VERSION 5.7 ;
BUSBITCHARS "[]" ;
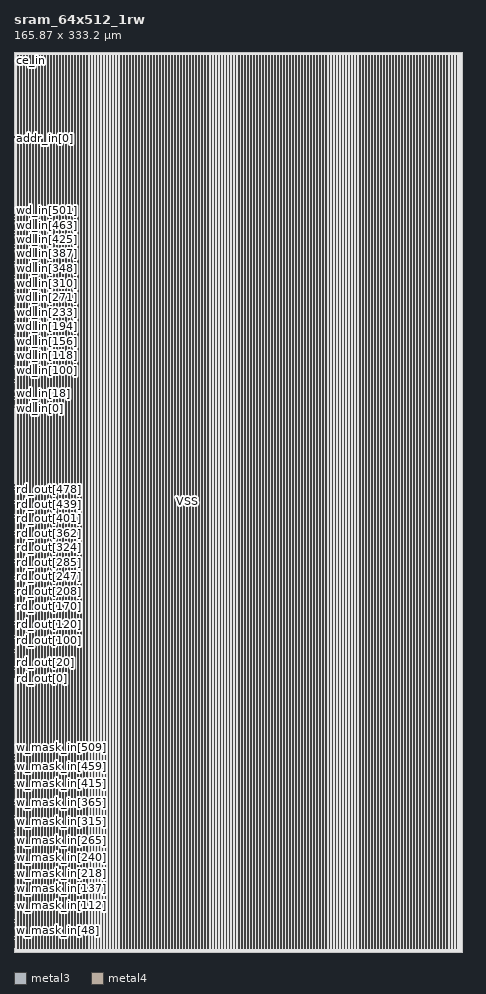
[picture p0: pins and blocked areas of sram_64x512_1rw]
MACRO sram_64x512_1rw
  FOREIGN sram_64x512_1rw 0 0 ;
  SYMMETRY X Y R90 ;
  SIZE 165.870 BY 333.200 ;
  CLASS BLOCK ;
  PIN w_mask_in[0]
    DIRECTION INPUT ;
    USE SIGNAL ;
    SHAPE ABUTMENT ;
    PORT
      LAYER metal3 ;
      RECT 0.000 1.365 0.070 1.435 ;
    END
  END w_mask_in[0]
  PIN w_mask_in[1]
    DIRECTION INPUT ;
    USE SIGNAL ;
    SHAPE ABUTMENT ;
    PORT
      LAYER metal3 ;
      RECT 0.000 1.505 0.070 1.575 ;
    END
  END w_mask_in[1]
  PIN w_mask_in[2]
    DIRECTION INPUT ;
    USE SIGNAL ;
    SHAPE ABUTMENT ;
    PORT
      LAYER metal3 ;
      RECT 0.000 1.645 0.070 1.715 ;
    END
  END w_mask_in[2]
  PIN w_mask_in[3]
    DIRECTION INPUT ;
    USE SIGNAL ;
    SHAPE ABUTMENT ;
    PORT
      LAYER metal3 ;
      RECT 0.000 1.785 0.070 1.855 ;
    END
  END w_mask_in[3]
  PIN w_mask_in[4]
    DIRECTION INPUT ;
    USE SIGNAL ;
    SHAPE ABUTMENT ;
    PORT
      LAYER metal3 ;
      RECT 0.000 1.925 0.070 1.995 ;
    END
  END w_mask_in[4]
  PIN w_mask_in[5]
    DIRECTION INPUT ;
    USE SIGNAL ;
    SHAPE ABUTMENT ;
    PORT
      LAYER metal3 ;
      RECT 0.000 2.065 0.070 2.135 ;
    END
  END w_mask_in[5]
  PIN w_mask_in[6]
    DIRECTION INPUT ;
    USE SIGNAL ;
    SHAPE ABUTMENT ;
    PORT
      LAYER metal3 ;
      RECT 0.000 2.205 0.070 2.275 ;
    END
  END w_mask_in[6]
  PIN w_mask_in[7]
    DIRECTION INPUT ;
    USE SIGNAL ;
    SHAPE ABUTMENT ;
    PORT
      LAYER metal3 ;
      RECT 0.000 2.345 0.070 2.415 ;
    END
  END w_mask_in[7]
  PIN w_mask_in[8]
    DIRECTION INPUT ;
    USE SIGNAL ;
    SHAPE ABUTMENT ;
    PORT
      LAYER metal3 ;
      RECT 0.000 2.485 0.070 2.555 ;
    END
  END w_mask_in[8]
  PIN w_mask_in[9]
    DIRECTION INPUT ;
    USE SIGNAL ;
    SHAPE ABUTMENT ;
    PORT
      LAYER metal3 ;
      RECT 0.000 2.625 0.070 2.695 ;
    END
  END w_mask_in[9]
  PIN w_mask_in[10]
    DIRECTION INPUT ;
    USE SIGNAL ;
    SHAPE ABUTMENT ;
    PORT
      LAYER metal3 ;
      RECT 0.000 2.765 0.070 2.835 ;
    END
  END w_mask_in[10]
  PIN w_mask_in[11]
    DIRECTION INPUT ;
    USE SIGNAL ;
    SHAPE ABUTMENT ;
    PORT
      LAYER metal3 ;
      RECT 0.000 2.905 0.070 2.975 ;
    END
  END w_mask_in[11]
  PIN w_mask_in[12]
    DIRECTION INPUT ;
    USE SIGNAL ;
    SHAPE ABUTMENT ;
    PORT
      LAYER metal3 ;
      RECT 0.000 3.045 0.070 3.115 ;
    END
  END w_mask_in[12]
  PIN w_mask_in[13]
    DIRECTION INPUT ;
    USE SIGNAL ;
    SHAPE ABUTMENT ;
    PORT
      LAYER metal3 ;
      RECT 0.000 3.185 0.070 3.255 ;
    END
  END w_mask_in[13]
  PIN w_mask_in[14]
    DIRECTION INPUT ;
    USE SIGNAL ;
    SHAPE ABUTMENT ;
    PORT
      LAYER metal3 ;
      RECT 0.000 3.325 0.070 3.395 ;
    END
  END w_mask_in[14]
  PIN w_mask_in[15]
    DIRECTION INPUT ;
    USE SIGNAL ;
    SHAPE ABUTMENT ;
    PORT
      LAYER metal3 ;
      RECT 0.000 3.465 0.070 3.535 ;
    END
  END w_mask_in[15]
  PIN w_mask_in[16]
    DIRECTION INPUT ;
    USE SIGNAL ;
    SHAPE ABUTMENT ;
    PORT
      LAYER metal3 ;
      RECT 0.000 3.605 0.070 3.675 ;
    END
  END w_mask_in[16]
  PIN w_mask_in[17]
    DIRECTION INPUT ;
    USE SIGNAL ;
    SHAPE ABUTMENT ;
    PORT
      LAYER metal3 ;
      RECT 0.000 3.745 0.070 3.815 ;
    END
  END w_mask_in[17]
  PIN w_mask_in[18]
    DIRECTION INPUT ;
    USE SIGNAL ;
    SHAPE ABUTMENT ;
    PORT
      LAYER metal3 ;
      RECT 0.000 3.885 0.070 3.955 ;
    END
  END w_mask_in[18]
  PIN w_mask_in[19]
    DIRECTION INPUT ;
    USE SIGNAL ;
    SHAPE ABUTMENT ;
    PORT
      LAYER metal3 ;
      RECT 0.000 4.025 0.070 4.095 ;
    END
  END w_mask_in[19]
  PIN w_mask_in[20]
    DIRECTION INPUT ;
    USE SIGNAL ;
    SHAPE ABUTMENT ;
    PORT
      LAYER metal3 ;
      RECT 0.000 4.165 0.070 4.235 ;
    END
  END w_mask_in[20]
  PIN w_mask_in[21]
    DIRECTION INPUT ;
    USE SIGNAL ;
    SHAPE ABUTMENT ;
    PORT
      LAYER metal3 ;
      RECT 0.000 4.305 0.070 4.375 ;
    END
  END w_mask_in[21]
  PIN w_mask_in[22]
    DIRECTION INPUT ;
    USE SIGNAL ;
    SHAPE ABUTMENT ;
    PORT
      LAYER metal3 ;
      RECT 0.000 4.445 0.070 4.515 ;
    END
  END w_mask_in[22]
  PIN w_mask_in[23]
    DIRECTION INPUT ;
    USE SIGNAL ;
    SHAPE ABUTMENT ;
    PORT
      LAYER metal3 ;
      RECT 0.000 4.585 0.070 4.655 ;
    END
  END w_mask_in[23]
  PIN w_mask_in[24]
    DIRECTION INPUT ;
    USE SIGNAL ;
    SHAPE ABUTMENT ;
    PORT
      LAYER metal3 ;
      RECT 0.000 4.725 0.070 4.795 ;
    END
  END w_mask_in[24]
  PIN w_mask_in[25]
    DIRECTION INPUT ;
    USE SIGNAL ;
    SHAPE ABUTMENT ;
    PORT
      LAYER metal3 ;
      RECT 0.000 4.865 0.070 4.935 ;
    END
  END w_mask_in[25]
  PIN w_mask_in[26]
    DIRECTION INPUT ;
    USE SIGNAL ;
    SHAPE ABUTMENT ;
    PORT
      LAYER metal3 ;
      RECT 0.000 5.005 0.070 5.075 ;
    END
  END w_mask_in[26]
  PIN w_mask_in[27]
    DIRECTION INPUT ;
    USE SIGNAL ;
    SHAPE ABUTMENT ;
    PORT
      LAYER metal3 ;
      RECT 0.000 5.145 0.070 5.215 ;
    END
  END w_mask_in[27]
  PIN w_mask_in[28]
    DIRECTION INPUT ;
    USE SIGNAL ;
    SHAPE ABUTMENT ;
    PORT
      LAYER metal3 ;
      RECT 0.000 5.285 0.070 5.355 ;
    END
  END w_mask_in[28]
  PIN w_mask_in[29]
    DIRECTION INPUT ;
    USE SIGNAL ;
    SHAPE ABUTMENT ;
    PORT
      LAYER metal3 ;
      RECT 0.000 5.425 0.070 5.495 ;
    END
  END w_mask_in[29]
  PIN w_mask_in[30]
    DIRECTION INPUT ;
    USE SIGNAL ;
    SHAPE ABUTMENT ;
    PORT
      LAYER metal3 ;
      RECT 0.000 5.565 0.070 5.635 ;
    END
  END w_mask_in[30]
  PIN w_mask_in[31]
    DIRECTION INPUT ;
    USE SIGNAL ;
    SHAPE ABUTMENT ;
    PORT
      LAYER metal3 ;
      RECT 0.000 5.705 0.070 5.775 ;
    END
  END w_mask_in[31]
  PIN w_mask_in[32]
    DIRECTION INPUT ;
    USE SIGNAL ;
    SHAPE ABUTMENT ;
    PORT
      LAYER metal3 ;
      RECT 0.000 5.845 0.070 5.915 ;
    END
  END w_mask_in[32]
  PIN w_mask_in[33]
    DIRECTION INPUT ;
    USE SIGNAL ;
    SHAPE ABUTMENT ;
    PORT
      LAYER metal3 ;
      RECT 0.000 5.985 0.070 6.055 ;
    END
  END w_mask_in[33]
  PIN w_mask_in[34]
    DIRECTION INPUT ;
    USE SIGNAL ;
    SHAPE ABUTMENT ;
    PORT
      LAYER metal3 ;
      RECT 0.000 6.125 0.070 6.195 ;
    END
  END w_mask_in[34]
  PIN w_mask_in[35]
    DIRECTION INPUT ;
    USE SIGNAL ;
    SHAPE ABUTMENT ;
    PORT
      LAYER metal3 ;
      RECT 0.000 6.265 0.070 6.335 ;
    END
  END w_mask_in[35]
  PIN w_mask_in[36]
    DIRECTION INPUT ;
    USE SIGNAL ;
    SHAPE ABUTMENT ;
    PORT
      LAYER metal3 ;
      RECT 0.000 6.405 0.070 6.475 ;
    END
  END w_mask_in[36]
  PIN w_mask_in[37]
    DIRECTION INPUT ;
    USE SIGNAL ;
    SHAPE ABUTMENT ;
    PORT
      LAYER metal3 ;
      RECT 0.000 6.545 0.070 6.615 ;
    END
  END w_mask_in[37]
  PIN w_mask_in[38]
    DIRECTION INPUT ;
    USE SIGNAL ;
    SHAPE ABUTMENT ;
    PORT
      LAYER metal3 ;
      RECT 0.000 6.685 0.070 6.755 ;
    END
  END w_mask_in[38]
  PIN w_mask_in[39]
    DIRECTION INPUT ;
    USE SIGNAL ;
    SHAPE ABUTMENT ;
    PORT
      LAYER metal3 ;
      RECT 0.000 6.825 0.070 6.895 ;
    END
  END w_mask_in[39]
  PIN w_mask_in[40]
    DIRECTION INPUT ;
    USE SIGNAL ;
    SHAPE ABUTMENT ;
    PORT
      LAYER metal3 ;
      RECT 0.000 6.965 0.070 7.035 ;
    END
  END w_mask_in[40]
  PIN w_mask_in[41]
    DIRECTION INPUT ;
    USE SIGNAL ;
    SHAPE ABUTMENT ;
    PORT
      LAYER metal3 ;
      RECT 0.000 7.105 0.070 7.175 ;
    END
  END w_mask_in[41]
  PIN w_mask_in[42]
    DIRECTION INPUT ;
    USE SIGNAL ;
    SHAPE ABUTMENT ;
    PORT
      LAYER metal3 ;
      RECT 0.000 7.245 0.070 7.315 ;
    END
  END w_mask_in[42]
  PIN w_mask_in[43]
    DIRECTION INPUT ;
    USE SIGNAL ;
    SHAPE ABUTMENT ;
    PORT
      LAYER metal3 ;
      RECT 0.000 7.385 0.070 7.455 ;
    END
  END w_mask_in[43]
  PIN w_mask_in[44]
    DIRECTION INPUT ;
    USE SIGNAL ;
    SHAPE ABUTMENT ;
    PORT
      LAYER metal3 ;
      RECT 0.000 7.525 0.070 7.595 ;
    END
  END w_mask_in[44]
  PIN w_mask_in[45]
    DIRECTION INPUT ;
    USE SIGNAL ;
    SHAPE ABUTMENT ;
    PORT
      LAYER metal3 ;
      RECT 0.000 7.665 0.070 7.735 ;
    END
  END w_mask_in[45]
  PIN w_mask_in[46]
    DIRECTION INPUT ;
    USE SIGNAL ;
    SHAPE ABUTMENT ;
    PORT
      LAYER metal3 ;
      RECT 0.000 7.805 0.070 7.875 ;
    END
  END w_mask_in[46]
  PIN w_mask_in[47]
    DIRECTION INPUT ;
    USE SIGNAL ;
    SHAPE ABUTMENT ;
    PORT
      LAYER metal3 ;
      RECT 0.000 7.945 0.070 8.015 ;
    END
  END w_mask_in[47]
  PIN w_mask_in[48]
    DIRECTION INPUT ;
    USE SIGNAL ;
    SHAPE ABUTMENT ;
    PORT
      LAYER metal3 ;
      RECT 0.000 8.085 0.070 8.155 ;
    END
  END w_mask_in[48]
  PIN w_mask_in[49]
    DIRECTION INPUT ;
    USE SIGNAL ;
    SHAPE ABUTMENT ;
    PORT
      LAYER metal3 ;
      RECT 0.000 8.225 0.070 8.295 ;
    END
  END w_mask_in[49]
  PIN w_mask_in[50]
    DIRECTION INPUT ;
    USE SIGNAL ;
    SHAPE ABUTMENT ;
    PORT
      LAYER metal3 ;
      RECT 0.000 8.365 0.070 8.435 ;
    END
  END w_mask_in[50]
  PIN w_mask_in[51]
    DIRECTION INPUT ;
    USE SIGNAL ;
    SHAPE ABUTMENT ;
    PORT
      LAYER metal3 ;
      RECT 0.000 8.505 0.070 8.575 ;
    END
  END w_mask_in[51]
  PIN w_mask_in[52]
    DIRECTION INPUT ;
    USE SIGNAL ;
    SHAPE ABUTMENT ;
    PORT
      LAYER metal3 ;
      RECT 0.000 8.645 0.070 8.715 ;
    END
  END w_mask_in[52]
  PIN w_mask_in[53]
    DIRECTION INPUT ;
    USE SIGNAL ;
    SHAPE ABUTMENT ;
    PORT
      LAYER metal3 ;
      RECT 0.000 8.785 0.070 8.855 ;
    END
  END w_mask_in[53]
  PIN w_mask_in[54]
    DIRECTION INPUT ;
    USE SIGNAL ;
    SHAPE ABUTMENT ;
    PORT
      LAYER metal3 ;
      RECT 0.000 8.925 0.070 8.995 ;
    END
  END w_mask_in[54]
  PIN w_mask_in[55]
    DIRECTION INPUT ;
    USE SIGNAL ;
    SHAPE ABUTMENT ;
    PORT
      LAYER metal3 ;
      RECT 0.000 9.065 0.070 9.135 ;
    END
  END w_mask_in[55]
  PIN w_mask_in[56]
    DIRECTION INPUT ;
    USE SIGNAL ;
    SHAPE ABUTMENT ;
    PORT
      LAYER metal3 ;
      RECT 0.000 9.205 0.070 9.275 ;
    END
  END w_mask_in[56]
  PIN w_mask_in[57]
    DIRECTION INPUT ;
    USE SIGNAL ;
    SHAPE ABUTMENT ;
    PORT
      LAYER metal3 ;
      RECT 0.000 9.345 0.070 9.415 ;
    END
  END w_mask_in[57]
  PIN w_mask_in[58]
    DIRECTION INPUT ;
    USE SIGNAL ;
    SHAPE ABUTMENT ;
    PORT
      LAYER metal3 ;
      RECT 0.000 9.485 0.070 9.555 ;
    END
  END w_mask_in[58]
  PIN w_mask_in[59]
    DIRECTION INPUT ;
    USE SIGNAL ;
    SHAPE ABUTMENT ;
    PORT
      LAYER metal3 ;
      RECT 0.000 9.625 0.070 9.695 ;
    END
  END w_mask_in[59]
  PIN w_mask_in[60]
    DIRECTION INPUT ;
    USE SIGNAL ;
    SHAPE ABUTMENT ;
    PORT
      LAYER metal3 ;
      RECT 0.000 9.765 0.070 9.835 ;
    END
  END w_mask_in[60]
  PIN w_mask_in[61]
    DIRECTION INPUT ;
    USE SIGNAL ;
    SHAPE ABUTMENT ;
    PORT
      LAYER metal3 ;
      RECT 0.000 9.905 0.070 9.975 ;
    END
  END w_mask_in[61]
  PIN w_mask_in[62]
    DIRECTION INPUT ;
    USE SIGNAL ;
    SHAPE ABUTMENT ;
    PORT
      LAYER metal3 ;
      RECT 0.000 10.045 0.070 10.115 ;
    END
  END w_mask_in[62]
  PIN w_mask_in[63]
    DIRECTION INPUT ;
    USE SIGNAL ;
    SHAPE ABUTMENT ;
    PORT
      LAYER metal3 ;
      RECT 0.000 10.185 0.070 10.255 ;
    END
  END w_mask_in[63]
  PIN w_mask_in[64]
    DIRECTION INPUT ;
    USE SIGNAL ;
    SHAPE ABUTMENT ;
    PORT
      LAYER metal3 ;
      RECT 0.000 10.325 0.070 10.395 ;
    END
  END w_mask_in[64]
  PIN w_mask_in[65]
    DIRECTION INPUT ;
    USE SIGNAL ;
    SHAPE ABUTMENT ;
    PORT
      LAYER metal3 ;
      RECT 0.000 10.465 0.070 10.535 ;
    END
  END w_mask_in[65]
  PIN w_mask_in[66]
    DIRECTION INPUT ;
    USE SIGNAL ;
    SHAPE ABUTMENT ;
    PORT
      LAYER metal3 ;
      RECT 0.000 10.605 0.070 10.675 ;
    END
  END w_mask_in[66]
  PIN w_mask_in[67]
    DIRECTION INPUT ;
    USE SIGNAL ;
    SHAPE ABUTMENT ;
    PORT
      LAYER metal3 ;
      RECT 0.000 10.745 0.070 10.815 ;
    END
  END w_mask_in[67]
  PIN w_mask_in[68]
    DIRECTION INPUT ;
    USE SIGNAL ;
    SHAPE ABUTMENT ;
    PORT
      LAYER metal3 ;
      RECT 0.000 10.885 0.070 10.955 ;
    END
  END w_mask_in[68]
  PIN w_mask_in[69]
    DIRECTION INPUT ;
    USE SIGNAL ;
    SHAPE ABUTMENT ;
    PORT
      LAYER metal3 ;
      RECT 0.000 11.025 0.070 11.095 ;
    END
  END w_mask_in[69]
  PIN w_mask_in[70]
    DIRECTION INPUT ;
    USE SIGNAL ;
    SHAPE ABUTMENT ;
    PORT
      LAYER metal3 ;
      RECT 0.000 11.165 0.070 11.235 ;
    END
  END w_mask_in[70]
  PIN w_mask_in[71]
    DIRECTION INPUT ;
    USE SIGNAL ;
    SHAPE ABUTMENT ;
    PORT
      LAYER metal3 ;
      RECT 0.000 11.305 0.070 11.375 ;
    END
  END w_mask_in[71]
  PIN w_mask_in[72]
    DIRECTION INPUT ;
    USE SIGNAL ;
    SHAPE ABUTMENT ;
    PORT
      LAYER metal3 ;
      RECT 0.000 11.445 0.070 11.515 ;
    END
  END w_mask_in[72]
  PIN w_mask_in[73]
    DIRECTION INPUT ;
    USE SIGNAL ;
    SHAPE ABUTMENT ;
    PORT
      LAYER metal3 ;
      RECT 0.000 11.585 0.070 11.655 ;
    END
  END w_mask_in[73]
  PIN w_mask_in[74]
    DIRECTION INPUT ;
    USE SIGNAL ;
    SHAPE ABUTMENT ;
    PORT
      LAYER metal3 ;
      RECT 0.000 11.725 0.070 11.795 ;
    END
  END w_mask_in[74]
  PIN w_mask_in[75]
    DIRECTION INPUT ;
    USE SIGNAL ;
    SHAPE ABUTMENT ;
    PORT
      LAYER metal3 ;
      RECT 0.000 11.865 0.070 11.935 ;
    END
  END w_mask_in[75]
  PIN w_mask_in[76]
    DIRECTION INPUT ;
    USE SIGNAL ;
    SHAPE ABUTMENT ;
    PORT
      LAYER metal3 ;
      RECT 0.000 12.005 0.070 12.075 ;
    END
  END w_mask_in[76]
  PIN w_mask_in[77]
    DIRECTION INPUT ;
    USE SIGNAL ;
    SHAPE ABUTMENT ;
    PORT
      LAYER metal3 ;
      RECT 0.000 12.145 0.070 12.215 ;
    END
  END w_mask_in[77]
  PIN w_mask_in[78]
    DIRECTION INPUT ;
    USE SIGNAL ;
    SHAPE ABUTMENT ;
    PORT
      LAYER metal3 ;
      RECT 0.000 12.285 0.070 12.355 ;
    END
  END w_mask_in[78]
  PIN w_mask_in[79]
    DIRECTION INPUT ;
    USE SIGNAL ;
    SHAPE ABUTMENT ;
    PORT
      LAYER metal3 ;
      RECT 0.000 12.425 0.070 12.495 ;
    END
  END w_mask_in[79]
  PIN w_mask_in[80]
    DIRECTION INPUT ;
    USE SIGNAL ;
    SHAPE ABUTMENT ;
    PORT
      LAYER metal3 ;
      RECT 0.000 12.565 0.070 12.635 ;
    END
  END w_mask_in[80]
  PIN w_mask_in[81]
    DIRECTION INPUT ;
    USE SIGNAL ;
    SHAPE ABUTMENT ;
    PORT
      LAYER metal3 ;
      RECT 0.000 12.705 0.070 12.775 ;
    END
  END w_mask_in[81]
  PIN w_mask_in[82]
    DIRECTION INPUT ;
    USE SIGNAL ;
    SHAPE ABUTMENT ;
    PORT
      LAYER metal3 ;
      RECT 0.000 12.845 0.070 12.915 ;
    END
  END w_mask_in[82]
  PIN w_mask_in[83]
    DIRECTION INPUT ;
    USE SIGNAL ;
    SHAPE ABUTMENT ;
    PORT
      LAYER metal3 ;
      RECT 0.000 12.985 0.070 13.055 ;
    END
  END w_mask_in[83]
  PIN w_mask_in[84]
    DIRECTION INPUT ;
    USE SIGNAL ;
    SHAPE ABUTMENT ;
    PORT
      LAYER metal3 ;
      RECT 0.000 13.125 0.070 13.195 ;
    END
  END w_mask_in[84]
  PIN w_mask_in[85]
    DIRECTION INPUT ;
    USE SIGNAL ;
    SHAPE ABUTMENT ;
    PORT
      LAYER metal3 ;
      RECT 0.000 13.265 0.070 13.335 ;
    END
  END w_mask_in[85]
  PIN w_mask_in[86]
    DIRECTION INPUT ;
    USE SIGNAL ;
    SHAPE ABUTMENT ;
    PORT
      LAYER metal3 ;
      RECT 0.000 13.405 0.070 13.475 ;
    END
  END w_mask_in[86]
  PIN w_mask_in[87]
    DIRECTION INPUT ;
    USE SIGNAL ;
    SHAPE ABUTMENT ;
    PORT
      LAYER metal3 ;
      RECT 0.000 13.545 0.070 13.615 ;
    END
  END w_mask_in[87]
  PIN w_mask_in[88]
    DIRECTION INPUT ;
    USE SIGNAL ;
    SHAPE ABUTMENT ;
    PORT
      LAYER metal3 ;
      RECT 0.000 13.685 0.070 13.755 ;
    END
  END w_mask_in[88]
  PIN w_mask_in[89]
    DIRECTION INPUT ;
    USE SIGNAL ;
    SHAPE ABUTMENT ;
    PORT
      LAYER metal3 ;
      RECT 0.000 13.825 0.070 13.895 ;
    END
  END w_mask_in[89]
  PIN w_mask_in[90]
    DIRECTION INPUT ;
    USE SIGNAL ;
    SHAPE ABUTMENT ;
    PORT
      LAYER metal3 ;
      RECT 0.000 13.965 0.070 14.035 ;
    END
  END w_mask_in[90]
  PIN w_mask_in[91]
    DIRECTION INPUT ;
    USE SIGNAL ;
    SHAPE ABUTMENT ;
    PORT
      LAYER metal3 ;
      RECT 0.000 14.105 0.070 14.175 ;
    END
  END w_mask_in[91]
  PIN w_mask_in[92]
    DIRECTION INPUT ;
    USE SIGNAL ;
    SHAPE ABUTMENT ;
    PORT
      LAYER metal3 ;
      RECT 0.000 14.245 0.070 14.315 ;
    END
  END w_mask_in[92]
  PIN w_mask_in[93]
    DIRECTION INPUT ;
    USE SIGNAL ;
    SHAPE ABUTMENT ;
    PORT
      LAYER metal3 ;
      RECT 0.000 14.385 0.070 14.455 ;
    END
  END w_mask_in[93]
  PIN w_mask_in[94]
    DIRECTION INPUT ;
    USE SIGNAL ;
    SHAPE ABUTMENT ;
    PORT
      LAYER metal3 ;
      RECT 0.000 14.525 0.070 14.595 ;
    END
  END w_mask_in[94]
  PIN w_mask_in[95]
    DIRECTION INPUT ;
    USE SIGNAL ;
    SHAPE ABUTMENT ;
    PORT
      LAYER metal3 ;
      RECT 0.000 14.665 0.070 14.735 ;
    END
  END w_mask_in[95]
  PIN w_mask_in[96]
    DIRECTION INPUT ;
    USE SIGNAL ;
    SHAPE ABUTMENT ;
    PORT
      LAYER metal3 ;
      RECT 0.000 14.805 0.070 14.875 ;
    END
  END w_mask_in[96]
  PIN w_mask_in[97]
    DIRECTION INPUT ;
    USE SIGNAL ;
    SHAPE ABUTMENT ;
    PORT
      LAYER metal3 ;
      RECT 0.000 14.945 0.070 15.015 ;
    END
  END w_mask_in[97]
  PIN w_mask_in[98]
    DIRECTION INPUT ;
    USE SIGNAL ;
    SHAPE ABUTMENT ;
    PORT
      LAYER metal3 ;
      RECT 0.000 15.085 0.070 15.155 ;
    END
  END w_mask_in[98]
  PIN w_mask_in[99]
    DIRECTION INPUT ;
    USE SIGNAL ;
    SHAPE ABUTMENT ;
    PORT
      LAYER metal3 ;
      RECT 0.000 15.225 0.070 15.295 ;
    END
  END w_mask_in[99]
  PIN w_mask_in[100]
    DIRECTION INPUT ;
    USE SIGNAL ;
    SHAPE ABUTMENT ;
    PORT
      LAYER metal3 ;
      RECT 0.000 15.365 0.070 15.435 ;
    END
  END w_mask_in[100]
  PIN w_mask_in[101]
    DIRECTION INPUT ;
    USE SIGNAL ;
    SHAPE ABUTMENT ;
    PORT
      LAYER metal3 ;
      RECT 0.000 15.505 0.070 15.575 ;
    END
  END w_mask_in[101]
  PIN w_mask_in[102]
    DIRECTION INPUT ;
    USE SIGNAL ;
    SHAPE ABUTMENT ;
    PORT
      LAYER metal3 ;
      RECT 0.000 15.645 0.070 15.715 ;
    END
  END w_mask_in[102]
  PIN w_mask_in[103]
    DIRECTION INPUT ;
    USE SIGNAL ;
    SHAPE ABUTMENT ;
    PORT
      LAYER metal3 ;
      RECT 0.000 15.785 0.070 15.855 ;
    END
  END w_mask_in[103]
  PIN w_mask_in[104]
    DIRECTION INPUT ;
    USE SIGNAL ;
    SHAPE ABUTMENT ;
    PORT
      LAYER metal3 ;
      RECT 0.000 15.925 0.070 15.995 ;
    END
  END w_mask_in[104]
  PIN w_mask_in[105]
    DIRECTION INPUT ;
    USE SIGNAL ;
    SHAPE ABUTMENT ;
    PORT
      LAYER metal3 ;
      RECT 0.000 16.065 0.070 16.135 ;
    END
  END w_mask_in[105]
  PIN w_mask_in[106]
    DIRECTION INPUT ;
    USE SIGNAL ;
    SHAPE ABUTMENT ;
    PORT
      LAYER metal3 ;
      RECT 0.000 16.205 0.070 16.275 ;
    END
  END w_mask_in[106]
  PIN w_mask_in[107]
    DIRECTION INPUT ;
    USE SIGNAL ;
    SHAPE ABUTMENT ;
    PORT
      LAYER metal3 ;
      RECT 0.000 16.345 0.070 16.415 ;
    END
  END w_mask_in[107]
  PIN w_mask_in[108]
    DIRECTION INPUT ;
    USE SIGNAL ;
    SHAPE ABUTMENT ;
    PORT
      LAYER metal3 ;
      RECT 0.000 16.485 0.070 16.555 ;
    END
  END w_mask_in[108]
  PIN w_mask_in[109]
    DIRECTION INPUT ;
    USE SIGNAL ;
    SHAPE ABUTMENT ;
    PORT
      LAYER metal3 ;
      RECT 0.000 16.625 0.070 16.695 ;
    END
  END w_mask_in[109]
  PIN w_mask_in[110]
    DIRECTION INPUT ;
    USE SIGNAL ;
    SHAPE ABUTMENT ;
    PORT
      LAYER metal3 ;
      RECT 0.000 16.765 0.070 16.835 ;
    END
  END w_mask_in[110]
  PIN w_mask_in[111]
    DIRECTION INPUT ;
    USE SIGNAL ;
    SHAPE ABUTMENT ;
    PORT
      LAYER metal3 ;
      RECT 0.000 16.905 0.070 16.975 ;
    END
  END w_mask_in[111]
  PIN w_mask_in[112]
    DIRECTION INPUT ;
    USE SIGNAL ;
    SHAPE ABUTMENT ;
    PORT
      LAYER metal3 ;
      RECT 0.000 17.045 0.070 17.115 ;
    END
  END w_mask_in[112]
  PIN w_mask_in[113]
    DIRECTION INPUT ;
    USE SIGNAL ;
    SHAPE ABUTMENT ;
    PORT
      LAYER metal3 ;
      RECT 0.000 17.185 0.070 17.255 ;
    END
  END w_mask_in[113]
  PIN w_mask_in[114]
    DIRECTION INPUT ;
    USE SIGNAL ;
    SHAPE ABUTMENT ;
    PORT
      LAYER metal3 ;
      RECT 0.000 17.325 0.070 17.395 ;
    END
  END w_mask_in[114]
  PIN w_mask_in[115]
    DIRECTION INPUT ;
    USE SIGNAL ;
    SHAPE ABUTMENT ;
    PORT
      LAYER metal3 ;
      RECT 0.000 17.465 0.070 17.535 ;
    END
  END w_mask_in[115]
  PIN w_mask_in[116]
    DIRECTION INPUT ;
    USE SIGNAL ;
    SHAPE ABUTMENT ;
    PORT
      LAYER metal3 ;
      RECT 0.000 17.605 0.070 17.675 ;
    END
  END w_mask_in[116]
  PIN w_mask_in[117]
    DIRECTION INPUT ;
    USE SIGNAL ;
    SHAPE ABUTMENT ;
    PORT
      LAYER metal3 ;
      RECT 0.000 17.745 0.070 17.815 ;
    END
  END w_mask_in[117]
  PIN w_mask_in[118]
    DIRECTION INPUT ;
    USE SIGNAL ;
    SHAPE ABUTMENT ;
    PORT
      LAYER metal3 ;
      RECT 0.000 17.885 0.070 17.955 ;
    END
  END w_mask_in[118]
  PIN w_mask_in[119]
    DIRECTION INPUT ;
    USE SIGNAL ;
    SHAPE ABUTMENT ;
    PORT
      LAYER metal3 ;
      RECT 0.000 18.025 0.070 18.095 ;
    END
  END w_mask_in[119]
  PIN w_mask_in[120]
    DIRECTION INPUT ;
    USE SIGNAL ;
    SHAPE ABUTMENT ;
    PORT
      LAYER metal3 ;
      RECT 0.000 18.165 0.070 18.235 ;
    END
  END w_mask_in[120]
  PIN w_mask_in[121]
    DIRECTION INPUT ;
    USE SIGNAL ;
    SHAPE ABUTMENT ;
    PORT
      LAYER metal3 ;
      RECT 0.000 18.305 0.070 18.375 ;
    END
  END w_mask_in[121]
  PIN w_mask_in[122]
    DIRECTION INPUT ;
    USE SIGNAL ;
    SHAPE ABUTMENT ;
    PORT
      LAYER metal3 ;
      RECT 0.000 18.445 0.070 18.515 ;
    END
  END w_mask_in[122]
  PIN w_mask_in[123]
    DIRECTION INPUT ;
    USE SIGNAL ;
    SHAPE ABUTMENT ;
    PORT
      LAYER metal3 ;
      RECT 0.000 18.585 0.070 18.655 ;
    END
  END w_mask_in[123]
  PIN w_mask_in[124]
    DIRECTION INPUT ;
    USE SIGNAL ;
    SHAPE ABUTMENT ;
    PORT
      LAYER metal3 ;
      RECT 0.000 18.725 0.070 18.795 ;
    END
  END w_mask_in[124]
  PIN w_mask_in[125]
    DIRECTION INPUT ;
    USE SIGNAL ;
    SHAPE ABUTMENT ;
    PORT
      LAYER metal3 ;
      RECT 0.000 18.865 0.070 18.935 ;
    END
  END w_mask_in[125]
  PIN w_mask_in[126]
    DIRECTION INPUT ;
    USE SIGNAL ;
    SHAPE ABUTMENT ;
    PORT
      LAYER metal3 ;
      RECT 0.000 19.005 0.070 19.075 ;
    END
  END w_mask_in[126]
  PIN w_mask_in[127]
    DIRECTION INPUT ;
    USE SIGNAL ;
    SHAPE ABUTMENT ;
    PORT
      LAYER metal3 ;
      RECT 0.000 19.145 0.070 19.215 ;
    END
  END w_mask_in[127]
  PIN w_mask_in[128]
    DIRECTION INPUT ;
    USE SIGNAL ;
    SHAPE ABUTMENT ;
    PORT
      LAYER metal3 ;
      RECT 0.000 19.285 0.070 19.355 ;
    END
  END w_mask_in[128]
  PIN w_mask_in[129]
    DIRECTION INPUT ;
    USE SIGNAL ;
    SHAPE ABUTMENT ;
    PORT
      LAYER metal3 ;
      RECT 0.000 19.425 0.070 19.495 ;
    END
  END w_mask_in[129]
  PIN w_mask_in[130]
    DIRECTION INPUT ;
    USE SIGNAL ;
    SHAPE ABUTMENT ;
    PORT
      LAYER metal3 ;
      RECT 0.000 19.565 0.070 19.635 ;
    END
  END w_mask_in[130]
  PIN w_mask_in[131]
    DIRECTION INPUT ;
    USE SIGNAL ;
    SHAPE ABUTMENT ;
    PORT
      LAYER metal3 ;
      RECT 0.000 19.705 0.070 19.775 ;
    END
  END w_mask_in[131]
  PIN w_mask_in[132]
    DIRECTION INPUT ;
    USE SIGNAL ;
    SHAPE ABUTMENT ;
    PORT
      LAYER metal3 ;
      RECT 0.000 19.845 0.070 19.915 ;
    END
  END w_mask_in[132]
  PIN w_mask_in[133]
    DIRECTION INPUT ;
    USE SIGNAL ;
    SHAPE ABUTMENT ;
    PORT
      LAYER metal3 ;
      RECT 0.000 19.985 0.070 20.055 ;
    END
  END w_mask_in[133]
  PIN w_mask_in[134]
    DIRECTION INPUT ;
    USE SIGNAL ;
    SHAPE ABUTMENT ;
    PORT
      LAYER metal3 ;
      RECT 0.000 20.125 0.070 20.195 ;
    END
  END w_mask_in[134]
  PIN w_mask_in[135]
    DIRECTION INPUT ;
    USE SIGNAL ;
    SHAPE ABUTMENT ;
    PORT
      LAYER metal3 ;
      RECT 0.000 20.265 0.070 20.335 ;
    END
  END w_mask_in[135]
  PIN w_mask_in[136]
    DIRECTION INPUT ;
    USE SIGNAL ;
    SHAPE ABUTMENT ;
    PORT
      LAYER metal3 ;
      RECT 0.000 20.405 0.070 20.475 ;
    END
  END w_mask_in[136]
  PIN w_mask_in[137]
    DIRECTION INPUT ;
    USE SIGNAL ;
    SHAPE ABUTMENT ;
    PORT
      LAYER metal3 ;
      RECT 0.000 20.545 0.070 20.615 ;
    END
  END w_mask_in[137]
  PIN w_mask_in[138]
    DIRECTION INPUT ;
    USE SIGNAL ;
    SHAPE ABUTMENT ;
    PORT
      LAYER metal3 ;
      RECT 0.000 20.685 0.070 20.755 ;
    END
  END w_mask_in[138]
  PIN w_mask_in[139]
    DIRECTION INPUT ;
    USE SIGNAL ;
    SHAPE ABUTMENT ;
    PORT
      LAYER metal3 ;
      RECT 0.000 20.825 0.070 20.895 ;
    END
  END w_mask_in[139]
  PIN w_mask_in[140]
    DIRECTION INPUT ;
    USE SIGNAL ;
    SHAPE ABUTMENT ;
    PORT
      LAYER metal3 ;
      RECT 0.000 20.965 0.070 21.035 ;
    END
  END w_mask_in[140]
  PIN w_mask_in[141]
    DIRECTION INPUT ;
    USE SIGNAL ;
    SHAPE ABUTMENT ;
    PORT
      LAYER metal3 ;
      RECT 0.000 21.105 0.070 21.175 ;
    END
  END w_mask_in[141]
  PIN w_mask_in[142]
    DIRECTION INPUT ;
    USE SIGNAL ;
    SHAPE ABUTMENT ;
    PORT
      LAYER metal3 ;
      RECT 0.000 21.245 0.070 21.315 ;
    END
  END w_mask_in[142]
  PIN w_mask_in[143]
    DIRECTION INPUT ;
    USE SIGNAL ;
    SHAPE ABUTMENT ;
    PORT
      LAYER metal3 ;
      RECT 0.000 21.385 0.070 21.455 ;
    END
  END w_mask_in[143]
  PIN w_mask_in[144]
    DIRECTION INPUT ;
    USE SIGNAL ;
    SHAPE ABUTMENT ;
    PORT
      LAYER metal3 ;
      RECT 0.000 21.525 0.070 21.595 ;
    END
  END w_mask_in[144]
  PIN w_mask_in[145]
    DIRECTION INPUT ;
    USE SIGNAL ;
    SHAPE ABUTMENT ;
    PORT
      LAYER metal3 ;
      RECT 0.000 21.665 0.070 21.735 ;
    END
  END w_mask_in[145]
  PIN w_mask_in[146]
    DIRECTION INPUT ;
    USE SIGNAL ;
    SHAPE ABUTMENT ;
    PORT
      LAYER metal3 ;
      RECT 0.000 21.805 0.070 21.875 ;
    END
  END w_mask_in[146]
  PIN w_mask_in[147]
    DIRECTION INPUT ;
    USE SIGNAL ;
    SHAPE ABUTMENT ;
    PORT
      LAYER metal3 ;
      RECT 0.000 21.945 0.070 22.015 ;
    END
  END w_mask_in[147]
  PIN w_mask_in[148]
    DIRECTION INPUT ;
    USE SIGNAL ;
    SHAPE ABUTMENT ;
    PORT
      LAYER metal3 ;
      RECT 0.000 22.085 0.070 22.155 ;
    END
  END w_mask_in[148]
  PIN w_mask_in[149]
    DIRECTION INPUT ;
    USE SIGNAL ;
    SHAPE ABUTMENT ;
    PORT
      LAYER metal3 ;
      RECT 0.000 22.225 0.070 22.295 ;
    END
  END w_mask_in[149]
  PIN w_mask_in[150]
    DIRECTION INPUT ;
    USE SIGNAL ;
    SHAPE ABUTMENT ;
    PORT
      LAYER metal3 ;
      RECT 0.000 22.365 0.070 22.435 ;
    END
  END w_mask_in[150]
  PIN w_mask_in[151]
    DIRECTION INPUT ;
    USE SIGNAL ;
    SHAPE ABUTMENT ;
    PORT
      LAYER metal3 ;
      RECT 0.000 22.505 0.070 22.575 ;
    END
  END w_mask_in[151]
  PIN w_mask_in[152]
    DIRECTION INPUT ;
    USE SIGNAL ;
    SHAPE ABUTMENT ;
    PORT
      LAYER metal3 ;
      RECT 0.000 22.645 0.070 22.715 ;
    END
  END w_mask_in[152]
  PIN w_mask_in[153]
    DIRECTION INPUT ;
    USE SIGNAL ;
    SHAPE ABUTMENT ;
    PORT
      LAYER metal3 ;
      RECT 0.000 22.785 0.070 22.855 ;
    END
  END w_mask_in[153]
  PIN w_mask_in[154]
    DIRECTION INPUT ;
    USE SIGNAL ;
    SHAPE ABUTMENT ;
    PORT
      LAYER metal3 ;
      RECT 0.000 22.925 0.070 22.995 ;
    END
  END w_mask_in[154]
  PIN w_mask_in[155]
    DIRECTION INPUT ;
    USE SIGNAL ;
    SHAPE ABUTMENT ;
    PORT
      LAYER metal3 ;
      RECT 0.000 23.065 0.070 23.135 ;
    END
  END w_mask_in[155]
  PIN w_mask_in[156]
    DIRECTION INPUT ;
    USE SIGNAL ;
    SHAPE ABUTMENT ;
    PORT
      LAYER metal3 ;
      RECT 0.000 23.205 0.070 23.275 ;
    END
  END w_mask_in[156]
  PIN w_mask_in[157]
    DIRECTION INPUT ;
    USE SIGNAL ;
    SHAPE ABUTMENT ;
    PORT
      LAYER metal3 ;
      RECT 0.000 23.345 0.070 23.415 ;
    END
  END w_mask_in[157]
  PIN w_mask_in[158]
    DIRECTION INPUT ;
    USE SIGNAL ;
    SHAPE ABUTMENT ;
    PORT
      LAYER metal3 ;
      RECT 0.000 23.485 0.070 23.555 ;
    END
  END w_mask_in[158]
  PIN w_mask_in[159]
    DIRECTION INPUT ;
    USE SIGNAL ;
    SHAPE ABUTMENT ;
    PORT
      LAYER metal3 ;
      RECT 0.000 23.625 0.070 23.695 ;
    END
  END w_mask_in[159]
  PIN w_mask_in[160]
    DIRECTION INPUT ;
    USE SIGNAL ;
    SHAPE ABUTMENT ;
    PORT
      LAYER metal3 ;
      RECT 0.000 23.765 0.070 23.835 ;
    END
  END w_mask_in[160]
  PIN w_mask_in[161]
    DIRECTION INPUT ;
    USE SIGNAL ;
    SHAPE ABUTMENT ;
    PORT
      LAYER metal3 ;
      RECT 0.000 23.905 0.070 23.975 ;
    END
  END w_mask_in[161]
  PIN w_mask_in[162]
    DIRECTION INPUT ;
    USE SIGNAL ;
    SHAPE ABUTMENT ;
    PORT
      LAYER metal3 ;
      RECT 0.000 24.045 0.070 24.115 ;
    END
  END w_mask_in[162]
  PIN w_mask_in[163]
    DIRECTION INPUT ;
    USE SIGNAL ;
    SHAPE ABUTMENT ;
    PORT
      LAYER metal3 ;
      RECT 0.000 24.185 0.070 24.255 ;
    END
  END w_mask_in[163]
  PIN w_mask_in[164]
    DIRECTION INPUT ;
    USE SIGNAL ;
    SHAPE ABUTMENT ;
    PORT
      LAYER metal3 ;
      RECT 0.000 24.325 0.070 24.395 ;
    END
  END w_mask_in[164]
  PIN w_mask_in[165]
    DIRECTION INPUT ;
    USE SIGNAL ;
    SHAPE ABUTMENT ;
    PORT
      LAYER metal3 ;
      RECT 0.000 24.465 0.070 24.535 ;
    END
  END w_mask_in[165]
  PIN w_mask_in[166]
    DIRECTION INPUT ;
    USE SIGNAL ;
    SHAPE ABUTMENT ;
    PORT
      LAYER metal3 ;
      RECT 0.000 24.605 0.070 24.675 ;
    END
  END w_mask_in[166]
  PIN w_mask_in[167]
    DIRECTION INPUT ;
    USE SIGNAL ;
    SHAPE ABUTMENT ;
    PORT
      LAYER metal3 ;
      RECT 0.000 24.745 0.070 24.815 ;
    END
  END w_mask_in[167]
  PIN w_mask_in[168]
    DIRECTION INPUT ;
    USE SIGNAL ;
    SHAPE ABUTMENT ;
    PORT
      LAYER metal3 ;
      RECT 0.000 24.885 0.070 24.955 ;
    END
  END w_mask_in[168]
  PIN w_mask_in[169]
    DIRECTION INPUT ;
    USE SIGNAL ;
    SHAPE ABUTMENT ;
    PORT
      LAYER metal3 ;
      RECT 0.000 25.025 0.070 25.095 ;
    END
  END w_mask_in[169]
  PIN w_mask_in[170]
    DIRECTION INPUT ;
    USE SIGNAL ;
    SHAPE ABUTMENT ;
    PORT
      LAYER metal3 ;
      RECT 0.000 25.165 0.070 25.235 ;
    END
  END w_mask_in[170]
  PIN w_mask_in[171]
    DIRECTION INPUT ;
    USE SIGNAL ;
    SHAPE ABUTMENT ;
    PORT
      LAYER metal3 ;
      RECT 0.000 25.305 0.070 25.375 ;
    END
  END w_mask_in[171]
  PIN w_mask_in[172]
    DIRECTION INPUT ;
    USE SIGNAL ;
    SHAPE ABUTMENT ;
    PORT
      LAYER metal3 ;
      RECT 0.000 25.445 0.070 25.515 ;
    END
  END w_mask_in[172]
  PIN w_mask_in[173]
    DIRECTION INPUT ;
    USE SIGNAL ;
    SHAPE ABUTMENT ;
    PORT
      LAYER metal3 ;
      RECT 0.000 25.585 0.070 25.655 ;
    END
  END w_mask_in[173]
  PIN w_mask_in[174]
    DIRECTION INPUT ;
    USE SIGNAL ;
    SHAPE ABUTMENT ;
    PORT
      LAYER metal3 ;
      RECT 0.000 25.725 0.070 25.795 ;
    END
  END w_mask_in[174]
  PIN w_mask_in[175]
    DIRECTION INPUT ;
    USE SIGNAL ;
    SHAPE ABUTMENT ;
    PORT
      LAYER metal3 ;
      RECT 0.000 25.865 0.070 25.935 ;
    END
  END w_mask_in[175]
  PIN w_mask_in[176]
    DIRECTION INPUT ;
    USE SIGNAL ;
    SHAPE ABUTMENT ;
    PORT
      LAYER metal3 ;
      RECT 0.000 26.005 0.070 26.075 ;
    END
  END w_mask_in[176]
  PIN w_mask_in[177]
    DIRECTION INPUT ;
    USE SIGNAL ;
    SHAPE ABUTMENT ;
    PORT
      LAYER metal3 ;
      RECT 0.000 26.145 0.070 26.215 ;
    END
  END w_mask_in[177]
  PIN w_mask_in[178]
    DIRECTION INPUT ;
    USE SIGNAL ;
    SHAPE ABUTMENT ;
    PORT
      LAYER metal3 ;
      RECT 0.000 26.285 0.070 26.355 ;
    END
  END w_mask_in[178]
  PIN w_mask_in[179]
    DIRECTION INPUT ;
    USE SIGNAL ;
    SHAPE ABUTMENT ;
    PORT
      LAYER metal3 ;
      RECT 0.000 26.425 0.070 26.495 ;
    END
  END w_mask_in[179]
  PIN w_mask_in[180]
    DIRECTION INPUT ;
    USE SIGNAL ;
    SHAPE ABUTMENT ;
    PORT
      LAYER metal3 ;
      RECT 0.000 26.565 0.070 26.635 ;
    END
  END w_mask_in[180]
  PIN w_mask_in[181]
    DIRECTION INPUT ;
    USE SIGNAL ;
    SHAPE ABUTMENT ;
    PORT
      LAYER metal3 ;
      RECT 0.000 26.705 0.070 26.775 ;
    END
  END w_mask_in[181]
  PIN w_mask_in[182]
    DIRECTION INPUT ;
    USE SIGNAL ;
    SHAPE ABUTMENT ;
    PORT
      LAYER metal3 ;
      RECT 0.000 26.845 0.070 26.915 ;
    END
  END w_mask_in[182]
  PIN w_mask_in[183]
    DIRECTION INPUT ;
    USE SIGNAL ;
    SHAPE ABUTMENT ;
    PORT
      LAYER metal3 ;
      RECT 0.000 26.985 0.070 27.055 ;
    END
  END w_mask_in[183]
  PIN w_mask_in[184]
    DIRECTION INPUT ;
    USE SIGNAL ;
    SHAPE ABUTMENT ;
    PORT
      LAYER metal3 ;
      RECT 0.000 27.125 0.070 27.195 ;
    END
  END w_mask_in[184]
  PIN w_mask_in[185]
    DIRECTION INPUT ;
    USE SIGNAL ;
    SHAPE ABUTMENT ;
    PORT
      LAYER metal3 ;
      RECT 0.000 27.265 0.070 27.335 ;
    END
  END w_mask_in[185]
  PIN w_mask_in[186]
    DIRECTION INPUT ;
    USE SIGNAL ;
    SHAPE ABUTMENT ;
    PORT
      LAYER metal3 ;
      RECT 0.000 27.405 0.070 27.475 ;
    END
  END w_mask_in[186]
  PIN w_mask_in[187]
    DIRECTION INPUT ;
    USE SIGNAL ;
    SHAPE ABUTMENT ;
    PORT
      LAYER metal3 ;
      RECT 0.000 27.545 0.070 27.615 ;
    END
  END w_mask_in[187]
  PIN w_mask_in[188]
    DIRECTION INPUT ;
    USE SIGNAL ;
    SHAPE ABUTMENT ;
    PORT
      LAYER metal3 ;
      RECT 0.000 27.685 0.070 27.755 ;
    END
  END w_mask_in[188]
  PIN w_mask_in[189]
    DIRECTION INPUT ;
    USE SIGNAL ;
    SHAPE ABUTMENT ;
    PORT
      LAYER metal3 ;
      RECT 0.000 27.825 0.070 27.895 ;
    END
  END w_mask_in[189]
  PIN w_mask_in[190]
    DIRECTION INPUT ;
    USE SIGNAL ;
    SHAPE ABUTMENT ;
    PORT
      LAYER metal3 ;
      RECT 0.000 27.965 0.070 28.035 ;
    END
  END w_mask_in[190]
  PIN w_mask_in[191]
    DIRECTION INPUT ;
    USE SIGNAL ;
    SHAPE ABUTMENT ;
    PORT
      LAYER metal3 ;
      RECT 0.000 28.105 0.070 28.175 ;
    END
  END w_mask_in[191]
  PIN w_mask_in[192]
    DIRECTION INPUT ;
    USE SIGNAL ;
    SHAPE ABUTMENT ;
    PORT
      LAYER metal3 ;
      RECT 0.000 28.245 0.070 28.315 ;
    END
  END w_mask_in[192]
  PIN w_mask_in[193]
    DIRECTION INPUT ;
    USE SIGNAL ;
    SHAPE ABUTMENT ;
    PORT
      LAYER metal3 ;
      RECT 0.000 28.385 0.070 28.455 ;
    END
  END w_mask_in[193]
  PIN w_mask_in[194]
    DIRECTION INPUT ;
    USE SIGNAL ;
    SHAPE ABUTMENT ;
    PORT
      LAYER metal3 ;
      RECT 0.000 28.525 0.070 28.595 ;
    END
  END w_mask_in[194]
  PIN w_mask_in[195]
    DIRECTION INPUT ;
    USE SIGNAL ;
    SHAPE ABUTMENT ;
    PORT
      LAYER metal3 ;
      RECT 0.000 28.665 0.070 28.735 ;
    END
  END w_mask_in[195]
  PIN w_mask_in[196]
    DIRECTION INPUT ;
    USE SIGNAL ;
    SHAPE ABUTMENT ;
    PORT
      LAYER metal3 ;
      RECT 0.000 28.805 0.070 28.875 ;
    END
  END w_mask_in[196]
  PIN w_mask_in[197]
    DIRECTION INPUT ;
    USE SIGNAL ;
    SHAPE ABUTMENT ;
    PORT
      LAYER metal3 ;
      RECT 0.000 28.945 0.070 29.015 ;
    END
  END w_mask_in[197]
  PIN w_mask_in[198]
    DIRECTION INPUT ;
    USE SIGNAL ;
    SHAPE ABUTMENT ;
    PORT
      LAYER metal3 ;
      RECT 0.000 29.085 0.070 29.155 ;
    END
  END w_mask_in[198]
  PIN w_mask_in[199]
    DIRECTION INPUT ;
    USE SIGNAL ;
    SHAPE ABUTMENT ;
    PORT
      LAYER metal3 ;
      RECT 0.000 29.225 0.070 29.295 ;
    END
  END w_mask_in[199]
  PIN w_mask_in[200]
    DIRECTION INPUT ;
    USE SIGNAL ;
    SHAPE ABUTMENT ;
    PORT
      LAYER metal3 ;
      RECT 0.000 29.365 0.070 29.435 ;
    END
  END w_mask_in[200]
  PIN w_mask_in[201]
    DIRECTION INPUT ;
    USE SIGNAL ;
    SHAPE ABUTMENT ;
    PORT
      LAYER metal3 ;
      RECT 0.000 29.505 0.070 29.575 ;
    END
  END w_mask_in[201]
  PIN w_mask_in[202]
    DIRECTION INPUT ;
    USE SIGNAL ;
    SHAPE ABUTMENT ;
    PORT
      LAYER metal3 ;
      RECT 0.000 29.645 0.070 29.715 ;
    END
  END w_mask_in[202]
  PIN w_mask_in[203]
    DIRECTION INPUT ;
    USE SIGNAL ;
    SHAPE ABUTMENT ;
    PORT
      LAYER metal3 ;
      RECT 0.000 29.785 0.070 29.855 ;
    END
  END w_mask_in[203]
  PIN w_mask_in[204]
    DIRECTION INPUT ;
    USE SIGNAL ;
    SHAPE ABUTMENT ;
    PORT
      LAYER metal3 ;
      RECT 0.000 29.925 0.070 29.995 ;
    END
  END w_mask_in[204]
  PIN w_mask_in[205]
    DIRECTION INPUT ;
    USE SIGNAL ;
    SHAPE ABUTMENT ;
    PORT
      LAYER metal3 ;
      RECT 0.000 30.065 0.070 30.135 ;
    END
  END w_mask_in[205]
  PIN w_mask_in[206]
    DIRECTION INPUT ;
    USE SIGNAL ;
    SHAPE ABUTMENT ;
    PORT
      LAYER metal3 ;
      RECT 0.000 30.205 0.070 30.275 ;
    END
  END w_mask_in[206]
  PIN w_mask_in[207]
    DIRECTION INPUT ;
    USE SIGNAL ;
    SHAPE ABUTMENT ;
    PORT
      LAYER metal3 ;
      RECT 0.000 30.345 0.070 30.415 ;
    END
  END w_mask_in[207]
  PIN w_mask_in[208]
    DIRECTION INPUT ;
    USE SIGNAL ;
    SHAPE ABUTMENT ;
    PORT
      LAYER metal3 ;
      RECT 0.000 30.485 0.070 30.555 ;
    END
  END w_mask_in[208]
  PIN w_mask_in[209]
    DIRECTION INPUT ;
    USE SIGNAL ;
    SHAPE ABUTMENT ;
    PORT
      LAYER metal3 ;
      RECT 0.000 30.625 0.070 30.695 ;
    END
  END w_mask_in[209]
  PIN w_mask_in[210]
    DIRECTION INPUT ;
    USE SIGNAL ;
    SHAPE ABUTMENT ;
    PORT
      LAYER metal3 ;
      RECT 0.000 30.765 0.070 30.835 ;
    END
  END w_mask_in[210]
  PIN w_mask_in[211]
    DIRECTION INPUT ;
    USE SIGNAL ;
    SHAPE ABUTMENT ;
    PORT
      LAYER metal3 ;
      RECT 0.000 30.905 0.070 30.975 ;
    END
  END w_mask_in[211]
  PIN w_mask_in[212]
    DIRECTION INPUT ;
    USE SIGNAL ;
    SHAPE ABUTMENT ;
    PORT
      LAYER metal3 ;
      RECT 0.000 31.045 0.070 31.115 ;
    END
  END w_mask_in[212]
  PIN w_mask_in[213]
    DIRECTION INPUT ;
    USE SIGNAL ;
    SHAPE ABUTMENT ;
    PORT
      LAYER metal3 ;
      RECT 0.000 31.185 0.070 31.255 ;
    END
  END w_mask_in[213]
  PIN w_mask_in[214]
    DIRECTION INPUT ;
    USE SIGNAL ;
    SHAPE ABUTMENT ;
    PORT
      LAYER metal3 ;
      RECT 0.000 31.325 0.070 31.395 ;
    END
  END w_mask_in[214]
  PIN w_mask_in[215]
    DIRECTION INPUT ;
    USE SIGNAL ;
    SHAPE ABUTMENT ;
    PORT
      LAYER metal3 ;
      RECT 0.000 31.465 0.070 31.535 ;
    END
  END w_mask_in[215]
  PIN w_mask_in[216]
    DIRECTION INPUT ;
    USE SIGNAL ;
    SHAPE ABUTMENT ;
    PORT
      LAYER metal3 ;
      RECT 0.000 31.605 0.070 31.675 ;
    END
  END w_mask_in[216]
  PIN w_mask_in[217]
    DIRECTION INPUT ;
    USE SIGNAL ;
    SHAPE ABUTMENT ;
    PORT
      LAYER metal3 ;
      RECT 0.000 31.745 0.070 31.815 ;
    END
  END w_mask_in[217]
  PIN w_mask_in[218]
    DIRECTION INPUT ;
    USE SIGNAL ;
    SHAPE ABUTMENT ;
    PORT
      LAYER metal3 ;
      RECT 0.000 31.885 0.070 31.955 ;
    END
  END w_mask_in[218]
  PIN w_mask_in[219]
    DIRECTION INPUT ;
    USE SIGNAL ;
    SHAPE ABUTMENT ;
    PORT
      LAYER metal3 ;
      RECT 0.000 32.025 0.070 32.095 ;
    END
  END w_mask_in[219]
  PIN w_mask_in[220]
    DIRECTION INPUT ;
    USE SIGNAL ;
    SHAPE ABUTMENT ;
    PORT
      LAYER metal3 ;
      RECT 0.000 32.165 0.070 32.235 ;
    END
  END w_mask_in[220]
  PIN w_mask_in[221]
    DIRECTION INPUT ;
    USE SIGNAL ;
    SHAPE ABUTMENT ;
    PORT
      LAYER metal3 ;
      RECT 0.000 32.305 0.070 32.375 ;
    END
  END w_mask_in[221]
  PIN w_mask_in[222]
    DIRECTION INPUT ;
    USE SIGNAL ;
    SHAPE ABUTMENT ;
    PORT
      LAYER metal3 ;
      RECT 0.000 32.445 0.070 32.515 ;
    END
  END w_mask_in[222]
  PIN w_mask_in[223]
    DIRECTION INPUT ;
    USE SIGNAL ;
    SHAPE ABUTMENT ;
    PORT
      LAYER metal3 ;
      RECT 0.000 32.585 0.070 32.655 ;
    END
  END w_mask_in[223]
  PIN w_mask_in[224]
    DIRECTION INPUT ;
    USE SIGNAL ;
    SHAPE ABUTMENT ;
    PORT
      LAYER metal3 ;
      RECT 0.000 32.725 0.070 32.795 ;
    END
  END w_mask_in[224]
  PIN w_mask_in[225]
    DIRECTION INPUT ;
    USE SIGNAL ;
    SHAPE ABUTMENT ;
    PORT
      LAYER metal3 ;
      RECT 0.000 32.865 0.070 32.935 ;
    END
  END w_mask_in[225]
  PIN w_mask_in[226]
    DIRECTION INPUT ;
    USE SIGNAL ;
    SHAPE ABUTMENT ;
    PORT
      LAYER metal3 ;
      RECT 0.000 33.005 0.070 33.075 ;
    END
  END w_mask_in[226]
  PIN w_mask_in[227]
    DIRECTION INPUT ;
    USE SIGNAL ;
    SHAPE ABUTMENT ;
    PORT
      LAYER metal3 ;
      RECT 0.000 33.145 0.070 33.215 ;
    END
  END w_mask_in[227]
  PIN w_mask_in[228]
    DIRECTION INPUT ;
    USE SIGNAL ;
    SHAPE ABUTMENT ;
    PORT
      LAYER metal3 ;
      RECT 0.000 33.285 0.070 33.355 ;
    END
  END w_mask_in[228]
  PIN w_mask_in[229]
    DIRECTION INPUT ;
    USE SIGNAL ;
    SHAPE ABUTMENT ;
    PORT
      LAYER metal3 ;
      RECT 0.000 33.425 0.070 33.495 ;
    END
  END w_mask_in[229]
  PIN w_mask_in[230]
    DIRECTION INPUT ;
    USE SIGNAL ;
    SHAPE ABUTMENT ;
    PORT
      LAYER metal3 ;
      RECT 0.000 33.565 0.070 33.635 ;
    END
  END w_mask_in[230]
  PIN w_mask_in[231]
    DIRECTION INPUT ;
    USE SIGNAL ;
    SHAPE ABUTMENT ;
    PORT
      LAYER metal3 ;
      RECT 0.000 33.705 0.070 33.775 ;
    END
  END w_mask_in[231]
  PIN w_mask_in[232]
    DIRECTION INPUT ;
    USE SIGNAL ;
    SHAPE ABUTMENT ;
    PORT
      LAYER metal3 ;
      RECT 0.000 33.845 0.070 33.915 ;
    END
  END w_mask_in[232]
  PIN w_mask_in[233]
    DIRECTION INPUT ;
    USE SIGNAL ;
    SHAPE ABUTMENT ;
    PORT
      LAYER metal3 ;
      RECT 0.000 33.985 0.070 34.055 ;
    END
  END w_mask_in[233]
  PIN w_mask_in[234]
    DIRECTION INPUT ;
    USE SIGNAL ;
    SHAPE ABUTMENT ;
    PORT
      LAYER metal3 ;
      RECT 0.000 34.125 0.070 34.195 ;
    END
  END w_mask_in[234]
  PIN w_mask_in[235]
    DIRECTION INPUT ;
    USE SIGNAL ;
    SHAPE ABUTMENT ;
    PORT
      LAYER metal3 ;
      RECT 0.000 34.265 0.070 34.335 ;
    END
  END w_mask_in[235]
  PIN w_mask_in[236]
    DIRECTION INPUT ;
    USE SIGNAL ;
    SHAPE ABUTMENT ;
    PORT
      LAYER metal3 ;
      RECT 0.000 34.405 0.070 34.475 ;
    END
  END w_mask_in[236]
  PIN w_mask_in[237]
    DIRECTION INPUT ;
    USE SIGNAL ;
    SHAPE ABUTMENT ;
    PORT
      LAYER metal3 ;
      RECT 0.000 34.545 0.070 34.615 ;
    END
  END w_mask_in[237]
  PIN w_mask_in[238]
    DIRECTION INPUT ;
    USE SIGNAL ;
    SHAPE ABUTMENT ;
    PORT
      LAYER metal3 ;
      RECT 0.000 34.685 0.070 34.755 ;
    END
  END w_mask_in[238]
  PIN w_mask_in[239]
    DIRECTION INPUT ;
    USE SIGNAL ;
    SHAPE ABUTMENT ;
    PORT
      LAYER metal3 ;
      RECT 0.000 34.825 0.070 34.895 ;
    END
  END w_mask_in[239]
  PIN w_mask_in[240]
    DIRECTION INPUT ;
    USE SIGNAL ;
    SHAPE ABUTMENT ;
    PORT
      LAYER metal3 ;
      RECT 0.000 34.965 0.070 35.035 ;
    END
  END w_mask_in[240]
  PIN w_mask_in[241]
    DIRECTION INPUT ;
    USE SIGNAL ;
    SHAPE ABUTMENT ;
    PORT
      LAYER metal3 ;
      RECT 0.000 35.105 0.070 35.175 ;
    END
  END w_mask_in[241]
  PIN w_mask_in[242]
    DIRECTION INPUT ;
    USE SIGNAL ;
    SHAPE ABUTMENT ;
    PORT
      LAYER metal3 ;
      RECT 0.000 35.245 0.070 35.315 ;
    END
  END w_mask_in[242]
  PIN w_mask_in[243]
    DIRECTION INPUT ;
    USE SIGNAL ;
    SHAPE ABUTMENT ;
    PORT
      LAYER metal3 ;
      RECT 0.000 35.385 0.070 35.455 ;
    END
  END w_mask_in[243]
  PIN w_mask_in[244]
    DIRECTION INPUT ;
    USE SIGNAL ;
    SHAPE ABUTMENT ;
    PORT
      LAYER metal3 ;
      RECT 0.000 35.525 0.070 35.595 ;
    END
  END w_mask_in[244]
  PIN w_mask_in[245]
    DIRECTION INPUT ;
    USE SIGNAL ;
    SHAPE ABUTMENT ;
    PORT
      LAYER metal3 ;
      RECT 0.000 35.665 0.070 35.735 ;
    END
  END w_mask_in[245]
  PIN w_mask_in[246]
    DIRECTION INPUT ;
    USE SIGNAL ;
    SHAPE ABUTMENT ;
    PORT
      LAYER metal3 ;
      RECT 0.000 35.805 0.070 35.875 ;
    END
  END w_mask_in[246]
  PIN w_mask_in[247]
    DIRECTION INPUT ;
    USE SIGNAL ;
    SHAPE ABUTMENT ;
    PORT
      LAYER metal3 ;
      RECT 0.000 35.945 0.070 36.015 ;
    END
  END w_mask_in[247]
  PIN w_mask_in[248]
    DIRECTION INPUT ;
    USE SIGNAL ;
    SHAPE ABUTMENT ;
    PORT
      LAYER metal3 ;
      RECT 0.000 36.085 0.070 36.155 ;
    END
  END w_mask_in[248]
  PIN w_mask_in[249]
    DIRECTION INPUT ;
    USE SIGNAL ;
    SHAPE ABUTMENT ;
    PORT
      LAYER metal3 ;
      RECT 0.000 36.225 0.070 36.295 ;
    END
  END w_mask_in[249]
  PIN w_mask_in[250]
    DIRECTION INPUT ;
    USE SIGNAL ;
    SHAPE ABUTMENT ;
    PORT
      LAYER metal3 ;
      RECT 0.000 36.365 0.070 36.435 ;
    END
  END w_mask_in[250]
  PIN w_mask_in[251]
    DIRECTION INPUT ;
    USE SIGNAL ;
    SHAPE ABUTMENT ;
    PORT
      LAYER metal3 ;
      RECT 0.000 36.505 0.070 36.575 ;
    END
  END w_mask_in[251]
  PIN w_mask_in[252]
    DIRECTION INPUT ;
    USE SIGNAL ;
    SHAPE ABUTMENT ;
    PORT
      LAYER metal3 ;
      RECT 0.000 36.645 0.070 36.715 ;
    END
  END w_mask_in[252]
  PIN w_mask_in[253]
    DIRECTION INPUT ;
    USE SIGNAL ;
    SHAPE ABUTMENT ;
    PORT
      LAYER metal3 ;
      RECT 0.000 36.785 0.070 36.855 ;
    END
  END w_mask_in[253]
  PIN w_mask_in[254]
    DIRECTION INPUT ;
    USE SIGNAL ;
    SHAPE ABUTMENT ;
    PORT
      LAYER metal3 ;
      RECT 0.000 36.925 0.070 36.995 ;
    END
  END w_mask_in[254]
  PIN w_mask_in[255]
    DIRECTION INPUT ;
    USE SIGNAL ;
    SHAPE ABUTMENT ;
    PORT
      LAYER metal3 ;
      RECT 0.000 37.065 0.070 37.135 ;
    END
  END w_mask_in[255]
  PIN w_mask_in[256]
    DIRECTION INPUT ;
    USE SIGNAL ;
    SHAPE ABUTMENT ;
    PORT
      LAYER metal3 ;
      RECT 0.000 37.205 0.070 37.275 ;
    END
  END w_mask_in[256]
  PIN w_mask_in[257]
    DIRECTION INPUT ;
    USE SIGNAL ;
    SHAPE ABUTMENT ;
    PORT
      LAYER metal3 ;
      RECT 0.000 37.345 0.070 37.415 ;
    END
  END w_mask_in[257]
  PIN w_mask_in[258]
    DIRECTION INPUT ;
    USE SIGNAL ;
    SHAPE ABUTMENT ;
    PORT
      LAYER metal3 ;
      RECT 0.000 37.485 0.070 37.555 ;
    END
  END w_mask_in[258]
  PIN w_mask_in[259]
    DIRECTION INPUT ;
    USE SIGNAL ;
    SHAPE ABUTMENT ;
    PORT
      LAYER metal3 ;
      RECT 0.000 37.625 0.070 37.695 ;
    END
  END w_mask_in[259]
  PIN w_mask_in[260]
    DIRECTION INPUT ;
    USE SIGNAL ;
    SHAPE ABUTMENT ;
    PORT
      LAYER metal3 ;
      RECT 0.000 37.765 0.070 37.835 ;
    END
  END w_mask_in[260]
  PIN w_mask_in[261]
    DIRECTION INPUT ;
    USE SIGNAL ;
    SHAPE ABUTMENT ;
    PORT
      LAYER metal3 ;
      RECT 0.000 37.905 0.070 37.975 ;
    END
  END w_mask_in[261]
  PIN w_mask_in[262]
    DIRECTION INPUT ;
    USE SIGNAL ;
    SHAPE ABUTMENT ;
    PORT
      LAYER metal3 ;
      RECT 0.000 38.045 0.070 38.115 ;
    END
  END w_mask_in[262]
  PIN w_mask_in[263]
    DIRECTION INPUT ;
    USE SIGNAL ;
    SHAPE ABUTMENT ;
    PORT
      LAYER metal3 ;
      RECT 0.000 38.185 0.070 38.255 ;
    END
  END w_mask_in[263]
  PIN w_mask_in[264]
    DIRECTION INPUT ;
    USE SIGNAL ;
    SHAPE ABUTMENT ;
    PORT
      LAYER metal3 ;
      RECT 0.000 38.325 0.070 38.395 ;
    END
  END w_mask_in[264]
  PIN w_mask_in[265]
    DIRECTION INPUT ;
    USE SIGNAL ;
    SHAPE ABUTMENT ;
    PORT
      LAYER metal3 ;
      RECT 0.000 38.465 0.070 38.535 ;
    END
  END w_mask_in[265]
  PIN w_mask_in[266]
    DIRECTION INPUT ;
    USE SIGNAL ;
    SHAPE ABUTMENT ;
    PORT
      LAYER metal3 ;
      RECT 0.000 38.605 0.070 38.675 ;
    END
  END w_mask_in[266]
  PIN w_mask_in[267]
    DIRECTION INPUT ;
    USE SIGNAL ;
    SHAPE ABUTMENT ;
    PORT
      LAYER metal3 ;
      RECT 0.000 38.745 0.070 38.815 ;
    END
  END w_mask_in[267]
  PIN w_mask_in[268]
    DIRECTION INPUT ;
    USE SIGNAL ;
    SHAPE ABUTMENT ;
    PORT
      LAYER metal3 ;
      RECT 0.000 38.885 0.070 38.955 ;
    END
  END w_mask_in[268]
  PIN w_mask_in[269]
    DIRECTION INPUT ;
    USE SIGNAL ;
    SHAPE ABUTMENT ;
    PORT
      LAYER metal3 ;
      RECT 0.000 39.025 0.070 39.095 ;
    END
  END w_mask_in[269]
  PIN w_mask_in[270]
    DIRECTION INPUT ;
    USE SIGNAL ;
    SHAPE ABUTMENT ;
    PORT
      LAYER metal3 ;
      RECT 0.000 39.165 0.070 39.235 ;
    END
  END w_mask_in[270]
  PIN w_mask_in[271]
    DIRECTION INPUT ;
    USE SIGNAL ;
    SHAPE ABUTMENT ;
    PORT
      LAYER metal3 ;
      RECT 0.000 39.305 0.070 39.375 ;
    END
  END w_mask_in[271]
  PIN w_mask_in[272]
    DIRECTION INPUT ;
    USE SIGNAL ;
    SHAPE ABUTMENT ;
    PORT
      LAYER metal3 ;
      RECT 0.000 39.445 0.070 39.515 ;
    END
  END w_mask_in[272]
  PIN w_mask_in[273]
    DIRECTION INPUT ;
    USE SIGNAL ;
    SHAPE ABUTMENT ;
    PORT
      LAYER metal3 ;
      RECT 0.000 39.585 0.070 39.655 ;
    END
  END w_mask_in[273]
  PIN w_mask_in[274]
    DIRECTION INPUT ;
    USE SIGNAL ;
    SHAPE ABUTMENT ;
    PORT
      LAYER metal3 ;
      RECT 0.000 39.725 0.070 39.795 ;
    END
  END w_mask_in[274]
  PIN w_mask_in[275]
    DIRECTION INPUT ;
    USE SIGNAL ;
    SHAPE ABUTMENT ;
    PORT
      LAYER metal3 ;
      RECT 0.000 39.865 0.070 39.935 ;
    END
  END w_mask_in[275]
  PIN w_mask_in[276]
    DIRECTION INPUT ;
    USE SIGNAL ;
    SHAPE ABUTMENT ;
    PORT
      LAYER metal3 ;
      RECT 0.000 40.005 0.070 40.075 ;
    END
  END w_mask_in[276]
  PIN w_mask_in[277]
    DIRECTION INPUT ;
    USE SIGNAL ;
    SHAPE ABUTMENT ;
    PORT
      LAYER metal3 ;
      RECT 0.000 40.145 0.070 40.215 ;
    END
  END w_mask_in[277]
  PIN w_mask_in[278]
    DIRECTION INPUT ;
    USE SIGNAL ;
    SHAPE ABUTMENT ;
    PORT
      LAYER metal3 ;
      RECT 0.000 40.285 0.070 40.355 ;
    END
  END w_mask_in[278]
  PIN w_mask_in[279]
    DIRECTION INPUT ;
    USE SIGNAL ;
    SHAPE ABUTMENT ;
    PORT
      LAYER metal3 ;
      RECT 0.000 40.425 0.070 40.495 ;
    END
  END w_mask_in[279]
  PIN w_mask_in[280]
    DIRECTION INPUT ;
    USE SIGNAL ;
    SHAPE ABUTMENT ;
    PORT
      LAYER metal3 ;
      RECT 0.000 40.565 0.070 40.635 ;
    END
  END w_mask_in[280]
  PIN w_mask_in[281]
    DIRECTION INPUT ;
    USE SIGNAL ;
    SHAPE ABUTMENT ;
    PORT
      LAYER metal3 ;
      RECT 0.000 40.705 0.070 40.775 ;
    END
  END w_mask_in[281]
  PIN w_mask_in[282]
    DIRECTION INPUT ;
    USE SIGNAL ;
    SHAPE ABUTMENT ;
    PORT
      LAYER metal3 ;
      RECT 0.000 40.845 0.070 40.915 ;
    END
  END w_mask_in[282]
  PIN w_mask_in[283]
    DIRECTION INPUT ;
    USE SIGNAL ;
    SHAPE ABUTMENT ;
    PORT
      LAYER metal3 ;
      RECT 0.000 40.985 0.070 41.055 ;
    END
  END w_mask_in[283]
  PIN w_mask_in[284]
    DIRECTION INPUT ;
    USE SIGNAL ;
    SHAPE ABUTMENT ;
    PORT
      LAYER metal3 ;
      RECT 0.000 41.125 0.070 41.195 ;
    END
  END w_mask_in[284]
  PIN w_mask_in[285]
    DIRECTION INPUT ;
    USE SIGNAL ;
    SHAPE ABUTMENT ;
    PORT
      LAYER metal3 ;
      RECT 0.000 41.265 0.070 41.335 ;
    END
  END w_mask_in[285]
  PIN w_mask_in[286]
    DIRECTION INPUT ;
    USE SIGNAL ;
    SHAPE ABUTMENT ;
    PORT
      LAYER metal3 ;
      RECT 0.000 41.405 0.070 41.475 ;
    END
  END w_mask_in[286]
  PIN w_mask_in[287]
    DIRECTION INPUT ;
    USE SIGNAL ;
    SHAPE ABUTMENT ;
    PORT
      LAYER metal3 ;
      RECT 0.000 41.545 0.070 41.615 ;
    END
  END w_mask_in[287]
  PIN w_mask_in[288]
    DIRECTION INPUT ;
    USE SIGNAL ;
    SHAPE ABUTMENT ;
    PORT
      LAYER metal3 ;
      RECT 0.000 41.685 0.070 41.755 ;
    END
  END w_mask_in[288]
  PIN w_mask_in[289]
    DIRECTION INPUT ;
    USE SIGNAL ;
    SHAPE ABUTMENT ;
    PORT
      LAYER metal3 ;
      RECT 0.000 41.825 0.070 41.895 ;
    END
  END w_mask_in[289]
  PIN w_mask_in[290]
    DIRECTION INPUT ;
    USE SIGNAL ;
    SHAPE ABUTMENT ;
    PORT
      LAYER metal3 ;
      RECT 0.000 41.965 0.070 42.035 ;
    END
  END w_mask_in[290]
  PIN w_mask_in[291]
    DIRECTION INPUT ;
    USE SIGNAL ;
    SHAPE ABUTMENT ;
    PORT
      LAYER metal3 ;
      RECT 0.000 42.105 0.070 42.175 ;
    END
  END w_mask_in[291]
  PIN w_mask_in[292]
    DIRECTION INPUT ;
    USE SIGNAL ;
    SHAPE ABUTMENT ;
    PORT
      LAYER metal3 ;
      RECT 0.000 42.245 0.070 42.315 ;
    END
  END w_mask_in[292]
  PIN w_mask_in[293]
    DIRECTION INPUT ;
    USE SIGNAL ;
    SHAPE ABUTMENT ;
    PORT
      LAYER metal3 ;
      RECT 0.000 42.385 0.070 42.455 ;
    END
  END w_mask_in[293]
  PIN w_mask_in[294]
    DIRECTION INPUT ;
    USE SIGNAL ;
    SHAPE ABUTMENT ;
    PORT
      LAYER metal3 ;
      RECT 0.000 42.525 0.070 42.595 ;
    END
  END w_mask_in[294]
  PIN w_mask_in[295]
    DIRECTION INPUT ;
    USE SIGNAL ;
    SHAPE ABUTMENT ;
    PORT
      LAYER metal3 ;
      RECT 0.000 42.665 0.070 42.735 ;
    END
  END w_mask_in[295]
  PIN w_mask_in[296]
    DIRECTION INPUT ;
    USE SIGNAL ;
    SHAPE ABUTMENT ;
    PORT
      LAYER metal3 ;
      RECT 0.000 42.805 0.070 42.875 ;
    END
  END w_mask_in[296]
  PIN w_mask_in[297]
    DIRECTION INPUT ;
    USE SIGNAL ;
    SHAPE ABUTMENT ;
    PORT
      LAYER metal3 ;
      RECT 0.000 42.945 0.070 43.015 ;
    END
  END w_mask_in[297]
  PIN w_mask_in[298]
    DIRECTION INPUT ;
    USE SIGNAL ;
    SHAPE ABUTMENT ;
    PORT
      LAYER metal3 ;
      RECT 0.000 43.085 0.070 43.155 ;
    END
  END w_mask_in[298]
  PIN w_mask_in[299]
    DIRECTION INPUT ;
    USE SIGNAL ;
    SHAPE ABUTMENT ;
    PORT
      LAYER metal3 ;
      RECT 0.000 43.225 0.070 43.295 ;
    END
  END w_mask_in[299]
  PIN w_mask_in[300]
    DIRECTION INPUT ;
    USE SIGNAL ;
    SHAPE ABUTMENT ;
    PORT
      LAYER metal3 ;
      RECT 0.000 43.365 0.070 43.435 ;
    END
  END w_mask_in[300]
  PIN w_mask_in[301]
    DIRECTION INPUT ;
    USE SIGNAL ;
    SHAPE ABUTMENT ;
    PORT
      LAYER metal3 ;
      RECT 0.000 43.505 0.070 43.575 ;
    END
  END w_mask_in[301]
  PIN w_mask_in[302]
    DIRECTION INPUT ;
    USE SIGNAL ;
    SHAPE ABUTMENT ;
    PORT
      LAYER metal3 ;
      RECT 0.000 43.645 0.070 43.715 ;
    END
  END w_mask_in[302]
  PIN w_mask_in[303]
    DIRECTION INPUT ;
    USE SIGNAL ;
    SHAPE ABUTMENT ;
    PORT
      LAYER metal3 ;
      RECT 0.000 43.785 0.070 43.855 ;
    END
  END w_mask_in[303]
  PIN w_mask_in[304]
    DIRECTION INPUT ;
    USE SIGNAL ;
    SHAPE ABUTMENT ;
    PORT
      LAYER metal3 ;
      RECT 0.000 43.925 0.070 43.995 ;
    END
  END w_mask_in[304]
  PIN w_mask_in[305]
    DIRECTION INPUT ;
    USE SIGNAL ;
    SHAPE ABUTMENT ;
    PORT
      LAYER metal3 ;
      RECT 0.000 44.065 0.070 44.135 ;
    END
  END w_mask_in[305]
  PIN w_mask_in[306]
    DIRECTION INPUT ;
    USE SIGNAL ;
    SHAPE ABUTMENT ;
    PORT
      LAYER metal3 ;
      RECT 0.000 44.205 0.070 44.275 ;
    END
  END w_mask_in[306]
  PIN w_mask_in[307]
    DIRECTION INPUT ;
    USE SIGNAL ;
    SHAPE ABUTMENT ;
    PORT
      LAYER metal3 ;
      RECT 0.000 44.345 0.070 44.415 ;
    END
  END w_mask_in[307]
  PIN w_mask_in[308]
    DIRECTION INPUT ;
    USE SIGNAL ;
    SHAPE ABUTMENT ;
    PORT
      LAYER metal3 ;
      RECT 0.000 44.485 0.070 44.555 ;
    END
  END w_mask_in[308]
  PIN w_mask_in[309]
    DIRECTION INPUT ;
    USE SIGNAL ;
    SHAPE ABUTMENT ;
    PORT
      LAYER metal3 ;
      RECT 0.000 44.625 0.070 44.695 ;
    END
  END w_mask_in[309]
  PIN w_mask_in[310]
    DIRECTION INPUT ;
    USE SIGNAL ;
    SHAPE ABUTMENT ;
    PORT
      LAYER metal3 ;
      RECT 0.000 44.765 0.070 44.835 ;
    END
  END w_mask_in[310]
  PIN w_mask_in[311]
    DIRECTION INPUT ;
    USE SIGNAL ;
    SHAPE ABUTMENT ;
    PORT
      LAYER metal3 ;
      RECT 0.000 44.905 0.070 44.975 ;
    END
  END w_mask_in[311]
  PIN w_mask_in[312]
    DIRECTION INPUT ;
    USE SIGNAL ;
    SHAPE ABUTMENT ;
    PORT
      LAYER metal3 ;
      RECT 0.000 45.045 0.070 45.115 ;
    END
  END w_mask_in[312]
  PIN w_mask_in[313]
    DIRECTION INPUT ;
    USE SIGNAL ;
    SHAPE ABUTMENT ;
    PORT
      LAYER metal3 ;
      RECT 0.000 45.185 0.070 45.255 ;
    END
  END w_mask_in[313]
  PIN w_mask_in[314]
    DIRECTION INPUT ;
    USE SIGNAL ;
    SHAPE ABUTMENT ;
    PORT
      LAYER metal3 ;
      RECT 0.000 45.325 0.070 45.395 ;
    END
  END w_mask_in[314]
  PIN w_mask_in[315]
    DIRECTION INPUT ;
    USE SIGNAL ;
    SHAPE ABUTMENT ;
    PORT
      LAYER metal3 ;
      RECT 0.000 45.465 0.070 45.535 ;
    END
  END w_mask_in[315]
  PIN w_mask_in[316]
    DIRECTION INPUT ;
    USE SIGNAL ;
    SHAPE ABUTMENT ;
    PORT
      LAYER metal3 ;
      RECT 0.000 45.605 0.070 45.675 ;
    END
  END w_mask_in[316]
  PIN w_mask_in[317]
    DIRECTION INPUT ;
    USE SIGNAL ;
    SHAPE ABUTMENT ;
    PORT
      LAYER metal3 ;
      RECT 0.000 45.745 0.070 45.815 ;
    END
  END w_mask_in[317]
  PIN w_mask_in[318]
    DIRECTION INPUT ;
    USE SIGNAL ;
    SHAPE ABUTMENT ;
    PORT
      LAYER metal3 ;
      RECT 0.000 45.885 0.070 45.955 ;
    END
  END w_mask_in[318]
  PIN w_mask_in[319]
    DIRECTION INPUT ;
    USE SIGNAL ;
    SHAPE ABUTMENT ;
    PORT
      LAYER metal3 ;
      RECT 0.000 46.025 0.070 46.095 ;
    END
  END w_mask_in[319]
  PIN w_mask_in[320]
    DIRECTION INPUT ;
    USE SIGNAL ;
    SHAPE ABUTMENT ;
    PORT
      LAYER metal3 ;
      RECT 0.000 46.165 0.070 46.235 ;
    END
  END w_mask_in[320]
  PIN w_mask_in[321]
    DIRECTION INPUT ;
    USE SIGNAL ;
    SHAPE ABUTMENT ;
    PORT
      LAYER metal3 ;
      RECT 0.000 46.305 0.070 46.375 ;
    END
  END w_mask_in[321]
  PIN w_mask_in[322]
    DIRECTION INPUT ;
    USE SIGNAL ;
    SHAPE ABUTMENT ;
    PORT
      LAYER metal3 ;
      RECT 0.000 46.445 0.070 46.515 ;
    END
  END w_mask_in[322]
  PIN w_mask_in[323]
    DIRECTION INPUT ;
    USE SIGNAL ;
    SHAPE ABUTMENT ;
    PORT
      LAYER metal3 ;
      RECT 0.000 46.585 0.070 46.655 ;
    END
  END w_mask_in[323]
  PIN w_mask_in[324]
    DIRECTION INPUT ;
    USE SIGNAL ;
    SHAPE ABUTMENT ;
    PORT
      LAYER metal3 ;
      RECT 0.000 46.725 0.070 46.795 ;
    END
  END w_mask_in[324]
  PIN w_mask_in[325]
    DIRECTION INPUT ;
    USE SIGNAL ;
    SHAPE ABUTMENT ;
    PORT
      LAYER metal3 ;
      RECT 0.000 46.865 0.070 46.935 ;
    END
  END w_mask_in[325]
  PIN w_mask_in[326]
    DIRECTION INPUT ;
    USE SIGNAL ;
    SHAPE ABUTMENT ;
    PORT
      LAYER metal3 ;
      RECT 0.000 47.005 0.070 47.075 ;
    END
  END w_mask_in[326]
  PIN w_mask_in[327]
    DIRECTION INPUT ;
    USE SIGNAL ;
    SHAPE ABUTMENT ;
    PORT
      LAYER metal3 ;
      RECT 0.000 47.145 0.070 47.215 ;
    END
  END w_mask_in[327]
  PIN w_mask_in[328]
    DIRECTION INPUT ;
    USE SIGNAL ;
    SHAPE ABUTMENT ;
    PORT
      LAYER metal3 ;
      RECT 0.000 47.285 0.070 47.355 ;
    END
  END w_mask_in[328]
  PIN w_mask_in[329]
    DIRECTION INPUT ;
    USE SIGNAL ;
    SHAPE ABUTMENT ;
    PORT
      LAYER metal3 ;
      RECT 0.000 47.425 0.070 47.495 ;
    END
  END w_mask_in[329]
  PIN w_mask_in[330]
    DIRECTION INPUT ;
    USE SIGNAL ;
    SHAPE ABUTMENT ;
    PORT
      LAYER metal3 ;
      RECT 0.000 47.565 0.070 47.635 ;
    END
  END w_mask_in[330]
  PIN w_mask_in[331]
    DIRECTION INPUT ;
    USE SIGNAL ;
    SHAPE ABUTMENT ;
    PORT
      LAYER metal3 ;
      RECT 0.000 47.705 0.070 47.775 ;
    END
  END w_mask_in[331]
  PIN w_mask_in[332]
    DIRECTION INPUT ;
    USE SIGNAL ;
    SHAPE ABUTMENT ;
    PORT
      LAYER metal3 ;
      RECT 0.000 47.845 0.070 47.915 ;
    END
  END w_mask_in[332]
  PIN w_mask_in[333]
    DIRECTION INPUT ;
    USE SIGNAL ;
    SHAPE ABUTMENT ;
    PORT
      LAYER metal3 ;
      RECT 0.000 47.985 0.070 48.055 ;
    END
  END w_mask_in[333]
  PIN w_mask_in[334]
    DIRECTION INPUT ;
    USE SIGNAL ;
    SHAPE ABUTMENT ;
    PORT
      LAYER metal3 ;
      RECT 0.000 48.125 0.070 48.195 ;
    END
  END w_mask_in[334]
  PIN w_mask_in[335]
    DIRECTION INPUT ;
    USE SIGNAL ;
    SHAPE ABUTMENT ;
    PORT
      LAYER metal3 ;
      RECT 0.000 48.265 0.070 48.335 ;
    END
  END w_mask_in[335]
  PIN w_mask_in[336]
    DIRECTION INPUT ;
    USE SIGNAL ;
    SHAPE ABUTMENT ;
    PORT
      LAYER metal3 ;
      RECT 0.000 48.405 0.070 48.475 ;
    END
  END w_mask_in[336]
  PIN w_mask_in[337]
    DIRECTION INPUT ;
    USE SIGNAL ;
    SHAPE ABUTMENT ;
    PORT
      LAYER metal3 ;
      RECT 0.000 48.545 0.070 48.615 ;
    END
  END w_mask_in[337]
  PIN w_mask_in[338]
    DIRECTION INPUT ;
    USE SIGNAL ;
    SHAPE ABUTMENT ;
    PORT
      LAYER metal3 ;
      RECT 0.000 48.685 0.070 48.755 ;
    END
  END w_mask_in[338]
  PIN w_mask_in[339]
    DIRECTION INPUT ;
    USE SIGNAL ;
    SHAPE ABUTMENT ;
    PORT
      LAYER metal3 ;
      RECT 0.000 48.825 0.070 48.895 ;
    END
  END w_mask_in[339]
  PIN w_mask_in[340]
    DIRECTION INPUT ;
    USE SIGNAL ;
    SHAPE ABUTMENT ;
    PORT
      LAYER metal3 ;
      RECT 0.000 48.965 0.070 49.035 ;
    END
  END w_mask_in[340]
  PIN w_mask_in[341]
    DIRECTION INPUT ;
    USE SIGNAL ;
    SHAPE ABUTMENT ;
    PORT
      LAYER metal3 ;
      RECT 0.000 49.105 0.070 49.175 ;
    END
  END w_mask_in[341]
  PIN w_mask_in[342]
    DIRECTION INPUT ;
    USE SIGNAL ;
    SHAPE ABUTMENT ;
    PORT
      LAYER metal3 ;
      RECT 0.000 49.245 0.070 49.315 ;
    END
  END w_mask_in[342]
  PIN w_mask_in[343]
    DIRECTION INPUT ;
    USE SIGNAL ;
    SHAPE ABUTMENT ;
    PORT
      LAYER metal3 ;
      RECT 0.000 49.385 0.070 49.455 ;
    END
  END w_mask_in[343]
  PIN w_mask_in[344]
    DIRECTION INPUT ;
    USE SIGNAL ;
    SHAPE ABUTMENT ;
    PORT
      LAYER metal3 ;
      RECT 0.000 49.525 0.070 49.595 ;
    END
  END w_mask_in[344]
  PIN w_mask_in[345]
    DIRECTION INPUT ;
    USE SIGNAL ;
    SHAPE ABUTMENT ;
    PORT
      LAYER metal3 ;
      RECT 0.000 49.665 0.070 49.735 ;
    END
  END w_mask_in[345]
  PIN w_mask_in[346]
    DIRECTION INPUT ;
    USE SIGNAL ;
    SHAPE ABUTMENT ;
    PORT
      LAYER metal3 ;
      RECT 0.000 49.805 0.070 49.875 ;
    END
  END w_mask_in[346]
  PIN w_mask_in[347]
    DIRECTION INPUT ;
    USE SIGNAL ;
    SHAPE ABUTMENT ;
    PORT
      LAYER metal3 ;
      RECT 0.000 49.945 0.070 50.015 ;
    END
  END w_mask_in[347]
  PIN w_mask_in[348]
    DIRECTION INPUT ;
    USE SIGNAL ;
    SHAPE ABUTMENT ;
    PORT
      LAYER metal3 ;
      RECT 0.000 50.085 0.070 50.155 ;
    END
  END w_mask_in[348]
  PIN w_mask_in[349]
    DIRECTION INPUT ;
    USE SIGNAL ;
    SHAPE ABUTMENT ;
    PORT
      LAYER metal3 ;
      RECT 0.000 50.225 0.070 50.295 ;
    END
  END w_mask_in[349]
  PIN w_mask_in[350]
    DIRECTION INPUT ;
    USE SIGNAL ;
    SHAPE ABUTMENT ;
    PORT
      LAYER metal3 ;
      RECT 0.000 50.365 0.070 50.435 ;
    END
  END w_mask_in[350]
  PIN w_mask_in[351]
    DIRECTION INPUT ;
    USE SIGNAL ;
    SHAPE ABUTMENT ;
    PORT
      LAYER metal3 ;
      RECT 0.000 50.505 0.070 50.575 ;
    END
  END w_mask_in[351]
  PIN w_mask_in[352]
    DIRECTION INPUT ;
    USE SIGNAL ;
    SHAPE ABUTMENT ;
    PORT
      LAYER metal3 ;
      RECT 0.000 50.645 0.070 50.715 ;
    END
  END w_mask_in[352]
  PIN w_mask_in[353]
    DIRECTION INPUT ;
    USE SIGNAL ;
    SHAPE ABUTMENT ;
    PORT
      LAYER metal3 ;
      RECT 0.000 50.785 0.070 50.855 ;
    END
  END w_mask_in[353]
  PIN w_mask_in[354]
    DIRECTION INPUT ;
    USE SIGNAL ;
    SHAPE ABUTMENT ;
    PORT
      LAYER metal3 ;
      RECT 0.000 50.925 0.070 50.995 ;
    END
  END w_mask_in[354]
  PIN w_mask_in[355]
    DIRECTION INPUT ;
    USE SIGNAL ;
    SHAPE ABUTMENT ;
    PORT
      LAYER metal3 ;
      RECT 0.000 51.065 0.070 51.135 ;
    END
  END w_mask_in[355]
  PIN w_mask_in[356]
    DIRECTION INPUT ;
    USE SIGNAL ;
    SHAPE ABUTMENT ;
    PORT
      LAYER metal3 ;
      RECT 0.000 51.205 0.070 51.275 ;
    END
  END w_mask_in[356]
  PIN w_mask_in[357]
    DIRECTION INPUT ;
    USE SIGNAL ;
    SHAPE ABUTMENT ;
    PORT
      LAYER metal3 ;
      RECT 0.000 51.345 0.070 51.415 ;
    END
  END w_mask_in[357]
  PIN w_mask_in[358]
    DIRECTION INPUT ;
    USE SIGNAL ;
    SHAPE ABUTMENT ;
    PORT
      LAYER metal3 ;
      RECT 0.000 51.485 0.070 51.555 ;
    END
  END w_mask_in[358]
  PIN w_mask_in[359]
    DIRECTION INPUT ;
    USE SIGNAL ;
    SHAPE ABUTMENT ;
    PORT
      LAYER metal3 ;
      RECT 0.000 51.625 0.070 51.695 ;
    END
  END w_mask_in[359]
  PIN w_mask_in[360]
    DIRECTION INPUT ;
    USE SIGNAL ;
    SHAPE ABUTMENT ;
    PORT
      LAYER metal3 ;
      RECT 0.000 51.765 0.070 51.835 ;
    END
  END w_mask_in[360]
  PIN w_mask_in[361]
    DIRECTION INPUT ;
    USE SIGNAL ;
    SHAPE ABUTMENT ;
    PORT
      LAYER metal3 ;
      RECT 0.000 51.905 0.070 51.975 ;
    END
  END w_mask_in[361]
  PIN w_mask_in[362]
    DIRECTION INPUT ;
    USE SIGNAL ;
    SHAPE ABUTMENT ;
    PORT
      LAYER metal3 ;
      RECT 0.000 52.045 0.070 52.115 ;
    END
  END w_mask_in[362]
  PIN w_mask_in[363]
    DIRECTION INPUT ;
    USE SIGNAL ;
    SHAPE ABUTMENT ;
    PORT
      LAYER metal3 ;
      RECT 0.000 52.185 0.070 52.255 ;
    END
  END w_mask_in[363]
  PIN w_mask_in[364]
    DIRECTION INPUT ;
    USE SIGNAL ;
    SHAPE ABUTMENT ;
    PORT
      LAYER metal3 ;
      RECT 0.000 52.325 0.070 52.395 ;
    END
  END w_mask_in[364]
  PIN w_mask_in[365]
    DIRECTION INPUT ;
    USE SIGNAL ;
    SHAPE ABUTMENT ;
    PORT
      LAYER metal3 ;
      RECT 0.000 52.465 0.070 52.535 ;
    END
  END w_mask_in[365]
  PIN w_mask_in[366]
    DIRECTION INPUT ;
    USE SIGNAL ;
    SHAPE ABUTMENT ;
    PORT
      LAYER metal3 ;
      RECT 0.000 52.605 0.070 52.675 ;
    END
  END w_mask_in[366]
  PIN w_mask_in[367]
    DIRECTION INPUT ;
    USE SIGNAL ;
    SHAPE ABUTMENT ;
    PORT
      LAYER metal3 ;
      RECT 0.000 52.745 0.070 52.815 ;
    END
  END w_mask_in[367]
  PIN w_mask_in[368]
    DIRECTION INPUT ;
    USE SIGNAL ;
    SHAPE ABUTMENT ;
    PORT
      LAYER metal3 ;
      RECT 0.000 52.885 0.070 52.955 ;
    END
  END w_mask_in[368]
  PIN w_mask_in[369]
    DIRECTION INPUT ;
    USE SIGNAL ;
    SHAPE ABUTMENT ;
    PORT
      LAYER metal3 ;
      RECT 0.000 53.025 0.070 53.095 ;
    END
  END w_mask_in[369]
  PIN w_mask_in[370]
    DIRECTION INPUT ;
    USE SIGNAL ;
    SHAPE ABUTMENT ;
    PORT
      LAYER metal3 ;
      RECT 0.000 53.165 0.070 53.235 ;
    END
  END w_mask_in[370]
  PIN w_mask_in[371]
    DIRECTION INPUT ;
    USE SIGNAL ;
    SHAPE ABUTMENT ;
    PORT
      LAYER metal3 ;
      RECT 0.000 53.305 0.070 53.375 ;
    END
  END w_mask_in[371]
  PIN w_mask_in[372]
    DIRECTION INPUT ;
    USE SIGNAL ;
    SHAPE ABUTMENT ;
    PORT
      LAYER metal3 ;
      RECT 0.000 53.445 0.070 53.515 ;
    END
  END w_mask_in[372]
  PIN w_mask_in[373]
    DIRECTION INPUT ;
    USE SIGNAL ;
    SHAPE ABUTMENT ;
    PORT
      LAYER metal3 ;
      RECT 0.000 53.585 0.070 53.655 ;
    END
  END w_mask_in[373]
  PIN w_mask_in[374]
    DIRECTION INPUT ;
    USE SIGNAL ;
    SHAPE ABUTMENT ;
    PORT
      LAYER metal3 ;
      RECT 0.000 53.725 0.070 53.795 ;
    END
  END w_mask_in[374]
  PIN w_mask_in[375]
    DIRECTION INPUT ;
    USE SIGNAL ;
    SHAPE ABUTMENT ;
    PORT
      LAYER metal3 ;
      RECT 0.000 53.865 0.070 53.935 ;
    END
  END w_mask_in[375]
  PIN w_mask_in[376]
    DIRECTION INPUT ;
    USE SIGNAL ;
    SHAPE ABUTMENT ;
    PORT
      LAYER metal3 ;
      RECT 0.000 54.005 0.070 54.075 ;
    END
  END w_mask_in[376]
  PIN w_mask_in[377]
    DIRECTION INPUT ;
    USE SIGNAL ;
    SHAPE ABUTMENT ;
    PORT
      LAYER metal3 ;
      RECT 0.000 54.145 0.070 54.215 ;
    END
  END w_mask_in[377]
  PIN w_mask_in[378]
    DIRECTION INPUT ;
    USE SIGNAL ;
    SHAPE ABUTMENT ;
    PORT
      LAYER metal3 ;
      RECT 0.000 54.285 0.070 54.355 ;
    END
  END w_mask_in[378]
  PIN w_mask_in[379]
    DIRECTION INPUT ;
    USE SIGNAL ;
    SHAPE ABUTMENT ;
    PORT
      LAYER metal3 ;
      RECT 0.000 54.425 0.070 54.495 ;
    END
  END w_mask_in[379]
  PIN w_mask_in[380]
    DIRECTION INPUT ;
    USE SIGNAL ;
    SHAPE ABUTMENT ;
    PORT
      LAYER metal3 ;
      RECT 0.000 54.565 0.070 54.635 ;
    END
  END w_mask_in[380]
  PIN w_mask_in[381]
    DIRECTION INPUT ;
    USE SIGNAL ;
    SHAPE ABUTMENT ;
    PORT
      LAYER metal3 ;
      RECT 0.000 54.705 0.070 54.775 ;
    END
  END w_mask_in[381]
  PIN w_mask_in[382]
    DIRECTION INPUT ;
    USE SIGNAL ;
    SHAPE ABUTMENT ;
    PORT
      LAYER metal3 ;
      RECT 0.000 54.845 0.070 54.915 ;
    END
  END w_mask_in[382]
  PIN w_mask_in[383]
    DIRECTION INPUT ;
    USE SIGNAL ;
    SHAPE ABUTMENT ;
    PORT
      LAYER metal3 ;
      RECT 0.000 54.985 0.070 55.055 ;
    END
  END w_mask_in[383]
  PIN w_mask_in[384]
    DIRECTION INPUT ;
    USE SIGNAL ;
    SHAPE ABUTMENT ;
    PORT
      LAYER metal3 ;
      RECT 0.000 55.125 0.070 55.195 ;
    END
  END w_mask_in[384]
  PIN w_mask_in[385]
    DIRECTION INPUT ;
    USE SIGNAL ;
    SHAPE ABUTMENT ;
    PORT
      LAYER metal3 ;
      RECT 0.000 55.265 0.070 55.335 ;
    END
  END w_mask_in[385]
  PIN w_mask_in[386]
    DIRECTION INPUT ;
    USE SIGNAL ;
    SHAPE ABUTMENT ;
    PORT
      LAYER metal3 ;
      RECT 0.000 55.405 0.070 55.475 ;
    END
  END w_mask_in[386]
  PIN w_mask_in[387]
    DIRECTION INPUT ;
    USE SIGNAL ;
    SHAPE ABUTMENT ;
    PORT
      LAYER metal3 ;
      RECT 0.000 55.545 0.070 55.615 ;
    END
  END w_mask_in[387]
  PIN w_mask_in[388]
    DIRECTION INPUT ;
    USE SIGNAL ;
    SHAPE ABUTMENT ;
    PORT
      LAYER metal3 ;
      RECT 0.000 55.685 0.070 55.755 ;
    END
  END w_mask_in[388]
  PIN w_mask_in[389]
    DIRECTION INPUT ;
    USE SIGNAL ;
    SHAPE ABUTMENT ;
    PORT
      LAYER metal3 ;
      RECT 0.000 55.825 0.070 55.895 ;
    END
  END w_mask_in[389]
  PIN w_mask_in[390]
    DIRECTION INPUT ;
    USE SIGNAL ;
    SHAPE ABUTMENT ;
    PORT
      LAYER metal3 ;
      RECT 0.000 55.965 0.070 56.035 ;
    END
  END w_mask_in[390]
  PIN w_mask_in[391]
    DIRECTION INPUT ;
    USE SIGNAL ;
    SHAPE ABUTMENT ;
    PORT
      LAYER metal3 ;
      RECT 0.000 56.105 0.070 56.175 ;
    END
  END w_mask_in[391]
  PIN w_mask_in[392]
    DIRECTION INPUT ;
    USE SIGNAL ;
    SHAPE ABUTMENT ;
    PORT
      LAYER metal3 ;
      RECT 0.000 56.245 0.070 56.315 ;
    END
  END w_mask_in[392]
  PIN w_mask_in[393]
    DIRECTION INPUT ;
    USE SIGNAL ;
    SHAPE ABUTMENT ;
    PORT
      LAYER metal3 ;
      RECT 0.000 56.385 0.070 56.455 ;
    END
  END w_mask_in[393]
  PIN w_mask_in[394]
    DIRECTION INPUT ;
    USE SIGNAL ;
    SHAPE ABUTMENT ;
    PORT
      LAYER metal3 ;
      RECT 0.000 56.525 0.070 56.595 ;
    END
  END w_mask_in[394]
  PIN w_mask_in[395]
    DIRECTION INPUT ;
    USE SIGNAL ;
    SHAPE ABUTMENT ;
    PORT
      LAYER metal3 ;
      RECT 0.000 56.665 0.070 56.735 ;
    END
  END w_mask_in[395]
  PIN w_mask_in[396]
    DIRECTION INPUT ;
    USE SIGNAL ;
    SHAPE ABUTMENT ;
    PORT
      LAYER metal3 ;
      RECT 0.000 56.805 0.070 56.875 ;
    END
  END w_mask_in[396]
  PIN w_mask_in[397]
    DIRECTION INPUT ;
    USE SIGNAL ;
    SHAPE ABUTMENT ;
    PORT
      LAYER metal3 ;
      RECT 0.000 56.945 0.070 57.015 ;
    END
  END w_mask_in[397]
  PIN w_mask_in[398]
    DIRECTION INPUT ;
    USE SIGNAL ;
    SHAPE ABUTMENT ;
    PORT
      LAYER metal3 ;
      RECT 0.000 57.085 0.070 57.155 ;
    END
  END w_mask_in[398]
  PIN w_mask_in[399]
    DIRECTION INPUT ;
    USE SIGNAL ;
    SHAPE ABUTMENT ;
    PORT
      LAYER metal3 ;
      RECT 0.000 57.225 0.070 57.295 ;
    END
  END w_mask_in[399]
  PIN w_mask_in[400]
    DIRECTION INPUT ;
    USE SIGNAL ;
    SHAPE ABUTMENT ;
    PORT
      LAYER metal3 ;
      RECT 0.000 57.365 0.070 57.435 ;
    END
  END w_mask_in[400]
  PIN w_mask_in[401]
    DIRECTION INPUT ;
    USE SIGNAL ;
    SHAPE ABUTMENT ;
    PORT
      LAYER metal3 ;
      RECT 0.000 57.505 0.070 57.575 ;
    END
  END w_mask_in[401]
  PIN w_mask_in[402]
    DIRECTION INPUT ;
    USE SIGNAL ;
    SHAPE ABUTMENT ;
    PORT
      LAYER metal3 ;
      RECT 0.000 57.645 0.070 57.715 ;
    END
  END w_mask_in[402]
  PIN w_mask_in[403]
    DIRECTION INPUT ;
    USE SIGNAL ;
    SHAPE ABUTMENT ;
    PORT
      LAYER metal3 ;
      RECT 0.000 57.785 0.070 57.855 ;
    END
  END w_mask_in[403]
  PIN w_mask_in[404]
    DIRECTION INPUT ;
    USE SIGNAL ;
    SHAPE ABUTMENT ;
    PORT
      LAYER metal3 ;
      RECT 0.000 57.925 0.070 57.995 ;
    END
  END w_mask_in[404]
  PIN w_mask_in[405]
    DIRECTION INPUT ;
    USE SIGNAL ;
    SHAPE ABUTMENT ;
    PORT
      LAYER metal3 ;
      RECT 0.000 58.065 0.070 58.135 ;
    END
  END w_mask_in[405]
  PIN w_mask_in[406]
    DIRECTION INPUT ;
    USE SIGNAL ;
    SHAPE ABUTMENT ;
    PORT
      LAYER metal3 ;
      RECT 0.000 58.205 0.070 58.275 ;
    END
  END w_mask_in[406]
  PIN w_mask_in[407]
    DIRECTION INPUT ;
    USE SIGNAL ;
    SHAPE ABUTMENT ;
    PORT
      LAYER metal3 ;
      RECT 0.000 58.345 0.070 58.415 ;
    END
  END w_mask_in[407]
  PIN w_mask_in[408]
    DIRECTION INPUT ;
    USE SIGNAL ;
    SHAPE ABUTMENT ;
    PORT
      LAYER metal3 ;
      RECT 0.000 58.485 0.070 58.555 ;
    END
  END w_mask_in[408]
  PIN w_mask_in[409]
    DIRECTION INPUT ;
    USE SIGNAL ;
    SHAPE ABUTMENT ;
    PORT
      LAYER metal3 ;
      RECT 0.000 58.625 0.070 58.695 ;
    END
  END w_mask_in[409]
  PIN w_mask_in[410]
    DIRECTION INPUT ;
    USE SIGNAL ;
    SHAPE ABUTMENT ;
    PORT
      LAYER metal3 ;
      RECT 0.000 58.765 0.070 58.835 ;
    END
  END w_mask_in[410]
  PIN w_mask_in[411]
    DIRECTION INPUT ;
    USE SIGNAL ;
    SHAPE ABUTMENT ;
    PORT
      LAYER metal3 ;
      RECT 0.000 58.905 0.070 58.975 ;
    END
  END w_mask_in[411]
  PIN w_mask_in[412]
    DIRECTION INPUT ;
    USE SIGNAL ;
    SHAPE ABUTMENT ;
    PORT
      LAYER metal3 ;
      RECT 0.000 59.045 0.070 59.115 ;
    END
  END w_mask_in[412]
  PIN w_mask_in[413]
    DIRECTION INPUT ;
    USE SIGNAL ;
    SHAPE ABUTMENT ;
    PORT
      LAYER metal3 ;
      RECT 0.000 59.185 0.070 59.255 ;
    END
  END w_mask_in[413]
  PIN w_mask_in[414]
    DIRECTION INPUT ;
    USE SIGNAL ;
    SHAPE ABUTMENT ;
    PORT
      LAYER metal3 ;
      RECT 0.000 59.325 0.070 59.395 ;
    END
  END w_mask_in[414]
  PIN w_mask_in[415]
    DIRECTION INPUT ;
    USE SIGNAL ;
    SHAPE ABUTMENT ;
    PORT
      LAYER metal3 ;
      RECT 0.000 59.465 0.070 59.535 ;
    END
  END w_mask_in[415]
  PIN w_mask_in[416]
    DIRECTION INPUT ;
    USE SIGNAL ;
    SHAPE ABUTMENT ;
    PORT
      LAYER metal3 ;
      RECT 0.000 59.605 0.070 59.675 ;
    END
  END w_mask_in[416]
  PIN w_mask_in[417]
    DIRECTION INPUT ;
    USE SIGNAL ;
    SHAPE ABUTMENT ;
    PORT
      LAYER metal3 ;
      RECT 0.000 59.745 0.070 59.815 ;
    END
  END w_mask_in[417]
  PIN w_mask_in[418]
    DIRECTION INPUT ;
    USE SIGNAL ;
    SHAPE ABUTMENT ;
    PORT
      LAYER metal3 ;
      RECT 0.000 59.885 0.070 59.955 ;
    END
  END w_mask_in[418]
  PIN w_mask_in[419]
    DIRECTION INPUT ;
    USE SIGNAL ;
    SHAPE ABUTMENT ;
    PORT
      LAYER metal3 ;
      RECT 0.000 60.025 0.070 60.095 ;
    END
  END w_mask_in[419]
  PIN w_mask_in[420]
    DIRECTION INPUT ;
    USE SIGNAL ;
    SHAPE ABUTMENT ;
    PORT
      LAYER metal3 ;
      RECT 0.000 60.165 0.070 60.235 ;
    END
  END w_mask_in[420]
  PIN w_mask_in[421]
    DIRECTION INPUT ;
    USE SIGNAL ;
    SHAPE ABUTMENT ;
    PORT
      LAYER metal3 ;
      RECT 0.000 60.305 0.070 60.375 ;
    END
  END w_mask_in[421]
  PIN w_mask_in[422]
    DIRECTION INPUT ;
    USE SIGNAL ;
    SHAPE ABUTMENT ;
    PORT
      LAYER metal3 ;
      RECT 0.000 60.445 0.070 60.515 ;
    END
  END w_mask_in[422]
  PIN w_mask_in[423]
    DIRECTION INPUT ;
    USE SIGNAL ;
    SHAPE ABUTMENT ;
    PORT
      LAYER metal3 ;
      RECT 0.000 60.585 0.070 60.655 ;
    END
  END w_mask_in[423]
  PIN w_mask_in[424]
    DIRECTION INPUT ;
    USE SIGNAL ;
    SHAPE ABUTMENT ;
    PORT
      LAYER metal3 ;
      RECT 0.000 60.725 0.070 60.795 ;
    END
  END w_mask_in[424]
  PIN w_mask_in[425]
    DIRECTION INPUT ;
    USE SIGNAL ;
    SHAPE ABUTMENT ;
    PORT
      LAYER metal3 ;
      RECT 0.000 60.865 0.070 60.935 ;
    END
  END w_mask_in[425]
  PIN w_mask_in[426]
    DIRECTION INPUT ;
    USE SIGNAL ;
    SHAPE ABUTMENT ;
    PORT
      LAYER metal3 ;
      RECT 0.000 61.005 0.070 61.075 ;
    END
  END w_mask_in[426]
  PIN w_mask_in[427]
    DIRECTION INPUT ;
    USE SIGNAL ;
    SHAPE ABUTMENT ;
    PORT
      LAYER metal3 ;
      RECT 0.000 61.145 0.070 61.215 ;
    END
  END w_mask_in[427]
  PIN w_mask_in[428]
    DIRECTION INPUT ;
    USE SIGNAL ;
    SHAPE ABUTMENT ;
    PORT
      LAYER metal3 ;
      RECT 0.000 61.285 0.070 61.355 ;
    END
  END w_mask_in[428]
  PIN w_mask_in[429]
    DIRECTION INPUT ;
    USE SIGNAL ;
    SHAPE ABUTMENT ;
    PORT
      LAYER metal3 ;
      RECT 0.000 61.425 0.070 61.495 ;
    END
  END w_mask_in[429]
  PIN w_mask_in[430]
    DIRECTION INPUT ;
    USE SIGNAL ;
    SHAPE ABUTMENT ;
    PORT
      LAYER metal3 ;
      RECT 0.000 61.565 0.070 61.635 ;
    END
  END w_mask_in[430]
  PIN w_mask_in[431]
    DIRECTION INPUT ;
    USE SIGNAL ;
    SHAPE ABUTMENT ;
    PORT
      LAYER metal3 ;
      RECT 0.000 61.705 0.070 61.775 ;
    END
  END w_mask_in[431]
  PIN w_mask_in[432]
    DIRECTION INPUT ;
    USE SIGNAL ;
    SHAPE ABUTMENT ;
    PORT
      LAYER metal3 ;
      RECT 0.000 61.845 0.070 61.915 ;
    END
  END w_mask_in[432]
  PIN w_mask_in[433]
    DIRECTION INPUT ;
    USE SIGNAL ;
    SHAPE ABUTMENT ;
    PORT
      LAYER metal3 ;
      RECT 0.000 61.985 0.070 62.055 ;
    END
  END w_mask_in[433]
  PIN w_mask_in[434]
    DIRECTION INPUT ;
    USE SIGNAL ;
    SHAPE ABUTMENT ;
    PORT
      LAYER metal3 ;
      RECT 0.000 62.125 0.070 62.195 ;
    END
  END w_mask_in[434]
  PIN w_mask_in[435]
    DIRECTION INPUT ;
    USE SIGNAL ;
    SHAPE ABUTMENT ;
    PORT
      LAYER metal3 ;
      RECT 0.000 62.265 0.070 62.335 ;
    END
  END w_mask_in[435]
  PIN w_mask_in[436]
    DIRECTION INPUT ;
    USE SIGNAL ;
    SHAPE ABUTMENT ;
    PORT
      LAYER metal3 ;
      RECT 0.000 62.405 0.070 62.475 ;
    END
  END w_mask_in[436]
  PIN w_mask_in[437]
    DIRECTION INPUT ;
    USE SIGNAL ;
    SHAPE ABUTMENT ;
    PORT
      LAYER metal3 ;
      RECT 0.000 62.545 0.070 62.615 ;
    END
  END w_mask_in[437]
  PIN w_mask_in[438]
    DIRECTION INPUT ;
    USE SIGNAL ;
    SHAPE ABUTMENT ;
    PORT
      LAYER metal3 ;
      RECT 0.000 62.685 0.070 62.755 ;
    END
  END w_mask_in[438]
  PIN w_mask_in[439]
    DIRECTION INPUT ;
    USE SIGNAL ;
    SHAPE ABUTMENT ;
    PORT
      LAYER metal3 ;
      RECT 0.000 62.825 0.070 62.895 ;
    END
  END w_mask_in[439]
  PIN w_mask_in[440]
    DIRECTION INPUT ;
    USE SIGNAL ;
    SHAPE ABUTMENT ;
    PORT
      LAYER metal3 ;
      RECT 0.000 62.965 0.070 63.035 ;
    END
  END w_mask_in[440]
  PIN w_mask_in[441]
    DIRECTION INPUT ;
    USE SIGNAL ;
    SHAPE ABUTMENT ;
    PORT
      LAYER metal3 ;
      RECT 0.000 63.105 0.070 63.175 ;
    END
  END w_mask_in[441]
  PIN w_mask_in[442]
    DIRECTION INPUT ;
    USE SIGNAL ;
    SHAPE ABUTMENT ;
    PORT
      LAYER metal3 ;
      RECT 0.000 63.245 0.070 63.315 ;
    END
  END w_mask_in[442]
  PIN w_mask_in[443]
    DIRECTION INPUT ;
    USE SIGNAL ;
    SHAPE ABUTMENT ;
    PORT
      LAYER metal3 ;
      RECT 0.000 63.385 0.070 63.455 ;
    END
  END w_mask_in[443]
  PIN w_mask_in[444]
    DIRECTION INPUT ;
    USE SIGNAL ;
    SHAPE ABUTMENT ;
    PORT
      LAYER metal3 ;
      RECT 0.000 63.525 0.070 63.595 ;
    END
  END w_mask_in[444]
  PIN w_mask_in[445]
    DIRECTION INPUT ;
    USE SIGNAL ;
    SHAPE ABUTMENT ;
    PORT
      LAYER metal3 ;
      RECT 0.000 63.665 0.070 63.735 ;
    END
  END w_mask_in[445]
  PIN w_mask_in[446]
    DIRECTION INPUT ;
    USE SIGNAL ;
    SHAPE ABUTMENT ;
    PORT
      LAYER metal3 ;
      RECT 0.000 63.805 0.070 63.875 ;
    END
  END w_mask_in[446]
  PIN w_mask_in[447]
    DIRECTION INPUT ;
    USE SIGNAL ;
    SHAPE ABUTMENT ;
    PORT
      LAYER metal3 ;
      RECT 0.000 63.945 0.070 64.015 ;
    END
  END w_mask_in[447]
  PIN w_mask_in[448]
    DIRECTION INPUT ;
    USE SIGNAL ;
    SHAPE ABUTMENT ;
    PORT
      LAYER metal3 ;
      RECT 0.000 64.085 0.070 64.155 ;
    END
  END w_mask_in[448]
  PIN w_mask_in[449]
    DIRECTION INPUT ;
    USE SIGNAL ;
    SHAPE ABUTMENT ;
    PORT
      LAYER metal3 ;
      RECT 0.000 64.225 0.070 64.295 ;
    END
  END w_mask_in[449]
  PIN w_mask_in[450]
    DIRECTION INPUT ;
    USE SIGNAL ;
    SHAPE ABUTMENT ;
    PORT
      LAYER metal3 ;
      RECT 0.000 64.365 0.070 64.435 ;
    END
  END w_mask_in[450]
  PIN w_mask_in[451]
    DIRECTION INPUT ;
    USE SIGNAL ;
    SHAPE ABUTMENT ;
    PORT
      LAYER metal3 ;
      RECT 0.000 64.505 0.070 64.575 ;
    END
  END w_mask_in[451]
  PIN w_mask_in[452]
    DIRECTION INPUT ;
    USE SIGNAL ;
    SHAPE ABUTMENT ;
    PORT
      LAYER metal3 ;
      RECT 0.000 64.645 0.070 64.715 ;
    END
  END w_mask_in[452]
  PIN w_mask_in[453]
    DIRECTION INPUT ;
    USE SIGNAL ;
    SHAPE ABUTMENT ;
    PORT
      LAYER metal3 ;
      RECT 0.000 64.785 0.070 64.855 ;
    END
  END w_mask_in[453]
  PIN w_mask_in[454]
    DIRECTION INPUT ;
    USE SIGNAL ;
    SHAPE ABUTMENT ;
    PORT
      LAYER metal3 ;
      RECT 0.000 64.925 0.070 64.995 ;
    END
  END w_mask_in[454]
  PIN w_mask_in[455]
    DIRECTION INPUT ;
    USE SIGNAL ;
    SHAPE ABUTMENT ;
    PORT
      LAYER metal3 ;
      RECT 0.000 65.065 0.070 65.135 ;
    END
  END w_mask_in[455]
  PIN w_mask_in[456]
    DIRECTION INPUT ;
    USE SIGNAL ;
    SHAPE ABUTMENT ;
    PORT
      LAYER metal3 ;
      RECT 0.000 65.205 0.070 65.275 ;
    END
  END w_mask_in[456]
  PIN w_mask_in[457]
    DIRECTION INPUT ;
    USE SIGNAL ;
    SHAPE ABUTMENT ;
    PORT
      LAYER metal3 ;
      RECT 0.000 65.345 0.070 65.415 ;
    END
  END w_mask_in[457]
  PIN w_mask_in[458]
    DIRECTION INPUT ;
    USE SIGNAL ;
    SHAPE ABUTMENT ;
    PORT
      LAYER metal3 ;
      RECT 0.000 65.485 0.070 65.555 ;
    END
  END w_mask_in[458]
  PIN w_mask_in[459]
    DIRECTION INPUT ;
    USE SIGNAL ;
    SHAPE ABUTMENT ;
    PORT
      LAYER metal3 ;
      RECT 0.000 65.625 0.070 65.695 ;
    END
  END w_mask_in[459]
  PIN w_mask_in[460]
    DIRECTION INPUT ;
    USE SIGNAL ;
    SHAPE ABUTMENT ;
    PORT
      LAYER metal3 ;
      RECT 0.000 65.765 0.070 65.835 ;
    END
  END w_mask_in[460]
  PIN w_mask_in[461]
    DIRECTION INPUT ;
    USE SIGNAL ;
    SHAPE ABUTMENT ;
    PORT
      LAYER metal3 ;
      RECT 0.000 65.905 0.070 65.975 ;
    END
  END w_mask_in[461]
  PIN w_mask_in[462]
    DIRECTION INPUT ;
    USE SIGNAL ;
    SHAPE ABUTMENT ;
    PORT
      LAYER metal3 ;
      RECT 0.000 66.045 0.070 66.115 ;
    END
  END w_mask_in[462]
  PIN w_mask_in[463]
    DIRECTION INPUT ;
    USE SIGNAL ;
    SHAPE ABUTMENT ;
    PORT
      LAYER metal3 ;
      RECT 0.000 66.185 0.070 66.255 ;
    END
  END w_mask_in[463]
  PIN w_mask_in[464]
    DIRECTION INPUT ;
    USE SIGNAL ;
    SHAPE ABUTMENT ;
    PORT
      LAYER metal3 ;
      RECT 0.000 66.325 0.070 66.395 ;
    END
  END w_mask_in[464]
  PIN w_mask_in[465]
    DIRECTION INPUT ;
    USE SIGNAL ;
    SHAPE ABUTMENT ;
    PORT
      LAYER metal3 ;
      RECT 0.000 66.465 0.070 66.535 ;
    END
  END w_mask_in[465]
  PIN w_mask_in[466]
    DIRECTION INPUT ;
    USE SIGNAL ;
    SHAPE ABUTMENT ;
    PORT
      LAYER metal3 ;
      RECT 0.000 66.605 0.070 66.675 ;
    END
  END w_mask_in[466]
  PIN w_mask_in[467]
    DIRECTION INPUT ;
    USE SIGNAL ;
    SHAPE ABUTMENT ;
    PORT
      LAYER metal3 ;
      RECT 0.000 66.745 0.070 66.815 ;
    END
  END w_mask_in[467]
  PIN w_mask_in[468]
    DIRECTION INPUT ;
    USE SIGNAL ;
    SHAPE ABUTMENT ;
    PORT
      LAYER metal3 ;
      RECT 0.000 66.885 0.070 66.955 ;
    END
  END w_mask_in[468]
  PIN w_mask_in[469]
    DIRECTION INPUT ;
    USE SIGNAL ;
    SHAPE ABUTMENT ;
    PORT
      LAYER metal3 ;
      RECT 0.000 67.025 0.070 67.095 ;
    END
  END w_mask_in[469]
  PIN w_mask_in[470]
    DIRECTION INPUT ;
    USE SIGNAL ;
    SHAPE ABUTMENT ;
    PORT
      LAYER metal3 ;
      RECT 0.000 67.165 0.070 67.235 ;
    END
  END w_mask_in[470]
  PIN w_mask_in[471]
    DIRECTION INPUT ;
    USE SIGNAL ;
    SHAPE ABUTMENT ;
    PORT
      LAYER metal3 ;
      RECT 0.000 67.305 0.070 67.375 ;
    END
  END w_mask_in[471]
  PIN w_mask_in[472]
    DIRECTION INPUT ;
    USE SIGNAL ;
    SHAPE ABUTMENT ;
    PORT
      LAYER metal3 ;
      RECT 0.000 67.445 0.070 67.515 ;
    END
  END w_mask_in[472]
  PIN w_mask_in[473]
    DIRECTION INPUT ;
    USE SIGNAL ;
    SHAPE ABUTMENT ;
    PORT
      LAYER metal3 ;
      RECT 0.000 67.585 0.070 67.655 ;
    END
  END w_mask_in[473]
  PIN w_mask_in[474]
    DIRECTION INPUT ;
    USE SIGNAL ;
    SHAPE ABUTMENT ;
    PORT
      LAYER metal3 ;
      RECT 0.000 67.725 0.070 67.795 ;
    END
  END w_mask_in[474]
  PIN w_mask_in[475]
    DIRECTION INPUT ;
    USE SIGNAL ;
    SHAPE ABUTMENT ;
    PORT
      LAYER metal3 ;
      RECT 0.000 67.865 0.070 67.935 ;
    END
  END w_mask_in[475]
  PIN w_mask_in[476]
    DIRECTION INPUT ;
    USE SIGNAL ;
    SHAPE ABUTMENT ;
    PORT
      LAYER metal3 ;
      RECT 0.000 68.005 0.070 68.075 ;
    END
  END w_mask_in[476]
  PIN w_mask_in[477]
    DIRECTION INPUT ;
    USE SIGNAL ;
    SHAPE ABUTMENT ;
    PORT
      LAYER metal3 ;
      RECT 0.000 68.145 0.070 68.215 ;
    END
  END w_mask_in[477]
  PIN w_mask_in[478]
    DIRECTION INPUT ;
    USE SIGNAL ;
    SHAPE ABUTMENT ;
    PORT
      LAYER metal3 ;
      RECT 0.000 68.285 0.070 68.355 ;
    END
  END w_mask_in[478]
  PIN w_mask_in[479]
    DIRECTION INPUT ;
    USE SIGNAL ;
    SHAPE ABUTMENT ;
    PORT
      LAYER metal3 ;
      RECT 0.000 68.425 0.070 68.495 ;
    END
  END w_mask_in[479]
  PIN w_mask_in[480]
    DIRECTION INPUT ;
    USE SIGNAL ;
    SHAPE ABUTMENT ;
    PORT
      LAYER metal3 ;
      RECT 0.000 68.565 0.070 68.635 ;
    END
  END w_mask_in[480]
  PIN w_mask_in[481]
    DIRECTION INPUT ;
    USE SIGNAL ;
    SHAPE ABUTMENT ;
    PORT
      LAYER metal3 ;
      RECT 0.000 68.705 0.070 68.775 ;
    END
  END w_mask_in[481]
  PIN w_mask_in[482]
    DIRECTION INPUT ;
    USE SIGNAL ;
    SHAPE ABUTMENT ;
    PORT
      LAYER metal3 ;
      RECT 0.000 68.845 0.070 68.915 ;
    END
  END w_mask_in[482]
  PIN w_mask_in[483]
    DIRECTION INPUT ;
    USE SIGNAL ;
    SHAPE ABUTMENT ;
    PORT
      LAYER metal3 ;
      RECT 0.000 68.985 0.070 69.055 ;
    END
  END w_mask_in[483]
  PIN w_mask_in[484]
    DIRECTION INPUT ;
    USE SIGNAL ;
    SHAPE ABUTMENT ;
    PORT
      LAYER metal3 ;
      RECT 0.000 69.125 0.070 69.195 ;
    END
  END w_mask_in[484]
  PIN w_mask_in[485]
    DIRECTION INPUT ;
    USE SIGNAL ;
    SHAPE ABUTMENT ;
    PORT
      LAYER metal3 ;
      RECT 0.000 69.265 0.070 69.335 ;
    END
  END w_mask_in[485]
  PIN w_mask_in[486]
    DIRECTION INPUT ;
    USE SIGNAL ;
    SHAPE ABUTMENT ;
    PORT
      LAYER metal3 ;
      RECT 0.000 69.405 0.070 69.475 ;
    END
  END w_mask_in[486]
  PIN w_mask_in[487]
    DIRECTION INPUT ;
    USE SIGNAL ;
    SHAPE ABUTMENT ;
    PORT
      LAYER metal3 ;
      RECT 0.000 69.545 0.070 69.615 ;
    END
  END w_mask_in[487]
  PIN w_mask_in[488]
    DIRECTION INPUT ;
    USE SIGNAL ;
    SHAPE ABUTMENT ;
    PORT
      LAYER metal3 ;
      RECT 0.000 69.685 0.070 69.755 ;
    END
  END w_mask_in[488]
  PIN w_mask_in[489]
    DIRECTION INPUT ;
    USE SIGNAL ;
    SHAPE ABUTMENT ;
    PORT
      LAYER metal3 ;
      RECT 0.000 69.825 0.070 69.895 ;
    END
  END w_mask_in[489]
  PIN w_mask_in[490]
    DIRECTION INPUT ;
    USE SIGNAL ;
    SHAPE ABUTMENT ;
    PORT
      LAYER metal3 ;
      RECT 0.000 69.965 0.070 70.035 ;
    END
  END w_mask_in[490]
  PIN w_mask_in[491]
    DIRECTION INPUT ;
    USE SIGNAL ;
    SHAPE ABUTMENT ;
    PORT
      LAYER metal3 ;
      RECT 0.000 70.105 0.070 70.175 ;
    END
  END w_mask_in[491]
  PIN w_mask_in[492]
    DIRECTION INPUT ;
    USE SIGNAL ;
    SHAPE ABUTMENT ;
    PORT
      LAYER metal3 ;
      RECT 0.000 70.245 0.070 70.315 ;
    END
  END w_mask_in[492]
  PIN w_mask_in[493]
    DIRECTION INPUT ;
    USE SIGNAL ;
    SHAPE ABUTMENT ;
    PORT
      LAYER metal3 ;
      RECT 0.000 70.385 0.070 70.455 ;
    END
  END w_mask_in[493]
  PIN w_mask_in[494]
    DIRECTION INPUT ;
    USE SIGNAL ;
    SHAPE ABUTMENT ;
    PORT
      LAYER metal3 ;
      RECT 0.000 70.525 0.070 70.595 ;
    END
  END w_mask_in[494]
  PIN w_mask_in[495]
    DIRECTION INPUT ;
    USE SIGNAL ;
    SHAPE ABUTMENT ;
    PORT
      LAYER metal3 ;
      RECT 0.000 70.665 0.070 70.735 ;
    END
  END w_mask_in[495]
  PIN w_mask_in[496]
    DIRECTION INPUT ;
    USE SIGNAL ;
    SHAPE ABUTMENT ;
    PORT
      LAYER metal3 ;
      RECT 0.000 70.805 0.070 70.875 ;
    END
  END w_mask_in[496]
  PIN w_mask_in[497]
    DIRECTION INPUT ;
    USE SIGNAL ;
    SHAPE ABUTMENT ;
    PORT
      LAYER metal3 ;
      RECT 0.000 70.945 0.070 71.015 ;
    END
  END w_mask_in[497]
  PIN w_mask_in[498]
    DIRECTION INPUT ;
    USE SIGNAL ;
    SHAPE ABUTMENT ;
    PORT
      LAYER metal3 ;
      RECT 0.000 71.085 0.070 71.155 ;
    END
  END w_mask_in[498]
  PIN w_mask_in[499]
    DIRECTION INPUT ;
    USE SIGNAL ;
    SHAPE ABUTMENT ;
    PORT
      LAYER metal3 ;
      RECT 0.000 71.225 0.070 71.295 ;
    END
  END w_mask_in[499]
  PIN w_mask_in[500]
    DIRECTION INPUT ;
    USE SIGNAL ;
    SHAPE ABUTMENT ;
    PORT
      LAYER metal3 ;
      RECT 0.000 71.365 0.070 71.435 ;
    END
  END w_mask_in[500]
  PIN w_mask_in[501]
    DIRECTION INPUT ;
    USE SIGNAL ;
    SHAPE ABUTMENT ;
    PORT
      LAYER metal3 ;
      RECT 0.000 71.505 0.070 71.575 ;
    END
  END w_mask_in[501]
  PIN w_mask_in[502]
    DIRECTION INPUT ;
    USE SIGNAL ;
    SHAPE ABUTMENT ;
    PORT
      LAYER metal3 ;
      RECT 0.000 71.645 0.070 71.715 ;
    END
  END w_mask_in[502]
  PIN w_mask_in[503]
    DIRECTION INPUT ;
    USE SIGNAL ;
    SHAPE ABUTMENT ;
    PORT
      LAYER metal3 ;
      RECT 0.000 71.785 0.070 71.855 ;
    END
  END w_mask_in[503]
  PIN w_mask_in[504]
    DIRECTION INPUT ;
    USE SIGNAL ;
    SHAPE ABUTMENT ;
    PORT
      LAYER metal3 ;
      RECT 0.000 71.925 0.070 71.995 ;
    END
  END w_mask_in[504]
  PIN w_mask_in[505]
    DIRECTION INPUT ;
    USE SIGNAL ;
    SHAPE ABUTMENT ;
    PORT
      LAYER metal3 ;
      RECT 0.000 72.065 0.070 72.135 ;
    END
  END w_mask_in[505]
  PIN w_mask_in[506]
    DIRECTION INPUT ;
    USE SIGNAL ;
    SHAPE ABUTMENT ;
    PORT
      LAYER metal3 ;
      RECT 0.000 72.205 0.070 72.275 ;
    END
  END w_mask_in[506]
  PIN w_mask_in[507]
    DIRECTION INPUT ;
    USE SIGNAL ;
    SHAPE ABUTMENT ;
    PORT
      LAYER metal3 ;
      RECT 0.000 72.345 0.070 72.415 ;
    END
  END w_mask_in[507]
  PIN w_mask_in[508]
    DIRECTION INPUT ;
    USE SIGNAL ;
    SHAPE ABUTMENT ;
    PORT
      LAYER metal3 ;
      RECT 0.000 72.485 0.070 72.555 ;
    END
  END w_mask_in[508]
  PIN w_mask_in[509]
    DIRECTION INPUT ;
    USE SIGNAL ;
    SHAPE ABUTMENT ;
    PORT
      LAYER metal3 ;
      RECT 0.000 72.625 0.070 72.695 ;
    END
  END w_mask_in[509]
  PIN w_mask_in[510]
    DIRECTION INPUT ;
    USE SIGNAL ;
    SHAPE ABUTMENT ;
    PORT
      LAYER metal3 ;
      RECT 0.000 72.765 0.070 72.835 ;
    END
  END w_mask_in[510]
  PIN w_mask_in[511]
    DIRECTION INPUT ;
    USE SIGNAL ;
    SHAPE ABUTMENT ;
    PORT
      LAYER metal3 ;
      RECT 0.000 72.905 0.070 72.975 ;
    END
  END w_mask_in[511]
  PIN rd_out[0]
    DIRECTION OUTPUT ;
    USE SIGNAL ;
    SHAPE ABUTMENT ;
    PORT
      LAYER metal3 ;
      RECT 0.000 101.325 0.070 101.395 ;
    END
  END rd_out[0]
  PIN rd_out[1]
    DIRECTION OUTPUT ;
    USE SIGNAL ;
    SHAPE ABUTMENT ;
    PORT
      LAYER metal3 ;
      RECT 0.000 101.465 0.070 101.535 ;
    END
  END rd_out[1]
  PIN rd_out[2]
    DIRECTION OUTPUT ;
    USE SIGNAL ;
    SHAPE ABUTMENT ;
    PORT
      LAYER metal3 ;
      RECT 0.000 101.605 0.070 101.675 ;
    END
  END rd_out[2]
  PIN rd_out[3]
    DIRECTION OUTPUT ;
    USE SIGNAL ;
    SHAPE ABUTMENT ;
    PORT
      LAYER metal3 ;
      RECT 0.000 101.745 0.070 101.815 ;
    END
  END rd_out[3]
  PIN rd_out[4]
    DIRECTION OUTPUT ;
    USE SIGNAL ;
    SHAPE ABUTMENT ;
    PORT
      LAYER metal3 ;
      RECT 0.000 101.885 0.070 101.955 ;
    END
  END rd_out[4]
  PIN rd_out[5]
    DIRECTION OUTPUT ;
    USE SIGNAL ;
    SHAPE ABUTMENT ;
    PORT
      LAYER metal3 ;
      RECT 0.000 102.025 0.070 102.095 ;
    END
  END rd_out[5]
  PIN rd_out[6]
    DIRECTION OUTPUT ;
    USE SIGNAL ;
    SHAPE ABUTMENT ;
    PORT
      LAYER metal3 ;
      RECT 0.000 102.165 0.070 102.235 ;
    END
  END rd_out[6]
  PIN rd_out[7]
    DIRECTION OUTPUT ;
    USE SIGNAL ;
    SHAPE ABUTMENT ;
    PORT
      LAYER metal3 ;
      RECT 0.000 102.305 0.070 102.375 ;
    END
  END rd_out[7]
  PIN rd_out[8]
    DIRECTION OUTPUT ;
    USE SIGNAL ;
    SHAPE ABUTMENT ;
    PORT
      LAYER metal3 ;
      RECT 0.000 102.445 0.070 102.515 ;
    END
  END rd_out[8]
  PIN rd_out[9]
    DIRECTION OUTPUT ;
    USE SIGNAL ;
    SHAPE ABUTMENT ;
    PORT
      LAYER metal3 ;
      RECT 0.000 102.585 0.070 102.655 ;
    END
  END rd_out[9]
  PIN rd_out[10]
    DIRECTION OUTPUT ;
    USE SIGNAL ;
    SHAPE ABUTMENT ;
    PORT
      LAYER metal3 ;
      RECT 0.000 102.725 0.070 102.795 ;
    END
  END rd_out[10]
  PIN rd_out[11]
    DIRECTION OUTPUT ;
    USE SIGNAL ;
    SHAPE ABUTMENT ;
    PORT
      LAYER metal3 ;
      RECT 0.000 102.865 0.070 102.935 ;
    END
  END rd_out[11]
  PIN rd_out[12]
    DIRECTION OUTPUT ;
    USE SIGNAL ;
    SHAPE ABUTMENT ;
    PORT
      LAYER metal3 ;
      RECT 0.000 103.005 0.070 103.075 ;
    END
  END rd_out[12]
  PIN rd_out[13]
    DIRECTION OUTPUT ;
    USE SIGNAL ;
    SHAPE ABUTMENT ;
    PORT
      LAYER metal3 ;
      RECT 0.000 103.145 0.070 103.215 ;
    END
  END rd_out[13]
  PIN rd_out[14]
    DIRECTION OUTPUT ;
    USE SIGNAL ;
    SHAPE ABUTMENT ;
    PORT
      LAYER metal3 ;
      RECT 0.000 103.285 0.070 103.355 ;
    END
  END rd_out[14]
  PIN rd_out[15]
    DIRECTION OUTPUT ;
    USE SIGNAL ;
    SHAPE ABUTMENT ;
    PORT
      LAYER metal3 ;
      RECT 0.000 103.425 0.070 103.495 ;
    END
  END rd_out[15]
  PIN rd_out[16]
    DIRECTION OUTPUT ;
    USE SIGNAL ;
    SHAPE ABUTMENT ;
    PORT
      LAYER metal3 ;
      RECT 0.000 103.565 0.070 103.635 ;
    END
  END rd_out[16]
  PIN rd_out[17]
    DIRECTION OUTPUT ;
    USE SIGNAL ;
    SHAPE ABUTMENT ;
    PORT
      LAYER metal3 ;
      RECT 0.000 103.705 0.070 103.775 ;
    END
  END rd_out[17]
  PIN rd_out[18]
    DIRECTION OUTPUT ;
    USE SIGNAL ;
    SHAPE ABUTMENT ;
    PORT
      LAYER metal3 ;
      RECT 0.000 103.845 0.070 103.915 ;
    END
  END rd_out[18]
  PIN rd_out[19]
    DIRECTION OUTPUT ;
    USE SIGNAL ;
    SHAPE ABUTMENT ;
    PORT
      LAYER metal3 ;
      RECT 0.000 103.985 0.070 104.055 ;
    END
  END rd_out[19]
  PIN rd_out[20]
    DIRECTION OUTPUT ;
    USE SIGNAL ;
    SHAPE ABUTMENT ;
    PORT
      LAYER metal3 ;
      RECT 0.000 104.125 0.070 104.195 ;
    END
  END rd_out[20]
  PIN rd_out[21]
    DIRECTION OUTPUT ;
    USE SIGNAL ;
    SHAPE ABUTMENT ;
    PORT
      LAYER metal3 ;
      RECT 0.000 104.265 0.070 104.335 ;
    END
  END rd_out[21]
  PIN rd_out[22]
    DIRECTION OUTPUT ;
    USE SIGNAL ;
    SHAPE ABUTMENT ;
    PORT
      LAYER metal3 ;
      RECT 0.000 104.405 0.070 104.475 ;
    END
  END rd_out[22]
  PIN rd_out[23]
    DIRECTION OUTPUT ;
    USE SIGNAL ;
    SHAPE ABUTMENT ;
    PORT
      LAYER metal3 ;
      RECT 0.000 104.545 0.070 104.615 ;
    END
  END rd_out[23]
  PIN rd_out[24]
    DIRECTION OUTPUT ;
    USE SIGNAL ;
    SHAPE ABUTMENT ;
    PORT
      LAYER metal3 ;
      RECT 0.000 104.685 0.070 104.755 ;
    END
  END rd_out[24]
  PIN rd_out[25]
    DIRECTION OUTPUT ;
    USE SIGNAL ;
    SHAPE ABUTMENT ;
    PORT
      LAYER metal3 ;
      RECT 0.000 104.825 0.070 104.895 ;
    END
  END rd_out[25]
  PIN rd_out[26]
    DIRECTION OUTPUT ;
    USE SIGNAL ;
    SHAPE ABUTMENT ;
    PORT
      LAYER metal3 ;
      RECT 0.000 104.965 0.070 105.035 ;
    END
  END rd_out[26]
  PIN rd_out[27]
    DIRECTION OUTPUT ;
    USE SIGNAL ;
    SHAPE ABUTMENT ;
    PORT
      LAYER metal3 ;
      RECT 0.000 105.105 0.070 105.175 ;
    END
  END rd_out[27]
  PIN rd_out[28]
    DIRECTION OUTPUT ;
    USE SIGNAL ;
    SHAPE ABUTMENT ;
    PORT
      LAYER metal3 ;
      RECT 0.000 105.245 0.070 105.315 ;
    END
  END rd_out[28]
  PIN rd_out[29]
    DIRECTION OUTPUT ;
    USE SIGNAL ;
    SHAPE ABUTMENT ;
    PORT
      LAYER metal3 ;
      RECT 0.000 105.385 0.070 105.455 ;
    END
  END rd_out[29]
  PIN rd_out[30]
    DIRECTION OUTPUT ;
    USE SIGNAL ;
    SHAPE ABUTMENT ;
    PORT
      LAYER metal3 ;
      RECT 0.000 105.525 0.070 105.595 ;
    END
  END rd_out[30]
  PIN rd_out[31]
    DIRECTION OUTPUT ;
    USE SIGNAL ;
    SHAPE ABUTMENT ;
    PORT
      LAYER metal3 ;
      RECT 0.000 105.665 0.070 105.735 ;
    END
  END rd_out[31]
  PIN rd_out[32]
    DIRECTION OUTPUT ;
    USE SIGNAL ;
    SHAPE ABUTMENT ;
    PORT
      LAYER metal3 ;
      RECT 0.000 105.805 0.070 105.875 ;
    END
  END rd_out[32]
  PIN rd_out[33]
    DIRECTION OUTPUT ;
    USE SIGNAL ;
    SHAPE ABUTMENT ;
    PORT
      LAYER metal3 ;
      RECT 0.000 105.945 0.070 106.015 ;
    END
  END rd_out[33]
  PIN rd_out[34]
    DIRECTION OUTPUT ;
    USE SIGNAL ;
    SHAPE ABUTMENT ;
    PORT
      LAYER metal3 ;
      RECT 0.000 106.085 0.070 106.155 ;
    END
  END rd_out[34]
  PIN rd_out[35]
    DIRECTION OUTPUT ;
    USE SIGNAL ;
    SHAPE ABUTMENT ;
    PORT
      LAYER metal3 ;
      RECT 0.000 106.225 0.070 106.295 ;
    END
  END rd_out[35]
  PIN rd_out[36]
    DIRECTION OUTPUT ;
    USE SIGNAL ;
    SHAPE ABUTMENT ;
    PORT
      LAYER metal3 ;
      RECT 0.000 106.365 0.070 106.435 ;
    END
  END rd_out[36]
  PIN rd_out[37]
    DIRECTION OUTPUT ;
    USE SIGNAL ;
    SHAPE ABUTMENT ;
    PORT
      LAYER metal3 ;
      RECT 0.000 106.505 0.070 106.575 ;
    END
  END rd_out[37]
  PIN rd_out[38]
    DIRECTION OUTPUT ;
    USE SIGNAL ;
    SHAPE ABUTMENT ;
    PORT
      LAYER metal3 ;
      RECT 0.000 106.645 0.070 106.715 ;
    END
  END rd_out[38]
  PIN rd_out[39]
    DIRECTION OUTPUT ;
    USE SIGNAL ;
    SHAPE ABUTMENT ;
    PORT
      LAYER metal3 ;
      RECT 0.000 106.785 0.070 106.855 ;
    END
  END rd_out[39]
  PIN rd_out[40]
    DIRECTION OUTPUT ;
    USE SIGNAL ;
    SHAPE ABUTMENT ;
    PORT
      LAYER metal3 ;
      RECT 0.000 106.925 0.070 106.995 ;
    END
  END rd_out[40]
  PIN rd_out[41]
    DIRECTION OUTPUT ;
    USE SIGNAL ;
    SHAPE ABUTMENT ;
    PORT
      LAYER metal3 ;
      RECT 0.000 107.065 0.070 107.135 ;
    END
  END rd_out[41]
  PIN rd_out[42]
    DIRECTION OUTPUT ;
    USE SIGNAL ;
    SHAPE ABUTMENT ;
    PORT
      LAYER metal3 ;
      RECT 0.000 107.205 0.070 107.275 ;
    END
  END rd_out[42]
  PIN rd_out[43]
    DIRECTION OUTPUT ;
    USE SIGNAL ;
    SHAPE ABUTMENT ;
    PORT
      LAYER metal3 ;
      RECT 0.000 107.345 0.070 107.415 ;
    END
  END rd_out[43]
  PIN rd_out[44]
    DIRECTION OUTPUT ;
    USE SIGNAL ;
    SHAPE ABUTMENT ;
    PORT
      LAYER metal3 ;
      RECT 0.000 107.485 0.070 107.555 ;
    END
  END rd_out[44]
  PIN rd_out[45]
    DIRECTION OUTPUT ;
    USE SIGNAL ;
    SHAPE ABUTMENT ;
    PORT
      LAYER metal3 ;
      RECT 0.000 107.625 0.070 107.695 ;
    END
  END rd_out[45]
  PIN rd_out[46]
    DIRECTION OUTPUT ;
    USE SIGNAL ;
    SHAPE ABUTMENT ;
    PORT
      LAYER metal3 ;
      RECT 0.000 107.765 0.070 107.835 ;
    END
  END rd_out[46]
  PIN rd_out[47]
    DIRECTION OUTPUT ;
    USE SIGNAL ;
    SHAPE ABUTMENT ;
    PORT
      LAYER metal3 ;
      RECT 0.000 107.905 0.070 107.975 ;
    END
  END rd_out[47]
  PIN rd_out[48]
    DIRECTION OUTPUT ;
    USE SIGNAL ;
    SHAPE ABUTMENT ;
    PORT
      LAYER metal3 ;
      RECT 0.000 108.045 0.070 108.115 ;
    END
  END rd_out[48]
  PIN rd_out[49]
    DIRECTION OUTPUT ;
    USE SIGNAL ;
    SHAPE ABUTMENT ;
    PORT
      LAYER metal3 ;
      RECT 0.000 108.185 0.070 108.255 ;
    END
  END rd_out[49]
  PIN rd_out[50]
    DIRECTION OUTPUT ;
    USE SIGNAL ;
    SHAPE ABUTMENT ;
    PORT
      LAYER metal3 ;
      RECT 0.000 108.325 0.070 108.395 ;
    END
  END rd_out[50]
  PIN rd_out[51]
    DIRECTION OUTPUT ;
    USE SIGNAL ;
    SHAPE ABUTMENT ;
    PORT
      LAYER metal3 ;
      RECT 0.000 108.465 0.070 108.535 ;
    END
  END rd_out[51]
  PIN rd_out[52]
    DIRECTION OUTPUT ;
    USE SIGNAL ;
    SHAPE ABUTMENT ;
    PORT
      LAYER metal3 ;
      RECT 0.000 108.605 0.070 108.675 ;
    END
  END rd_out[52]
  PIN rd_out[53]
    DIRECTION OUTPUT ;
    USE SIGNAL ;
    SHAPE ABUTMENT ;
    PORT
      LAYER metal3 ;
      RECT 0.000 108.745 0.070 108.815 ;
    END
  END rd_out[53]
  PIN rd_out[54]
    DIRECTION OUTPUT ;
    USE SIGNAL ;
    SHAPE ABUTMENT ;
    PORT
      LAYER metal3 ;
      RECT 0.000 108.885 0.070 108.955 ;
    END
  END rd_out[54]
  PIN rd_out[55]
    DIRECTION OUTPUT ;
    USE SIGNAL ;
    SHAPE ABUTMENT ;
    PORT
      LAYER metal3 ;
      RECT 0.000 109.025 0.070 109.095 ;
    END
  END rd_out[55]
  PIN rd_out[56]
    DIRECTION OUTPUT ;
    USE SIGNAL ;
    SHAPE ABUTMENT ;
    PORT
      LAYER metal3 ;
      RECT 0.000 109.165 0.070 109.235 ;
    END
  END rd_out[56]
  PIN rd_out[57]
    DIRECTION OUTPUT ;
    USE SIGNAL ;
    SHAPE ABUTMENT ;
    PORT
      LAYER metal3 ;
      RECT 0.000 109.305 0.070 109.375 ;
    END
  END rd_out[57]
  PIN rd_out[58]
    DIRECTION OUTPUT ;
    USE SIGNAL ;
    SHAPE ABUTMENT ;
    PORT
      LAYER metal3 ;
      RECT 0.000 109.445 0.070 109.515 ;
    END
  END rd_out[58]
  PIN rd_out[59]
    DIRECTION OUTPUT ;
    USE SIGNAL ;
    SHAPE ABUTMENT ;
    PORT
      LAYER metal3 ;
      RECT 0.000 109.585 0.070 109.655 ;
    END
  END rd_out[59]
  PIN rd_out[60]
    DIRECTION OUTPUT ;
    USE SIGNAL ;
    SHAPE ABUTMENT ;
    PORT
      LAYER metal3 ;
      RECT 0.000 109.725 0.070 109.795 ;
    END
  END rd_out[60]
  PIN rd_out[61]
    DIRECTION OUTPUT ;
    USE SIGNAL ;
    SHAPE ABUTMENT ;
    PORT
      LAYER metal3 ;
      RECT 0.000 109.865 0.070 109.935 ;
    END
  END rd_out[61]
  PIN rd_out[62]
    DIRECTION OUTPUT ;
    USE SIGNAL ;
    SHAPE ABUTMENT ;
    PORT
      LAYER metal3 ;
      RECT 0.000 110.005 0.070 110.075 ;
    END
  END rd_out[62]
  PIN rd_out[63]
    DIRECTION OUTPUT ;
    USE SIGNAL ;
    SHAPE ABUTMENT ;
    PORT
      LAYER metal3 ;
      RECT 0.000 110.145 0.070 110.215 ;
    END
  END rd_out[63]
  PIN rd_out[64]
    DIRECTION OUTPUT ;
    USE SIGNAL ;
    SHAPE ABUTMENT ;
    PORT
      LAYER metal3 ;
      RECT 0.000 110.285 0.070 110.355 ;
    END
  END rd_out[64]
  PIN rd_out[65]
    DIRECTION OUTPUT ;
    USE SIGNAL ;
    SHAPE ABUTMENT ;
    PORT
      LAYER metal3 ;
      RECT 0.000 110.425 0.070 110.495 ;
    END
  END rd_out[65]
  PIN rd_out[66]
    DIRECTION OUTPUT ;
    USE SIGNAL ;
    SHAPE ABUTMENT ;
    PORT
      LAYER metal3 ;
      RECT 0.000 110.565 0.070 110.635 ;
    END
  END rd_out[66]
  PIN rd_out[67]
    DIRECTION OUTPUT ;
    USE SIGNAL ;
    SHAPE ABUTMENT ;
    PORT
      LAYER metal3 ;
      RECT 0.000 110.705 0.070 110.775 ;
    END
  END rd_out[67]
  PIN rd_out[68]
    DIRECTION OUTPUT ;
    USE SIGNAL ;
    SHAPE ABUTMENT ;
    PORT
      LAYER metal3 ;
      RECT 0.000 110.845 0.070 110.915 ;
    END
  END rd_out[68]
  PIN rd_out[69]
    DIRECTION OUTPUT ;
    USE SIGNAL ;
    SHAPE ABUTMENT ;
    PORT
      LAYER metal3 ;
      RECT 0.000 110.985 0.070 111.055 ;
    END
  END rd_out[69]
  PIN rd_out[70]
    DIRECTION OUTPUT ;
    USE SIGNAL ;
    SHAPE ABUTMENT ;
    PORT
      LAYER metal3 ;
      RECT 0.000 111.125 0.070 111.195 ;
    END
  END rd_out[70]
  PIN rd_out[71]
    DIRECTION OUTPUT ;
    USE SIGNAL ;
    SHAPE ABUTMENT ;
    PORT
      LAYER metal3 ;
      RECT 0.000 111.265 0.070 111.335 ;
    END
  END rd_out[71]
  PIN rd_out[72]
    DIRECTION OUTPUT ;
    USE SIGNAL ;
    SHAPE ABUTMENT ;
    PORT
      LAYER metal3 ;
      RECT 0.000 111.405 0.070 111.475 ;
    END
  END rd_out[72]
  PIN rd_out[73]
    DIRECTION OUTPUT ;
    USE SIGNAL ;
    SHAPE ABUTMENT ;
    PORT
      LAYER metal3 ;
      RECT 0.000 111.545 0.070 111.615 ;
    END
  END rd_out[73]
  PIN rd_out[74]
    DIRECTION OUTPUT ;
    USE SIGNAL ;
    SHAPE ABUTMENT ;
    PORT
      LAYER metal3 ;
      RECT 0.000 111.685 0.070 111.755 ;
    END
  END rd_out[74]
  PIN rd_out[75]
    DIRECTION OUTPUT ;
    USE SIGNAL ;
    SHAPE ABUTMENT ;
    PORT
      LAYER metal3 ;
      RECT 0.000 111.825 0.070 111.895 ;
    END
  END rd_out[75]
  PIN rd_out[76]
    DIRECTION OUTPUT ;
    USE SIGNAL ;
    SHAPE ABUTMENT ;
    PORT
      LAYER metal3 ;
      RECT 0.000 111.965 0.070 112.035 ;
    END
  END rd_out[76]
  PIN rd_out[77]
    DIRECTION OUTPUT ;
    USE SIGNAL ;
    SHAPE ABUTMENT ;
    PORT
      LAYER metal3 ;
      RECT 0.000 112.105 0.070 112.175 ;
    END
  END rd_out[77]
  PIN rd_out[78]
    DIRECTION OUTPUT ;
    USE SIGNAL ;
    SHAPE ABUTMENT ;
    PORT
      LAYER metal3 ;
      RECT 0.000 112.245 0.070 112.315 ;
    END
  END rd_out[78]
  PIN rd_out[79]
    DIRECTION OUTPUT ;
    USE SIGNAL ;
    SHAPE ABUTMENT ;
    PORT
      LAYER metal3 ;
      RECT 0.000 112.385 0.070 112.455 ;
    END
  END rd_out[79]
  PIN rd_out[80]
    DIRECTION OUTPUT ;
    USE SIGNAL ;
    SHAPE ABUTMENT ;
    PORT
      LAYER metal3 ;
      RECT 0.000 112.525 0.070 112.595 ;
    END
  END rd_out[80]
  PIN rd_out[81]
    DIRECTION OUTPUT ;
    USE SIGNAL ;
    SHAPE ABUTMENT ;
    PORT
      LAYER metal3 ;
      RECT 0.000 112.665 0.070 112.735 ;
    END
  END rd_out[81]
  PIN rd_out[82]
    DIRECTION OUTPUT ;
    USE SIGNAL ;
    SHAPE ABUTMENT ;
    PORT
      LAYER metal3 ;
      RECT 0.000 112.805 0.070 112.875 ;
    END
  END rd_out[82]
  PIN rd_out[83]
    DIRECTION OUTPUT ;
    USE SIGNAL ;
    SHAPE ABUTMENT ;
    PORT
      LAYER metal3 ;
      RECT 0.000 112.945 0.070 113.015 ;
    END
  END rd_out[83]
  PIN rd_out[84]
    DIRECTION OUTPUT ;
    USE SIGNAL ;
    SHAPE ABUTMENT ;
    PORT
      LAYER metal3 ;
      RECT 0.000 113.085 0.070 113.155 ;
    END
  END rd_out[84]
  PIN rd_out[85]
    DIRECTION OUTPUT ;
    USE SIGNAL ;
    SHAPE ABUTMENT ;
    PORT
      LAYER metal3 ;
      RECT 0.000 113.225 0.070 113.295 ;
    END
  END rd_out[85]
  PIN rd_out[86]
    DIRECTION OUTPUT ;
    USE SIGNAL ;
    SHAPE ABUTMENT ;
    PORT
      LAYER metal3 ;
      RECT 0.000 113.365 0.070 113.435 ;
    END
  END rd_out[86]
  PIN rd_out[87]
    DIRECTION OUTPUT ;
    USE SIGNAL ;
    SHAPE ABUTMENT ;
    PORT
      LAYER metal3 ;
      RECT 0.000 113.505 0.070 113.575 ;
    END
  END rd_out[87]
  PIN rd_out[88]
    DIRECTION OUTPUT ;
    USE SIGNAL ;
    SHAPE ABUTMENT ;
    PORT
      LAYER metal3 ;
      RECT 0.000 113.645 0.070 113.715 ;
    END
  END rd_out[88]
  PIN rd_out[89]
    DIRECTION OUTPUT ;
    USE SIGNAL ;
    SHAPE ABUTMENT ;
    PORT
      LAYER metal3 ;
      RECT 0.000 113.785 0.070 113.855 ;
    END
  END rd_out[89]
  PIN rd_out[90]
    DIRECTION OUTPUT ;
    USE SIGNAL ;
    SHAPE ABUTMENT ;
    PORT
      LAYER metal3 ;
      RECT 0.000 113.925 0.070 113.995 ;
    END
  END rd_out[90]
  PIN rd_out[91]
    DIRECTION OUTPUT ;
    USE SIGNAL ;
    SHAPE ABUTMENT ;
    PORT
      LAYER metal3 ;
      RECT 0.000 114.065 0.070 114.135 ;
    END
  END rd_out[91]
  PIN rd_out[92]
    DIRECTION OUTPUT ;
    USE SIGNAL ;
    SHAPE ABUTMENT ;
    PORT
      LAYER metal3 ;
      RECT 0.000 114.205 0.070 114.275 ;
    END
  END rd_out[92]
  PIN rd_out[93]
    DIRECTION OUTPUT ;
    USE SIGNAL ;
    SHAPE ABUTMENT ;
    PORT
      LAYER metal3 ;
      RECT 0.000 114.345 0.070 114.415 ;
    END
  END rd_out[93]
  PIN rd_out[94]
    DIRECTION OUTPUT ;
    USE SIGNAL ;
    SHAPE ABUTMENT ;
    PORT
      LAYER metal3 ;
      RECT 0.000 114.485 0.070 114.555 ;
    END
  END rd_out[94]
  PIN rd_out[95]
    DIRECTION OUTPUT ;
    USE SIGNAL ;
    SHAPE ABUTMENT ;
    PORT
      LAYER metal3 ;
      RECT 0.000 114.625 0.070 114.695 ;
    END
  END rd_out[95]
  PIN rd_out[96]
    DIRECTION OUTPUT ;
    USE SIGNAL ;
    SHAPE ABUTMENT ;
    PORT
      LAYER metal3 ;
      RECT 0.000 114.765 0.070 114.835 ;
    END
  END rd_out[96]
  PIN rd_out[97]
    DIRECTION OUTPUT ;
    USE SIGNAL ;
    SHAPE ABUTMENT ;
    PORT
      LAYER metal3 ;
      RECT 0.000 114.905 0.070 114.975 ;
    END
  END rd_out[97]
  PIN rd_out[98]
    DIRECTION OUTPUT ;
    USE SIGNAL ;
    SHAPE ABUTMENT ;
    PORT
      LAYER metal3 ;
      RECT 0.000 115.045 0.070 115.115 ;
    END
  END rd_out[98]
  PIN rd_out[99]
    DIRECTION OUTPUT ;
    USE SIGNAL ;
    SHAPE ABUTMENT ;
    PORT
      LAYER metal3 ;
      RECT 0.000 115.185 0.070 115.255 ;
    END
  END rd_out[99]
  PIN rd_out[100]
    DIRECTION OUTPUT ;
    USE SIGNAL ;
    SHAPE ABUTMENT ;
    PORT
      LAYER metal3 ;
      RECT 0.000 115.325 0.070 115.395 ;
    END
  END rd_out[100]
  PIN rd_out[101]
    DIRECTION OUTPUT ;
    USE SIGNAL ;
    SHAPE ABUTMENT ;
    PORT
      LAYER metal3 ;
      RECT 0.000 115.465 0.070 115.535 ;
    END
  END rd_out[101]
  PIN rd_out[102]
    DIRECTION OUTPUT ;
    USE SIGNAL ;
    SHAPE ABUTMENT ;
    PORT
      LAYER metal3 ;
      RECT 0.000 115.605 0.070 115.675 ;
    END
  END rd_out[102]
  PIN rd_out[103]
    DIRECTION OUTPUT ;
    USE SIGNAL ;
    SHAPE ABUTMENT ;
    PORT
      LAYER metal3 ;
      RECT 0.000 115.745 0.070 115.815 ;
    END
  END rd_out[103]
  PIN rd_out[104]
    DIRECTION OUTPUT ;
    USE SIGNAL ;
    SHAPE ABUTMENT ;
    PORT
      LAYER metal3 ;
      RECT 0.000 115.885 0.070 115.955 ;
    END
  END rd_out[104]
  PIN rd_out[105]
    DIRECTION OUTPUT ;
    USE SIGNAL ;
    SHAPE ABUTMENT ;
    PORT
      LAYER metal3 ;
      RECT 0.000 116.025 0.070 116.095 ;
    END
  END rd_out[105]
  PIN rd_out[106]
    DIRECTION OUTPUT ;
    USE SIGNAL ;
    SHAPE ABUTMENT ;
    PORT
      LAYER metal3 ;
      RECT 0.000 116.165 0.070 116.235 ;
    END
  END rd_out[106]
  PIN rd_out[107]
    DIRECTION OUTPUT ;
    USE SIGNAL ;
    SHAPE ABUTMENT ;
    PORT
      LAYER metal3 ;
      RECT 0.000 116.305 0.070 116.375 ;
    END
  END rd_out[107]
  PIN rd_out[108]
    DIRECTION OUTPUT ;
    USE SIGNAL ;
    SHAPE ABUTMENT ;
    PORT
      LAYER metal3 ;
      RECT 0.000 116.445 0.070 116.515 ;
    END
  END rd_out[108]
  PIN rd_out[109]
    DIRECTION OUTPUT ;
    USE SIGNAL ;
    SHAPE ABUTMENT ;
    PORT
      LAYER metal3 ;
      RECT 0.000 116.585 0.070 116.655 ;
    END
  END rd_out[109]
  PIN rd_out[110]
    DIRECTION OUTPUT ;
    USE SIGNAL ;
    SHAPE ABUTMENT ;
    PORT
      LAYER metal3 ;
      RECT 0.000 116.725 0.070 116.795 ;
    END
  END rd_out[110]
  PIN rd_out[111]
    DIRECTION OUTPUT ;
    USE SIGNAL ;
    SHAPE ABUTMENT ;
    PORT
      LAYER metal3 ;
      RECT 0.000 116.865 0.070 116.935 ;
    END
  END rd_out[111]
  PIN rd_out[112]
    DIRECTION OUTPUT ;
    USE SIGNAL ;
    SHAPE ABUTMENT ;
    PORT
      LAYER metal3 ;
      RECT 0.000 117.005 0.070 117.075 ;
    END
  END rd_out[112]
  PIN rd_out[113]
    DIRECTION OUTPUT ;
    USE SIGNAL ;
    SHAPE ABUTMENT ;
    PORT
      LAYER metal3 ;
      RECT 0.000 117.145 0.070 117.215 ;
    END
  END rd_out[113]
  PIN rd_out[114]
    DIRECTION OUTPUT ;
    USE SIGNAL ;
    SHAPE ABUTMENT ;
    PORT
      LAYER metal3 ;
      RECT 0.000 117.285 0.070 117.355 ;
    END
  END rd_out[114]
  PIN rd_out[115]
    DIRECTION OUTPUT ;
    USE SIGNAL ;
    SHAPE ABUTMENT ;
    PORT
      LAYER metal3 ;
      RECT 0.000 117.425 0.070 117.495 ;
    END
  END rd_out[115]
  PIN rd_out[116]
    DIRECTION OUTPUT ;
    USE SIGNAL ;
    SHAPE ABUTMENT ;
    PORT
      LAYER metal3 ;
      RECT 0.000 117.565 0.070 117.635 ;
    END
  END rd_out[116]
  PIN rd_out[117]
    DIRECTION OUTPUT ;
    USE SIGNAL ;
    SHAPE ABUTMENT ;
    PORT
      LAYER metal3 ;
      RECT 0.000 117.705 0.070 117.775 ;
    END
  END rd_out[117]
  PIN rd_out[118]
    DIRECTION OUTPUT ;
    USE SIGNAL ;
    SHAPE ABUTMENT ;
    PORT
      LAYER metal3 ;
      RECT 0.000 117.845 0.070 117.915 ;
    END
  END rd_out[118]
  PIN rd_out[119]
    DIRECTION OUTPUT ;
    USE SIGNAL ;
    SHAPE ABUTMENT ;
    PORT
      LAYER metal3 ;
      RECT 0.000 117.985 0.070 118.055 ;
    END
  END rd_out[119]
  PIN rd_out[120]
    DIRECTION OUTPUT ;
    USE SIGNAL ;
    SHAPE ABUTMENT ;
    PORT
      LAYER metal3 ;
      RECT 0.000 118.125 0.070 118.195 ;
    END
  END rd_out[120]
  PIN rd_out[121]
    DIRECTION OUTPUT ;
    USE SIGNAL ;
    SHAPE ABUTMENT ;
    PORT
      LAYER metal3 ;
      RECT 0.000 118.265 0.070 118.335 ;
    END
  END rd_out[121]
  PIN rd_out[122]
    DIRECTION OUTPUT ;
    USE SIGNAL ;
    SHAPE ABUTMENT ;
    PORT
      LAYER metal3 ;
      RECT 0.000 118.405 0.070 118.475 ;
    END
  END rd_out[122]
  PIN rd_out[123]
    DIRECTION OUTPUT ;
    USE SIGNAL ;
    SHAPE ABUTMENT ;
    PORT
      LAYER metal3 ;
      RECT 0.000 118.545 0.070 118.615 ;
    END
  END rd_out[123]
  PIN rd_out[124]
    DIRECTION OUTPUT ;
    USE SIGNAL ;
    SHAPE ABUTMENT ;
    PORT
      LAYER metal3 ;
      RECT 0.000 118.685 0.070 118.755 ;
    END
  END rd_out[124]
  PIN rd_out[125]
    DIRECTION OUTPUT ;
    USE SIGNAL ;
    SHAPE ABUTMENT ;
    PORT
      LAYER metal3 ;
      RECT 0.000 118.825 0.070 118.895 ;
    END
  END rd_out[125]
  PIN rd_out[126]
    DIRECTION OUTPUT ;
    USE SIGNAL ;
    SHAPE ABUTMENT ;
    PORT
      LAYER metal3 ;
      RECT 0.000 118.965 0.070 119.035 ;
    END
  END rd_out[126]
  PIN rd_out[127]
    DIRECTION OUTPUT ;
    USE SIGNAL ;
    SHAPE ABUTMENT ;
    PORT
      LAYER metal3 ;
      RECT 0.000 119.105 0.070 119.175 ;
    END
  END rd_out[127]
  PIN rd_out[128]
    DIRECTION OUTPUT ;
    USE SIGNAL ;
    SHAPE ABUTMENT ;
    PORT
      LAYER metal3 ;
      RECT 0.000 119.245 0.070 119.315 ;
    END
  END rd_out[128]
  PIN rd_out[129]
    DIRECTION OUTPUT ;
    USE SIGNAL ;
    SHAPE ABUTMENT ;
    PORT
      LAYER metal3 ;
      RECT 0.000 119.385 0.070 119.455 ;
    END
  END rd_out[129]
  PIN rd_out[130]
    DIRECTION OUTPUT ;
    USE SIGNAL ;
    SHAPE ABUTMENT ;
    PORT
      LAYER metal3 ;
      RECT 0.000 119.525 0.070 119.595 ;
    END
  END rd_out[130]
  PIN rd_out[131]
    DIRECTION OUTPUT ;
    USE SIGNAL ;
    SHAPE ABUTMENT ;
    PORT
      LAYER metal3 ;
      RECT 0.000 119.665 0.070 119.735 ;
    END
  END rd_out[131]
  PIN rd_out[132]
    DIRECTION OUTPUT ;
    USE SIGNAL ;
    SHAPE ABUTMENT ;
    PORT
      LAYER metal3 ;
      RECT 0.000 119.805 0.070 119.875 ;
    END
  END rd_out[132]
  PIN rd_out[133]
    DIRECTION OUTPUT ;
    USE SIGNAL ;
    SHAPE ABUTMENT ;
    PORT
      LAYER metal3 ;
      RECT 0.000 119.945 0.070 120.015 ;
    END
  END rd_out[133]
  PIN rd_out[134]
    DIRECTION OUTPUT ;
    USE SIGNAL ;
    SHAPE ABUTMENT ;
    PORT
      LAYER metal3 ;
      RECT 0.000 120.085 0.070 120.155 ;
    END
  END rd_out[134]
  PIN rd_out[135]
    DIRECTION OUTPUT ;
    USE SIGNAL ;
    SHAPE ABUTMENT ;
    PORT
      LAYER metal3 ;
      RECT 0.000 120.225 0.070 120.295 ;
    END
  END rd_out[135]
  PIN rd_out[136]
    DIRECTION OUTPUT ;
    USE SIGNAL ;
    SHAPE ABUTMENT ;
    PORT
      LAYER metal3 ;
      RECT 0.000 120.365 0.070 120.435 ;
    END
  END rd_out[136]
  PIN rd_out[137]
    DIRECTION OUTPUT ;
    USE SIGNAL ;
    SHAPE ABUTMENT ;
    PORT
      LAYER metal3 ;
      RECT 0.000 120.505 0.070 120.575 ;
    END
  END rd_out[137]
  PIN rd_out[138]
    DIRECTION OUTPUT ;
    USE SIGNAL ;
    SHAPE ABUTMENT ;
    PORT
      LAYER metal3 ;
      RECT 0.000 120.645 0.070 120.715 ;
    END
  END rd_out[138]
  PIN rd_out[139]
    DIRECTION OUTPUT ;
    USE SIGNAL ;
    SHAPE ABUTMENT ;
    PORT
      LAYER metal3 ;
      RECT 0.000 120.785 0.070 120.855 ;
    END
  END rd_out[139]
  PIN rd_out[140]
    DIRECTION OUTPUT ;
    USE SIGNAL ;
    SHAPE ABUTMENT ;
    PORT
      LAYER metal3 ;
      RECT 0.000 120.925 0.070 120.995 ;
    END
  END rd_out[140]
  PIN rd_out[141]
    DIRECTION OUTPUT ;
    USE SIGNAL ;
    SHAPE ABUTMENT ;
    PORT
      LAYER metal3 ;
      RECT 0.000 121.065 0.070 121.135 ;
    END
  END rd_out[141]
  PIN rd_out[142]
    DIRECTION OUTPUT ;
    USE SIGNAL ;
    SHAPE ABUTMENT ;
    PORT
      LAYER metal3 ;
      RECT 0.000 121.205 0.070 121.275 ;
    END
  END rd_out[142]
  PIN rd_out[143]
    DIRECTION OUTPUT ;
    USE SIGNAL ;
    SHAPE ABUTMENT ;
    PORT
      LAYER metal3 ;
      RECT 0.000 121.345 0.070 121.415 ;
    END
  END rd_out[143]
  PIN rd_out[144]
    DIRECTION OUTPUT ;
    USE SIGNAL ;
    SHAPE ABUTMENT ;
    PORT
      LAYER metal3 ;
      RECT 0.000 121.485 0.070 121.555 ;
    END
  END rd_out[144]
  PIN rd_out[145]
    DIRECTION OUTPUT ;
    USE SIGNAL ;
    SHAPE ABUTMENT ;
    PORT
      LAYER metal3 ;
      RECT 0.000 121.625 0.070 121.695 ;
    END
  END rd_out[145]
  PIN rd_out[146]
    DIRECTION OUTPUT ;
    USE SIGNAL ;
    SHAPE ABUTMENT ;
    PORT
      LAYER metal3 ;
      RECT 0.000 121.765 0.070 121.835 ;
    END
  END rd_out[146]
  PIN rd_out[147]
    DIRECTION OUTPUT ;
    USE SIGNAL ;
    SHAPE ABUTMENT ;
    PORT
      LAYER metal3 ;
      RECT 0.000 121.905 0.070 121.975 ;
    END
  END rd_out[147]
  PIN rd_out[148]
    DIRECTION OUTPUT ;
    USE SIGNAL ;
    SHAPE ABUTMENT ;
    PORT
      LAYER metal3 ;
      RECT 0.000 122.045 0.070 122.115 ;
    END
  END rd_out[148]
  PIN rd_out[149]
    DIRECTION OUTPUT ;
    USE SIGNAL ;
    SHAPE ABUTMENT ;
    PORT
      LAYER metal3 ;
      RECT 0.000 122.185 0.070 122.255 ;
    END
  END rd_out[149]
  PIN rd_out[150]
    DIRECTION OUTPUT ;
    USE SIGNAL ;
    SHAPE ABUTMENT ;
    PORT
      LAYER metal3 ;
      RECT 0.000 122.325 0.070 122.395 ;
    END
  END rd_out[150]
  PIN rd_out[151]
    DIRECTION OUTPUT ;
    USE SIGNAL ;
    SHAPE ABUTMENT ;
    PORT
      LAYER metal3 ;
      RECT 0.000 122.465 0.070 122.535 ;
    END
  END rd_out[151]
  PIN rd_out[152]
    DIRECTION OUTPUT ;
    USE SIGNAL ;
    SHAPE ABUTMENT ;
    PORT
      LAYER metal3 ;
      RECT 0.000 122.605 0.070 122.675 ;
    END
  END rd_out[152]
  PIN rd_out[153]
    DIRECTION OUTPUT ;
    USE SIGNAL ;
    SHAPE ABUTMENT ;
    PORT
      LAYER metal3 ;
      RECT 0.000 122.745 0.070 122.815 ;
    END
  END rd_out[153]
  PIN rd_out[154]
    DIRECTION OUTPUT ;
    USE SIGNAL ;
    SHAPE ABUTMENT ;
    PORT
      LAYER metal3 ;
      RECT 0.000 122.885 0.070 122.955 ;
    END
  END rd_out[154]
  PIN rd_out[155]
    DIRECTION OUTPUT ;
    USE SIGNAL ;
    SHAPE ABUTMENT ;
    PORT
      LAYER metal3 ;
      RECT 0.000 123.025 0.070 123.095 ;
    END
  END rd_out[155]
  PIN rd_out[156]
    DIRECTION OUTPUT ;
    USE SIGNAL ;
    SHAPE ABUTMENT ;
    PORT
      LAYER metal3 ;
      RECT 0.000 123.165 0.070 123.235 ;
    END
  END rd_out[156]
  PIN rd_out[157]
    DIRECTION OUTPUT ;
    USE SIGNAL ;
    SHAPE ABUTMENT ;
    PORT
      LAYER metal3 ;
      RECT 0.000 123.305 0.070 123.375 ;
    END
  END rd_out[157]
  PIN rd_out[158]
    DIRECTION OUTPUT ;
    USE SIGNAL ;
    SHAPE ABUTMENT ;
    PORT
      LAYER metal3 ;
      RECT 0.000 123.445 0.070 123.515 ;
    END
  END rd_out[158]
  PIN rd_out[159]
    DIRECTION OUTPUT ;
    USE SIGNAL ;
    SHAPE ABUTMENT ;
    PORT
      LAYER metal3 ;
      RECT 0.000 123.585 0.070 123.655 ;
    END
  END rd_out[159]
  PIN rd_out[160]
    DIRECTION OUTPUT ;
    USE SIGNAL ;
    SHAPE ABUTMENT ;
    PORT
      LAYER metal3 ;
      RECT 0.000 123.725 0.070 123.795 ;
    END
  END rd_out[160]
  PIN rd_out[161]
    DIRECTION OUTPUT ;
    USE SIGNAL ;
    SHAPE ABUTMENT ;
    PORT
      LAYER metal3 ;
      RECT 0.000 123.865 0.070 123.935 ;
    END
  END rd_out[161]
  PIN rd_out[162]
    DIRECTION OUTPUT ;
    USE SIGNAL ;
    SHAPE ABUTMENT ;
    PORT
      LAYER metal3 ;
      RECT 0.000 124.005 0.070 124.075 ;
    END
  END rd_out[162]
  PIN rd_out[163]
    DIRECTION OUTPUT ;
    USE SIGNAL ;
    SHAPE ABUTMENT ;
    PORT
      LAYER metal3 ;
      RECT 0.000 124.145 0.070 124.215 ;
    END
  END rd_out[163]
  PIN rd_out[164]
    DIRECTION OUTPUT ;
    USE SIGNAL ;
    SHAPE ABUTMENT ;
    PORT
      LAYER metal3 ;
      RECT 0.000 124.285 0.070 124.355 ;
    END
  END rd_out[164]
  PIN rd_out[165]
    DIRECTION OUTPUT ;
    USE SIGNAL ;
    SHAPE ABUTMENT ;
    PORT
      LAYER metal3 ;
      RECT 0.000 124.425 0.070 124.495 ;
    END
  END rd_out[165]
  PIN rd_out[166]
    DIRECTION OUTPUT ;
    USE SIGNAL ;
    SHAPE ABUTMENT ;
    PORT
      LAYER metal3 ;
      RECT 0.000 124.565 0.070 124.635 ;
    END
  END rd_out[166]
  PIN rd_out[167]
    DIRECTION OUTPUT ;
    USE SIGNAL ;
    SHAPE ABUTMENT ;
    PORT
      LAYER metal3 ;
      RECT 0.000 124.705 0.070 124.775 ;
    END
  END rd_out[167]
  PIN rd_out[168]
    DIRECTION OUTPUT ;
    USE SIGNAL ;
    SHAPE ABUTMENT ;
    PORT
      LAYER metal3 ;
      RECT 0.000 124.845 0.070 124.915 ;
    END
  END rd_out[168]
  PIN rd_out[169]
    DIRECTION OUTPUT ;
    USE SIGNAL ;
    SHAPE ABUTMENT ;
    PORT
      LAYER metal3 ;
      RECT 0.000 124.985 0.070 125.055 ;
    END
  END rd_out[169]
  PIN rd_out[170]
    DIRECTION OUTPUT ;
    USE SIGNAL ;
    SHAPE ABUTMENT ;
    PORT
      LAYER metal3 ;
      RECT 0.000 125.125 0.070 125.195 ;
    END
  END rd_out[170]
  PIN rd_out[171]
    DIRECTION OUTPUT ;
    USE SIGNAL ;
    SHAPE ABUTMENT ;
    PORT
      LAYER metal3 ;
      RECT 0.000 125.265 0.070 125.335 ;
    END
  END rd_out[171]
  PIN rd_out[172]
    DIRECTION OUTPUT ;
    USE SIGNAL ;
    SHAPE ABUTMENT ;
    PORT
      LAYER metal3 ;
      RECT 0.000 125.405 0.070 125.475 ;
    END
  END rd_out[172]
  PIN rd_out[173]
    DIRECTION OUTPUT ;
    USE SIGNAL ;
    SHAPE ABUTMENT ;
    PORT
      LAYER metal3 ;
      RECT 0.000 125.545 0.070 125.615 ;
    END
  END rd_out[173]
  PIN rd_out[174]
    DIRECTION OUTPUT ;
    USE SIGNAL ;
    SHAPE ABUTMENT ;
    PORT
      LAYER metal3 ;
      RECT 0.000 125.685 0.070 125.755 ;
    END
  END rd_out[174]
  PIN rd_out[175]
    DIRECTION OUTPUT ;
    USE SIGNAL ;
    SHAPE ABUTMENT ;
    PORT
      LAYER metal3 ;
      RECT 0.000 125.825 0.070 125.895 ;
    END
  END rd_out[175]
  PIN rd_out[176]
    DIRECTION OUTPUT ;
    USE SIGNAL ;
    SHAPE ABUTMENT ;
    PORT
      LAYER metal3 ;
      RECT 0.000 125.965 0.070 126.035 ;
    END
  END rd_out[176]
  PIN rd_out[177]
    DIRECTION OUTPUT ;
    USE SIGNAL ;
    SHAPE ABUTMENT ;
    PORT
      LAYER metal3 ;
      RECT 0.000 126.105 0.070 126.175 ;
    END
  END rd_out[177]
  PIN rd_out[178]
    DIRECTION OUTPUT ;
    USE SIGNAL ;
    SHAPE ABUTMENT ;
    PORT
      LAYER metal3 ;
      RECT 0.000 126.245 0.070 126.315 ;
    END
  END rd_out[178]
  PIN rd_out[179]
    DIRECTION OUTPUT ;
    USE SIGNAL ;
    SHAPE ABUTMENT ;
    PORT
      LAYER metal3 ;
      RECT 0.000 126.385 0.070 126.455 ;
    END
  END rd_out[179]
  PIN rd_out[180]
    DIRECTION OUTPUT ;
    USE SIGNAL ;
    SHAPE ABUTMENT ;
    PORT
      LAYER metal3 ;
      RECT 0.000 126.525 0.070 126.595 ;
    END
  END rd_out[180]
  PIN rd_out[181]
    DIRECTION OUTPUT ;
    USE SIGNAL ;
    SHAPE ABUTMENT ;
    PORT
      LAYER metal3 ;
      RECT 0.000 126.665 0.070 126.735 ;
    END
  END rd_out[181]
  PIN rd_out[182]
    DIRECTION OUTPUT ;
    USE SIGNAL ;
    SHAPE ABUTMENT ;
    PORT
      LAYER metal3 ;
      RECT 0.000 126.805 0.070 126.875 ;
    END
  END rd_out[182]
  PIN rd_out[183]
    DIRECTION OUTPUT ;
    USE SIGNAL ;
    SHAPE ABUTMENT ;
    PORT
      LAYER metal3 ;
      RECT 0.000 126.945 0.070 127.015 ;
    END
  END rd_out[183]
  PIN rd_out[184]
    DIRECTION OUTPUT ;
    USE SIGNAL ;
    SHAPE ABUTMENT ;
    PORT
      LAYER metal3 ;
      RECT 0.000 127.085 0.070 127.155 ;
    END
  END rd_out[184]
  PIN rd_out[185]
    DIRECTION OUTPUT ;
    USE SIGNAL ;
    SHAPE ABUTMENT ;
    PORT
      LAYER metal3 ;
      RECT 0.000 127.225 0.070 127.295 ;
    END
  END rd_out[185]
  PIN rd_out[186]
    DIRECTION OUTPUT ;
    USE SIGNAL ;
    SHAPE ABUTMENT ;
    PORT
      LAYER metal3 ;
      RECT 0.000 127.365 0.070 127.435 ;
    END
  END rd_out[186]
  PIN rd_out[187]
    DIRECTION OUTPUT ;
    USE SIGNAL ;
    SHAPE ABUTMENT ;
    PORT
      LAYER metal3 ;
      RECT 0.000 127.505 0.070 127.575 ;
    END
  END rd_out[187]
  PIN rd_out[188]
    DIRECTION OUTPUT ;
    USE SIGNAL ;
    SHAPE ABUTMENT ;
    PORT
      LAYER metal3 ;
      RECT 0.000 127.645 0.070 127.715 ;
    END
  END rd_out[188]
  PIN rd_out[189]
    DIRECTION OUTPUT ;
    USE SIGNAL ;
    SHAPE ABUTMENT ;
    PORT
      LAYER metal3 ;
      RECT 0.000 127.785 0.070 127.855 ;
    END
  END rd_out[189]
  PIN rd_out[190]
    DIRECTION OUTPUT ;
    USE SIGNAL ;
    SHAPE ABUTMENT ;
    PORT
      LAYER metal3 ;
      RECT 0.000 127.925 0.070 127.995 ;
    END
  END rd_out[190]
  PIN rd_out[191]
    DIRECTION OUTPUT ;
    USE SIGNAL ;
    SHAPE ABUTMENT ;
    PORT
      LAYER metal3 ;
      RECT 0.000 128.065 0.070 128.135 ;
    END
  END rd_out[191]
  PIN rd_out[192]
    DIRECTION OUTPUT ;
    USE SIGNAL ;
    SHAPE ABUTMENT ;
    PORT
      LAYER metal3 ;
      RECT 0.000 128.205 0.070 128.275 ;
    END
  END rd_out[192]
  PIN rd_out[193]
    DIRECTION OUTPUT ;
    USE SIGNAL ;
    SHAPE ABUTMENT ;
    PORT
      LAYER metal3 ;
      RECT 0.000 128.345 0.070 128.415 ;
    END
  END rd_out[193]
  PIN rd_out[194]
    DIRECTION OUTPUT ;
    USE SIGNAL ;
    SHAPE ABUTMENT ;
    PORT
      LAYER metal3 ;
      RECT 0.000 128.485 0.070 128.555 ;
    END
  END rd_out[194]
  PIN rd_out[195]
    DIRECTION OUTPUT ;
    USE SIGNAL ;
    SHAPE ABUTMENT ;
    PORT
      LAYER metal3 ;
      RECT 0.000 128.625 0.070 128.695 ;
    END
  END rd_out[195]
  PIN rd_out[196]
    DIRECTION OUTPUT ;
    USE SIGNAL ;
    SHAPE ABUTMENT ;
    PORT
      LAYER metal3 ;
      RECT 0.000 128.765 0.070 128.835 ;
    END
  END rd_out[196]
  PIN rd_out[197]
    DIRECTION OUTPUT ;
    USE SIGNAL ;
    SHAPE ABUTMENT ;
    PORT
      LAYER metal3 ;
      RECT 0.000 128.905 0.070 128.975 ;
    END
  END rd_out[197]
  PIN rd_out[198]
    DIRECTION OUTPUT ;
    USE SIGNAL ;
    SHAPE ABUTMENT ;
    PORT
      LAYER metal3 ;
      RECT 0.000 129.045 0.070 129.115 ;
    END
  END rd_out[198]
  PIN rd_out[199]
    DIRECTION OUTPUT ;
    USE SIGNAL ;
    SHAPE ABUTMENT ;
    PORT
      LAYER metal3 ;
      RECT 0.000 129.185 0.070 129.255 ;
    END
  END rd_out[199]
  PIN rd_out[200]
    DIRECTION OUTPUT ;
    USE SIGNAL ;
    SHAPE ABUTMENT ;
    PORT
      LAYER metal3 ;
      RECT 0.000 129.325 0.070 129.395 ;
    END
  END rd_out[200]
  PIN rd_out[201]
    DIRECTION OUTPUT ;
    USE SIGNAL ;
    SHAPE ABUTMENT ;
    PORT
      LAYER metal3 ;
      RECT 0.000 129.465 0.070 129.535 ;
    END
  END rd_out[201]
  PIN rd_out[202]
    DIRECTION OUTPUT ;
    USE SIGNAL ;
    SHAPE ABUTMENT ;
    PORT
      LAYER metal3 ;
      RECT 0.000 129.605 0.070 129.675 ;
    END
  END rd_out[202]
  PIN rd_out[203]
    DIRECTION OUTPUT ;
    USE SIGNAL ;
    SHAPE ABUTMENT ;
    PORT
      LAYER metal3 ;
      RECT 0.000 129.745 0.070 129.815 ;
    END
  END rd_out[203]
  PIN rd_out[204]
    DIRECTION OUTPUT ;
    USE SIGNAL ;
    SHAPE ABUTMENT ;
    PORT
      LAYER metal3 ;
      RECT 0.000 129.885 0.070 129.955 ;
    END
  END rd_out[204]
  PIN rd_out[205]
    DIRECTION OUTPUT ;
    USE SIGNAL ;
    SHAPE ABUTMENT ;
    PORT
      LAYER metal3 ;
      RECT 0.000 130.025 0.070 130.095 ;
    END
  END rd_out[205]
  PIN rd_out[206]
    DIRECTION OUTPUT ;
    USE SIGNAL ;
    SHAPE ABUTMENT ;
    PORT
      LAYER metal3 ;
      RECT 0.000 130.165 0.070 130.235 ;
    END
  END rd_out[206]
  PIN rd_out[207]
    DIRECTION OUTPUT ;
    USE SIGNAL ;
    SHAPE ABUTMENT ;
    PORT
      LAYER metal3 ;
      RECT 0.000 130.305 0.070 130.375 ;
    END
  END rd_out[207]
  PIN rd_out[208]
    DIRECTION OUTPUT ;
    USE SIGNAL ;
    SHAPE ABUTMENT ;
    PORT
      LAYER metal3 ;
      RECT 0.000 130.445 0.070 130.515 ;
    END
  END rd_out[208]
  PIN rd_out[209]
    DIRECTION OUTPUT ;
    USE SIGNAL ;
    SHAPE ABUTMENT ;
    PORT
      LAYER metal3 ;
      RECT 0.000 130.585 0.070 130.655 ;
    END
  END rd_out[209]
  PIN rd_out[210]
    DIRECTION OUTPUT ;
    USE SIGNAL ;
    SHAPE ABUTMENT ;
    PORT
      LAYER metal3 ;
      RECT 0.000 130.725 0.070 130.795 ;
    END
  END rd_out[210]
  PIN rd_out[211]
    DIRECTION OUTPUT ;
    USE SIGNAL ;
    SHAPE ABUTMENT ;
    PORT
      LAYER metal3 ;
      RECT 0.000 130.865 0.070 130.935 ;
    END
  END rd_out[211]
  PIN rd_out[212]
    DIRECTION OUTPUT ;
    USE SIGNAL ;
    SHAPE ABUTMENT ;
    PORT
      LAYER metal3 ;
      RECT 0.000 131.005 0.070 131.075 ;
    END
  END rd_out[212]
  PIN rd_out[213]
    DIRECTION OUTPUT ;
    USE SIGNAL ;
    SHAPE ABUTMENT ;
    PORT
      LAYER metal3 ;
      RECT 0.000 131.145 0.070 131.215 ;
    END
  END rd_out[213]
  PIN rd_out[214]
    DIRECTION OUTPUT ;
    USE SIGNAL ;
    SHAPE ABUTMENT ;
    PORT
      LAYER metal3 ;
      RECT 0.000 131.285 0.070 131.355 ;
    END
  END rd_out[214]
  PIN rd_out[215]
    DIRECTION OUTPUT ;
    USE SIGNAL ;
    SHAPE ABUTMENT ;
    PORT
      LAYER metal3 ;
      RECT 0.000 131.425 0.070 131.495 ;
    END
  END rd_out[215]
  PIN rd_out[216]
    DIRECTION OUTPUT ;
    USE SIGNAL ;
    SHAPE ABUTMENT ;
    PORT
      LAYER metal3 ;
      RECT 0.000 131.565 0.070 131.635 ;
    END
  END rd_out[216]
  PIN rd_out[217]
    DIRECTION OUTPUT ;
    USE SIGNAL ;
    SHAPE ABUTMENT ;
    PORT
      LAYER metal3 ;
      RECT 0.000 131.705 0.070 131.775 ;
    END
  END rd_out[217]
  PIN rd_out[218]
    DIRECTION OUTPUT ;
    USE SIGNAL ;
    SHAPE ABUTMENT ;
    PORT
      LAYER metal3 ;
      RECT 0.000 131.845 0.070 131.915 ;
    END
  END rd_out[218]
  PIN rd_out[219]
    DIRECTION OUTPUT ;
    USE SIGNAL ;
    SHAPE ABUTMENT ;
    PORT
      LAYER metal3 ;
      RECT 0.000 131.985 0.070 132.055 ;
    END
  END rd_out[219]
  PIN rd_out[220]
    DIRECTION OUTPUT ;
    USE SIGNAL ;
    SHAPE ABUTMENT ;
    PORT
      LAYER metal3 ;
      RECT 0.000 132.125 0.070 132.195 ;
    END
  END rd_out[220]
  PIN rd_out[221]
    DIRECTION OUTPUT ;
    USE SIGNAL ;
    SHAPE ABUTMENT ;
    PORT
      LAYER metal3 ;
      RECT 0.000 132.265 0.070 132.335 ;
    END
  END rd_out[221]
  PIN rd_out[222]
    DIRECTION OUTPUT ;
    USE SIGNAL ;
    SHAPE ABUTMENT ;
    PORT
      LAYER metal3 ;
      RECT 0.000 132.405 0.070 132.475 ;
    END
  END rd_out[222]
  PIN rd_out[223]
    DIRECTION OUTPUT ;
    USE SIGNAL ;
    SHAPE ABUTMENT ;
    PORT
      LAYER metal3 ;
      RECT 0.000 132.545 0.070 132.615 ;
    END
  END rd_out[223]
  PIN rd_out[224]
    DIRECTION OUTPUT ;
    USE SIGNAL ;
    SHAPE ABUTMENT ;
    PORT
      LAYER metal3 ;
      RECT 0.000 132.685 0.070 132.755 ;
    END
  END rd_out[224]
  PIN rd_out[225]
    DIRECTION OUTPUT ;
    USE SIGNAL ;
    SHAPE ABUTMENT ;
    PORT
      LAYER metal3 ;
      RECT 0.000 132.825 0.070 132.895 ;
    END
  END rd_out[225]
  PIN rd_out[226]
    DIRECTION OUTPUT ;
    USE SIGNAL ;
    SHAPE ABUTMENT ;
    PORT
      LAYER metal3 ;
      RECT 0.000 132.965 0.070 133.035 ;
    END
  END rd_out[226]
  PIN rd_out[227]
    DIRECTION OUTPUT ;
    USE SIGNAL ;
    SHAPE ABUTMENT ;
    PORT
      LAYER metal3 ;
      RECT 0.000 133.105 0.070 133.175 ;
    END
  END rd_out[227]
  PIN rd_out[228]
    DIRECTION OUTPUT ;
    USE SIGNAL ;
    SHAPE ABUTMENT ;
    PORT
      LAYER metal3 ;
      RECT 0.000 133.245 0.070 133.315 ;
    END
  END rd_out[228]
  PIN rd_out[229]
    DIRECTION OUTPUT ;
    USE SIGNAL ;
    SHAPE ABUTMENT ;
    PORT
      LAYER metal3 ;
      RECT 0.000 133.385 0.070 133.455 ;
    END
  END rd_out[229]
  PIN rd_out[230]
    DIRECTION OUTPUT ;
    USE SIGNAL ;
    SHAPE ABUTMENT ;
    PORT
      LAYER metal3 ;
      RECT 0.000 133.525 0.070 133.595 ;
    END
  END rd_out[230]
  PIN rd_out[231]
    DIRECTION OUTPUT ;
    USE SIGNAL ;
    SHAPE ABUTMENT ;
    PORT
      LAYER metal3 ;
      RECT 0.000 133.665 0.070 133.735 ;
    END
  END rd_out[231]
  PIN rd_out[232]
    DIRECTION OUTPUT ;
    USE SIGNAL ;
    SHAPE ABUTMENT ;
    PORT
      LAYER metal3 ;
      RECT 0.000 133.805 0.070 133.875 ;
    END
  END rd_out[232]
  PIN rd_out[233]
    DIRECTION OUTPUT ;
    USE SIGNAL ;
    SHAPE ABUTMENT ;
    PORT
      LAYER metal3 ;
      RECT 0.000 133.945 0.070 134.015 ;
    END
  END rd_out[233]
  PIN rd_out[234]
    DIRECTION OUTPUT ;
    USE SIGNAL ;
    SHAPE ABUTMENT ;
    PORT
      LAYER metal3 ;
      RECT 0.000 134.085 0.070 134.155 ;
    END
  END rd_out[234]
  PIN rd_out[235]
    DIRECTION OUTPUT ;
    USE SIGNAL ;
    SHAPE ABUTMENT ;
    PORT
      LAYER metal3 ;
      RECT 0.000 134.225 0.070 134.295 ;
    END
  END rd_out[235]
  PIN rd_out[236]
    DIRECTION OUTPUT ;
    USE SIGNAL ;
    SHAPE ABUTMENT ;
    PORT
      LAYER metal3 ;
      RECT 0.000 134.365 0.070 134.435 ;
    END
  END rd_out[236]
  PIN rd_out[237]
    DIRECTION OUTPUT ;
    USE SIGNAL ;
    SHAPE ABUTMENT ;
    PORT
      LAYER metal3 ;
      RECT 0.000 134.505 0.070 134.575 ;
    END
  END rd_out[237]
  PIN rd_out[238]
    DIRECTION OUTPUT ;
    USE SIGNAL ;
    SHAPE ABUTMENT ;
    PORT
      LAYER metal3 ;
      RECT 0.000 134.645 0.070 134.715 ;
    END
  END rd_out[238]
  PIN rd_out[239]
    DIRECTION OUTPUT ;
    USE SIGNAL ;
    SHAPE ABUTMENT ;
    PORT
      LAYER metal3 ;
      RECT 0.000 134.785 0.070 134.855 ;
    END
  END rd_out[239]
  PIN rd_out[240]
    DIRECTION OUTPUT ;
    USE SIGNAL ;
    SHAPE ABUTMENT ;
    PORT
      LAYER metal3 ;
      RECT 0.000 134.925 0.070 134.995 ;
    END
  END rd_out[240]
  PIN rd_out[241]
    DIRECTION OUTPUT ;
    USE SIGNAL ;
    SHAPE ABUTMENT ;
    PORT
      LAYER metal3 ;
      RECT 0.000 135.065 0.070 135.135 ;
    END
  END rd_out[241]
  PIN rd_out[242]
    DIRECTION OUTPUT ;
    USE SIGNAL ;
    SHAPE ABUTMENT ;
    PORT
      LAYER metal3 ;
      RECT 0.000 135.205 0.070 135.275 ;
    END
  END rd_out[242]
  PIN rd_out[243]
    DIRECTION OUTPUT ;
    USE SIGNAL ;
    SHAPE ABUTMENT ;
    PORT
      LAYER metal3 ;
      RECT 0.000 135.345 0.070 135.415 ;
    END
  END rd_out[243]
  PIN rd_out[244]
    DIRECTION OUTPUT ;
    USE SIGNAL ;
    SHAPE ABUTMENT ;
    PORT
      LAYER metal3 ;
      RECT 0.000 135.485 0.070 135.555 ;
    END
  END rd_out[244]
  PIN rd_out[245]
    DIRECTION OUTPUT ;
    USE SIGNAL ;
    SHAPE ABUTMENT ;
    PORT
      LAYER metal3 ;
      RECT 0.000 135.625 0.070 135.695 ;
    END
  END rd_out[245]
  PIN rd_out[246]
    DIRECTION OUTPUT ;
    USE SIGNAL ;
    SHAPE ABUTMENT ;
    PORT
      LAYER metal3 ;
      RECT 0.000 135.765 0.070 135.835 ;
    END
  END rd_out[246]
  PIN rd_out[247]
    DIRECTION OUTPUT ;
    USE SIGNAL ;
    SHAPE ABUTMENT ;
    PORT
      LAYER metal3 ;
      RECT 0.000 135.905 0.070 135.975 ;
    END
  END rd_out[247]
  PIN rd_out[248]
    DIRECTION OUTPUT ;
    USE SIGNAL ;
    SHAPE ABUTMENT ;
    PORT
      LAYER metal3 ;
      RECT 0.000 136.045 0.070 136.115 ;
    END
  END rd_out[248]
  PIN rd_out[249]
    DIRECTION OUTPUT ;
    USE SIGNAL ;
    SHAPE ABUTMENT ;
    PORT
      LAYER metal3 ;
      RECT 0.000 136.185 0.070 136.255 ;
    END
  END rd_out[249]
  PIN rd_out[250]
    DIRECTION OUTPUT ;
    USE SIGNAL ;
    SHAPE ABUTMENT ;
    PORT
      LAYER metal3 ;
      RECT 0.000 136.325 0.070 136.395 ;
    END
  END rd_out[250]
  PIN rd_out[251]
    DIRECTION OUTPUT ;
    USE SIGNAL ;
    SHAPE ABUTMENT ;
    PORT
      LAYER metal3 ;
      RECT 0.000 136.465 0.070 136.535 ;
    END
  END rd_out[251]
  PIN rd_out[252]
    DIRECTION OUTPUT ;
    USE SIGNAL ;
    SHAPE ABUTMENT ;
    PORT
      LAYER metal3 ;
      RECT 0.000 136.605 0.070 136.675 ;
    END
  END rd_out[252]
  PIN rd_out[253]
    DIRECTION OUTPUT ;
    USE SIGNAL ;
    SHAPE ABUTMENT ;
    PORT
      LAYER metal3 ;
      RECT 0.000 136.745 0.070 136.815 ;
    END
  END rd_out[253]
  PIN rd_out[254]
    DIRECTION OUTPUT ;
    USE SIGNAL ;
    SHAPE ABUTMENT ;
    PORT
      LAYER metal3 ;
      RECT 0.000 136.885 0.070 136.955 ;
    END
  END rd_out[254]
  PIN rd_out[255]
    DIRECTION OUTPUT ;
    USE SIGNAL ;
    SHAPE ABUTMENT ;
    PORT
      LAYER metal3 ;
      RECT 0.000 137.025 0.070 137.095 ;
    END
  END rd_out[255]
  PIN rd_out[256]
    DIRECTION OUTPUT ;
    USE SIGNAL ;
    SHAPE ABUTMENT ;
    PORT
      LAYER metal3 ;
      RECT 0.000 137.165 0.070 137.235 ;
    END
  END rd_out[256]
  PIN rd_out[257]
    DIRECTION OUTPUT ;
    USE SIGNAL ;
    SHAPE ABUTMENT ;
    PORT
      LAYER metal3 ;
      RECT 0.000 137.305 0.070 137.375 ;
    END
  END rd_out[257]
  PIN rd_out[258]
    DIRECTION OUTPUT ;
    USE SIGNAL ;
    SHAPE ABUTMENT ;
    PORT
      LAYER metal3 ;
      RECT 0.000 137.445 0.070 137.515 ;
    END
  END rd_out[258]
  PIN rd_out[259]
    DIRECTION OUTPUT ;
    USE SIGNAL ;
    SHAPE ABUTMENT ;
    PORT
      LAYER metal3 ;
      RECT 0.000 137.585 0.070 137.655 ;
    END
  END rd_out[259]
  PIN rd_out[260]
    DIRECTION OUTPUT ;
    USE SIGNAL ;
    SHAPE ABUTMENT ;
    PORT
      LAYER metal3 ;
      RECT 0.000 137.725 0.070 137.795 ;
    END
  END rd_out[260]
  PIN rd_out[261]
    DIRECTION OUTPUT ;
    USE SIGNAL ;
    SHAPE ABUTMENT ;
    PORT
      LAYER metal3 ;
      RECT 0.000 137.865 0.070 137.935 ;
    END
  END rd_out[261]
  PIN rd_out[262]
    DIRECTION OUTPUT ;
    USE SIGNAL ;
    SHAPE ABUTMENT ;
    PORT
      LAYER metal3 ;
      RECT 0.000 138.005 0.070 138.075 ;
    END
  END rd_out[262]
  PIN rd_out[263]
    DIRECTION OUTPUT ;
    USE SIGNAL ;
    SHAPE ABUTMENT ;
    PORT
      LAYER metal3 ;
      RECT 0.000 138.145 0.070 138.215 ;
    END
  END rd_out[263]
  PIN rd_out[264]
    DIRECTION OUTPUT ;
    USE SIGNAL ;
    SHAPE ABUTMENT ;
    PORT
      LAYER metal3 ;
      RECT 0.000 138.285 0.070 138.355 ;
    END
  END rd_out[264]
  PIN rd_out[265]
    DIRECTION OUTPUT ;
    USE SIGNAL ;
    SHAPE ABUTMENT ;
    PORT
      LAYER metal3 ;
      RECT 0.000 138.425 0.070 138.495 ;
    END
  END rd_out[265]
  PIN rd_out[266]
    DIRECTION OUTPUT ;
    USE SIGNAL ;
    SHAPE ABUTMENT ;
    PORT
      LAYER metal3 ;
      RECT 0.000 138.565 0.070 138.635 ;
    END
  END rd_out[266]
  PIN rd_out[267]
    DIRECTION OUTPUT ;
    USE SIGNAL ;
    SHAPE ABUTMENT ;
    PORT
      LAYER metal3 ;
      RECT 0.000 138.705 0.070 138.775 ;
    END
  END rd_out[267]
  PIN rd_out[268]
    DIRECTION OUTPUT ;
    USE SIGNAL ;
    SHAPE ABUTMENT ;
    PORT
      LAYER metal3 ;
      RECT 0.000 138.845 0.070 138.915 ;
    END
  END rd_out[268]
  PIN rd_out[269]
    DIRECTION OUTPUT ;
    USE SIGNAL ;
    SHAPE ABUTMENT ;
    PORT
      LAYER metal3 ;
      RECT 0.000 138.985 0.070 139.055 ;
    END
  END rd_out[269]
  PIN rd_out[270]
    DIRECTION OUTPUT ;
    USE SIGNAL ;
    SHAPE ABUTMENT ;
    PORT
      LAYER metal3 ;
      RECT 0.000 139.125 0.070 139.195 ;
    END
  END rd_out[270]
  PIN rd_out[271]
    DIRECTION OUTPUT ;
    USE SIGNAL ;
    SHAPE ABUTMENT ;
    PORT
      LAYER metal3 ;
      RECT 0.000 139.265 0.070 139.335 ;
    END
  END rd_out[271]
  PIN rd_out[272]
    DIRECTION OUTPUT ;
    USE SIGNAL ;
    SHAPE ABUTMENT ;
    PORT
      LAYER metal3 ;
      RECT 0.000 139.405 0.070 139.475 ;
    END
  END rd_out[272]
  PIN rd_out[273]
    DIRECTION OUTPUT ;
    USE SIGNAL ;
    SHAPE ABUTMENT ;
    PORT
      LAYER metal3 ;
      RECT 0.000 139.545 0.070 139.615 ;
    END
  END rd_out[273]
  PIN rd_out[274]
    DIRECTION OUTPUT ;
    USE SIGNAL ;
    SHAPE ABUTMENT ;
    PORT
      LAYER metal3 ;
      RECT 0.000 139.685 0.070 139.755 ;
    END
  END rd_out[274]
  PIN rd_out[275]
    DIRECTION OUTPUT ;
    USE SIGNAL ;
    SHAPE ABUTMENT ;
    PORT
      LAYER metal3 ;
      RECT 0.000 139.825 0.070 139.895 ;
    END
  END rd_out[275]
  PIN rd_out[276]
    DIRECTION OUTPUT ;
    USE SIGNAL ;
    SHAPE ABUTMENT ;
    PORT
      LAYER metal3 ;
      RECT 0.000 139.965 0.070 140.035 ;
    END
  END rd_out[276]
  PIN rd_out[277]
    DIRECTION OUTPUT ;
    USE SIGNAL ;
    SHAPE ABUTMENT ;
    PORT
      LAYER metal3 ;
      RECT 0.000 140.105 0.070 140.175 ;
    END
  END rd_out[277]
  PIN rd_out[278]
    DIRECTION OUTPUT ;
    USE SIGNAL ;
    SHAPE ABUTMENT ;
    PORT
      LAYER metal3 ;
      RECT 0.000 140.245 0.070 140.315 ;
    END
  END rd_out[278]
  PIN rd_out[279]
    DIRECTION OUTPUT ;
    USE SIGNAL ;
    SHAPE ABUTMENT ;
    PORT
      LAYER metal3 ;
      RECT 0.000 140.385 0.070 140.455 ;
    END
  END rd_out[279]
  PIN rd_out[280]
    DIRECTION OUTPUT ;
    USE SIGNAL ;
    SHAPE ABUTMENT ;
    PORT
      LAYER metal3 ;
      RECT 0.000 140.525 0.070 140.595 ;
    END
  END rd_out[280]
  PIN rd_out[281]
    DIRECTION OUTPUT ;
    USE SIGNAL ;
    SHAPE ABUTMENT ;
    PORT
      LAYER metal3 ;
      RECT 0.000 140.665 0.070 140.735 ;
    END
  END rd_out[281]
  PIN rd_out[282]
    DIRECTION OUTPUT ;
    USE SIGNAL ;
    SHAPE ABUTMENT ;
    PORT
      LAYER metal3 ;
      RECT 0.000 140.805 0.070 140.875 ;
    END
  END rd_out[282]
  PIN rd_out[283]
    DIRECTION OUTPUT ;
    USE SIGNAL ;
    SHAPE ABUTMENT ;
    PORT
      LAYER metal3 ;
      RECT 0.000 140.945 0.070 141.015 ;
    END
  END rd_out[283]
  PIN rd_out[284]
    DIRECTION OUTPUT ;
    USE SIGNAL ;
    SHAPE ABUTMENT ;
    PORT
      LAYER metal3 ;
      RECT 0.000 141.085 0.070 141.155 ;
    END
  END rd_out[284]
  PIN rd_out[285]
    DIRECTION OUTPUT ;
    USE SIGNAL ;
    SHAPE ABUTMENT ;
    PORT
      LAYER metal3 ;
      RECT 0.000 141.225 0.070 141.295 ;
    END
  END rd_out[285]
  PIN rd_out[286]
    DIRECTION OUTPUT ;
    USE SIGNAL ;
    SHAPE ABUTMENT ;
    PORT
      LAYER metal3 ;
      RECT 0.000 141.365 0.070 141.435 ;
    END
  END rd_out[286]
  PIN rd_out[287]
    DIRECTION OUTPUT ;
    USE SIGNAL ;
    SHAPE ABUTMENT ;
    PORT
      LAYER metal3 ;
      RECT 0.000 141.505 0.070 141.575 ;
    END
  END rd_out[287]
  PIN rd_out[288]
    DIRECTION OUTPUT ;
    USE SIGNAL ;
    SHAPE ABUTMENT ;
    PORT
      LAYER metal3 ;
      RECT 0.000 141.645 0.070 141.715 ;
    END
  END rd_out[288]
  PIN rd_out[289]
    DIRECTION OUTPUT ;
    USE SIGNAL ;
    SHAPE ABUTMENT ;
    PORT
      LAYER metal3 ;
      RECT 0.000 141.785 0.070 141.855 ;
    END
  END rd_out[289]
  PIN rd_out[290]
    DIRECTION OUTPUT ;
    USE SIGNAL ;
    SHAPE ABUTMENT ;
    PORT
      LAYER metal3 ;
      RECT 0.000 141.925 0.070 141.995 ;
    END
  END rd_out[290]
  PIN rd_out[291]
    DIRECTION OUTPUT ;
    USE SIGNAL ;
    SHAPE ABUTMENT ;
    PORT
      LAYER metal3 ;
      RECT 0.000 142.065 0.070 142.135 ;
    END
  END rd_out[291]
  PIN rd_out[292]
    DIRECTION OUTPUT ;
    USE SIGNAL ;
    SHAPE ABUTMENT ;
    PORT
      LAYER metal3 ;
      RECT 0.000 142.205 0.070 142.275 ;
    END
  END rd_out[292]
  PIN rd_out[293]
    DIRECTION OUTPUT ;
    USE SIGNAL ;
    SHAPE ABUTMENT ;
    PORT
      LAYER metal3 ;
      RECT 0.000 142.345 0.070 142.415 ;
    END
  END rd_out[293]
  PIN rd_out[294]
    DIRECTION OUTPUT ;
    USE SIGNAL ;
    SHAPE ABUTMENT ;
    PORT
      LAYER metal3 ;
      RECT 0.000 142.485 0.070 142.555 ;
    END
  END rd_out[294]
  PIN rd_out[295]
    DIRECTION OUTPUT ;
    USE SIGNAL ;
    SHAPE ABUTMENT ;
    PORT
      LAYER metal3 ;
      RECT 0.000 142.625 0.070 142.695 ;
    END
  END rd_out[295]
  PIN rd_out[296]
    DIRECTION OUTPUT ;
    USE SIGNAL ;
    SHAPE ABUTMENT ;
    PORT
      LAYER metal3 ;
      RECT 0.000 142.765 0.070 142.835 ;
    END
  END rd_out[296]
  PIN rd_out[297]
    DIRECTION OUTPUT ;
    USE SIGNAL ;
    SHAPE ABUTMENT ;
    PORT
      LAYER metal3 ;
      RECT 0.000 142.905 0.070 142.975 ;
    END
  END rd_out[297]
  PIN rd_out[298]
    DIRECTION OUTPUT ;
    USE SIGNAL ;
    SHAPE ABUTMENT ;
    PORT
      LAYER metal3 ;
      RECT 0.000 143.045 0.070 143.115 ;
    END
  END rd_out[298]
  PIN rd_out[299]
    DIRECTION OUTPUT ;
    USE SIGNAL ;
    SHAPE ABUTMENT ;
    PORT
      LAYER metal3 ;
      RECT 0.000 143.185 0.070 143.255 ;
    END
  END rd_out[299]
  PIN rd_out[300]
    DIRECTION OUTPUT ;
    USE SIGNAL ;
    SHAPE ABUTMENT ;
    PORT
      LAYER metal3 ;
      RECT 0.000 143.325 0.070 143.395 ;
    END
  END rd_out[300]
  PIN rd_out[301]
    DIRECTION OUTPUT ;
    USE SIGNAL ;
    SHAPE ABUTMENT ;
    PORT
      LAYER metal3 ;
      RECT 0.000 143.465 0.070 143.535 ;
    END
  END rd_out[301]
  PIN rd_out[302]
    DIRECTION OUTPUT ;
    USE SIGNAL ;
    SHAPE ABUTMENT ;
    PORT
      LAYER metal3 ;
      RECT 0.000 143.605 0.070 143.675 ;
    END
  END rd_out[302]
  PIN rd_out[303]
    DIRECTION OUTPUT ;
    USE SIGNAL ;
    SHAPE ABUTMENT ;
    PORT
      LAYER metal3 ;
      RECT 0.000 143.745 0.070 143.815 ;
    END
  END rd_out[303]
  PIN rd_out[304]
    DIRECTION OUTPUT ;
    USE SIGNAL ;
    SHAPE ABUTMENT ;
    PORT
      LAYER metal3 ;
      RECT 0.000 143.885 0.070 143.955 ;
    END
  END rd_out[304]
  PIN rd_out[305]
    DIRECTION OUTPUT ;
    USE SIGNAL ;
    SHAPE ABUTMENT ;
    PORT
      LAYER metal3 ;
      RECT 0.000 144.025 0.070 144.095 ;
    END
  END rd_out[305]
  PIN rd_out[306]
    DIRECTION OUTPUT ;
    USE SIGNAL ;
    SHAPE ABUTMENT ;
    PORT
      LAYER metal3 ;
      RECT 0.000 144.165 0.070 144.235 ;
    END
  END rd_out[306]
  PIN rd_out[307]
    DIRECTION OUTPUT ;
    USE SIGNAL ;
    SHAPE ABUTMENT ;
    PORT
      LAYER metal3 ;
      RECT 0.000 144.305 0.070 144.375 ;
    END
  END rd_out[307]
  PIN rd_out[308]
    DIRECTION OUTPUT ;
    USE SIGNAL ;
    SHAPE ABUTMENT ;
    PORT
      LAYER metal3 ;
      RECT 0.000 144.445 0.070 144.515 ;
    END
  END rd_out[308]
  PIN rd_out[309]
    DIRECTION OUTPUT ;
    USE SIGNAL ;
    SHAPE ABUTMENT ;
    PORT
      LAYER metal3 ;
      RECT 0.000 144.585 0.070 144.655 ;
    END
  END rd_out[309]
  PIN rd_out[310]
    DIRECTION OUTPUT ;
    USE SIGNAL ;
    SHAPE ABUTMENT ;
    PORT
      LAYER metal3 ;
      RECT 0.000 144.725 0.070 144.795 ;
    END
  END rd_out[310]
  PIN rd_out[311]
    DIRECTION OUTPUT ;
    USE SIGNAL ;
    SHAPE ABUTMENT ;
    PORT
      LAYER metal3 ;
      RECT 0.000 144.865 0.070 144.935 ;
    END
  END rd_out[311]
  PIN rd_out[312]
    DIRECTION OUTPUT ;
    USE SIGNAL ;
    SHAPE ABUTMENT ;
    PORT
      LAYER metal3 ;
      RECT 0.000 145.005 0.070 145.075 ;
    END
  END rd_out[312]
  PIN rd_out[313]
    DIRECTION OUTPUT ;
    USE SIGNAL ;
    SHAPE ABUTMENT ;
    PORT
      LAYER metal3 ;
      RECT 0.000 145.145 0.070 145.215 ;
    END
  END rd_out[313]
  PIN rd_out[314]
    DIRECTION OUTPUT ;
    USE SIGNAL ;
    SHAPE ABUTMENT ;
    PORT
      LAYER metal3 ;
      RECT 0.000 145.285 0.070 145.355 ;
    END
  END rd_out[314]
  PIN rd_out[315]
    DIRECTION OUTPUT ;
    USE SIGNAL ;
    SHAPE ABUTMENT ;
    PORT
      LAYER metal3 ;
      RECT 0.000 145.425 0.070 145.495 ;
    END
  END rd_out[315]
  PIN rd_out[316]
    DIRECTION OUTPUT ;
    USE SIGNAL ;
    SHAPE ABUTMENT ;
    PORT
      LAYER metal3 ;
      RECT 0.000 145.565 0.070 145.635 ;
    END
  END rd_out[316]
  PIN rd_out[317]
    DIRECTION OUTPUT ;
    USE SIGNAL ;
    SHAPE ABUTMENT ;
    PORT
      LAYER metal3 ;
      RECT 0.000 145.705 0.070 145.775 ;
    END
  END rd_out[317]
  PIN rd_out[318]
    DIRECTION OUTPUT ;
    USE SIGNAL ;
    SHAPE ABUTMENT ;
    PORT
      LAYER metal3 ;
      RECT 0.000 145.845 0.070 145.915 ;
    END
  END rd_out[318]
  PIN rd_out[319]
    DIRECTION OUTPUT ;
    USE SIGNAL ;
    SHAPE ABUTMENT ;
    PORT
      LAYER metal3 ;
      RECT 0.000 145.985 0.070 146.055 ;
    END
  END rd_out[319]
  PIN rd_out[320]
    DIRECTION OUTPUT ;
    USE SIGNAL ;
    SHAPE ABUTMENT ;
    PORT
      LAYER metal3 ;
      RECT 0.000 146.125 0.070 146.195 ;
    END
  END rd_out[320]
  PIN rd_out[321]
    DIRECTION OUTPUT ;
    USE SIGNAL ;
    SHAPE ABUTMENT ;
    PORT
      LAYER metal3 ;
      RECT 0.000 146.265 0.070 146.335 ;
    END
  END rd_out[321]
  PIN rd_out[322]
    DIRECTION OUTPUT ;
    USE SIGNAL ;
    SHAPE ABUTMENT ;
    PORT
      LAYER metal3 ;
      RECT 0.000 146.405 0.070 146.475 ;
    END
  END rd_out[322]
  PIN rd_out[323]
    DIRECTION OUTPUT ;
    USE SIGNAL ;
    SHAPE ABUTMENT ;
    PORT
      LAYER metal3 ;
      RECT 0.000 146.545 0.070 146.615 ;
    END
  END rd_out[323]
  PIN rd_out[324]
    DIRECTION OUTPUT ;
    USE SIGNAL ;
    SHAPE ABUTMENT ;
    PORT
      LAYER metal3 ;
      RECT 0.000 146.685 0.070 146.755 ;
    END
  END rd_out[324]
  PIN rd_out[325]
    DIRECTION OUTPUT ;
    USE SIGNAL ;
    SHAPE ABUTMENT ;
    PORT
      LAYER metal3 ;
      RECT 0.000 146.825 0.070 146.895 ;
    END
  END rd_out[325]
  PIN rd_out[326]
    DIRECTION OUTPUT ;
    USE SIGNAL ;
    SHAPE ABUTMENT ;
    PORT
      LAYER metal3 ;
      RECT 0.000 146.965 0.070 147.035 ;
    END
  END rd_out[326]
  PIN rd_out[327]
    DIRECTION OUTPUT ;
    USE SIGNAL ;
    SHAPE ABUTMENT ;
    PORT
      LAYER metal3 ;
      RECT 0.000 147.105 0.070 147.175 ;
    END
  END rd_out[327]
  PIN rd_out[328]
    DIRECTION OUTPUT ;
    USE SIGNAL ;
    SHAPE ABUTMENT ;
    PORT
      LAYER metal3 ;
      RECT 0.000 147.245 0.070 147.315 ;
    END
  END rd_out[328]
  PIN rd_out[329]
    DIRECTION OUTPUT ;
    USE SIGNAL ;
    SHAPE ABUTMENT ;
    PORT
      LAYER metal3 ;
      RECT 0.000 147.385 0.070 147.455 ;
    END
  END rd_out[329]
  PIN rd_out[330]
    DIRECTION OUTPUT ;
    USE SIGNAL ;
    SHAPE ABUTMENT ;
    PORT
      LAYER metal3 ;
      RECT 0.000 147.525 0.070 147.595 ;
    END
  END rd_out[330]
  PIN rd_out[331]
    DIRECTION OUTPUT ;
    USE SIGNAL ;
    SHAPE ABUTMENT ;
    PORT
      LAYER metal3 ;
      RECT 0.000 147.665 0.070 147.735 ;
    END
  END rd_out[331]
  PIN rd_out[332]
    DIRECTION OUTPUT ;
    USE SIGNAL ;
    SHAPE ABUTMENT ;
    PORT
      LAYER metal3 ;
      RECT 0.000 147.805 0.070 147.875 ;
    END
  END rd_out[332]
  PIN rd_out[333]
    DIRECTION OUTPUT ;
    USE SIGNAL ;
    SHAPE ABUTMENT ;
    PORT
      LAYER metal3 ;
      RECT 0.000 147.945 0.070 148.015 ;
    END
  END rd_out[333]
  PIN rd_out[334]
    DIRECTION OUTPUT ;
    USE SIGNAL ;
    SHAPE ABUTMENT ;
    PORT
      LAYER metal3 ;
      RECT 0.000 148.085 0.070 148.155 ;
    END
  END rd_out[334]
  PIN rd_out[335]
    DIRECTION OUTPUT ;
    USE SIGNAL ;
    SHAPE ABUTMENT ;
    PORT
      LAYER metal3 ;
      RECT 0.000 148.225 0.070 148.295 ;
    END
  END rd_out[335]
  PIN rd_out[336]
    DIRECTION OUTPUT ;
    USE SIGNAL ;
    SHAPE ABUTMENT ;
    PORT
      LAYER metal3 ;
      RECT 0.000 148.365 0.070 148.435 ;
    END
  END rd_out[336]
  PIN rd_out[337]
    DIRECTION OUTPUT ;
    USE SIGNAL ;
    SHAPE ABUTMENT ;
    PORT
      LAYER metal3 ;
      RECT 0.000 148.505 0.070 148.575 ;
    END
  END rd_out[337]
  PIN rd_out[338]
    DIRECTION OUTPUT ;
    USE SIGNAL ;
    SHAPE ABUTMENT ;
    PORT
      LAYER metal3 ;
      RECT 0.000 148.645 0.070 148.715 ;
    END
  END rd_out[338]
  PIN rd_out[339]
    DIRECTION OUTPUT ;
    USE SIGNAL ;
    SHAPE ABUTMENT ;
    PORT
      LAYER metal3 ;
      RECT 0.000 148.785 0.070 148.855 ;
    END
  END rd_out[339]
  PIN rd_out[340]
    DIRECTION OUTPUT ;
    USE SIGNAL ;
    SHAPE ABUTMENT ;
    PORT
      LAYER metal3 ;
      RECT 0.000 148.925 0.070 148.995 ;
    END
  END rd_out[340]
  PIN rd_out[341]
    DIRECTION OUTPUT ;
    USE SIGNAL ;
    SHAPE ABUTMENT ;
    PORT
      LAYER metal3 ;
      RECT 0.000 149.065 0.070 149.135 ;
    END
  END rd_out[341]
  PIN rd_out[342]
    DIRECTION OUTPUT ;
    USE SIGNAL ;
    SHAPE ABUTMENT ;
    PORT
      LAYER metal3 ;
      RECT 0.000 149.205 0.070 149.275 ;
    END
  END rd_out[342]
  PIN rd_out[343]
    DIRECTION OUTPUT ;
    USE SIGNAL ;
    SHAPE ABUTMENT ;
    PORT
      LAYER metal3 ;
      RECT 0.000 149.345 0.070 149.415 ;
    END
  END rd_out[343]
  PIN rd_out[344]
    DIRECTION OUTPUT ;
    USE SIGNAL ;
    SHAPE ABUTMENT ;
    PORT
      LAYER metal3 ;
      RECT 0.000 149.485 0.070 149.555 ;
    END
  END rd_out[344]
  PIN rd_out[345]
    DIRECTION OUTPUT ;
    USE SIGNAL ;
    SHAPE ABUTMENT ;
    PORT
      LAYER metal3 ;
      RECT 0.000 149.625 0.070 149.695 ;
    END
  END rd_out[345]
  PIN rd_out[346]
    DIRECTION OUTPUT ;
    USE SIGNAL ;
    SHAPE ABUTMENT ;
    PORT
      LAYER metal3 ;
      RECT 0.000 149.765 0.070 149.835 ;
    END
  END rd_out[346]
  PIN rd_out[347]
    DIRECTION OUTPUT ;
    USE SIGNAL ;
    SHAPE ABUTMENT ;
    PORT
      LAYER metal3 ;
      RECT 0.000 149.905 0.070 149.975 ;
    END
  END rd_out[347]
  PIN rd_out[348]
    DIRECTION OUTPUT ;
    USE SIGNAL ;
    SHAPE ABUTMENT ;
    PORT
      LAYER metal3 ;
      RECT 0.000 150.045 0.070 150.115 ;
    END
  END rd_out[348]
  PIN rd_out[349]
    DIRECTION OUTPUT ;
    USE SIGNAL ;
    SHAPE ABUTMENT ;
    PORT
      LAYER metal3 ;
      RECT 0.000 150.185 0.070 150.255 ;
    END
  END rd_out[349]
  PIN rd_out[350]
    DIRECTION OUTPUT ;
    USE SIGNAL ;
    SHAPE ABUTMENT ;
    PORT
      LAYER metal3 ;
      RECT 0.000 150.325 0.070 150.395 ;
    END
  END rd_out[350]
  PIN rd_out[351]
    DIRECTION OUTPUT ;
    USE SIGNAL ;
    SHAPE ABUTMENT ;
    PORT
      LAYER metal3 ;
      RECT 0.000 150.465 0.070 150.535 ;
    END
  END rd_out[351]
  PIN rd_out[352]
    DIRECTION OUTPUT ;
    USE SIGNAL ;
    SHAPE ABUTMENT ;
    PORT
      LAYER metal3 ;
      RECT 0.000 150.605 0.070 150.675 ;
    END
  END rd_out[352]
  PIN rd_out[353]
    DIRECTION OUTPUT ;
    USE SIGNAL ;
    SHAPE ABUTMENT ;
    PORT
      LAYER metal3 ;
      RECT 0.000 150.745 0.070 150.815 ;
    END
  END rd_out[353]
  PIN rd_out[354]
    DIRECTION OUTPUT ;
    USE SIGNAL ;
    SHAPE ABUTMENT ;
    PORT
      LAYER metal3 ;
      RECT 0.000 150.885 0.070 150.955 ;
    END
  END rd_out[354]
  PIN rd_out[355]
    DIRECTION OUTPUT ;
    USE SIGNAL ;
    SHAPE ABUTMENT ;
    PORT
      LAYER metal3 ;
      RECT 0.000 151.025 0.070 151.095 ;
    END
  END rd_out[355]
  PIN rd_out[356]
    DIRECTION OUTPUT ;
    USE SIGNAL ;
    SHAPE ABUTMENT ;
    PORT
      LAYER metal3 ;
      RECT 0.000 151.165 0.070 151.235 ;
    END
  END rd_out[356]
  PIN rd_out[357]
    DIRECTION OUTPUT ;
    USE SIGNAL ;
    SHAPE ABUTMENT ;
    PORT
      LAYER metal3 ;
      RECT 0.000 151.305 0.070 151.375 ;
    END
  END rd_out[357]
  PIN rd_out[358]
    DIRECTION OUTPUT ;
    USE SIGNAL ;
    SHAPE ABUTMENT ;
    PORT
      LAYER metal3 ;
      RECT 0.000 151.445 0.070 151.515 ;
    END
  END rd_out[358]
  PIN rd_out[359]
    DIRECTION OUTPUT ;
    USE SIGNAL ;
    SHAPE ABUTMENT ;
    PORT
      LAYER metal3 ;
      RECT 0.000 151.585 0.070 151.655 ;
    END
  END rd_out[359]
  PIN rd_out[360]
    DIRECTION OUTPUT ;
    USE SIGNAL ;
    SHAPE ABUTMENT ;
    PORT
      LAYER metal3 ;
      RECT 0.000 151.725 0.070 151.795 ;
    END
  END rd_out[360]
  PIN rd_out[361]
    DIRECTION OUTPUT ;
    USE SIGNAL ;
    SHAPE ABUTMENT ;
    PORT
      LAYER metal3 ;
      RECT 0.000 151.865 0.070 151.935 ;
    END
  END rd_out[361]
  PIN rd_out[362]
    DIRECTION OUTPUT ;
    USE SIGNAL ;
    SHAPE ABUTMENT ;
    PORT
      LAYER metal3 ;
      RECT 0.000 152.005 0.070 152.075 ;
    END
  END rd_out[362]
  PIN rd_out[363]
    DIRECTION OUTPUT ;
    USE SIGNAL ;
    SHAPE ABUTMENT ;
    PORT
      LAYER metal3 ;
      RECT 0.000 152.145 0.070 152.215 ;
    END
  END rd_out[363]
  PIN rd_out[364]
    DIRECTION OUTPUT ;
    USE SIGNAL ;
    SHAPE ABUTMENT ;
    PORT
      LAYER metal3 ;
      RECT 0.000 152.285 0.070 152.355 ;
    END
  END rd_out[364]
  PIN rd_out[365]
    DIRECTION OUTPUT ;
    USE SIGNAL ;
    SHAPE ABUTMENT ;
    PORT
      LAYER metal3 ;
      RECT 0.000 152.425 0.070 152.495 ;
    END
  END rd_out[365]
  PIN rd_out[366]
    DIRECTION OUTPUT ;
    USE SIGNAL ;
    SHAPE ABUTMENT ;
    PORT
      LAYER metal3 ;
      RECT 0.000 152.565 0.070 152.635 ;
    END
  END rd_out[366]
  PIN rd_out[367]
    DIRECTION OUTPUT ;
    USE SIGNAL ;
    SHAPE ABUTMENT ;
    PORT
      LAYER metal3 ;
      RECT 0.000 152.705 0.070 152.775 ;
    END
  END rd_out[367]
  PIN rd_out[368]
    DIRECTION OUTPUT ;
    USE SIGNAL ;
    SHAPE ABUTMENT ;
    PORT
      LAYER metal3 ;
      RECT 0.000 152.845 0.070 152.915 ;
    END
  END rd_out[368]
  PIN rd_out[369]
    DIRECTION OUTPUT ;
    USE SIGNAL ;
    SHAPE ABUTMENT ;
    PORT
      LAYER metal3 ;
      RECT 0.000 152.985 0.070 153.055 ;
    END
  END rd_out[369]
  PIN rd_out[370]
    DIRECTION OUTPUT ;
    USE SIGNAL ;
    SHAPE ABUTMENT ;
    PORT
      LAYER metal3 ;
      RECT 0.000 153.125 0.070 153.195 ;
    END
  END rd_out[370]
  PIN rd_out[371]
    DIRECTION OUTPUT ;
    USE SIGNAL ;
    SHAPE ABUTMENT ;
    PORT
      LAYER metal3 ;
      RECT 0.000 153.265 0.070 153.335 ;
    END
  END rd_out[371]
  PIN rd_out[372]
    DIRECTION OUTPUT ;
    USE SIGNAL ;
    SHAPE ABUTMENT ;
    PORT
      LAYER metal3 ;
      RECT 0.000 153.405 0.070 153.475 ;
    END
  END rd_out[372]
  PIN rd_out[373]
    DIRECTION OUTPUT ;
    USE SIGNAL ;
    SHAPE ABUTMENT ;
    PORT
      LAYER metal3 ;
      RECT 0.000 153.545 0.070 153.615 ;
    END
  END rd_out[373]
  PIN rd_out[374]
    DIRECTION OUTPUT ;
    USE SIGNAL ;
    SHAPE ABUTMENT ;
    PORT
      LAYER metal3 ;
      RECT 0.000 153.685 0.070 153.755 ;
    END
  END rd_out[374]
  PIN rd_out[375]
    DIRECTION OUTPUT ;
    USE SIGNAL ;
    SHAPE ABUTMENT ;
    PORT
      LAYER metal3 ;
      RECT 0.000 153.825 0.070 153.895 ;
    END
  END rd_out[375]
  PIN rd_out[376]
    DIRECTION OUTPUT ;
    USE SIGNAL ;
    SHAPE ABUTMENT ;
    PORT
      LAYER metal3 ;
      RECT 0.000 153.965 0.070 154.035 ;
    END
  END rd_out[376]
  PIN rd_out[377]
    DIRECTION OUTPUT ;
    USE SIGNAL ;
    SHAPE ABUTMENT ;
    PORT
      LAYER metal3 ;
      RECT 0.000 154.105 0.070 154.175 ;
    END
  END rd_out[377]
  PIN rd_out[378]
    DIRECTION OUTPUT ;
    USE SIGNAL ;
    SHAPE ABUTMENT ;
    PORT
      LAYER metal3 ;
      RECT 0.000 154.245 0.070 154.315 ;
    END
  END rd_out[378]
  PIN rd_out[379]
    DIRECTION OUTPUT ;
    USE SIGNAL ;
    SHAPE ABUTMENT ;
    PORT
      LAYER metal3 ;
      RECT 0.000 154.385 0.070 154.455 ;
    END
  END rd_out[379]
  PIN rd_out[380]
    DIRECTION OUTPUT ;
    USE SIGNAL ;
    SHAPE ABUTMENT ;
    PORT
      LAYER metal3 ;
      RECT 0.000 154.525 0.070 154.595 ;
    END
  END rd_out[380]
  PIN rd_out[381]
    DIRECTION OUTPUT ;
    USE SIGNAL ;
    SHAPE ABUTMENT ;
    PORT
      LAYER metal3 ;
      RECT 0.000 154.665 0.070 154.735 ;
    END
  END rd_out[381]
  PIN rd_out[382]
    DIRECTION OUTPUT ;
    USE SIGNAL ;
    SHAPE ABUTMENT ;
    PORT
      LAYER metal3 ;
      RECT 0.000 154.805 0.070 154.875 ;
    END
  END rd_out[382]
  PIN rd_out[383]
    DIRECTION OUTPUT ;
    USE SIGNAL ;
    SHAPE ABUTMENT ;
    PORT
      LAYER metal3 ;
      RECT 0.000 154.945 0.070 155.015 ;
    END
  END rd_out[383]
  PIN rd_out[384]
    DIRECTION OUTPUT ;
    USE SIGNAL ;
    SHAPE ABUTMENT ;
    PORT
      LAYER metal3 ;
      RECT 0.000 155.085 0.070 155.155 ;
    END
  END rd_out[384]
  PIN rd_out[385]
    DIRECTION OUTPUT ;
    USE SIGNAL ;
    SHAPE ABUTMENT ;
    PORT
      LAYER metal3 ;
      RECT 0.000 155.225 0.070 155.295 ;
    END
  END rd_out[385]
  PIN rd_out[386]
    DIRECTION OUTPUT ;
    USE SIGNAL ;
    SHAPE ABUTMENT ;
    PORT
      LAYER metal3 ;
      RECT 0.000 155.365 0.070 155.435 ;
    END
  END rd_out[386]
  PIN rd_out[387]
    DIRECTION OUTPUT ;
    USE SIGNAL ;
    SHAPE ABUTMENT ;
    PORT
      LAYER metal3 ;
      RECT 0.000 155.505 0.070 155.575 ;
    END
  END rd_out[387]
  PIN rd_out[388]
    DIRECTION OUTPUT ;
    USE SIGNAL ;
    SHAPE ABUTMENT ;
    PORT
      LAYER metal3 ;
      RECT 0.000 155.645 0.070 155.715 ;
    END
  END rd_out[388]
  PIN rd_out[389]
    DIRECTION OUTPUT ;
    USE SIGNAL ;
    SHAPE ABUTMENT ;
    PORT
      LAYER metal3 ;
      RECT 0.000 155.785 0.070 155.855 ;
    END
  END rd_out[389]
  PIN rd_out[390]
    DIRECTION OUTPUT ;
    USE SIGNAL ;
    SHAPE ABUTMENT ;
    PORT
      LAYER metal3 ;
      RECT 0.000 155.925 0.070 155.995 ;
    END
  END rd_out[390]
  PIN rd_out[391]
    DIRECTION OUTPUT ;
    USE SIGNAL ;
    SHAPE ABUTMENT ;
    PORT
      LAYER metal3 ;
      RECT 0.000 156.065 0.070 156.135 ;
    END
  END rd_out[391]
  PIN rd_out[392]
    DIRECTION OUTPUT ;
    USE SIGNAL ;
    SHAPE ABUTMENT ;
    PORT
      LAYER metal3 ;
      RECT 0.000 156.205 0.070 156.275 ;
    END
  END rd_out[392]
  PIN rd_out[393]
    DIRECTION OUTPUT ;
    USE SIGNAL ;
    SHAPE ABUTMENT ;
    PORT
      LAYER metal3 ;
      RECT 0.000 156.345 0.070 156.415 ;
    END
  END rd_out[393]
  PIN rd_out[394]
    DIRECTION OUTPUT ;
    USE SIGNAL ;
    SHAPE ABUTMENT ;
    PORT
      LAYER metal3 ;
      RECT 0.000 156.485 0.070 156.555 ;
    END
  END rd_out[394]
  PIN rd_out[395]
    DIRECTION OUTPUT ;
    USE SIGNAL ;
    SHAPE ABUTMENT ;
    PORT
      LAYER metal3 ;
      RECT 0.000 156.625 0.070 156.695 ;
    END
  END rd_out[395]
  PIN rd_out[396]
    DIRECTION OUTPUT ;
    USE SIGNAL ;
    SHAPE ABUTMENT ;
    PORT
      LAYER metal3 ;
      RECT 0.000 156.765 0.070 156.835 ;
    END
  END rd_out[396]
  PIN rd_out[397]
    DIRECTION OUTPUT ;
    USE SIGNAL ;
    SHAPE ABUTMENT ;
    PORT
      LAYER metal3 ;
      RECT 0.000 156.905 0.070 156.975 ;
    END
  END rd_out[397]
  PIN rd_out[398]
    DIRECTION OUTPUT ;
    USE SIGNAL ;
    SHAPE ABUTMENT ;
    PORT
      LAYER metal3 ;
      RECT 0.000 157.045 0.070 157.115 ;
    END
  END rd_out[398]
  PIN rd_out[399]
    DIRECTION OUTPUT ;
    USE SIGNAL ;
    SHAPE ABUTMENT ;
    PORT
      LAYER metal3 ;
      RECT 0.000 157.185 0.070 157.255 ;
    END
  END rd_out[399]
  PIN rd_out[400]
    DIRECTION OUTPUT ;
    USE SIGNAL ;
    SHAPE ABUTMENT ;
    PORT
      LAYER metal3 ;
      RECT 0.000 157.325 0.070 157.395 ;
    END
  END rd_out[400]
  PIN rd_out[401]
    DIRECTION OUTPUT ;
    USE SIGNAL ;
    SHAPE ABUTMENT ;
    PORT
      LAYER metal3 ;
      RECT 0.000 157.465 0.070 157.535 ;
    END
  END rd_out[401]
  PIN rd_out[402]
    DIRECTION OUTPUT ;
    USE SIGNAL ;
    SHAPE ABUTMENT ;
    PORT
      LAYER metal3 ;
      RECT 0.000 157.605 0.070 157.675 ;
    END
  END rd_out[402]
  PIN rd_out[403]
    DIRECTION OUTPUT ;
    USE SIGNAL ;
    SHAPE ABUTMENT ;
    PORT
      LAYER metal3 ;
      RECT 0.000 157.745 0.070 157.815 ;
    END
  END rd_out[403]
  PIN rd_out[404]
    DIRECTION OUTPUT ;
    USE SIGNAL ;
    SHAPE ABUTMENT ;
    PORT
      LAYER metal3 ;
      RECT 0.000 157.885 0.070 157.955 ;
    END
  END rd_out[404]
  PIN rd_out[405]
    DIRECTION OUTPUT ;
    USE SIGNAL ;
    SHAPE ABUTMENT ;
    PORT
      LAYER metal3 ;
      RECT 0.000 158.025 0.070 158.095 ;
    END
  END rd_out[405]
  PIN rd_out[406]
    DIRECTION OUTPUT ;
    USE SIGNAL ;
    SHAPE ABUTMENT ;
    PORT
      LAYER metal3 ;
      RECT 0.000 158.165 0.070 158.235 ;
    END
  END rd_out[406]
  PIN rd_out[407]
    DIRECTION OUTPUT ;
    USE SIGNAL ;
    SHAPE ABUTMENT ;
    PORT
      LAYER metal3 ;
      RECT 0.000 158.305 0.070 158.375 ;
    END
  END rd_out[407]
  PIN rd_out[408]
    DIRECTION OUTPUT ;
    USE SIGNAL ;
    SHAPE ABUTMENT ;
    PORT
      LAYER metal3 ;
      RECT 0.000 158.445 0.070 158.515 ;
    END
  END rd_out[408]
  PIN rd_out[409]
    DIRECTION OUTPUT ;
    USE SIGNAL ;
    SHAPE ABUTMENT ;
    PORT
      LAYER metal3 ;
      RECT 0.000 158.585 0.070 158.655 ;
    END
  END rd_out[409]
  PIN rd_out[410]
    DIRECTION OUTPUT ;
    USE SIGNAL ;
    SHAPE ABUTMENT ;
    PORT
      LAYER metal3 ;
      RECT 0.000 158.725 0.070 158.795 ;
    END
  END rd_out[410]
  PIN rd_out[411]
    DIRECTION OUTPUT ;
    USE SIGNAL ;
    SHAPE ABUTMENT ;
    PORT
      LAYER metal3 ;
      RECT 0.000 158.865 0.070 158.935 ;
    END
  END rd_out[411]
  PIN rd_out[412]
    DIRECTION OUTPUT ;
    USE SIGNAL ;
    SHAPE ABUTMENT ;
    PORT
      LAYER metal3 ;
      RECT 0.000 159.005 0.070 159.075 ;
    END
  END rd_out[412]
  PIN rd_out[413]
    DIRECTION OUTPUT ;
    USE SIGNAL ;
    SHAPE ABUTMENT ;
    PORT
      LAYER metal3 ;
      RECT 0.000 159.145 0.070 159.215 ;
    END
  END rd_out[413]
  PIN rd_out[414]
    DIRECTION OUTPUT ;
    USE SIGNAL ;
    SHAPE ABUTMENT ;
    PORT
      LAYER metal3 ;
      RECT 0.000 159.285 0.070 159.355 ;
    END
  END rd_out[414]
  PIN rd_out[415]
    DIRECTION OUTPUT ;
    USE SIGNAL ;
    SHAPE ABUTMENT ;
    PORT
      LAYER metal3 ;
      RECT 0.000 159.425 0.070 159.495 ;
    END
  END rd_out[415]
  PIN rd_out[416]
    DIRECTION OUTPUT ;
    USE SIGNAL ;
    SHAPE ABUTMENT ;
    PORT
      LAYER metal3 ;
      RECT 0.000 159.565 0.070 159.635 ;
    END
  END rd_out[416]
  PIN rd_out[417]
    DIRECTION OUTPUT ;
    USE SIGNAL ;
    SHAPE ABUTMENT ;
    PORT
      LAYER metal3 ;
      RECT 0.000 159.705 0.070 159.775 ;
    END
  END rd_out[417]
  PIN rd_out[418]
    DIRECTION OUTPUT ;
    USE SIGNAL ;
    SHAPE ABUTMENT ;
    PORT
      LAYER metal3 ;
      RECT 0.000 159.845 0.070 159.915 ;
    END
  END rd_out[418]
  PIN rd_out[419]
    DIRECTION OUTPUT ;
    USE SIGNAL ;
    SHAPE ABUTMENT ;
    PORT
      LAYER metal3 ;
      RECT 0.000 159.985 0.070 160.055 ;
    END
  END rd_out[419]
  PIN rd_out[420]
    DIRECTION OUTPUT ;
    USE SIGNAL ;
    SHAPE ABUTMENT ;
    PORT
      LAYER metal3 ;
      RECT 0.000 160.125 0.070 160.195 ;
    END
  END rd_out[420]
  PIN rd_out[421]
    DIRECTION OUTPUT ;
    USE SIGNAL ;
    SHAPE ABUTMENT ;
    PORT
      LAYER metal3 ;
      RECT 0.000 160.265 0.070 160.335 ;
    END
  END rd_out[421]
  PIN rd_out[422]
    DIRECTION OUTPUT ;
    USE SIGNAL ;
    SHAPE ABUTMENT ;
    PORT
      LAYER metal3 ;
      RECT 0.000 160.405 0.070 160.475 ;
    END
  END rd_out[422]
  PIN rd_out[423]
    DIRECTION OUTPUT ;
    USE SIGNAL ;
    SHAPE ABUTMENT ;
    PORT
      LAYER metal3 ;
      RECT 0.000 160.545 0.070 160.615 ;
    END
  END rd_out[423]
  PIN rd_out[424]
    DIRECTION OUTPUT ;
    USE SIGNAL ;
    SHAPE ABUTMENT ;
    PORT
      LAYER metal3 ;
      RECT 0.000 160.685 0.070 160.755 ;
    END
  END rd_out[424]
  PIN rd_out[425]
    DIRECTION OUTPUT ;
    USE SIGNAL ;
    SHAPE ABUTMENT ;
    PORT
      LAYER metal3 ;
      RECT 0.000 160.825 0.070 160.895 ;
    END
  END rd_out[425]
  PIN rd_out[426]
    DIRECTION OUTPUT ;
    USE SIGNAL ;
    SHAPE ABUTMENT ;
    PORT
      LAYER metal3 ;
      RECT 0.000 160.965 0.070 161.035 ;
    END
  END rd_out[426]
  PIN rd_out[427]
    DIRECTION OUTPUT ;
    USE SIGNAL ;
    SHAPE ABUTMENT ;
    PORT
      LAYER metal3 ;
      RECT 0.000 161.105 0.070 161.175 ;
    END
  END rd_out[427]
  PIN rd_out[428]
    DIRECTION OUTPUT ;
    USE SIGNAL ;
    SHAPE ABUTMENT ;
    PORT
      LAYER metal3 ;
      RECT 0.000 161.245 0.070 161.315 ;
    END
  END rd_out[428]
  PIN rd_out[429]
    DIRECTION OUTPUT ;
    USE SIGNAL ;
    SHAPE ABUTMENT ;
    PORT
      LAYER metal3 ;
      RECT 0.000 161.385 0.070 161.455 ;
    END
  END rd_out[429]
  PIN rd_out[430]
    DIRECTION OUTPUT ;
    USE SIGNAL ;
    SHAPE ABUTMENT ;
    PORT
      LAYER metal3 ;
      RECT 0.000 161.525 0.070 161.595 ;
    END
  END rd_out[430]
  PIN rd_out[431]
    DIRECTION OUTPUT ;
    USE SIGNAL ;
    SHAPE ABUTMENT ;
    PORT
      LAYER metal3 ;
      RECT 0.000 161.665 0.070 161.735 ;
    END
  END rd_out[431]
  PIN rd_out[432]
    DIRECTION OUTPUT ;
    USE SIGNAL ;
    SHAPE ABUTMENT ;
    PORT
      LAYER metal3 ;
      RECT 0.000 161.805 0.070 161.875 ;
    END
  END rd_out[432]
  PIN rd_out[433]
    DIRECTION OUTPUT ;
    USE SIGNAL ;
    SHAPE ABUTMENT ;
    PORT
      LAYER metal3 ;
      RECT 0.000 161.945 0.070 162.015 ;
    END
  END rd_out[433]
  PIN rd_out[434]
    DIRECTION OUTPUT ;
    USE SIGNAL ;
    SHAPE ABUTMENT ;
    PORT
      LAYER metal3 ;
      RECT 0.000 162.085 0.070 162.155 ;
    END
  END rd_out[434]
  PIN rd_out[435]
    DIRECTION OUTPUT ;
    USE SIGNAL ;
    SHAPE ABUTMENT ;
    PORT
      LAYER metal3 ;
      RECT 0.000 162.225 0.070 162.295 ;
    END
  END rd_out[435]
  PIN rd_out[436]
    DIRECTION OUTPUT ;
    USE SIGNAL ;
    SHAPE ABUTMENT ;
    PORT
      LAYER metal3 ;
      RECT 0.000 162.365 0.070 162.435 ;
    END
  END rd_out[436]
  PIN rd_out[437]
    DIRECTION OUTPUT ;
    USE SIGNAL ;
    SHAPE ABUTMENT ;
    PORT
      LAYER metal3 ;
      RECT 0.000 162.505 0.070 162.575 ;
    END
  END rd_out[437]
  PIN rd_out[438]
    DIRECTION OUTPUT ;
    USE SIGNAL ;
    SHAPE ABUTMENT ;
    PORT
      LAYER metal3 ;
      RECT 0.000 162.645 0.070 162.715 ;
    END
  END rd_out[438]
  PIN rd_out[439]
    DIRECTION OUTPUT ;
    USE SIGNAL ;
    SHAPE ABUTMENT ;
    PORT
      LAYER metal3 ;
      RECT 0.000 162.785 0.070 162.855 ;
    END
  END rd_out[439]
  PIN rd_out[440]
    DIRECTION OUTPUT ;
    USE SIGNAL ;
    SHAPE ABUTMENT ;
    PORT
      LAYER metal3 ;
      RECT 0.000 162.925 0.070 162.995 ;
    END
  END rd_out[440]
  PIN rd_out[441]
    DIRECTION OUTPUT ;
    USE SIGNAL ;
    SHAPE ABUTMENT ;
    PORT
      LAYER metal3 ;
      RECT 0.000 163.065 0.070 163.135 ;
    END
  END rd_out[441]
  PIN rd_out[442]
    DIRECTION OUTPUT ;
    USE SIGNAL ;
    SHAPE ABUTMENT ;
    PORT
      LAYER metal3 ;
      RECT 0.000 163.205 0.070 163.275 ;
    END
  END rd_out[442]
  PIN rd_out[443]
    DIRECTION OUTPUT ;
    USE SIGNAL ;
    SHAPE ABUTMENT ;
    PORT
      LAYER metal3 ;
      RECT 0.000 163.345 0.070 163.415 ;
    END
  END rd_out[443]
  PIN rd_out[444]
    DIRECTION OUTPUT ;
    USE SIGNAL ;
    SHAPE ABUTMENT ;
    PORT
      LAYER metal3 ;
      RECT 0.000 163.485 0.070 163.555 ;
    END
  END rd_out[444]
  PIN rd_out[445]
    DIRECTION OUTPUT ;
    USE SIGNAL ;
    SHAPE ABUTMENT ;
    PORT
      LAYER metal3 ;
      RECT 0.000 163.625 0.070 163.695 ;
    END
  END rd_out[445]
  PIN rd_out[446]
    DIRECTION OUTPUT ;
    USE SIGNAL ;
    SHAPE ABUTMENT ;
    PORT
      LAYER metal3 ;
      RECT 0.000 163.765 0.070 163.835 ;
    END
  END rd_out[446]
  PIN rd_out[447]
    DIRECTION OUTPUT ;
    USE SIGNAL ;
    SHAPE ABUTMENT ;
    PORT
      LAYER metal3 ;
      RECT 0.000 163.905 0.070 163.975 ;
    END
  END rd_out[447]
  PIN rd_out[448]
    DIRECTION OUTPUT ;
    USE SIGNAL ;
    SHAPE ABUTMENT ;
    PORT
      LAYER metal3 ;
      RECT 0.000 164.045 0.070 164.115 ;
    END
  END rd_out[448]
  PIN rd_out[449]
    DIRECTION OUTPUT ;
    USE SIGNAL ;
    SHAPE ABUTMENT ;
    PORT
      LAYER metal3 ;
      RECT 0.000 164.185 0.070 164.255 ;
    END
  END rd_out[449]
  PIN rd_out[450]
    DIRECTION OUTPUT ;
    USE SIGNAL ;
    SHAPE ABUTMENT ;
    PORT
      LAYER metal3 ;
      RECT 0.000 164.325 0.070 164.395 ;
    END
  END rd_out[450]
  PIN rd_out[451]
    DIRECTION OUTPUT ;
    USE SIGNAL ;
    SHAPE ABUTMENT ;
    PORT
      LAYER metal3 ;
      RECT 0.000 164.465 0.070 164.535 ;
    END
  END rd_out[451]
  PIN rd_out[452]
    DIRECTION OUTPUT ;
    USE SIGNAL ;
    SHAPE ABUTMENT ;
    PORT
      LAYER metal3 ;
      RECT 0.000 164.605 0.070 164.675 ;
    END
  END rd_out[452]
  PIN rd_out[453]
    DIRECTION OUTPUT ;
    USE SIGNAL ;
    SHAPE ABUTMENT ;
    PORT
      LAYER metal3 ;
      RECT 0.000 164.745 0.070 164.815 ;
    END
  END rd_out[453]
  PIN rd_out[454]
    DIRECTION OUTPUT ;
    USE SIGNAL ;
    SHAPE ABUTMENT ;
    PORT
      LAYER metal3 ;
      RECT 0.000 164.885 0.070 164.955 ;
    END
  END rd_out[454]
  PIN rd_out[455]
    DIRECTION OUTPUT ;
    USE SIGNAL ;
    SHAPE ABUTMENT ;
    PORT
      LAYER metal3 ;
      RECT 0.000 165.025 0.070 165.095 ;
    END
  END rd_out[455]
  PIN rd_out[456]
    DIRECTION OUTPUT ;
    USE SIGNAL ;
    SHAPE ABUTMENT ;
    PORT
      LAYER metal3 ;
      RECT 0.000 165.165 0.070 165.235 ;
    END
  END rd_out[456]
  PIN rd_out[457]
    DIRECTION OUTPUT ;
    USE SIGNAL ;
    SHAPE ABUTMENT ;
    PORT
      LAYER metal3 ;
      RECT 0.000 165.305 0.070 165.375 ;
    END
  END rd_out[457]
  PIN rd_out[458]
    DIRECTION OUTPUT ;
    USE SIGNAL ;
    SHAPE ABUTMENT ;
    PORT
      LAYER metal3 ;
      RECT 0.000 165.445 0.070 165.515 ;
    END
  END rd_out[458]
  PIN rd_out[459]
    DIRECTION OUTPUT ;
    USE SIGNAL ;
    SHAPE ABUTMENT ;
    PORT
      LAYER metal3 ;
      RECT 0.000 165.585 0.070 165.655 ;
    END
  END rd_out[459]
  PIN rd_out[460]
    DIRECTION OUTPUT ;
    USE SIGNAL ;
    SHAPE ABUTMENT ;
    PORT
      LAYER metal3 ;
      RECT 0.000 165.725 0.070 165.795 ;
    END
  END rd_out[460]
  PIN rd_out[461]
    DIRECTION OUTPUT ;
    USE SIGNAL ;
    SHAPE ABUTMENT ;
    PORT
      LAYER metal3 ;
      RECT 0.000 165.865 0.070 165.935 ;
    END
  END rd_out[461]
  PIN rd_out[462]
    DIRECTION OUTPUT ;
    USE SIGNAL ;
    SHAPE ABUTMENT ;
    PORT
      LAYER metal3 ;
      RECT 0.000 166.005 0.070 166.075 ;
    END
  END rd_out[462]
  PIN rd_out[463]
    DIRECTION OUTPUT ;
    USE SIGNAL ;
    SHAPE ABUTMENT ;
    PORT
      LAYER metal3 ;
      RECT 0.000 166.145 0.070 166.215 ;
    END
  END rd_out[463]
  PIN rd_out[464]
    DIRECTION OUTPUT ;
    USE SIGNAL ;
    SHAPE ABUTMENT ;
    PORT
      LAYER metal3 ;
      RECT 0.000 166.285 0.070 166.355 ;
    END
  END rd_out[464]
  PIN rd_out[465]
    DIRECTION OUTPUT ;
    USE SIGNAL ;
    SHAPE ABUTMENT ;
    PORT
      LAYER metal3 ;
      RECT 0.000 166.425 0.070 166.495 ;
    END
  END rd_out[465]
  PIN rd_out[466]
    DIRECTION OUTPUT ;
    USE SIGNAL ;
    SHAPE ABUTMENT ;
    PORT
      LAYER metal3 ;
      RECT 0.000 166.565 0.070 166.635 ;
    END
  END rd_out[466]
  PIN rd_out[467]
    DIRECTION OUTPUT ;
    USE SIGNAL ;
    SHAPE ABUTMENT ;
    PORT
      LAYER metal3 ;
      RECT 0.000 166.705 0.070 166.775 ;
    END
  END rd_out[467]
  PIN rd_out[468]
    DIRECTION OUTPUT ;
    USE SIGNAL ;
    SHAPE ABUTMENT ;
    PORT
      LAYER metal3 ;
      RECT 0.000 166.845 0.070 166.915 ;
    END
  END rd_out[468]
  PIN rd_out[469]
    DIRECTION OUTPUT ;
    USE SIGNAL ;
    SHAPE ABUTMENT ;
    PORT
      LAYER metal3 ;
      RECT 0.000 166.985 0.070 167.055 ;
    END
  END rd_out[469]
  PIN rd_out[470]
    DIRECTION OUTPUT ;
    USE SIGNAL ;
    SHAPE ABUTMENT ;
    PORT
      LAYER metal3 ;
      RECT 0.000 167.125 0.070 167.195 ;
    END
  END rd_out[470]
  PIN rd_out[471]
    DIRECTION OUTPUT ;
    USE SIGNAL ;
    SHAPE ABUTMENT ;
    PORT
      LAYER metal3 ;
      RECT 0.000 167.265 0.070 167.335 ;
    END
  END rd_out[471]
  PIN rd_out[472]
    DIRECTION OUTPUT ;
    USE SIGNAL ;
    SHAPE ABUTMENT ;
    PORT
      LAYER metal3 ;
      RECT 0.000 167.405 0.070 167.475 ;
    END
  END rd_out[472]
  PIN rd_out[473]
    DIRECTION OUTPUT ;
    USE SIGNAL ;
    SHAPE ABUTMENT ;
    PORT
      LAYER metal3 ;
      RECT 0.000 167.545 0.070 167.615 ;
    END
  END rd_out[473]
  PIN rd_out[474]
    DIRECTION OUTPUT ;
    USE SIGNAL ;
    SHAPE ABUTMENT ;
    PORT
      LAYER metal3 ;
      RECT 0.000 167.685 0.070 167.755 ;
    END
  END rd_out[474]
  PIN rd_out[475]
    DIRECTION OUTPUT ;
    USE SIGNAL ;
    SHAPE ABUTMENT ;
    PORT
      LAYER metal3 ;
      RECT 0.000 167.825 0.070 167.895 ;
    END
  END rd_out[475]
  PIN rd_out[476]
    DIRECTION OUTPUT ;
    USE SIGNAL ;
    SHAPE ABUTMENT ;
    PORT
      LAYER metal3 ;
      RECT 0.000 167.965 0.070 168.035 ;
    END
  END rd_out[476]
  PIN rd_out[477]
    DIRECTION OUTPUT ;
    USE SIGNAL ;
    SHAPE ABUTMENT ;
    PORT
      LAYER metal3 ;
      RECT 0.000 168.105 0.070 168.175 ;
    END
  END rd_out[477]
  PIN rd_out[478]
    DIRECTION OUTPUT ;
    USE SIGNAL ;
    SHAPE ABUTMENT ;
    PORT
      LAYER metal3 ;
      RECT 0.000 168.245 0.070 168.315 ;
    END
  END rd_out[478]
  PIN rd_out[479]
    DIRECTION OUTPUT ;
    USE SIGNAL ;
    SHAPE ABUTMENT ;
    PORT
      LAYER metal3 ;
      RECT 0.000 168.385 0.070 168.455 ;
    END
  END rd_out[479]
  PIN rd_out[480]
    DIRECTION OUTPUT ;
    USE SIGNAL ;
    SHAPE ABUTMENT ;
    PORT
      LAYER metal3 ;
      RECT 0.000 168.525 0.070 168.595 ;
    END
  END rd_out[480]
  PIN rd_out[481]
    DIRECTION OUTPUT ;
    USE SIGNAL ;
    SHAPE ABUTMENT ;
    PORT
      LAYER metal3 ;
      RECT 0.000 168.665 0.070 168.735 ;
    END
  END rd_out[481]
  PIN rd_out[482]
    DIRECTION OUTPUT ;
    USE SIGNAL ;
    SHAPE ABUTMENT ;
    PORT
      LAYER metal3 ;
      RECT 0.000 168.805 0.070 168.875 ;
    END
  END rd_out[482]
  PIN rd_out[483]
    DIRECTION OUTPUT ;
    USE SIGNAL ;
    SHAPE ABUTMENT ;
    PORT
      LAYER metal3 ;
      RECT 0.000 168.945 0.070 169.015 ;
    END
  END rd_out[483]
  PIN rd_out[484]
    DIRECTION OUTPUT ;
    USE SIGNAL ;
    SHAPE ABUTMENT ;
    PORT
      LAYER metal3 ;
      RECT 0.000 169.085 0.070 169.155 ;
    END
  END rd_out[484]
  PIN rd_out[485]
    DIRECTION OUTPUT ;
    USE SIGNAL ;
    SHAPE ABUTMENT ;
    PORT
      LAYER metal3 ;
      RECT 0.000 169.225 0.070 169.295 ;
    END
  END rd_out[485]
  PIN rd_out[486]
    DIRECTION OUTPUT ;
    USE SIGNAL ;
    SHAPE ABUTMENT ;
    PORT
      LAYER metal3 ;
      RECT 0.000 169.365 0.070 169.435 ;
    END
  END rd_out[486]
  PIN rd_out[487]
    DIRECTION OUTPUT ;
    USE SIGNAL ;
    SHAPE ABUTMENT ;
    PORT
      LAYER metal3 ;
      RECT 0.000 169.505 0.070 169.575 ;
    END
  END rd_out[487]
  PIN rd_out[488]
    DIRECTION OUTPUT ;
    USE SIGNAL ;
    SHAPE ABUTMENT ;
    PORT
      LAYER metal3 ;
      RECT 0.000 169.645 0.070 169.715 ;
    END
  END rd_out[488]
  PIN rd_out[489]
    DIRECTION OUTPUT ;
    USE SIGNAL ;
    SHAPE ABUTMENT ;
    PORT
      LAYER metal3 ;
      RECT 0.000 169.785 0.070 169.855 ;
    END
  END rd_out[489]
  PIN rd_out[490]
    DIRECTION OUTPUT ;
    USE SIGNAL ;
    SHAPE ABUTMENT ;
    PORT
      LAYER metal3 ;
      RECT 0.000 169.925 0.070 169.995 ;
    END
  END rd_out[490]
  PIN rd_out[491]
    DIRECTION OUTPUT ;
    USE SIGNAL ;
    SHAPE ABUTMENT ;
    PORT
      LAYER metal3 ;
      RECT 0.000 170.065 0.070 170.135 ;
    END
  END rd_out[491]
  PIN rd_out[492]
    DIRECTION OUTPUT ;
    USE SIGNAL ;
    SHAPE ABUTMENT ;
    PORT
      LAYER metal3 ;
      RECT 0.000 170.205 0.070 170.275 ;
    END
  END rd_out[492]
  PIN rd_out[493]
    DIRECTION OUTPUT ;
    USE SIGNAL ;
    SHAPE ABUTMENT ;
    PORT
      LAYER metal3 ;
      RECT 0.000 170.345 0.070 170.415 ;
    END
  END rd_out[493]
  PIN rd_out[494]
    DIRECTION OUTPUT ;
    USE SIGNAL ;
    SHAPE ABUTMENT ;
    PORT
      LAYER metal3 ;
      RECT 0.000 170.485 0.070 170.555 ;
    END
  END rd_out[494]
  PIN rd_out[495]
    DIRECTION OUTPUT ;
    USE SIGNAL ;
    SHAPE ABUTMENT ;
    PORT
      LAYER metal3 ;
      RECT 0.000 170.625 0.070 170.695 ;
    END
  END rd_out[495]
  PIN rd_out[496]
    DIRECTION OUTPUT ;
    USE SIGNAL ;
    SHAPE ABUTMENT ;
    PORT
      LAYER metal3 ;
      RECT 0.000 170.765 0.070 170.835 ;
    END
  END rd_out[496]
  PIN rd_out[497]
    DIRECTION OUTPUT ;
    USE SIGNAL ;
    SHAPE ABUTMENT ;
    PORT
      LAYER metal3 ;
      RECT 0.000 170.905 0.070 170.975 ;
    END
  END rd_out[497]
  PIN rd_out[498]
    DIRECTION OUTPUT ;
    USE SIGNAL ;
    SHAPE ABUTMENT ;
    PORT
      LAYER metal3 ;
      RECT 0.000 171.045 0.070 171.115 ;
    END
  END rd_out[498]
  PIN rd_out[499]
    DIRECTION OUTPUT ;
    USE SIGNAL ;
    SHAPE ABUTMENT ;
    PORT
      LAYER metal3 ;
      RECT 0.000 171.185 0.070 171.255 ;
    END
  END rd_out[499]
  PIN rd_out[500]
    DIRECTION OUTPUT ;
    USE SIGNAL ;
    SHAPE ABUTMENT ;
    PORT
      LAYER metal3 ;
      RECT 0.000 171.325 0.070 171.395 ;
    END
  END rd_out[500]
  PIN rd_out[501]
    DIRECTION OUTPUT ;
    USE SIGNAL ;
    SHAPE ABUTMENT ;
    PORT
      LAYER metal3 ;
      RECT 0.000 171.465 0.070 171.535 ;
    END
  END rd_out[501]
  PIN rd_out[502]
    DIRECTION OUTPUT ;
    USE SIGNAL ;
    SHAPE ABUTMENT ;
    PORT
      LAYER metal3 ;
      RECT 0.000 171.605 0.070 171.675 ;
    END
  END rd_out[502]
  PIN rd_out[503]
    DIRECTION OUTPUT ;
    USE SIGNAL ;
    SHAPE ABUTMENT ;
    PORT
      LAYER metal3 ;
      RECT 0.000 171.745 0.070 171.815 ;
    END
  END rd_out[503]
  PIN rd_out[504]
    DIRECTION OUTPUT ;
    USE SIGNAL ;
    SHAPE ABUTMENT ;
    PORT
      LAYER metal3 ;
      RECT 0.000 171.885 0.070 171.955 ;
    END
  END rd_out[504]
  PIN rd_out[505]
    DIRECTION OUTPUT ;
    USE SIGNAL ;
    SHAPE ABUTMENT ;
    PORT
      LAYER metal3 ;
      RECT 0.000 172.025 0.070 172.095 ;
    END
  END rd_out[505]
  PIN rd_out[506]
    DIRECTION OUTPUT ;
    USE SIGNAL ;
    SHAPE ABUTMENT ;
    PORT
      LAYER metal3 ;
      RECT 0.000 172.165 0.070 172.235 ;
    END
  END rd_out[506]
  PIN rd_out[507]
    DIRECTION OUTPUT ;
    USE SIGNAL ;
    SHAPE ABUTMENT ;
    PORT
      LAYER metal3 ;
      RECT 0.000 172.305 0.070 172.375 ;
    END
  END rd_out[507]
  PIN rd_out[508]
    DIRECTION OUTPUT ;
    USE SIGNAL ;
    SHAPE ABUTMENT ;
    PORT
      LAYER metal3 ;
      RECT 0.000 172.445 0.070 172.515 ;
    END
  END rd_out[508]
  PIN rd_out[509]
    DIRECTION OUTPUT ;
    USE SIGNAL ;
    SHAPE ABUTMENT ;
    PORT
      LAYER metal3 ;
      RECT 0.000 172.585 0.070 172.655 ;
    END
  END rd_out[509]
  PIN rd_out[510]
    DIRECTION OUTPUT ;
    USE SIGNAL ;
    SHAPE ABUTMENT ;
    PORT
      LAYER metal3 ;
      RECT 0.000 172.725 0.070 172.795 ;
    END
  END rd_out[510]
  PIN rd_out[511]
    DIRECTION OUTPUT ;
    USE SIGNAL ;
    SHAPE ABUTMENT ;
    PORT
      LAYER metal3 ;
      RECT 0.000 172.865 0.070 172.935 ;
    END
  END rd_out[511]
  PIN wd_in[0]
    DIRECTION INPUT ;
    USE SIGNAL ;
    SHAPE ABUTMENT ;
    PORT
      LAYER metal3 ;
      RECT 0.000 201.285 0.070 201.355 ;
    END
  END wd_in[0]
  PIN wd_in[1]
    DIRECTION INPUT ;
    USE SIGNAL ;
    SHAPE ABUTMENT ;
    PORT
      LAYER metal3 ;
      RECT 0.000 201.425 0.070 201.495 ;
    END
  END wd_in[1]
  PIN wd_in[2]
    DIRECTION INPUT ;
    USE SIGNAL ;
    SHAPE ABUTMENT ;
    PORT
      LAYER metal3 ;
      RECT 0.000 201.565 0.070 201.635 ;
    END
  END wd_in[2]
  PIN wd_in[3]
    DIRECTION INPUT ;
    USE SIGNAL ;
    SHAPE ABUTMENT ;
    PORT
      LAYER metal3 ;
      RECT 0.000 201.705 0.070 201.775 ;
    END
  END wd_in[3]
  PIN wd_in[4]
    DIRECTION INPUT ;
    USE SIGNAL ;
    SHAPE ABUTMENT ;
    PORT
      LAYER metal3 ;
      RECT 0.000 201.845 0.070 201.915 ;
    END
  END wd_in[4]
  PIN wd_in[5]
    DIRECTION INPUT ;
    USE SIGNAL ;
    SHAPE ABUTMENT ;
    PORT
      LAYER metal3 ;
      RECT 0.000 201.985 0.070 202.055 ;
    END
  END wd_in[5]
  PIN wd_in[6]
    DIRECTION INPUT ;
    USE SIGNAL ;
    SHAPE ABUTMENT ;
    PORT
      LAYER metal3 ;
      RECT 0.000 202.125 0.070 202.195 ;
    END
  END wd_in[6]
  PIN wd_in[7]
    DIRECTION INPUT ;
    USE SIGNAL ;
    SHAPE ABUTMENT ;
    PORT
      LAYER metal3 ;
      RECT 0.000 202.265 0.070 202.335 ;
    END
  END wd_in[7]
  PIN wd_in[8]
    DIRECTION INPUT ;
    USE SIGNAL ;
    SHAPE ABUTMENT ;
    PORT
      LAYER metal3 ;
      RECT 0.000 202.405 0.070 202.475 ;
    END
  END wd_in[8]
  PIN wd_in[9]
    DIRECTION INPUT ;
    USE SIGNAL ;
    SHAPE ABUTMENT ;
    PORT
      LAYER metal3 ;
      RECT 0.000 202.545 0.070 202.615 ;
    END
  END wd_in[9]
  PIN wd_in[10]
    DIRECTION INPUT ;
    USE SIGNAL ;
    SHAPE ABUTMENT ;
    PORT
      LAYER metal3 ;
      RECT 0.000 202.685 0.070 202.755 ;
    END
  END wd_in[10]
  PIN wd_in[11]
    DIRECTION INPUT ;
    USE SIGNAL ;
    SHAPE ABUTMENT ;
    PORT
      LAYER metal3 ;
      RECT 0.000 202.825 0.070 202.895 ;
    END
  END wd_in[11]
  PIN wd_in[12]
    DIRECTION INPUT ;
    USE SIGNAL ;
    SHAPE ABUTMENT ;
    PORT
      LAYER metal3 ;
      RECT 0.000 202.965 0.070 203.035 ;
    END
  END wd_in[12]
  PIN wd_in[13]
    DIRECTION INPUT ;
    USE SIGNAL ;
    SHAPE ABUTMENT ;
    PORT
      LAYER metal3 ;
      RECT 0.000 203.105 0.070 203.175 ;
    END
  END wd_in[13]
  PIN wd_in[14]
    DIRECTION INPUT ;
    USE SIGNAL ;
    SHAPE ABUTMENT ;
    PORT
      LAYER metal3 ;
      RECT 0.000 203.245 0.070 203.315 ;
    END
  END wd_in[14]
  PIN wd_in[15]
    DIRECTION INPUT ;
    USE SIGNAL ;
    SHAPE ABUTMENT ;
    PORT
      LAYER metal3 ;
      RECT 0.000 203.385 0.070 203.455 ;
    END
  END wd_in[15]
  PIN wd_in[16]
    DIRECTION INPUT ;
    USE SIGNAL ;
    SHAPE ABUTMENT ;
    PORT
      LAYER metal3 ;
      RECT 0.000 203.525 0.070 203.595 ;
    END
  END wd_in[16]
  PIN wd_in[17]
    DIRECTION INPUT ;
    USE SIGNAL ;
    SHAPE ABUTMENT ;
    PORT
      LAYER metal3 ;
      RECT 0.000 203.665 0.070 203.735 ;
    END
  END wd_in[17]
  PIN wd_in[18]
    DIRECTION INPUT ;
    USE SIGNAL ;
    SHAPE ABUTMENT ;
    PORT
      LAYER metal3 ;
      RECT 0.000 203.805 0.070 203.875 ;
    END
  END wd_in[18]
  PIN wd_in[19]
    DIRECTION INPUT ;
    USE SIGNAL ;
    SHAPE ABUTMENT ;
    PORT
      LAYER metal3 ;
      RECT 0.000 203.945 0.070 204.015 ;
    END
  END wd_in[19]
  PIN wd_in[20]
    DIRECTION INPUT ;
    USE SIGNAL ;
    SHAPE ABUTMENT ;
    PORT
      LAYER metal3 ;
      RECT 0.000 204.085 0.070 204.155 ;
    END
  END wd_in[20]
  PIN wd_in[21]
    DIRECTION INPUT ;
    USE SIGNAL ;
    SHAPE ABUTMENT ;
    PORT
      LAYER metal3 ;
      RECT 0.000 204.225 0.070 204.295 ;
    END
  END wd_in[21]
  PIN wd_in[22]
    DIRECTION INPUT ;
    USE SIGNAL ;
    SHAPE ABUTMENT ;
    PORT
      LAYER metal3 ;
      RECT 0.000 204.365 0.070 204.435 ;
    END
  END wd_in[22]
  PIN wd_in[23]
    DIRECTION INPUT ;
    USE SIGNAL ;
    SHAPE ABUTMENT ;
    PORT
      LAYER metal3 ;
      RECT 0.000 204.505 0.070 204.575 ;
    END
  END wd_in[23]
  PIN wd_in[24]
    DIRECTION INPUT ;
    USE SIGNAL ;
    SHAPE ABUTMENT ;
    PORT
      LAYER metal3 ;
      RECT 0.000 204.645 0.070 204.715 ;
    END
  END wd_in[24]
  PIN wd_in[25]
    DIRECTION INPUT ;
    USE SIGNAL ;
    SHAPE ABUTMENT ;
    PORT
      LAYER metal3 ;
      RECT 0.000 204.785 0.070 204.855 ;
    END
  END wd_in[25]
  PIN wd_in[26]
    DIRECTION INPUT ;
    USE SIGNAL ;
    SHAPE ABUTMENT ;
    PORT
      LAYER metal3 ;
      RECT 0.000 204.925 0.070 204.995 ;
    END
  END wd_in[26]
  PIN wd_in[27]
    DIRECTION INPUT ;
    USE SIGNAL ;
    SHAPE ABUTMENT ;
    PORT
      LAYER metal3 ;
      RECT 0.000 205.065 0.070 205.135 ;
    END
  END wd_in[27]
  PIN wd_in[28]
    DIRECTION INPUT ;
    USE SIGNAL ;
    SHAPE ABUTMENT ;
    PORT
      LAYER metal3 ;
      RECT 0.000 205.205 0.070 205.275 ;
    END
  END wd_in[28]
  PIN wd_in[29]
    DIRECTION INPUT ;
    USE SIGNAL ;
    SHAPE ABUTMENT ;
    PORT
      LAYER metal3 ;
      RECT 0.000 205.345 0.070 205.415 ;
    END
  END wd_in[29]
  PIN wd_in[30]
    DIRECTION INPUT ;
    USE SIGNAL ;
    SHAPE ABUTMENT ;
    PORT
      LAYER metal3 ;
      RECT 0.000 205.485 0.070 205.555 ;
    END
  END wd_in[30]
  PIN wd_in[31]
    DIRECTION INPUT ;
    USE SIGNAL ;
    SHAPE ABUTMENT ;
    PORT
      LAYER metal3 ;
      RECT 0.000 205.625 0.070 205.695 ;
    END
  END wd_in[31]
  PIN wd_in[32]
    DIRECTION INPUT ;
    USE SIGNAL ;
    SHAPE ABUTMENT ;
    PORT
      LAYER metal3 ;
      RECT 0.000 205.765 0.070 205.835 ;
    END
  END wd_in[32]
  PIN wd_in[33]
    DIRECTION INPUT ;
    USE SIGNAL ;
    SHAPE ABUTMENT ;
    PORT
      LAYER metal3 ;
      RECT 0.000 205.905 0.070 205.975 ;
    END
  END wd_in[33]
  PIN wd_in[34]
    DIRECTION INPUT ;
    USE SIGNAL ;
    SHAPE ABUTMENT ;
    PORT
      LAYER metal3 ;
      RECT 0.000 206.045 0.070 206.115 ;
    END
  END wd_in[34]
  PIN wd_in[35]
    DIRECTION INPUT ;
    USE SIGNAL ;
    SHAPE ABUTMENT ;
    PORT
      LAYER metal3 ;
      RECT 0.000 206.185 0.070 206.255 ;
    END
  END wd_in[35]
  PIN wd_in[36]
    DIRECTION INPUT ;
    USE SIGNAL ;
    SHAPE ABUTMENT ;
    PORT
      LAYER metal3 ;
      RECT 0.000 206.325 0.070 206.395 ;
    END
  END wd_in[36]
  PIN wd_in[37]
    DIRECTION INPUT ;
    USE SIGNAL ;
    SHAPE ABUTMENT ;
    PORT
      LAYER metal3 ;
      RECT 0.000 206.465 0.070 206.535 ;
    END
  END wd_in[37]
  PIN wd_in[38]
    DIRECTION INPUT ;
    USE SIGNAL ;
    SHAPE ABUTMENT ;
    PORT
      LAYER metal3 ;
      RECT 0.000 206.605 0.070 206.675 ;
    END
  END wd_in[38]
  PIN wd_in[39]
    DIRECTION INPUT ;
    USE SIGNAL ;
    SHAPE ABUTMENT ;
    PORT
      LAYER metal3 ;
      RECT 0.000 206.745 0.070 206.815 ;
    END
  END wd_in[39]
  PIN wd_in[40]
    DIRECTION INPUT ;
    USE SIGNAL ;
    SHAPE ABUTMENT ;
    PORT
      LAYER metal3 ;
      RECT 0.000 206.885 0.070 206.955 ;
    END
  END wd_in[40]
  PIN wd_in[41]
    DIRECTION INPUT ;
    USE SIGNAL ;
    SHAPE ABUTMENT ;
    PORT
      LAYER metal3 ;
      RECT 0.000 207.025 0.070 207.095 ;
    END
  END wd_in[41]
  PIN wd_in[42]
    DIRECTION INPUT ;
    USE SIGNAL ;
    SHAPE ABUTMENT ;
    PORT
      LAYER metal3 ;
      RECT 0.000 207.165 0.070 207.235 ;
    END
  END wd_in[42]
  PIN wd_in[43]
    DIRECTION INPUT ;
    USE SIGNAL ;
    SHAPE ABUTMENT ;
    PORT
      LAYER metal3 ;
      RECT 0.000 207.305 0.070 207.375 ;
    END
  END wd_in[43]
  PIN wd_in[44]
    DIRECTION INPUT ;
    USE SIGNAL ;
    SHAPE ABUTMENT ;
    PORT
      LAYER metal3 ;
      RECT 0.000 207.445 0.070 207.515 ;
    END
  END wd_in[44]
  PIN wd_in[45]
    DIRECTION INPUT ;
    USE SIGNAL ;
    SHAPE ABUTMENT ;
    PORT
      LAYER metal3 ;
      RECT 0.000 207.585 0.070 207.655 ;
    END
  END wd_in[45]
  PIN wd_in[46]
    DIRECTION INPUT ;
    USE SIGNAL ;
    SHAPE ABUTMENT ;
    PORT
      LAYER metal3 ;
      RECT 0.000 207.725 0.070 207.795 ;
    END
  END wd_in[46]
  PIN wd_in[47]
    DIRECTION INPUT ;
    USE SIGNAL ;
    SHAPE ABUTMENT ;
    PORT
      LAYER metal3 ;
      RECT 0.000 207.865 0.070 207.935 ;
    END
  END wd_in[47]
  PIN wd_in[48]
    DIRECTION INPUT ;
    USE SIGNAL ;
    SHAPE ABUTMENT ;
    PORT
      LAYER metal3 ;
      RECT 0.000 208.005 0.070 208.075 ;
    END
  END wd_in[48]
  PIN wd_in[49]
    DIRECTION INPUT ;
    USE SIGNAL ;
    SHAPE ABUTMENT ;
    PORT
      LAYER metal3 ;
      RECT 0.000 208.145 0.070 208.215 ;
    END
  END wd_in[49]
  PIN wd_in[50]
    DIRECTION INPUT ;
    USE SIGNAL ;
    SHAPE ABUTMENT ;
    PORT
      LAYER metal3 ;
      RECT 0.000 208.285 0.070 208.355 ;
    END
  END wd_in[50]
  PIN wd_in[51]
    DIRECTION INPUT ;
    USE SIGNAL ;
    SHAPE ABUTMENT ;
    PORT
      LAYER metal3 ;
      RECT 0.000 208.425 0.070 208.495 ;
    END
  END wd_in[51]
  PIN wd_in[52]
    DIRECTION INPUT ;
    USE SIGNAL ;
    SHAPE ABUTMENT ;
    PORT
      LAYER metal3 ;
      RECT 0.000 208.565 0.070 208.635 ;
    END
  END wd_in[52]
  PIN wd_in[53]
    DIRECTION INPUT ;
    USE SIGNAL ;
    SHAPE ABUTMENT ;
    PORT
      LAYER metal3 ;
      RECT 0.000 208.705 0.070 208.775 ;
    END
  END wd_in[53]
  PIN wd_in[54]
    DIRECTION INPUT ;
    USE SIGNAL ;
    SHAPE ABUTMENT ;
    PORT
      LAYER metal3 ;
      RECT 0.000 208.845 0.070 208.915 ;
    END
  END wd_in[54]
  PIN wd_in[55]
    DIRECTION INPUT ;
    USE SIGNAL ;
    SHAPE ABUTMENT ;
    PORT
      LAYER metal3 ;
      RECT 0.000 208.985 0.070 209.055 ;
    END
  END wd_in[55]
  PIN wd_in[56]
    DIRECTION INPUT ;
    USE SIGNAL ;
    SHAPE ABUTMENT ;
    PORT
      LAYER metal3 ;
      RECT 0.000 209.125 0.070 209.195 ;
    END
  END wd_in[56]
  PIN wd_in[57]
    DIRECTION INPUT ;
    USE SIGNAL ;
    SHAPE ABUTMENT ;
    PORT
      LAYER metal3 ;
      RECT 0.000 209.265 0.070 209.335 ;
    END
  END wd_in[57]
  PIN wd_in[58]
    DIRECTION INPUT ;
    USE SIGNAL ;
    SHAPE ABUTMENT ;
    PORT
      LAYER metal3 ;
      RECT 0.000 209.405 0.070 209.475 ;
    END
  END wd_in[58]
  PIN wd_in[59]
    DIRECTION INPUT ;
    USE SIGNAL ;
    SHAPE ABUTMENT ;
    PORT
      LAYER metal3 ;
      RECT 0.000 209.545 0.070 209.615 ;
    END
  END wd_in[59]
  PIN wd_in[60]
    DIRECTION INPUT ;
    USE SIGNAL ;
    SHAPE ABUTMENT ;
    PORT
      LAYER metal3 ;
      RECT 0.000 209.685 0.070 209.755 ;
    END
  END wd_in[60]
  PIN wd_in[61]
    DIRECTION INPUT ;
    USE SIGNAL ;
    SHAPE ABUTMENT ;
    PORT
      LAYER metal3 ;
      RECT 0.000 209.825 0.070 209.895 ;
    END
  END wd_in[61]
  PIN wd_in[62]
    DIRECTION INPUT ;
    USE SIGNAL ;
    SHAPE ABUTMENT ;
    PORT
      LAYER metal3 ;
      RECT 0.000 209.965 0.070 210.035 ;
    END
  END wd_in[62]
  PIN wd_in[63]
    DIRECTION INPUT ;
    USE SIGNAL ;
    SHAPE ABUTMENT ;
    PORT
      LAYER metal3 ;
      RECT 0.000 210.105 0.070 210.175 ;
    END
  END wd_in[63]
  PIN wd_in[64]
    DIRECTION INPUT ;
    USE SIGNAL ;
    SHAPE ABUTMENT ;
    PORT
      LAYER metal3 ;
      RECT 0.000 210.245 0.070 210.315 ;
    END
  END wd_in[64]
  PIN wd_in[65]
    DIRECTION INPUT ;
    USE SIGNAL ;
    SHAPE ABUTMENT ;
    PORT
      LAYER metal3 ;
      RECT 0.000 210.385 0.070 210.455 ;
    END
  END wd_in[65]
  PIN wd_in[66]
    DIRECTION INPUT ;
    USE SIGNAL ;
    SHAPE ABUTMENT ;
    PORT
      LAYER metal3 ;
      RECT 0.000 210.525 0.070 210.595 ;
    END
  END wd_in[66]
  PIN wd_in[67]
    DIRECTION INPUT ;
    USE SIGNAL ;
    SHAPE ABUTMENT ;
    PORT
      LAYER metal3 ;
      RECT 0.000 210.665 0.070 210.735 ;
    END
  END wd_in[67]
  PIN wd_in[68]
    DIRECTION INPUT ;
    USE SIGNAL ;
    SHAPE ABUTMENT ;
    PORT
      LAYER metal3 ;
      RECT 0.000 210.805 0.070 210.875 ;
    END
  END wd_in[68]
  PIN wd_in[69]
    DIRECTION INPUT ;
    USE SIGNAL ;
    SHAPE ABUTMENT ;
    PORT
      LAYER metal3 ;
      RECT 0.000 210.945 0.070 211.015 ;
    END
  END wd_in[69]
  PIN wd_in[70]
    DIRECTION INPUT ;
    USE SIGNAL ;
    SHAPE ABUTMENT ;
    PORT
      LAYER metal3 ;
      RECT 0.000 211.085 0.070 211.155 ;
    END
  END wd_in[70]
  PIN wd_in[71]
    DIRECTION INPUT ;
    USE SIGNAL ;
    SHAPE ABUTMENT ;
    PORT
      LAYER metal3 ;
      RECT 0.000 211.225 0.070 211.295 ;
    END
  END wd_in[71]
  PIN wd_in[72]
    DIRECTION INPUT ;
    USE SIGNAL ;
    SHAPE ABUTMENT ;
    PORT
      LAYER metal3 ;
      RECT 0.000 211.365 0.070 211.435 ;
    END
  END wd_in[72]
  PIN wd_in[73]
    DIRECTION INPUT ;
    USE SIGNAL ;
    SHAPE ABUTMENT ;
    PORT
      LAYER metal3 ;
      RECT 0.000 211.505 0.070 211.575 ;
    END
  END wd_in[73]
  PIN wd_in[74]
    DIRECTION INPUT ;
    USE SIGNAL ;
    SHAPE ABUTMENT ;
    PORT
      LAYER metal3 ;
      RECT 0.000 211.645 0.070 211.715 ;
    END
  END wd_in[74]
  PIN wd_in[75]
    DIRECTION INPUT ;
    USE SIGNAL ;
    SHAPE ABUTMENT ;
    PORT
      LAYER metal3 ;
      RECT 0.000 211.785 0.070 211.855 ;
    END
  END wd_in[75]
  PIN wd_in[76]
    DIRECTION INPUT ;
    USE SIGNAL ;
    SHAPE ABUTMENT ;
    PORT
      LAYER metal3 ;
      RECT 0.000 211.925 0.070 211.995 ;
    END
  END wd_in[76]
  PIN wd_in[77]
    DIRECTION INPUT ;
    USE SIGNAL ;
    SHAPE ABUTMENT ;
    PORT
      LAYER metal3 ;
      RECT 0.000 212.065 0.070 212.135 ;
    END
  END wd_in[77]
  PIN wd_in[78]
    DIRECTION INPUT ;
    USE SIGNAL ;
    SHAPE ABUTMENT ;
    PORT
      LAYER metal3 ;
      RECT 0.000 212.205 0.070 212.275 ;
    END
  END wd_in[78]
  PIN wd_in[79]
    DIRECTION INPUT ;
    USE SIGNAL ;
    SHAPE ABUTMENT ;
    PORT
      LAYER metal3 ;
      RECT 0.000 212.345 0.070 212.415 ;
    END
  END wd_in[79]
  PIN wd_in[80]
    DIRECTION INPUT ;
    USE SIGNAL ;
    SHAPE ABUTMENT ;
    PORT
      LAYER metal3 ;
      RECT 0.000 212.485 0.070 212.555 ;
    END
  END wd_in[80]
  PIN wd_in[81]
    DIRECTION INPUT ;
    USE SIGNAL ;
    SHAPE ABUTMENT ;
    PORT
      LAYER metal3 ;
      RECT 0.000 212.625 0.070 212.695 ;
    END
  END wd_in[81]
  PIN wd_in[82]
    DIRECTION INPUT ;
    USE SIGNAL ;
    SHAPE ABUTMENT ;
    PORT
      LAYER metal3 ;
      RECT 0.000 212.765 0.070 212.835 ;
    END
  END wd_in[82]
  PIN wd_in[83]
    DIRECTION INPUT ;
    USE SIGNAL ;
    SHAPE ABUTMENT ;
    PORT
      LAYER metal3 ;
      RECT 0.000 212.905 0.070 212.975 ;
    END
  END wd_in[83]
  PIN wd_in[84]
    DIRECTION INPUT ;
    USE SIGNAL ;
    SHAPE ABUTMENT ;
    PORT
      LAYER metal3 ;
      RECT 0.000 213.045 0.070 213.115 ;
    END
  END wd_in[84]
  PIN wd_in[85]
    DIRECTION INPUT ;
    USE SIGNAL ;
    SHAPE ABUTMENT ;
    PORT
      LAYER metal3 ;
      RECT 0.000 213.185 0.070 213.255 ;
    END
  END wd_in[85]
  PIN wd_in[86]
    DIRECTION INPUT ;
    USE SIGNAL ;
    SHAPE ABUTMENT ;
    PORT
      LAYER metal3 ;
      RECT 0.000 213.325 0.070 213.395 ;
    END
  END wd_in[86]
  PIN wd_in[87]
    DIRECTION INPUT ;
    USE SIGNAL ;
    SHAPE ABUTMENT ;
    PORT
      LAYER metal3 ;
      RECT 0.000 213.465 0.070 213.535 ;
    END
  END wd_in[87]
  PIN wd_in[88]
    DIRECTION INPUT ;
    USE SIGNAL ;
    SHAPE ABUTMENT ;
    PORT
      LAYER metal3 ;
      RECT 0.000 213.605 0.070 213.675 ;
    END
  END wd_in[88]
  PIN wd_in[89]
    DIRECTION INPUT ;
    USE SIGNAL ;
    SHAPE ABUTMENT ;
    PORT
      LAYER metal3 ;
      RECT 0.000 213.745 0.070 213.815 ;
    END
  END wd_in[89]
  PIN wd_in[90]
    DIRECTION INPUT ;
    USE SIGNAL ;
    SHAPE ABUTMENT ;
    PORT
      LAYER metal3 ;
      RECT 0.000 213.885 0.070 213.955 ;
    END
  END wd_in[90]
  PIN wd_in[91]
    DIRECTION INPUT ;
    USE SIGNAL ;
    SHAPE ABUTMENT ;
    PORT
      LAYER metal3 ;
      RECT 0.000 214.025 0.070 214.095 ;
    END
  END wd_in[91]
  PIN wd_in[92]
    DIRECTION INPUT ;
    USE SIGNAL ;
    SHAPE ABUTMENT ;
    PORT
      LAYER metal3 ;
      RECT 0.000 214.165 0.070 214.235 ;
    END
  END wd_in[92]
  PIN wd_in[93]
    DIRECTION INPUT ;
    USE SIGNAL ;
    SHAPE ABUTMENT ;
    PORT
      LAYER metal3 ;
      RECT 0.000 214.305 0.070 214.375 ;
    END
  END wd_in[93]
  PIN wd_in[94]
    DIRECTION INPUT ;
    USE SIGNAL ;
    SHAPE ABUTMENT ;
    PORT
      LAYER metal3 ;
      RECT 0.000 214.445 0.070 214.515 ;
    END
  END wd_in[94]
  PIN wd_in[95]
    DIRECTION INPUT ;
    USE SIGNAL ;
    SHAPE ABUTMENT ;
    PORT
      LAYER metal3 ;
      RECT 0.000 214.585 0.070 214.655 ;
    END
  END wd_in[95]
  PIN wd_in[96]
    DIRECTION INPUT ;
    USE SIGNAL ;
    SHAPE ABUTMENT ;
    PORT
      LAYER metal3 ;
      RECT 0.000 214.725 0.070 214.795 ;
    END
  END wd_in[96]
  PIN wd_in[97]
    DIRECTION INPUT ;
    USE SIGNAL ;
    SHAPE ABUTMENT ;
    PORT
      LAYER metal3 ;
      RECT 0.000 214.865 0.070 214.935 ;
    END
  END wd_in[97]
  PIN wd_in[98]
    DIRECTION INPUT ;
    USE SIGNAL ;
    SHAPE ABUTMENT ;
    PORT
      LAYER metal3 ;
      RECT 0.000 215.005 0.070 215.075 ;
    END
  END wd_in[98]
  PIN wd_in[99]
    DIRECTION INPUT ;
    USE SIGNAL ;
    SHAPE ABUTMENT ;
    PORT
      LAYER metal3 ;
      RECT 0.000 215.145 0.070 215.215 ;
    END
  END wd_in[99]
  PIN wd_in[100]
    DIRECTION INPUT ;
    USE SIGNAL ;
    SHAPE ABUTMENT ;
    PORT
      LAYER metal3 ;
      RECT 0.000 215.285 0.070 215.355 ;
    END
  END wd_in[100]
  PIN wd_in[101]
    DIRECTION INPUT ;
    USE SIGNAL ;
    SHAPE ABUTMENT ;
    PORT
      LAYER metal3 ;
      RECT 0.000 215.425 0.070 215.495 ;
    END
  END wd_in[101]
  PIN wd_in[102]
    DIRECTION INPUT ;
    USE SIGNAL ;
    SHAPE ABUTMENT ;
    PORT
      LAYER metal3 ;
      RECT 0.000 215.565 0.070 215.635 ;
    END
  END wd_in[102]
  PIN wd_in[103]
    DIRECTION INPUT ;
    USE SIGNAL ;
    SHAPE ABUTMENT ;
    PORT
      LAYER metal3 ;
      RECT 0.000 215.705 0.070 215.775 ;
    END
  END wd_in[103]
  PIN wd_in[104]
    DIRECTION INPUT ;
    USE SIGNAL ;
    SHAPE ABUTMENT ;
    PORT
      LAYER metal3 ;
      RECT 0.000 215.845 0.070 215.915 ;
    END
  END wd_in[104]
  PIN wd_in[105]
    DIRECTION INPUT ;
    USE SIGNAL ;
    SHAPE ABUTMENT ;
    PORT
      LAYER metal3 ;
      RECT 0.000 215.985 0.070 216.055 ;
    END
  END wd_in[105]
  PIN wd_in[106]
    DIRECTION INPUT ;
    USE SIGNAL ;
    SHAPE ABUTMENT ;
    PORT
      LAYER metal3 ;
      RECT 0.000 216.125 0.070 216.195 ;
    END
  END wd_in[106]
  PIN wd_in[107]
    DIRECTION INPUT ;
    USE SIGNAL ;
    SHAPE ABUTMENT ;
    PORT
      LAYER metal3 ;
      RECT 0.000 216.265 0.070 216.335 ;
    END
  END wd_in[107]
  PIN wd_in[108]
    DIRECTION INPUT ;
    USE SIGNAL ;
    SHAPE ABUTMENT ;
    PORT
      LAYER metal3 ;
      RECT 0.000 216.405 0.070 216.475 ;
    END
  END wd_in[108]
  PIN wd_in[109]
    DIRECTION INPUT ;
    USE SIGNAL ;
    SHAPE ABUTMENT ;
    PORT
      LAYER metal3 ;
      RECT 0.000 216.545 0.070 216.615 ;
    END
  END wd_in[109]
  PIN wd_in[110]
    DIRECTION INPUT ;
    USE SIGNAL ;
    SHAPE ABUTMENT ;
    PORT
      LAYER metal3 ;
      RECT 0.000 216.685 0.070 216.755 ;
    END
  END wd_in[110]
  PIN wd_in[111]
    DIRECTION INPUT ;
    USE SIGNAL ;
    SHAPE ABUTMENT ;
    PORT
      LAYER metal3 ;
      RECT 0.000 216.825 0.070 216.895 ;
    END
  END wd_in[111]
  PIN wd_in[112]
    DIRECTION INPUT ;
    USE SIGNAL ;
    SHAPE ABUTMENT ;
    PORT
      LAYER metal3 ;
      RECT 0.000 216.965 0.070 217.035 ;
    END
  END wd_in[112]
  PIN wd_in[113]
    DIRECTION INPUT ;
    USE SIGNAL ;
    SHAPE ABUTMENT ;
    PORT
      LAYER metal3 ;
      RECT 0.000 217.105 0.070 217.175 ;
    END
  END wd_in[113]
  PIN wd_in[114]
    DIRECTION INPUT ;
    USE SIGNAL ;
    SHAPE ABUTMENT ;
    PORT
      LAYER metal3 ;
      RECT 0.000 217.245 0.070 217.315 ;
    END
  END wd_in[114]
  PIN wd_in[115]
    DIRECTION INPUT ;
    USE SIGNAL ;
    SHAPE ABUTMENT ;
    PORT
      LAYER metal3 ;
      RECT 0.000 217.385 0.070 217.455 ;
    END
  END wd_in[115]
  PIN wd_in[116]
    DIRECTION INPUT ;
    USE SIGNAL ;
    SHAPE ABUTMENT ;
    PORT
      LAYER metal3 ;
      RECT 0.000 217.525 0.070 217.595 ;
    END
  END wd_in[116]
  PIN wd_in[117]
    DIRECTION INPUT ;
    USE SIGNAL ;
    SHAPE ABUTMENT ;
    PORT
      LAYER metal3 ;
      RECT 0.000 217.665 0.070 217.735 ;
    END
  END wd_in[117]
  PIN wd_in[118]
    DIRECTION INPUT ;
    USE SIGNAL ;
    SHAPE ABUTMENT ;
    PORT
      LAYER metal3 ;
      RECT 0.000 217.805 0.070 217.875 ;
    END
  END wd_in[118]
  PIN wd_in[119]
    DIRECTION INPUT ;
    USE SIGNAL ;
    SHAPE ABUTMENT ;
    PORT
      LAYER metal3 ;
      RECT 0.000 217.945 0.070 218.015 ;
    END
  END wd_in[119]
  PIN wd_in[120]
    DIRECTION INPUT ;
    USE SIGNAL ;
    SHAPE ABUTMENT ;
    PORT
      LAYER metal3 ;
      RECT 0.000 218.085 0.070 218.155 ;
    END
  END wd_in[120]
  PIN wd_in[121]
    DIRECTION INPUT ;
    USE SIGNAL ;
    SHAPE ABUTMENT ;
    PORT
      LAYER metal3 ;
      RECT 0.000 218.225 0.070 218.295 ;
    END
  END wd_in[121]
  PIN wd_in[122]
    DIRECTION INPUT ;
    USE SIGNAL ;
    SHAPE ABUTMENT ;
    PORT
      LAYER metal3 ;
      RECT 0.000 218.365 0.070 218.435 ;
    END
  END wd_in[122]
  PIN wd_in[123]
    DIRECTION INPUT ;
    USE SIGNAL ;
    SHAPE ABUTMENT ;
    PORT
      LAYER metal3 ;
      RECT 0.000 218.505 0.070 218.575 ;
    END
  END wd_in[123]
  PIN wd_in[124]
    DIRECTION INPUT ;
    USE SIGNAL ;
    SHAPE ABUTMENT ;
    PORT
      LAYER metal3 ;
      RECT 0.000 218.645 0.070 218.715 ;
    END
  END wd_in[124]
  PIN wd_in[125]
    DIRECTION INPUT ;
    USE SIGNAL ;
    SHAPE ABUTMENT ;
    PORT
      LAYER metal3 ;
      RECT 0.000 218.785 0.070 218.855 ;
    END
  END wd_in[125]
  PIN wd_in[126]
    DIRECTION INPUT ;
    USE SIGNAL ;
    SHAPE ABUTMENT ;
    PORT
      LAYER metal3 ;
      RECT 0.000 218.925 0.070 218.995 ;
    END
  END wd_in[126]
  PIN wd_in[127]
    DIRECTION INPUT ;
    USE SIGNAL ;
    SHAPE ABUTMENT ;
    PORT
      LAYER metal3 ;
      RECT 0.000 219.065 0.070 219.135 ;
    END
  END wd_in[127]
  PIN wd_in[128]
    DIRECTION INPUT ;
    USE SIGNAL ;
    SHAPE ABUTMENT ;
    PORT
      LAYER metal3 ;
      RECT 0.000 219.205 0.070 219.275 ;
    END
  END wd_in[128]
  PIN wd_in[129]
    DIRECTION INPUT ;
    USE SIGNAL ;
    SHAPE ABUTMENT ;
    PORT
      LAYER metal3 ;
      RECT 0.000 219.345 0.070 219.415 ;
    END
  END wd_in[129]
  PIN wd_in[130]
    DIRECTION INPUT ;
    USE SIGNAL ;
    SHAPE ABUTMENT ;
    PORT
      LAYER metal3 ;
      RECT 0.000 219.485 0.070 219.555 ;
    END
  END wd_in[130]
  PIN wd_in[131]
    DIRECTION INPUT ;
    USE SIGNAL ;
    SHAPE ABUTMENT ;
    PORT
      LAYER metal3 ;
      RECT 0.000 219.625 0.070 219.695 ;
    END
  END wd_in[131]
  PIN wd_in[132]
    DIRECTION INPUT ;
    USE SIGNAL ;
    SHAPE ABUTMENT ;
    PORT
      LAYER metal3 ;
      RECT 0.000 219.765 0.070 219.835 ;
    END
  END wd_in[132]
  PIN wd_in[133]
    DIRECTION INPUT ;
    USE SIGNAL ;
    SHAPE ABUTMENT ;
    PORT
      LAYER metal3 ;
      RECT 0.000 219.905 0.070 219.975 ;
    END
  END wd_in[133]
  PIN wd_in[134]
    DIRECTION INPUT ;
    USE SIGNAL ;
    SHAPE ABUTMENT ;
    PORT
      LAYER metal3 ;
      RECT 0.000 220.045 0.070 220.115 ;
    END
  END wd_in[134]
  PIN wd_in[135]
    DIRECTION INPUT ;
    USE SIGNAL ;
    SHAPE ABUTMENT ;
    PORT
      LAYER metal3 ;
      RECT 0.000 220.185 0.070 220.255 ;
    END
  END wd_in[135]
  PIN wd_in[136]
    DIRECTION INPUT ;
    USE SIGNAL ;
    SHAPE ABUTMENT ;
    PORT
      LAYER metal3 ;
      RECT 0.000 220.325 0.070 220.395 ;
    END
  END wd_in[136]
  PIN wd_in[137]
    DIRECTION INPUT ;
    USE SIGNAL ;
    SHAPE ABUTMENT ;
    PORT
      LAYER metal3 ;
      RECT 0.000 220.465 0.070 220.535 ;
    END
  END wd_in[137]
  PIN wd_in[138]
    DIRECTION INPUT ;
    USE SIGNAL ;
    SHAPE ABUTMENT ;
    PORT
      LAYER metal3 ;
      RECT 0.000 220.605 0.070 220.675 ;
    END
  END wd_in[138]
  PIN wd_in[139]
    DIRECTION INPUT ;
    USE SIGNAL ;
    SHAPE ABUTMENT ;
    PORT
      LAYER metal3 ;
      RECT 0.000 220.745 0.070 220.815 ;
    END
  END wd_in[139]
  PIN wd_in[140]
    DIRECTION INPUT ;
    USE SIGNAL ;
    SHAPE ABUTMENT ;
    PORT
      LAYER metal3 ;
      RECT 0.000 220.885 0.070 220.955 ;
    END
  END wd_in[140]
  PIN wd_in[141]
    DIRECTION INPUT ;
    USE SIGNAL ;
    SHAPE ABUTMENT ;
    PORT
      LAYER metal3 ;
      RECT 0.000 221.025 0.070 221.095 ;
    END
  END wd_in[141]
  PIN wd_in[142]
    DIRECTION INPUT ;
    USE SIGNAL ;
    SHAPE ABUTMENT ;
    PORT
      LAYER metal3 ;
      RECT 0.000 221.165 0.070 221.235 ;
    END
  END wd_in[142]
  PIN wd_in[143]
    DIRECTION INPUT ;
    USE SIGNAL ;
    SHAPE ABUTMENT ;
    PORT
      LAYER metal3 ;
      RECT 0.000 221.305 0.070 221.375 ;
    END
  END wd_in[143]
  PIN wd_in[144]
    DIRECTION INPUT ;
    USE SIGNAL ;
    SHAPE ABUTMENT ;
    PORT
      LAYER metal3 ;
      RECT 0.000 221.445 0.070 221.515 ;
    END
  END wd_in[144]
  PIN wd_in[145]
    DIRECTION INPUT ;
    USE SIGNAL ;
    SHAPE ABUTMENT ;
    PORT
      LAYER metal3 ;
      RECT 0.000 221.585 0.070 221.655 ;
    END
  END wd_in[145]
  PIN wd_in[146]
    DIRECTION INPUT ;
    USE SIGNAL ;
    SHAPE ABUTMENT ;
    PORT
      LAYER metal3 ;
      RECT 0.000 221.725 0.070 221.795 ;
    END
  END wd_in[146]
  PIN wd_in[147]
    DIRECTION INPUT ;
    USE SIGNAL ;
    SHAPE ABUTMENT ;
    PORT
      LAYER metal3 ;
      RECT 0.000 221.865 0.070 221.935 ;
    END
  END wd_in[147]
  PIN wd_in[148]
    DIRECTION INPUT ;
    USE SIGNAL ;
    SHAPE ABUTMENT ;
    PORT
      LAYER metal3 ;
      RECT 0.000 222.005 0.070 222.075 ;
    END
  END wd_in[148]
  PIN wd_in[149]
    DIRECTION INPUT ;
    USE SIGNAL ;
    SHAPE ABUTMENT ;
    PORT
      LAYER metal3 ;
      RECT 0.000 222.145 0.070 222.215 ;
    END
  END wd_in[149]
  PIN wd_in[150]
    DIRECTION INPUT ;
    USE SIGNAL ;
    SHAPE ABUTMENT ;
    PORT
      LAYER metal3 ;
      RECT 0.000 222.285 0.070 222.355 ;
    END
  END wd_in[150]
  PIN wd_in[151]
    DIRECTION INPUT ;
    USE SIGNAL ;
    SHAPE ABUTMENT ;
    PORT
      LAYER metal3 ;
      RECT 0.000 222.425 0.070 222.495 ;
    END
  END wd_in[151]
  PIN wd_in[152]
    DIRECTION INPUT ;
    USE SIGNAL ;
    SHAPE ABUTMENT ;
    PORT
      LAYER metal3 ;
      RECT 0.000 222.565 0.070 222.635 ;
    END
  END wd_in[152]
  PIN wd_in[153]
    DIRECTION INPUT ;
    USE SIGNAL ;
    SHAPE ABUTMENT ;
    PORT
      LAYER metal3 ;
      RECT 0.000 222.705 0.070 222.775 ;
    END
  END wd_in[153]
  PIN wd_in[154]
    DIRECTION INPUT ;
    USE SIGNAL ;
    SHAPE ABUTMENT ;
    PORT
      LAYER metal3 ;
      RECT 0.000 222.845 0.070 222.915 ;
    END
  END wd_in[154]
  PIN wd_in[155]
    DIRECTION INPUT ;
    USE SIGNAL ;
    SHAPE ABUTMENT ;
    PORT
      LAYER metal3 ;
      RECT 0.000 222.985 0.070 223.055 ;
    END
  END wd_in[155]
  PIN wd_in[156]
    DIRECTION INPUT ;
    USE SIGNAL ;
    SHAPE ABUTMENT ;
    PORT
      LAYER metal3 ;
      RECT 0.000 223.125 0.070 223.195 ;
    END
  END wd_in[156]
  PIN wd_in[157]
    DIRECTION INPUT ;
    USE SIGNAL ;
    SHAPE ABUTMENT ;
    PORT
      LAYER metal3 ;
      RECT 0.000 223.265 0.070 223.335 ;
    END
  END wd_in[157]
  PIN wd_in[158]
    DIRECTION INPUT ;
    USE SIGNAL ;
    SHAPE ABUTMENT ;
    PORT
      LAYER metal3 ;
      RECT 0.000 223.405 0.070 223.475 ;
    END
  END wd_in[158]
  PIN wd_in[159]
    DIRECTION INPUT ;
    USE SIGNAL ;
    SHAPE ABUTMENT ;
    PORT
      LAYER metal3 ;
      RECT 0.000 223.545 0.070 223.615 ;
    END
  END wd_in[159]
  PIN wd_in[160]
    DIRECTION INPUT ;
    USE SIGNAL ;
    SHAPE ABUTMENT ;
    PORT
      LAYER metal3 ;
      RECT 0.000 223.685 0.070 223.755 ;
    END
  END wd_in[160]
  PIN wd_in[161]
    DIRECTION INPUT ;
    USE SIGNAL ;
    SHAPE ABUTMENT ;
    PORT
      LAYER metal3 ;
      RECT 0.000 223.825 0.070 223.895 ;
    END
  END wd_in[161]
  PIN wd_in[162]
    DIRECTION INPUT ;
    USE SIGNAL ;
    SHAPE ABUTMENT ;
    PORT
      LAYER metal3 ;
      RECT 0.000 223.965 0.070 224.035 ;
    END
  END wd_in[162]
  PIN wd_in[163]
    DIRECTION INPUT ;
    USE SIGNAL ;
    SHAPE ABUTMENT ;
    PORT
      LAYER metal3 ;
      RECT 0.000 224.105 0.070 224.175 ;
    END
  END wd_in[163]
  PIN wd_in[164]
    DIRECTION INPUT ;
    USE SIGNAL ;
    SHAPE ABUTMENT ;
    PORT
      LAYER metal3 ;
      RECT 0.000 224.245 0.070 224.315 ;
    END
  END wd_in[164]
  PIN wd_in[165]
    DIRECTION INPUT ;
    USE SIGNAL ;
    SHAPE ABUTMENT ;
    PORT
      LAYER metal3 ;
      RECT 0.000 224.385 0.070 224.455 ;
    END
  END wd_in[165]
  PIN wd_in[166]
    DIRECTION INPUT ;
    USE SIGNAL ;
    SHAPE ABUTMENT ;
    PORT
      LAYER metal3 ;
      RECT 0.000 224.525 0.070 224.595 ;
    END
  END wd_in[166]
  PIN wd_in[167]
    DIRECTION INPUT ;
    USE SIGNAL ;
    SHAPE ABUTMENT ;
    PORT
      LAYER metal3 ;
      RECT 0.000 224.665 0.070 224.735 ;
    END
  END wd_in[167]
  PIN wd_in[168]
    DIRECTION INPUT ;
    USE SIGNAL ;
    SHAPE ABUTMENT ;
    PORT
      LAYER metal3 ;
      RECT 0.000 224.805 0.070 224.875 ;
    END
  END wd_in[168]
  PIN wd_in[169]
    DIRECTION INPUT ;
    USE SIGNAL ;
    SHAPE ABUTMENT ;
    PORT
      LAYER metal3 ;
      RECT 0.000 224.945 0.070 225.015 ;
    END
  END wd_in[169]
  PIN wd_in[170]
    DIRECTION INPUT ;
    USE SIGNAL ;
    SHAPE ABUTMENT ;
    PORT
      LAYER metal3 ;
      RECT 0.000 225.085 0.070 225.155 ;
    END
  END wd_in[170]
  PIN wd_in[171]
    DIRECTION INPUT ;
    USE SIGNAL ;
    SHAPE ABUTMENT ;
    PORT
      LAYER metal3 ;
      RECT 0.000 225.225 0.070 225.295 ;
    END
  END wd_in[171]
  PIN wd_in[172]
    DIRECTION INPUT ;
    USE SIGNAL ;
    SHAPE ABUTMENT ;
    PORT
      LAYER metal3 ;
      RECT 0.000 225.365 0.070 225.435 ;
    END
  END wd_in[172]
  PIN wd_in[173]
    DIRECTION INPUT ;
    USE SIGNAL ;
    SHAPE ABUTMENT ;
    PORT
      LAYER metal3 ;
      RECT 0.000 225.505 0.070 225.575 ;
    END
  END wd_in[173]
  PIN wd_in[174]
    DIRECTION INPUT ;
    USE SIGNAL ;
    SHAPE ABUTMENT ;
    PORT
      LAYER metal3 ;
      RECT 0.000 225.645 0.070 225.715 ;
    END
  END wd_in[174]
  PIN wd_in[175]
    DIRECTION INPUT ;
    USE SIGNAL ;
    SHAPE ABUTMENT ;
    PORT
      LAYER metal3 ;
      RECT 0.000 225.785 0.070 225.855 ;
    END
  END wd_in[175]
  PIN wd_in[176]
    DIRECTION INPUT ;
    USE SIGNAL ;
    SHAPE ABUTMENT ;
    PORT
      LAYER metal3 ;
      RECT 0.000 225.925 0.070 225.995 ;
    END
  END wd_in[176]
  PIN wd_in[177]
    DIRECTION INPUT ;
    USE SIGNAL ;
    SHAPE ABUTMENT ;
    PORT
      LAYER metal3 ;
      RECT 0.000 226.065 0.070 226.135 ;
    END
  END wd_in[177]
  PIN wd_in[178]
    DIRECTION INPUT ;
    USE SIGNAL ;
    SHAPE ABUTMENT ;
    PORT
      LAYER metal3 ;
      RECT 0.000 226.205 0.070 226.275 ;
    END
  END wd_in[178]
  PIN wd_in[179]
    DIRECTION INPUT ;
    USE SIGNAL ;
    SHAPE ABUTMENT ;
    PORT
      LAYER metal3 ;
      RECT 0.000 226.345 0.070 226.415 ;
    END
  END wd_in[179]
  PIN wd_in[180]
    DIRECTION INPUT ;
    USE SIGNAL ;
    SHAPE ABUTMENT ;
    PORT
      LAYER metal3 ;
      RECT 0.000 226.485 0.070 226.555 ;
    END
  END wd_in[180]
  PIN wd_in[181]
    DIRECTION INPUT ;
    USE SIGNAL ;
    SHAPE ABUTMENT ;
    PORT
      LAYER metal3 ;
      RECT 0.000 226.625 0.070 226.695 ;
    END
  END wd_in[181]
  PIN wd_in[182]
    DIRECTION INPUT ;
    USE SIGNAL ;
    SHAPE ABUTMENT ;
    PORT
      LAYER metal3 ;
      RECT 0.000 226.765 0.070 226.835 ;
    END
  END wd_in[182]
  PIN wd_in[183]
    DIRECTION INPUT ;
    USE SIGNAL ;
    SHAPE ABUTMENT ;
    PORT
      LAYER metal3 ;
      RECT 0.000 226.905 0.070 226.975 ;
    END
  END wd_in[183]
  PIN wd_in[184]
    DIRECTION INPUT ;
    USE SIGNAL ;
    SHAPE ABUTMENT ;
    PORT
      LAYER metal3 ;
      RECT 0.000 227.045 0.070 227.115 ;
    END
  END wd_in[184]
  PIN wd_in[185]
    DIRECTION INPUT ;
    USE SIGNAL ;
    SHAPE ABUTMENT ;
    PORT
      LAYER metal3 ;
      RECT 0.000 227.185 0.070 227.255 ;
    END
  END wd_in[185]
  PIN wd_in[186]
    DIRECTION INPUT ;
    USE SIGNAL ;
    SHAPE ABUTMENT ;
    PORT
      LAYER metal3 ;
      RECT 0.000 227.325 0.070 227.395 ;
    END
  END wd_in[186]
  PIN wd_in[187]
    DIRECTION INPUT ;
    USE SIGNAL ;
    SHAPE ABUTMENT ;
    PORT
      LAYER metal3 ;
      RECT 0.000 227.465 0.070 227.535 ;
    END
  END wd_in[187]
  PIN wd_in[188]
    DIRECTION INPUT ;
    USE SIGNAL ;
    SHAPE ABUTMENT ;
    PORT
      LAYER metal3 ;
      RECT 0.000 227.605 0.070 227.675 ;
    END
  END wd_in[188]
  PIN wd_in[189]
    DIRECTION INPUT ;
    USE SIGNAL ;
    SHAPE ABUTMENT ;
    PORT
      LAYER metal3 ;
      RECT 0.000 227.745 0.070 227.815 ;
    END
  END wd_in[189]
  PIN wd_in[190]
    DIRECTION INPUT ;
    USE SIGNAL ;
    SHAPE ABUTMENT ;
    PORT
      LAYER metal3 ;
      RECT 0.000 227.885 0.070 227.955 ;
    END
  END wd_in[190]
  PIN wd_in[191]
    DIRECTION INPUT ;
    USE SIGNAL ;
    SHAPE ABUTMENT ;
    PORT
      LAYER metal3 ;
      RECT 0.000 228.025 0.070 228.095 ;
    END
  END wd_in[191]
  PIN wd_in[192]
    DIRECTION INPUT ;
    USE SIGNAL ;
    SHAPE ABUTMENT ;
    PORT
      LAYER metal3 ;
      RECT 0.000 228.165 0.070 228.235 ;
    END
  END wd_in[192]
  PIN wd_in[193]
    DIRECTION INPUT ;
    USE SIGNAL ;
    SHAPE ABUTMENT ;
    PORT
      LAYER metal3 ;
      RECT 0.000 228.305 0.070 228.375 ;
    END
  END wd_in[193]
  PIN wd_in[194]
    DIRECTION INPUT ;
    USE SIGNAL ;
    SHAPE ABUTMENT ;
    PORT
      LAYER metal3 ;
      RECT 0.000 228.445 0.070 228.515 ;
    END
  END wd_in[194]
  PIN wd_in[195]
    DIRECTION INPUT ;
    USE SIGNAL ;
    SHAPE ABUTMENT ;
    PORT
      LAYER metal3 ;
      RECT 0.000 228.585 0.070 228.655 ;
    END
  END wd_in[195]
  PIN wd_in[196]
    DIRECTION INPUT ;
    USE SIGNAL ;
    SHAPE ABUTMENT ;
    PORT
      LAYER metal3 ;
      RECT 0.000 228.725 0.070 228.795 ;
    END
  END wd_in[196]
  PIN wd_in[197]
    DIRECTION INPUT ;
    USE SIGNAL ;
    SHAPE ABUTMENT ;
    PORT
      LAYER metal3 ;
      RECT 0.000 228.865 0.070 228.935 ;
    END
  END wd_in[197]
  PIN wd_in[198]
    DIRECTION INPUT ;
    USE SIGNAL ;
    SHAPE ABUTMENT ;
    PORT
      LAYER metal3 ;
      RECT 0.000 229.005 0.070 229.075 ;
    END
  END wd_in[198]
  PIN wd_in[199]
    DIRECTION INPUT ;
    USE SIGNAL ;
    SHAPE ABUTMENT ;
    PORT
      LAYER metal3 ;
      RECT 0.000 229.145 0.070 229.215 ;
    END
  END wd_in[199]
  PIN wd_in[200]
    DIRECTION INPUT ;
    USE SIGNAL ;
    SHAPE ABUTMENT ;
    PORT
      LAYER metal3 ;
      RECT 0.000 229.285 0.070 229.355 ;
    END
  END wd_in[200]
  PIN wd_in[201]
    DIRECTION INPUT ;
    USE SIGNAL ;
    SHAPE ABUTMENT ;
    PORT
      LAYER metal3 ;
      RECT 0.000 229.425 0.070 229.495 ;
    END
  END wd_in[201]
  PIN wd_in[202]
    DIRECTION INPUT ;
    USE SIGNAL ;
    SHAPE ABUTMENT ;
    PORT
      LAYER metal3 ;
      RECT 0.000 229.565 0.070 229.635 ;
    END
  END wd_in[202]
  PIN wd_in[203]
    DIRECTION INPUT ;
    USE SIGNAL ;
    SHAPE ABUTMENT ;
    PORT
      LAYER metal3 ;
      RECT 0.000 229.705 0.070 229.775 ;
    END
  END wd_in[203]
  PIN wd_in[204]
    DIRECTION INPUT ;
    USE SIGNAL ;
    SHAPE ABUTMENT ;
    PORT
      LAYER metal3 ;
      RECT 0.000 229.845 0.070 229.915 ;
    END
  END wd_in[204]
  PIN wd_in[205]
    DIRECTION INPUT ;
    USE SIGNAL ;
    SHAPE ABUTMENT ;
    PORT
      LAYER metal3 ;
      RECT 0.000 229.985 0.070 230.055 ;
    END
  END wd_in[205]
  PIN wd_in[206]
    DIRECTION INPUT ;
    USE SIGNAL ;
    SHAPE ABUTMENT ;
    PORT
      LAYER metal3 ;
      RECT 0.000 230.125 0.070 230.195 ;
    END
  END wd_in[206]
  PIN wd_in[207]
    DIRECTION INPUT ;
    USE SIGNAL ;
    SHAPE ABUTMENT ;
    PORT
      LAYER metal3 ;
      RECT 0.000 230.265 0.070 230.335 ;
    END
  END wd_in[207]
  PIN wd_in[208]
    DIRECTION INPUT ;
    USE SIGNAL ;
    SHAPE ABUTMENT ;
    PORT
      LAYER metal3 ;
      RECT 0.000 230.405 0.070 230.475 ;
    END
  END wd_in[208]
  PIN wd_in[209]
    DIRECTION INPUT ;
    USE SIGNAL ;
    SHAPE ABUTMENT ;
    PORT
      LAYER metal3 ;
      RECT 0.000 230.545 0.070 230.615 ;
    END
  END wd_in[209]
  PIN wd_in[210]
    DIRECTION INPUT ;
    USE SIGNAL ;
    SHAPE ABUTMENT ;
    PORT
      LAYER metal3 ;
      RECT 0.000 230.685 0.070 230.755 ;
    END
  END wd_in[210]
  PIN wd_in[211]
    DIRECTION INPUT ;
    USE SIGNAL ;
    SHAPE ABUTMENT ;
    PORT
      LAYER metal3 ;
      RECT 0.000 230.825 0.070 230.895 ;
    END
  END wd_in[211]
  PIN wd_in[212]
    DIRECTION INPUT ;
    USE SIGNAL ;
    SHAPE ABUTMENT ;
    PORT
      LAYER metal3 ;
      RECT 0.000 230.965 0.070 231.035 ;
    END
  END wd_in[212]
  PIN wd_in[213]
    DIRECTION INPUT ;
    USE SIGNAL ;
    SHAPE ABUTMENT ;
    PORT
      LAYER metal3 ;
      RECT 0.000 231.105 0.070 231.175 ;
    END
  END wd_in[213]
  PIN wd_in[214]
    DIRECTION INPUT ;
    USE SIGNAL ;
    SHAPE ABUTMENT ;
    PORT
      LAYER metal3 ;
      RECT 0.000 231.245 0.070 231.315 ;
    END
  END wd_in[214]
  PIN wd_in[215]
    DIRECTION INPUT ;
    USE SIGNAL ;
    SHAPE ABUTMENT ;
    PORT
      LAYER metal3 ;
      RECT 0.000 231.385 0.070 231.455 ;
    END
  END wd_in[215]
  PIN wd_in[216]
    DIRECTION INPUT ;
    USE SIGNAL ;
    SHAPE ABUTMENT ;
    PORT
      LAYER metal3 ;
      RECT 0.000 231.525 0.070 231.595 ;
    END
  END wd_in[216]
  PIN wd_in[217]
    DIRECTION INPUT ;
    USE SIGNAL ;
    SHAPE ABUTMENT ;
    PORT
      LAYER metal3 ;
      RECT 0.000 231.665 0.070 231.735 ;
    END
  END wd_in[217]
  PIN wd_in[218]
    DIRECTION INPUT ;
    USE SIGNAL ;
    SHAPE ABUTMENT ;
    PORT
      LAYER metal3 ;
      RECT 0.000 231.805 0.070 231.875 ;
    END
  END wd_in[218]
  PIN wd_in[219]
    DIRECTION INPUT ;
    USE SIGNAL ;
    SHAPE ABUTMENT ;
    PORT
      LAYER metal3 ;
      RECT 0.000 231.945 0.070 232.015 ;
    END
  END wd_in[219]
  PIN wd_in[220]
    DIRECTION INPUT ;
    USE SIGNAL ;
    SHAPE ABUTMENT ;
    PORT
      LAYER metal3 ;
      RECT 0.000 232.085 0.070 232.155 ;
    END
  END wd_in[220]
  PIN wd_in[221]
    DIRECTION INPUT ;
    USE SIGNAL ;
    SHAPE ABUTMENT ;
    PORT
      LAYER metal3 ;
      RECT 0.000 232.225 0.070 232.295 ;
    END
  END wd_in[221]
  PIN wd_in[222]
    DIRECTION INPUT ;
    USE SIGNAL ;
    SHAPE ABUTMENT ;
    PORT
      LAYER metal3 ;
      RECT 0.000 232.365 0.070 232.435 ;
    END
  END wd_in[222]
  PIN wd_in[223]
    DIRECTION INPUT ;
    USE SIGNAL ;
    SHAPE ABUTMENT ;
    PORT
      LAYER metal3 ;
      RECT 0.000 232.505 0.070 232.575 ;
    END
  END wd_in[223]
  PIN wd_in[224]
    DIRECTION INPUT ;
    USE SIGNAL ;
    SHAPE ABUTMENT ;
    PORT
      LAYER metal3 ;
      RECT 0.000 232.645 0.070 232.715 ;
    END
  END wd_in[224]
  PIN wd_in[225]
    DIRECTION INPUT ;
    USE SIGNAL ;
    SHAPE ABUTMENT ;
    PORT
      LAYER metal3 ;
      RECT 0.000 232.785 0.070 232.855 ;
    END
  END wd_in[225]
  PIN wd_in[226]
    DIRECTION INPUT ;
    USE SIGNAL ;
    SHAPE ABUTMENT ;
    PORT
      LAYER metal3 ;
      RECT 0.000 232.925 0.070 232.995 ;
    END
  END wd_in[226]
  PIN wd_in[227]
    DIRECTION INPUT ;
    USE SIGNAL ;
    SHAPE ABUTMENT ;
    PORT
      LAYER metal3 ;
      RECT 0.000 233.065 0.070 233.135 ;
    END
  END wd_in[227]
  PIN wd_in[228]
    DIRECTION INPUT ;
    USE SIGNAL ;
    SHAPE ABUTMENT ;
    PORT
      LAYER metal3 ;
      RECT 0.000 233.205 0.070 233.275 ;
    END
  END wd_in[228]
  PIN wd_in[229]
    DIRECTION INPUT ;
    USE SIGNAL ;
    SHAPE ABUTMENT ;
    PORT
      LAYER metal3 ;
      RECT 0.000 233.345 0.070 233.415 ;
    END
  END wd_in[229]
  PIN wd_in[230]
    DIRECTION INPUT ;
    USE SIGNAL ;
    SHAPE ABUTMENT ;
    PORT
      LAYER metal3 ;
      RECT 0.000 233.485 0.070 233.555 ;
    END
  END wd_in[230]
  PIN wd_in[231]
    DIRECTION INPUT ;
    USE SIGNAL ;
    SHAPE ABUTMENT ;
    PORT
      LAYER metal3 ;
      RECT 0.000 233.625 0.070 233.695 ;
    END
  END wd_in[231]
  PIN wd_in[232]
    DIRECTION INPUT ;
    USE SIGNAL ;
    SHAPE ABUTMENT ;
    PORT
      LAYER metal3 ;
      RECT 0.000 233.765 0.070 233.835 ;
    END
  END wd_in[232]
  PIN wd_in[233]
    DIRECTION INPUT ;
    USE SIGNAL ;
    SHAPE ABUTMENT ;
    PORT
      LAYER metal3 ;
      RECT 0.000 233.905 0.070 233.975 ;
    END
  END wd_in[233]
  PIN wd_in[234]
    DIRECTION INPUT ;
    USE SIGNAL ;
    SHAPE ABUTMENT ;
    PORT
      LAYER metal3 ;
      RECT 0.000 234.045 0.070 234.115 ;
    END
  END wd_in[234]
  PIN wd_in[235]
    DIRECTION INPUT ;
    USE SIGNAL ;
    SHAPE ABUTMENT ;
    PORT
      LAYER metal3 ;
      RECT 0.000 234.185 0.070 234.255 ;
    END
  END wd_in[235]
  PIN wd_in[236]
    DIRECTION INPUT ;
    USE SIGNAL ;
    SHAPE ABUTMENT ;
    PORT
      LAYER metal3 ;
      RECT 0.000 234.325 0.070 234.395 ;
    END
  END wd_in[236]
  PIN wd_in[237]
    DIRECTION INPUT ;
    USE SIGNAL ;
    SHAPE ABUTMENT ;
    PORT
      LAYER metal3 ;
      RECT 0.000 234.465 0.070 234.535 ;
    END
  END wd_in[237]
  PIN wd_in[238]
    DIRECTION INPUT ;
    USE SIGNAL ;
    SHAPE ABUTMENT ;
    PORT
      LAYER metal3 ;
      RECT 0.000 234.605 0.070 234.675 ;
    END
  END wd_in[238]
  PIN wd_in[239]
    DIRECTION INPUT ;
    USE SIGNAL ;
    SHAPE ABUTMENT ;
    PORT
      LAYER metal3 ;
      RECT 0.000 234.745 0.070 234.815 ;
    END
  END wd_in[239]
  PIN wd_in[240]
    DIRECTION INPUT ;
    USE SIGNAL ;
    SHAPE ABUTMENT ;
    PORT
      LAYER metal3 ;
      RECT 0.000 234.885 0.070 234.955 ;
    END
  END wd_in[240]
  PIN wd_in[241]
    DIRECTION INPUT ;
    USE SIGNAL ;
    SHAPE ABUTMENT ;
    PORT
      LAYER metal3 ;
      RECT 0.000 235.025 0.070 235.095 ;
    END
  END wd_in[241]
  PIN wd_in[242]
    DIRECTION INPUT ;
    USE SIGNAL ;
    SHAPE ABUTMENT ;
    PORT
      LAYER metal3 ;
      RECT 0.000 235.165 0.070 235.235 ;
    END
  END wd_in[242]
  PIN wd_in[243]
    DIRECTION INPUT ;
    USE SIGNAL ;
    SHAPE ABUTMENT ;
    PORT
      LAYER metal3 ;
      RECT 0.000 235.305 0.070 235.375 ;
    END
  END wd_in[243]
  PIN wd_in[244]
    DIRECTION INPUT ;
    USE SIGNAL ;
    SHAPE ABUTMENT ;
    PORT
      LAYER metal3 ;
      RECT 0.000 235.445 0.070 235.515 ;
    END
  END wd_in[244]
  PIN wd_in[245]
    DIRECTION INPUT ;
    USE SIGNAL ;
    SHAPE ABUTMENT ;
    PORT
      LAYER metal3 ;
      RECT 0.000 235.585 0.070 235.655 ;
    END
  END wd_in[245]
  PIN wd_in[246]
    DIRECTION INPUT ;
    USE SIGNAL ;
    SHAPE ABUTMENT ;
    PORT
      LAYER metal3 ;
      RECT 0.000 235.725 0.070 235.795 ;
    END
  END wd_in[246]
  PIN wd_in[247]
    DIRECTION INPUT ;
    USE SIGNAL ;
    SHAPE ABUTMENT ;
    PORT
      LAYER metal3 ;
      RECT 0.000 235.865 0.070 235.935 ;
    END
  END wd_in[247]
  PIN wd_in[248]
    DIRECTION INPUT ;
    USE SIGNAL ;
    SHAPE ABUTMENT ;
    PORT
      LAYER metal3 ;
      RECT 0.000 236.005 0.070 236.075 ;
    END
  END wd_in[248]
  PIN wd_in[249]
    DIRECTION INPUT ;
    USE SIGNAL ;
    SHAPE ABUTMENT ;
    PORT
      LAYER metal3 ;
      RECT 0.000 236.145 0.070 236.215 ;
    END
  END wd_in[249]
  PIN wd_in[250]
    DIRECTION INPUT ;
    USE SIGNAL ;
    SHAPE ABUTMENT ;
    PORT
      LAYER metal3 ;
      RECT 0.000 236.285 0.070 236.355 ;
    END
  END wd_in[250]
  PIN wd_in[251]
    DIRECTION INPUT ;
    USE SIGNAL ;
    SHAPE ABUTMENT ;
    PORT
      LAYER metal3 ;
      RECT 0.000 236.425 0.070 236.495 ;
    END
  END wd_in[251]
  PIN wd_in[252]
    DIRECTION INPUT ;
    USE SIGNAL ;
    SHAPE ABUTMENT ;
    PORT
      LAYER metal3 ;
      RECT 0.000 236.565 0.070 236.635 ;
    END
  END wd_in[252]
  PIN wd_in[253]
    DIRECTION INPUT ;
    USE SIGNAL ;
    SHAPE ABUTMENT ;
    PORT
      LAYER metal3 ;
      RECT 0.000 236.705 0.070 236.775 ;
    END
  END wd_in[253]
  PIN wd_in[254]
    DIRECTION INPUT ;
    USE SIGNAL ;
    SHAPE ABUTMENT ;
    PORT
      LAYER metal3 ;
      RECT 0.000 236.845 0.070 236.915 ;
    END
  END wd_in[254]
  PIN wd_in[255]
    DIRECTION INPUT ;
    USE SIGNAL ;
    SHAPE ABUTMENT ;
    PORT
      LAYER metal3 ;
      RECT 0.000 236.985 0.070 237.055 ;
    END
  END wd_in[255]
  PIN wd_in[256]
    DIRECTION INPUT ;
    USE SIGNAL ;
    SHAPE ABUTMENT ;
    PORT
      LAYER metal3 ;
      RECT 0.000 237.125 0.070 237.195 ;
    END
  END wd_in[256]
  PIN wd_in[257]
    DIRECTION INPUT ;
    USE SIGNAL ;
    SHAPE ABUTMENT ;
    PORT
      LAYER metal3 ;
      RECT 0.000 237.265 0.070 237.335 ;
    END
  END wd_in[257]
  PIN wd_in[258]
    DIRECTION INPUT ;
    USE SIGNAL ;
    SHAPE ABUTMENT ;
    PORT
      LAYER metal3 ;
      RECT 0.000 237.405 0.070 237.475 ;
    END
  END wd_in[258]
  PIN wd_in[259]
    DIRECTION INPUT ;
    USE SIGNAL ;
    SHAPE ABUTMENT ;
    PORT
      LAYER metal3 ;
      RECT 0.000 237.545 0.070 237.615 ;
    END
  END wd_in[259]
  PIN wd_in[260]
    DIRECTION INPUT ;
    USE SIGNAL ;
    SHAPE ABUTMENT ;
    PORT
      LAYER metal3 ;
      RECT 0.000 237.685 0.070 237.755 ;
    END
  END wd_in[260]
  PIN wd_in[261]
    DIRECTION INPUT ;
    USE SIGNAL ;
    SHAPE ABUTMENT ;
    PORT
      LAYER metal3 ;
      RECT 0.000 237.825 0.070 237.895 ;
    END
  END wd_in[261]
  PIN wd_in[262]
    DIRECTION INPUT ;
    USE SIGNAL ;
    SHAPE ABUTMENT ;
    PORT
      LAYER metal3 ;
      RECT 0.000 237.965 0.070 238.035 ;
    END
  END wd_in[262]
  PIN wd_in[263]
    DIRECTION INPUT ;
    USE SIGNAL ;
    SHAPE ABUTMENT ;
    PORT
      LAYER metal3 ;
      RECT 0.000 238.105 0.070 238.175 ;
    END
  END wd_in[263]
  PIN wd_in[264]
    DIRECTION INPUT ;
    USE SIGNAL ;
    SHAPE ABUTMENT ;
    PORT
      LAYER metal3 ;
      RECT 0.000 238.245 0.070 238.315 ;
    END
  END wd_in[264]
  PIN wd_in[265]
    DIRECTION INPUT ;
    USE SIGNAL ;
    SHAPE ABUTMENT ;
    PORT
      LAYER metal3 ;
      RECT 0.000 238.385 0.070 238.455 ;
    END
  END wd_in[265]
  PIN wd_in[266]
    DIRECTION INPUT ;
    USE SIGNAL ;
    SHAPE ABUTMENT ;
    PORT
      LAYER metal3 ;
      RECT 0.000 238.525 0.070 238.595 ;
    END
  END wd_in[266]
  PIN wd_in[267]
    DIRECTION INPUT ;
    USE SIGNAL ;
    SHAPE ABUTMENT ;
    PORT
      LAYER metal3 ;
      RECT 0.000 238.665 0.070 238.735 ;
    END
  END wd_in[267]
  PIN wd_in[268]
    DIRECTION INPUT ;
    USE SIGNAL ;
    SHAPE ABUTMENT ;
    PORT
      LAYER metal3 ;
      RECT 0.000 238.805 0.070 238.875 ;
    END
  END wd_in[268]
  PIN wd_in[269]
    DIRECTION INPUT ;
    USE SIGNAL ;
    SHAPE ABUTMENT ;
    PORT
      LAYER metal3 ;
      RECT 0.000 238.945 0.070 239.015 ;
    END
  END wd_in[269]
  PIN wd_in[270]
    DIRECTION INPUT ;
    USE SIGNAL ;
    SHAPE ABUTMENT ;
    PORT
      LAYER metal3 ;
      RECT 0.000 239.085 0.070 239.155 ;
    END
  END wd_in[270]
  PIN wd_in[271]
    DIRECTION INPUT ;
    USE SIGNAL ;
    SHAPE ABUTMENT ;
    PORT
      LAYER metal3 ;
      RECT 0.000 239.225 0.070 239.295 ;
    END
  END wd_in[271]
  PIN wd_in[272]
    DIRECTION INPUT ;
    USE SIGNAL ;
    SHAPE ABUTMENT ;
    PORT
      LAYER metal3 ;
      RECT 0.000 239.365 0.070 239.435 ;
    END
  END wd_in[272]
  PIN wd_in[273]
    DIRECTION INPUT ;
    USE SIGNAL ;
    SHAPE ABUTMENT ;
    PORT
      LAYER metal3 ;
      RECT 0.000 239.505 0.070 239.575 ;
    END
  END wd_in[273]
  PIN wd_in[274]
    DIRECTION INPUT ;
    USE SIGNAL ;
    SHAPE ABUTMENT ;
    PORT
      LAYER metal3 ;
      RECT 0.000 239.645 0.070 239.715 ;
    END
  END wd_in[274]
  PIN wd_in[275]
    DIRECTION INPUT ;
    USE SIGNAL ;
    SHAPE ABUTMENT ;
    PORT
      LAYER metal3 ;
      RECT 0.000 239.785 0.070 239.855 ;
    END
  END wd_in[275]
  PIN wd_in[276]
    DIRECTION INPUT ;
    USE SIGNAL ;
    SHAPE ABUTMENT ;
    PORT
      LAYER metal3 ;
      RECT 0.000 239.925 0.070 239.995 ;
    END
  END wd_in[276]
  PIN wd_in[277]
    DIRECTION INPUT ;
    USE SIGNAL ;
    SHAPE ABUTMENT ;
    PORT
      LAYER metal3 ;
      RECT 0.000 240.065 0.070 240.135 ;
    END
  END wd_in[277]
  PIN wd_in[278]
    DIRECTION INPUT ;
    USE SIGNAL ;
    SHAPE ABUTMENT ;
    PORT
      LAYER metal3 ;
      RECT 0.000 240.205 0.070 240.275 ;
    END
  END wd_in[278]
  PIN wd_in[279]
    DIRECTION INPUT ;
    USE SIGNAL ;
    SHAPE ABUTMENT ;
    PORT
      LAYER metal3 ;
      RECT 0.000 240.345 0.070 240.415 ;
    END
  END wd_in[279]
  PIN wd_in[280]
    DIRECTION INPUT ;
    USE SIGNAL ;
    SHAPE ABUTMENT ;
    PORT
      LAYER metal3 ;
      RECT 0.000 240.485 0.070 240.555 ;
    END
  END wd_in[280]
  PIN wd_in[281]
    DIRECTION INPUT ;
    USE SIGNAL ;
    SHAPE ABUTMENT ;
    PORT
      LAYER metal3 ;
      RECT 0.000 240.625 0.070 240.695 ;
    END
  END wd_in[281]
  PIN wd_in[282]
    DIRECTION INPUT ;
    USE SIGNAL ;
    SHAPE ABUTMENT ;
    PORT
      LAYER metal3 ;
      RECT 0.000 240.765 0.070 240.835 ;
    END
  END wd_in[282]
  PIN wd_in[283]
    DIRECTION INPUT ;
    USE SIGNAL ;
    SHAPE ABUTMENT ;
    PORT
      LAYER metal3 ;
      RECT 0.000 240.905 0.070 240.975 ;
    END
  END wd_in[283]
  PIN wd_in[284]
    DIRECTION INPUT ;
    USE SIGNAL ;
    SHAPE ABUTMENT ;
    PORT
      LAYER metal3 ;
      RECT 0.000 241.045 0.070 241.115 ;
    END
  END wd_in[284]
  PIN wd_in[285]
    DIRECTION INPUT ;
    USE SIGNAL ;
    SHAPE ABUTMENT ;
    PORT
      LAYER metal3 ;
      RECT 0.000 241.185 0.070 241.255 ;
    END
  END wd_in[285]
  PIN wd_in[286]
    DIRECTION INPUT ;
    USE SIGNAL ;
    SHAPE ABUTMENT ;
    PORT
      LAYER metal3 ;
      RECT 0.000 241.325 0.070 241.395 ;
    END
  END wd_in[286]
  PIN wd_in[287]
    DIRECTION INPUT ;
    USE SIGNAL ;
    SHAPE ABUTMENT ;
    PORT
      LAYER metal3 ;
      RECT 0.000 241.465 0.070 241.535 ;
    END
  END wd_in[287]
  PIN wd_in[288]
    DIRECTION INPUT ;
    USE SIGNAL ;
    SHAPE ABUTMENT ;
    PORT
      LAYER metal3 ;
      RECT 0.000 241.605 0.070 241.675 ;
    END
  END wd_in[288]
  PIN wd_in[289]
    DIRECTION INPUT ;
    USE SIGNAL ;
    SHAPE ABUTMENT ;
    PORT
      LAYER metal3 ;
      RECT 0.000 241.745 0.070 241.815 ;
    END
  END wd_in[289]
  PIN wd_in[290]
    DIRECTION INPUT ;
    USE SIGNAL ;
    SHAPE ABUTMENT ;
    PORT
      LAYER metal3 ;
      RECT 0.000 241.885 0.070 241.955 ;
    END
  END wd_in[290]
  PIN wd_in[291]
    DIRECTION INPUT ;
    USE SIGNAL ;
    SHAPE ABUTMENT ;
    PORT
      LAYER metal3 ;
      RECT 0.000 242.025 0.070 242.095 ;
    END
  END wd_in[291]
  PIN wd_in[292]
    DIRECTION INPUT ;
    USE SIGNAL ;
    SHAPE ABUTMENT ;
    PORT
      LAYER metal3 ;
      RECT 0.000 242.165 0.070 242.235 ;
    END
  END wd_in[292]
  PIN wd_in[293]
    DIRECTION INPUT ;
    USE SIGNAL ;
    SHAPE ABUTMENT ;
    PORT
      LAYER metal3 ;
      RECT 0.000 242.305 0.070 242.375 ;
    END
  END wd_in[293]
  PIN wd_in[294]
    DIRECTION INPUT ;
    USE SIGNAL ;
    SHAPE ABUTMENT ;
    PORT
      LAYER metal3 ;
      RECT 0.000 242.445 0.070 242.515 ;
    END
  END wd_in[294]
  PIN wd_in[295]
    DIRECTION INPUT ;
    USE SIGNAL ;
    SHAPE ABUTMENT ;
    PORT
      LAYER metal3 ;
      RECT 0.000 242.585 0.070 242.655 ;
    END
  END wd_in[295]
  PIN wd_in[296]
    DIRECTION INPUT ;
    USE SIGNAL ;
    SHAPE ABUTMENT ;
    PORT
      LAYER metal3 ;
      RECT 0.000 242.725 0.070 242.795 ;
    END
  END wd_in[296]
  PIN wd_in[297]
    DIRECTION INPUT ;
    USE SIGNAL ;
    SHAPE ABUTMENT ;
    PORT
      LAYER metal3 ;
      RECT 0.000 242.865 0.070 242.935 ;
    END
  END wd_in[297]
  PIN wd_in[298]
    DIRECTION INPUT ;
    USE SIGNAL ;
    SHAPE ABUTMENT ;
    PORT
      LAYER metal3 ;
      RECT 0.000 243.005 0.070 243.075 ;
    END
  END wd_in[298]
  PIN wd_in[299]
    DIRECTION INPUT ;
    USE SIGNAL ;
    SHAPE ABUTMENT ;
    PORT
      LAYER metal3 ;
      RECT 0.000 243.145 0.070 243.215 ;
    END
  END wd_in[299]
  PIN wd_in[300]
    DIRECTION INPUT ;
    USE SIGNAL ;
    SHAPE ABUTMENT ;
    PORT
      LAYER metal3 ;
      RECT 0.000 243.285 0.070 243.355 ;
    END
  END wd_in[300]
  PIN wd_in[301]
    DIRECTION INPUT ;
    USE SIGNAL ;
    SHAPE ABUTMENT ;
    PORT
      LAYER metal3 ;
      RECT 0.000 243.425 0.070 243.495 ;
    END
  END wd_in[301]
  PIN wd_in[302]
    DIRECTION INPUT ;
    USE SIGNAL ;
    SHAPE ABUTMENT ;
    PORT
      LAYER metal3 ;
      RECT 0.000 243.565 0.070 243.635 ;
    END
  END wd_in[302]
  PIN wd_in[303]
    DIRECTION INPUT ;
    USE SIGNAL ;
    SHAPE ABUTMENT ;
    PORT
      LAYER metal3 ;
      RECT 0.000 243.705 0.070 243.775 ;
    END
  END wd_in[303]
  PIN wd_in[304]
    DIRECTION INPUT ;
    USE SIGNAL ;
    SHAPE ABUTMENT ;
    PORT
      LAYER metal3 ;
      RECT 0.000 243.845 0.070 243.915 ;
    END
  END wd_in[304]
  PIN wd_in[305]
    DIRECTION INPUT ;
    USE SIGNAL ;
    SHAPE ABUTMENT ;
    PORT
      LAYER metal3 ;
      RECT 0.000 243.985 0.070 244.055 ;
    END
  END wd_in[305]
  PIN wd_in[306]
    DIRECTION INPUT ;
    USE SIGNAL ;
    SHAPE ABUTMENT ;
    PORT
      LAYER metal3 ;
      RECT 0.000 244.125 0.070 244.195 ;
    END
  END wd_in[306]
  PIN wd_in[307]
    DIRECTION INPUT ;
    USE SIGNAL ;
    SHAPE ABUTMENT ;
    PORT
      LAYER metal3 ;
      RECT 0.000 244.265 0.070 244.335 ;
    END
  END wd_in[307]
  PIN wd_in[308]
    DIRECTION INPUT ;
    USE SIGNAL ;
    SHAPE ABUTMENT ;
    PORT
      LAYER metal3 ;
      RECT 0.000 244.405 0.070 244.475 ;
    END
  END wd_in[308]
  PIN wd_in[309]
    DIRECTION INPUT ;
    USE SIGNAL ;
    SHAPE ABUTMENT ;
    PORT
      LAYER metal3 ;
      RECT 0.000 244.545 0.070 244.615 ;
    END
  END wd_in[309]
  PIN wd_in[310]
    DIRECTION INPUT ;
    USE SIGNAL ;
    SHAPE ABUTMENT ;
    PORT
      LAYER metal3 ;
      RECT 0.000 244.685 0.070 244.755 ;
    END
  END wd_in[310]
  PIN wd_in[311]
    DIRECTION INPUT ;
    USE SIGNAL ;
    SHAPE ABUTMENT ;
    PORT
      LAYER metal3 ;
      RECT 0.000 244.825 0.070 244.895 ;
    END
  END wd_in[311]
  PIN wd_in[312]
    DIRECTION INPUT ;
    USE SIGNAL ;
    SHAPE ABUTMENT ;
    PORT
      LAYER metal3 ;
      RECT 0.000 244.965 0.070 245.035 ;
    END
  END wd_in[312]
  PIN wd_in[313]
    DIRECTION INPUT ;
    USE SIGNAL ;
    SHAPE ABUTMENT ;
    PORT
      LAYER metal3 ;
      RECT 0.000 245.105 0.070 245.175 ;
    END
  END wd_in[313]
  PIN wd_in[314]
    DIRECTION INPUT ;
    USE SIGNAL ;
    SHAPE ABUTMENT ;
    PORT
      LAYER metal3 ;
      RECT 0.000 245.245 0.070 245.315 ;
    END
  END wd_in[314]
  PIN wd_in[315]
    DIRECTION INPUT ;
    USE SIGNAL ;
    SHAPE ABUTMENT ;
    PORT
      LAYER metal3 ;
      RECT 0.000 245.385 0.070 245.455 ;
    END
  END wd_in[315]
  PIN wd_in[316]
    DIRECTION INPUT ;
    USE SIGNAL ;
    SHAPE ABUTMENT ;
    PORT
      LAYER metal3 ;
      RECT 0.000 245.525 0.070 245.595 ;
    END
  END wd_in[316]
  PIN wd_in[317]
    DIRECTION INPUT ;
    USE SIGNAL ;
    SHAPE ABUTMENT ;
    PORT
      LAYER metal3 ;
      RECT 0.000 245.665 0.070 245.735 ;
    END
  END wd_in[317]
  PIN wd_in[318]
    DIRECTION INPUT ;
    USE SIGNAL ;
    SHAPE ABUTMENT ;
    PORT
      LAYER metal3 ;
      RECT 0.000 245.805 0.070 245.875 ;
    END
  END wd_in[318]
  PIN wd_in[319]
    DIRECTION INPUT ;
    USE SIGNAL ;
    SHAPE ABUTMENT ;
    PORT
      LAYER metal3 ;
      RECT 0.000 245.945 0.070 246.015 ;
    END
  END wd_in[319]
  PIN wd_in[320]
    DIRECTION INPUT ;
    USE SIGNAL ;
    SHAPE ABUTMENT ;
    PORT
      LAYER metal3 ;
      RECT 0.000 246.085 0.070 246.155 ;
    END
  END wd_in[320]
  PIN wd_in[321]
    DIRECTION INPUT ;
    USE SIGNAL ;
    SHAPE ABUTMENT ;
    PORT
      LAYER metal3 ;
      RECT 0.000 246.225 0.070 246.295 ;
    END
  END wd_in[321]
  PIN wd_in[322]
    DIRECTION INPUT ;
    USE SIGNAL ;
    SHAPE ABUTMENT ;
    PORT
      LAYER metal3 ;
      RECT 0.000 246.365 0.070 246.435 ;
    END
  END wd_in[322]
  PIN wd_in[323]
    DIRECTION INPUT ;
    USE SIGNAL ;
    SHAPE ABUTMENT ;
    PORT
      LAYER metal3 ;
      RECT 0.000 246.505 0.070 246.575 ;
    END
  END wd_in[323]
  PIN wd_in[324]
    DIRECTION INPUT ;
    USE SIGNAL ;
    SHAPE ABUTMENT ;
    PORT
      LAYER metal3 ;
      RECT 0.000 246.645 0.070 246.715 ;
    END
  END wd_in[324]
  PIN wd_in[325]
    DIRECTION INPUT ;
    USE SIGNAL ;
    SHAPE ABUTMENT ;
    PORT
      LAYER metal3 ;
      RECT 0.000 246.785 0.070 246.855 ;
    END
  END wd_in[325]
  PIN wd_in[326]
    DIRECTION INPUT ;
    USE SIGNAL ;
    SHAPE ABUTMENT ;
    PORT
      LAYER metal3 ;
      RECT 0.000 246.925 0.070 246.995 ;
    END
  END wd_in[326]
  PIN wd_in[327]
    DIRECTION INPUT ;
    USE SIGNAL ;
    SHAPE ABUTMENT ;
    PORT
      LAYER metal3 ;
      RECT 0.000 247.065 0.070 247.135 ;
    END
  END wd_in[327]
  PIN wd_in[328]
    DIRECTION INPUT ;
    USE SIGNAL ;
    SHAPE ABUTMENT ;
    PORT
      LAYER metal3 ;
      RECT 0.000 247.205 0.070 247.275 ;
    END
  END wd_in[328]
  PIN wd_in[329]
    DIRECTION INPUT ;
    USE SIGNAL ;
    SHAPE ABUTMENT ;
    PORT
      LAYER metal3 ;
      RECT 0.000 247.345 0.070 247.415 ;
    END
  END wd_in[329]
  PIN wd_in[330]
    DIRECTION INPUT ;
    USE SIGNAL ;
    SHAPE ABUTMENT ;
    PORT
      LAYER metal3 ;
      RECT 0.000 247.485 0.070 247.555 ;
    END
  END wd_in[330]
  PIN wd_in[331]
    DIRECTION INPUT ;
    USE SIGNAL ;
    SHAPE ABUTMENT ;
    PORT
      LAYER metal3 ;
      RECT 0.000 247.625 0.070 247.695 ;
    END
  END wd_in[331]
  PIN wd_in[332]
    DIRECTION INPUT ;
    USE SIGNAL ;
    SHAPE ABUTMENT ;
    PORT
      LAYER metal3 ;
      RECT 0.000 247.765 0.070 247.835 ;
    END
  END wd_in[332]
  PIN wd_in[333]
    DIRECTION INPUT ;
    USE SIGNAL ;
    SHAPE ABUTMENT ;
    PORT
      LAYER metal3 ;
      RECT 0.000 247.905 0.070 247.975 ;
    END
  END wd_in[333]
  PIN wd_in[334]
    DIRECTION INPUT ;
    USE SIGNAL ;
    SHAPE ABUTMENT ;
    PORT
      LAYER metal3 ;
      RECT 0.000 248.045 0.070 248.115 ;
    END
  END wd_in[334]
  PIN wd_in[335]
    DIRECTION INPUT ;
    USE SIGNAL ;
    SHAPE ABUTMENT ;
    PORT
      LAYER metal3 ;
      RECT 0.000 248.185 0.070 248.255 ;
    END
  END wd_in[335]
  PIN wd_in[336]
    DIRECTION INPUT ;
    USE SIGNAL ;
    SHAPE ABUTMENT ;
    PORT
      LAYER metal3 ;
      RECT 0.000 248.325 0.070 248.395 ;
    END
  END wd_in[336]
  PIN wd_in[337]
    DIRECTION INPUT ;
    USE SIGNAL ;
    SHAPE ABUTMENT ;
    PORT
      LAYER metal3 ;
      RECT 0.000 248.465 0.070 248.535 ;
    END
  END wd_in[337]
  PIN wd_in[338]
    DIRECTION INPUT ;
    USE SIGNAL ;
    SHAPE ABUTMENT ;
    PORT
      LAYER metal3 ;
      RECT 0.000 248.605 0.070 248.675 ;
    END
  END wd_in[338]
  PIN wd_in[339]
    DIRECTION INPUT ;
    USE SIGNAL ;
    SHAPE ABUTMENT ;
    PORT
      LAYER metal3 ;
      RECT 0.000 248.745 0.070 248.815 ;
    END
  END wd_in[339]
  PIN wd_in[340]
    DIRECTION INPUT ;
    USE SIGNAL ;
    SHAPE ABUTMENT ;
    PORT
      LAYER metal3 ;
      RECT 0.000 248.885 0.070 248.955 ;
    END
  END wd_in[340]
  PIN wd_in[341]
    DIRECTION INPUT ;
    USE SIGNAL ;
    SHAPE ABUTMENT ;
    PORT
      LAYER metal3 ;
      RECT 0.000 249.025 0.070 249.095 ;
    END
  END wd_in[341]
  PIN wd_in[342]
    DIRECTION INPUT ;
    USE SIGNAL ;
    SHAPE ABUTMENT ;
    PORT
      LAYER metal3 ;
      RECT 0.000 249.165 0.070 249.235 ;
    END
  END wd_in[342]
  PIN wd_in[343]
    DIRECTION INPUT ;
    USE SIGNAL ;
    SHAPE ABUTMENT ;
    PORT
      LAYER metal3 ;
      RECT 0.000 249.305 0.070 249.375 ;
    END
  END wd_in[343]
  PIN wd_in[344]
    DIRECTION INPUT ;
    USE SIGNAL ;
    SHAPE ABUTMENT ;
    PORT
      LAYER metal3 ;
      RECT 0.000 249.445 0.070 249.515 ;
    END
  END wd_in[344]
  PIN wd_in[345]
    DIRECTION INPUT ;
    USE SIGNAL ;
    SHAPE ABUTMENT ;
    PORT
      LAYER metal3 ;
      RECT 0.000 249.585 0.070 249.655 ;
    END
  END wd_in[345]
  PIN wd_in[346]
    DIRECTION INPUT ;
    USE SIGNAL ;
    SHAPE ABUTMENT ;
    PORT
      LAYER metal3 ;
      RECT 0.000 249.725 0.070 249.795 ;
    END
  END wd_in[346]
  PIN wd_in[347]
    DIRECTION INPUT ;
    USE SIGNAL ;
    SHAPE ABUTMENT ;
    PORT
      LAYER metal3 ;
      RECT 0.000 249.865 0.070 249.935 ;
    END
  END wd_in[347]
  PIN wd_in[348]
    DIRECTION INPUT ;
    USE SIGNAL ;
    SHAPE ABUTMENT ;
    PORT
      LAYER metal3 ;
      RECT 0.000 250.005 0.070 250.075 ;
    END
  END wd_in[348]
  PIN wd_in[349]
    DIRECTION INPUT ;
    USE SIGNAL ;
    SHAPE ABUTMENT ;
    PORT
      LAYER metal3 ;
      RECT 0.000 250.145 0.070 250.215 ;
    END
  END wd_in[349]
  PIN wd_in[350]
    DIRECTION INPUT ;
    USE SIGNAL ;
    SHAPE ABUTMENT ;
    PORT
      LAYER metal3 ;
      RECT 0.000 250.285 0.070 250.355 ;
    END
  END wd_in[350]
  PIN wd_in[351]
    DIRECTION INPUT ;
    USE SIGNAL ;
    SHAPE ABUTMENT ;
    PORT
      LAYER metal3 ;
      RECT 0.000 250.425 0.070 250.495 ;
    END
  END wd_in[351]
  PIN wd_in[352]
    DIRECTION INPUT ;
    USE SIGNAL ;
    SHAPE ABUTMENT ;
    PORT
      LAYER metal3 ;
      RECT 0.000 250.565 0.070 250.635 ;
    END
  END wd_in[352]
  PIN wd_in[353]
    DIRECTION INPUT ;
    USE SIGNAL ;
    SHAPE ABUTMENT ;
    PORT
      LAYER metal3 ;
      RECT 0.000 250.705 0.070 250.775 ;
    END
  END wd_in[353]
  PIN wd_in[354]
    DIRECTION INPUT ;
    USE SIGNAL ;
    SHAPE ABUTMENT ;
    PORT
      LAYER metal3 ;
      RECT 0.000 250.845 0.070 250.915 ;
    END
  END wd_in[354]
  PIN wd_in[355]
    DIRECTION INPUT ;
    USE SIGNAL ;
    SHAPE ABUTMENT ;
    PORT
      LAYER metal3 ;
      RECT 0.000 250.985 0.070 251.055 ;
    END
  END wd_in[355]
  PIN wd_in[356]
    DIRECTION INPUT ;
    USE SIGNAL ;
    SHAPE ABUTMENT ;
    PORT
      LAYER metal3 ;
      RECT 0.000 251.125 0.070 251.195 ;
    END
  END wd_in[356]
  PIN wd_in[357]
    DIRECTION INPUT ;
    USE SIGNAL ;
    SHAPE ABUTMENT ;
    PORT
      LAYER metal3 ;
      RECT 0.000 251.265 0.070 251.335 ;
    END
  END wd_in[357]
  PIN wd_in[358]
    DIRECTION INPUT ;
    USE SIGNAL ;
    SHAPE ABUTMENT ;
    PORT
      LAYER metal3 ;
      RECT 0.000 251.405 0.070 251.475 ;
    END
  END wd_in[358]
  PIN wd_in[359]
    DIRECTION INPUT ;
    USE SIGNAL ;
    SHAPE ABUTMENT ;
    PORT
      LAYER metal3 ;
      RECT 0.000 251.545 0.070 251.615 ;
    END
  END wd_in[359]
  PIN wd_in[360]
    DIRECTION INPUT ;
    USE SIGNAL ;
    SHAPE ABUTMENT ;
    PORT
      LAYER metal3 ;
      RECT 0.000 251.685 0.070 251.755 ;
    END
  END wd_in[360]
  PIN wd_in[361]
    DIRECTION INPUT ;
    USE SIGNAL ;
    SHAPE ABUTMENT ;
    PORT
      LAYER metal3 ;
      RECT 0.000 251.825 0.070 251.895 ;
    END
  END wd_in[361]
  PIN wd_in[362]
    DIRECTION INPUT ;
    USE SIGNAL ;
    SHAPE ABUTMENT ;
    PORT
      LAYER metal3 ;
      RECT 0.000 251.965 0.070 252.035 ;
    END
  END wd_in[362]
  PIN wd_in[363]
    DIRECTION INPUT ;
    USE SIGNAL ;
    SHAPE ABUTMENT ;
    PORT
      LAYER metal3 ;
      RECT 0.000 252.105 0.070 252.175 ;
    END
  END wd_in[363]
  PIN wd_in[364]
    DIRECTION INPUT ;
    USE SIGNAL ;
    SHAPE ABUTMENT ;
    PORT
      LAYER metal3 ;
      RECT 0.000 252.245 0.070 252.315 ;
    END
  END wd_in[364]
  PIN wd_in[365]
    DIRECTION INPUT ;
    USE SIGNAL ;
    SHAPE ABUTMENT ;
    PORT
      LAYER metal3 ;
      RECT 0.000 252.385 0.070 252.455 ;
    END
  END wd_in[365]
  PIN wd_in[366]
    DIRECTION INPUT ;
    USE SIGNAL ;
    SHAPE ABUTMENT ;
    PORT
      LAYER metal3 ;
      RECT 0.000 252.525 0.070 252.595 ;
    END
  END wd_in[366]
  PIN wd_in[367]
    DIRECTION INPUT ;
    USE SIGNAL ;
    SHAPE ABUTMENT ;
    PORT
      LAYER metal3 ;
      RECT 0.000 252.665 0.070 252.735 ;
    END
  END wd_in[367]
  PIN wd_in[368]
    DIRECTION INPUT ;
    USE SIGNAL ;
    SHAPE ABUTMENT ;
    PORT
      LAYER metal3 ;
      RECT 0.000 252.805 0.070 252.875 ;
    END
  END wd_in[368]
  PIN wd_in[369]
    DIRECTION INPUT ;
    USE SIGNAL ;
    SHAPE ABUTMENT ;
    PORT
      LAYER metal3 ;
      RECT 0.000 252.945 0.070 253.015 ;
    END
  END wd_in[369]
  PIN wd_in[370]
    DIRECTION INPUT ;
    USE SIGNAL ;
    SHAPE ABUTMENT ;
    PORT
      LAYER metal3 ;
      RECT 0.000 253.085 0.070 253.155 ;
    END
  END wd_in[370]
  PIN wd_in[371]
    DIRECTION INPUT ;
    USE SIGNAL ;
    SHAPE ABUTMENT ;
    PORT
      LAYER metal3 ;
      RECT 0.000 253.225 0.070 253.295 ;
    END
  END wd_in[371]
  PIN wd_in[372]
    DIRECTION INPUT ;
    USE SIGNAL ;
    SHAPE ABUTMENT ;
    PORT
      LAYER metal3 ;
      RECT 0.000 253.365 0.070 253.435 ;
    END
  END wd_in[372]
  PIN wd_in[373]
    DIRECTION INPUT ;
    USE SIGNAL ;
    SHAPE ABUTMENT ;
    PORT
      LAYER metal3 ;
      RECT 0.000 253.505 0.070 253.575 ;
    END
  END wd_in[373]
  PIN wd_in[374]
    DIRECTION INPUT ;
    USE SIGNAL ;
    SHAPE ABUTMENT ;
    PORT
      LAYER metal3 ;
      RECT 0.000 253.645 0.070 253.715 ;
    END
  END wd_in[374]
  PIN wd_in[375]
    DIRECTION INPUT ;
    USE SIGNAL ;
    SHAPE ABUTMENT ;
    PORT
      LAYER metal3 ;
      RECT 0.000 253.785 0.070 253.855 ;
    END
  END wd_in[375]
  PIN wd_in[376]
    DIRECTION INPUT ;
    USE SIGNAL ;
    SHAPE ABUTMENT ;
    PORT
      LAYER metal3 ;
      RECT 0.000 253.925 0.070 253.995 ;
    END
  END wd_in[376]
  PIN wd_in[377]
    DIRECTION INPUT ;
    USE SIGNAL ;
    SHAPE ABUTMENT ;
    PORT
      LAYER metal3 ;
      RECT 0.000 254.065 0.070 254.135 ;
    END
  END wd_in[377]
  PIN wd_in[378]
    DIRECTION INPUT ;
    USE SIGNAL ;
    SHAPE ABUTMENT ;
    PORT
      LAYER metal3 ;
      RECT 0.000 254.205 0.070 254.275 ;
    END
  END wd_in[378]
  PIN wd_in[379]
    DIRECTION INPUT ;
    USE SIGNAL ;
    SHAPE ABUTMENT ;
    PORT
      LAYER metal3 ;
      RECT 0.000 254.345 0.070 254.415 ;
    END
  END wd_in[379]
  PIN wd_in[380]
    DIRECTION INPUT ;
    USE SIGNAL ;
    SHAPE ABUTMENT ;
    PORT
      LAYER metal3 ;
      RECT 0.000 254.485 0.070 254.555 ;
    END
  END wd_in[380]
  PIN wd_in[381]
    DIRECTION INPUT ;
    USE SIGNAL ;
    SHAPE ABUTMENT ;
    PORT
      LAYER metal3 ;
      RECT 0.000 254.625 0.070 254.695 ;
    END
  END wd_in[381]
  PIN wd_in[382]
    DIRECTION INPUT ;
    USE SIGNAL ;
    SHAPE ABUTMENT ;
    PORT
      LAYER metal3 ;
      RECT 0.000 254.765 0.070 254.835 ;
    END
  END wd_in[382]
  PIN wd_in[383]
    DIRECTION INPUT ;
    USE SIGNAL ;
    SHAPE ABUTMENT ;
    PORT
      LAYER metal3 ;
      RECT 0.000 254.905 0.070 254.975 ;
    END
  END wd_in[383]
  PIN wd_in[384]
    DIRECTION INPUT ;
    USE SIGNAL ;
    SHAPE ABUTMENT ;
    PORT
      LAYER metal3 ;
      RECT 0.000 255.045 0.070 255.115 ;
    END
  END wd_in[384]
  PIN wd_in[385]
    DIRECTION INPUT ;
    USE SIGNAL ;
    SHAPE ABUTMENT ;
    PORT
      LAYER metal3 ;
      RECT 0.000 255.185 0.070 255.255 ;
    END
  END wd_in[385]
  PIN wd_in[386]
    DIRECTION INPUT ;
    USE SIGNAL ;
    SHAPE ABUTMENT ;
    PORT
      LAYER metal3 ;
      RECT 0.000 255.325 0.070 255.395 ;
    END
  END wd_in[386]
  PIN wd_in[387]
    DIRECTION INPUT ;
    USE SIGNAL ;
    SHAPE ABUTMENT ;
    PORT
      LAYER metal3 ;
      RECT 0.000 255.465 0.070 255.535 ;
    END
  END wd_in[387]
  PIN wd_in[388]
    DIRECTION INPUT ;
    USE SIGNAL ;
    SHAPE ABUTMENT ;
    PORT
      LAYER metal3 ;
      RECT 0.000 255.605 0.070 255.675 ;
    END
  END wd_in[388]
  PIN wd_in[389]
    DIRECTION INPUT ;
    USE SIGNAL ;
    SHAPE ABUTMENT ;
    PORT
      LAYER metal3 ;
      RECT 0.000 255.745 0.070 255.815 ;
    END
  END wd_in[389]
  PIN wd_in[390]
    DIRECTION INPUT ;
    USE SIGNAL ;
    SHAPE ABUTMENT ;
    PORT
      LAYER metal3 ;
      RECT 0.000 255.885 0.070 255.955 ;
    END
  END wd_in[390]
  PIN wd_in[391]
    DIRECTION INPUT ;
    USE SIGNAL ;
    SHAPE ABUTMENT ;
    PORT
      LAYER metal3 ;
      RECT 0.000 256.025 0.070 256.095 ;
    END
  END wd_in[391]
  PIN wd_in[392]
    DIRECTION INPUT ;
    USE SIGNAL ;
    SHAPE ABUTMENT ;
    PORT
      LAYER metal3 ;
      RECT 0.000 256.165 0.070 256.235 ;
    END
  END wd_in[392]
  PIN wd_in[393]
    DIRECTION INPUT ;
    USE SIGNAL ;
    SHAPE ABUTMENT ;
    PORT
      LAYER metal3 ;
      RECT 0.000 256.305 0.070 256.375 ;
    END
  END wd_in[393]
  PIN wd_in[394]
    DIRECTION INPUT ;
    USE SIGNAL ;
    SHAPE ABUTMENT ;
    PORT
      LAYER metal3 ;
      RECT 0.000 256.445 0.070 256.515 ;
    END
  END wd_in[394]
  PIN wd_in[395]
    DIRECTION INPUT ;
    USE SIGNAL ;
    SHAPE ABUTMENT ;
    PORT
      LAYER metal3 ;
      RECT 0.000 256.585 0.070 256.655 ;
    END
  END wd_in[395]
  PIN wd_in[396]
    DIRECTION INPUT ;
    USE SIGNAL ;
    SHAPE ABUTMENT ;
    PORT
      LAYER metal3 ;
      RECT 0.000 256.725 0.070 256.795 ;
    END
  END wd_in[396]
  PIN wd_in[397]
    DIRECTION INPUT ;
    USE SIGNAL ;
    SHAPE ABUTMENT ;
    PORT
      LAYER metal3 ;
      RECT 0.000 256.865 0.070 256.935 ;
    END
  END wd_in[397]
  PIN wd_in[398]
    DIRECTION INPUT ;
    USE SIGNAL ;
    SHAPE ABUTMENT ;
    PORT
      LAYER metal3 ;
      RECT 0.000 257.005 0.070 257.075 ;
    END
  END wd_in[398]
  PIN wd_in[399]
    DIRECTION INPUT ;
    USE SIGNAL ;
    SHAPE ABUTMENT ;
    PORT
      LAYER metal3 ;
      RECT 0.000 257.145 0.070 257.215 ;
    END
  END wd_in[399]
  PIN wd_in[400]
    DIRECTION INPUT ;
    USE SIGNAL ;
    SHAPE ABUTMENT ;
    PORT
      LAYER metal3 ;
      RECT 0.000 257.285 0.070 257.355 ;
    END
  END wd_in[400]
  PIN wd_in[401]
    DIRECTION INPUT ;
    USE SIGNAL ;
    SHAPE ABUTMENT ;
    PORT
      LAYER metal3 ;
      RECT 0.000 257.425 0.070 257.495 ;
    END
  END wd_in[401]
  PIN wd_in[402]
    DIRECTION INPUT ;
    USE SIGNAL ;
    SHAPE ABUTMENT ;
    PORT
      LAYER metal3 ;
      RECT 0.000 257.565 0.070 257.635 ;
    END
  END wd_in[402]
  PIN wd_in[403]
    DIRECTION INPUT ;
    USE SIGNAL ;
    SHAPE ABUTMENT ;
    PORT
      LAYER metal3 ;
      RECT 0.000 257.705 0.070 257.775 ;
    END
  END wd_in[403]
  PIN wd_in[404]
    DIRECTION INPUT ;
    USE SIGNAL ;
    SHAPE ABUTMENT ;
    PORT
      LAYER metal3 ;
      RECT 0.000 257.845 0.070 257.915 ;
    END
  END wd_in[404]
  PIN wd_in[405]
    DIRECTION INPUT ;
    USE SIGNAL ;
    SHAPE ABUTMENT ;
    PORT
      LAYER metal3 ;
      RECT 0.000 257.985 0.070 258.055 ;
    END
  END wd_in[405]
  PIN wd_in[406]
    DIRECTION INPUT ;
    USE SIGNAL ;
    SHAPE ABUTMENT ;
    PORT
      LAYER metal3 ;
      RECT 0.000 258.125 0.070 258.195 ;
    END
  END wd_in[406]
  PIN wd_in[407]
    DIRECTION INPUT ;
    USE SIGNAL ;
    SHAPE ABUTMENT ;
    PORT
      LAYER metal3 ;
      RECT 0.000 258.265 0.070 258.335 ;
    END
  END wd_in[407]
  PIN wd_in[408]
    DIRECTION INPUT ;
    USE SIGNAL ;
    SHAPE ABUTMENT ;
    PORT
      LAYER metal3 ;
      RECT 0.000 258.405 0.070 258.475 ;
    END
  END wd_in[408]
  PIN wd_in[409]
    DIRECTION INPUT ;
    USE SIGNAL ;
    SHAPE ABUTMENT ;
    PORT
      LAYER metal3 ;
      RECT 0.000 258.545 0.070 258.615 ;
    END
  END wd_in[409]
  PIN wd_in[410]
    DIRECTION INPUT ;
    USE SIGNAL ;
    SHAPE ABUTMENT ;
    PORT
      LAYER metal3 ;
      RECT 0.000 258.685 0.070 258.755 ;
    END
  END wd_in[410]
  PIN wd_in[411]
    DIRECTION INPUT ;
    USE SIGNAL ;
    SHAPE ABUTMENT ;
    PORT
      LAYER metal3 ;
      RECT 0.000 258.825 0.070 258.895 ;
    END
  END wd_in[411]
  PIN wd_in[412]
    DIRECTION INPUT ;
    USE SIGNAL ;
    SHAPE ABUTMENT ;
    PORT
      LAYER metal3 ;
      RECT 0.000 258.965 0.070 259.035 ;
    END
  END wd_in[412]
  PIN wd_in[413]
    DIRECTION INPUT ;
    USE SIGNAL ;
    SHAPE ABUTMENT ;
    PORT
      LAYER metal3 ;
      RECT 0.000 259.105 0.070 259.175 ;
    END
  END wd_in[413]
  PIN wd_in[414]
    DIRECTION INPUT ;
    USE SIGNAL ;
    SHAPE ABUTMENT ;
    PORT
      LAYER metal3 ;
      RECT 0.000 259.245 0.070 259.315 ;
    END
  END wd_in[414]
  PIN wd_in[415]
    DIRECTION INPUT ;
    USE SIGNAL ;
    SHAPE ABUTMENT ;
    PORT
      LAYER metal3 ;
      RECT 0.000 259.385 0.070 259.455 ;
    END
  END wd_in[415]
  PIN wd_in[416]
    DIRECTION INPUT ;
    USE SIGNAL ;
    SHAPE ABUTMENT ;
    PORT
      LAYER metal3 ;
      RECT 0.000 259.525 0.070 259.595 ;
    END
  END wd_in[416]
  PIN wd_in[417]
    DIRECTION INPUT ;
    USE SIGNAL ;
    SHAPE ABUTMENT ;
    PORT
      LAYER metal3 ;
      RECT 0.000 259.665 0.070 259.735 ;
    END
  END wd_in[417]
  PIN wd_in[418]
    DIRECTION INPUT ;
    USE SIGNAL ;
    SHAPE ABUTMENT ;
    PORT
      LAYER metal3 ;
      RECT 0.000 259.805 0.070 259.875 ;
    END
  END wd_in[418]
  PIN wd_in[419]
    DIRECTION INPUT ;
    USE SIGNAL ;
    SHAPE ABUTMENT ;
    PORT
      LAYER metal3 ;
      RECT 0.000 259.945 0.070 260.015 ;
    END
  END wd_in[419]
  PIN wd_in[420]
    DIRECTION INPUT ;
    USE SIGNAL ;
    SHAPE ABUTMENT ;
    PORT
      LAYER metal3 ;
      RECT 0.000 260.085 0.070 260.155 ;
    END
  END wd_in[420]
  PIN wd_in[421]
    DIRECTION INPUT ;
    USE SIGNAL ;
    SHAPE ABUTMENT ;
    PORT
      LAYER metal3 ;
      RECT 0.000 260.225 0.070 260.295 ;
    END
  END wd_in[421]
  PIN wd_in[422]
    DIRECTION INPUT ;
    USE SIGNAL ;
    SHAPE ABUTMENT ;
    PORT
      LAYER metal3 ;
      RECT 0.000 260.365 0.070 260.435 ;
    END
  END wd_in[422]
  PIN wd_in[423]
    DIRECTION INPUT ;
    USE SIGNAL ;
    SHAPE ABUTMENT ;
    PORT
      LAYER metal3 ;
      RECT 0.000 260.505 0.070 260.575 ;
    END
  END wd_in[423]
  PIN wd_in[424]
    DIRECTION INPUT ;
    USE SIGNAL ;
    SHAPE ABUTMENT ;
    PORT
      LAYER metal3 ;
      RECT 0.000 260.645 0.070 260.715 ;
    END
  END wd_in[424]
  PIN wd_in[425]
    DIRECTION INPUT ;
    USE SIGNAL ;
    SHAPE ABUTMENT ;
    PORT
      LAYER metal3 ;
      RECT 0.000 260.785 0.070 260.855 ;
    END
  END wd_in[425]
  PIN wd_in[426]
    DIRECTION INPUT ;
    USE SIGNAL ;
    SHAPE ABUTMENT ;
    PORT
      LAYER metal3 ;
      RECT 0.000 260.925 0.070 260.995 ;
    END
  END wd_in[426]
  PIN wd_in[427]
    DIRECTION INPUT ;
    USE SIGNAL ;
    SHAPE ABUTMENT ;
    PORT
      LAYER metal3 ;
      RECT 0.000 261.065 0.070 261.135 ;
    END
  END wd_in[427]
  PIN wd_in[428]
    DIRECTION INPUT ;
    USE SIGNAL ;
    SHAPE ABUTMENT ;
    PORT
      LAYER metal3 ;
      RECT 0.000 261.205 0.070 261.275 ;
    END
  END wd_in[428]
  PIN wd_in[429]
    DIRECTION INPUT ;
    USE SIGNAL ;
    SHAPE ABUTMENT ;
    PORT
      LAYER metal3 ;
      RECT 0.000 261.345 0.070 261.415 ;
    END
  END wd_in[429]
  PIN wd_in[430]
    DIRECTION INPUT ;
    USE SIGNAL ;
    SHAPE ABUTMENT ;
    PORT
      LAYER metal3 ;
      RECT 0.000 261.485 0.070 261.555 ;
    END
  END wd_in[430]
  PIN wd_in[431]
    DIRECTION INPUT ;
    USE SIGNAL ;
    SHAPE ABUTMENT ;
    PORT
      LAYER metal3 ;
      RECT 0.000 261.625 0.070 261.695 ;
    END
  END wd_in[431]
  PIN wd_in[432]
    DIRECTION INPUT ;
    USE SIGNAL ;
    SHAPE ABUTMENT ;
    PORT
      LAYER metal3 ;
      RECT 0.000 261.765 0.070 261.835 ;
    END
  END wd_in[432]
  PIN wd_in[433]
    DIRECTION INPUT ;
    USE SIGNAL ;
    SHAPE ABUTMENT ;
    PORT
      LAYER metal3 ;
      RECT 0.000 261.905 0.070 261.975 ;
    END
  END wd_in[433]
  PIN wd_in[434]
    DIRECTION INPUT ;
    USE SIGNAL ;
    SHAPE ABUTMENT ;
    PORT
      LAYER metal3 ;
      RECT 0.000 262.045 0.070 262.115 ;
    END
  END wd_in[434]
  PIN wd_in[435]
    DIRECTION INPUT ;
    USE SIGNAL ;
    SHAPE ABUTMENT ;
    PORT
      LAYER metal3 ;
      RECT 0.000 262.185 0.070 262.255 ;
    END
  END wd_in[435]
  PIN wd_in[436]
    DIRECTION INPUT ;
    USE SIGNAL ;
    SHAPE ABUTMENT ;
    PORT
      LAYER metal3 ;
      RECT 0.000 262.325 0.070 262.395 ;
    END
  END wd_in[436]
  PIN wd_in[437]
    DIRECTION INPUT ;
    USE SIGNAL ;
    SHAPE ABUTMENT ;
    PORT
      LAYER metal3 ;
      RECT 0.000 262.465 0.070 262.535 ;
    END
  END wd_in[437]
  PIN wd_in[438]
    DIRECTION INPUT ;
    USE SIGNAL ;
    SHAPE ABUTMENT ;
    PORT
      LAYER metal3 ;
      RECT 0.000 262.605 0.070 262.675 ;
    END
  END wd_in[438]
  PIN wd_in[439]
    DIRECTION INPUT ;
    USE SIGNAL ;
    SHAPE ABUTMENT ;
    PORT
      LAYER metal3 ;
      RECT 0.000 262.745 0.070 262.815 ;
    END
  END wd_in[439]
  PIN wd_in[440]
    DIRECTION INPUT ;
    USE SIGNAL ;
    SHAPE ABUTMENT ;
    PORT
      LAYER metal3 ;
      RECT 0.000 262.885 0.070 262.955 ;
    END
  END wd_in[440]
  PIN wd_in[441]
    DIRECTION INPUT ;
    USE SIGNAL ;
    SHAPE ABUTMENT ;
    PORT
      LAYER metal3 ;
      RECT 0.000 263.025 0.070 263.095 ;
    END
  END wd_in[441]
  PIN wd_in[442]
    DIRECTION INPUT ;
    USE SIGNAL ;
    SHAPE ABUTMENT ;
    PORT
      LAYER metal3 ;
      RECT 0.000 263.165 0.070 263.235 ;
    END
  END wd_in[442]
  PIN wd_in[443]
    DIRECTION INPUT ;
    USE SIGNAL ;
    SHAPE ABUTMENT ;
    PORT
      LAYER metal3 ;
      RECT 0.000 263.305 0.070 263.375 ;
    END
  END wd_in[443]
  PIN wd_in[444]
    DIRECTION INPUT ;
    USE SIGNAL ;
    SHAPE ABUTMENT ;
    PORT
      LAYER metal3 ;
      RECT 0.000 263.445 0.070 263.515 ;
    END
  END wd_in[444]
  PIN wd_in[445]
    DIRECTION INPUT ;
    USE SIGNAL ;
    SHAPE ABUTMENT ;
    PORT
      LAYER metal3 ;
      RECT 0.000 263.585 0.070 263.655 ;
    END
  END wd_in[445]
  PIN wd_in[446]
    DIRECTION INPUT ;
    USE SIGNAL ;
    SHAPE ABUTMENT ;
    PORT
      LAYER metal3 ;
      RECT 0.000 263.725 0.070 263.795 ;
    END
  END wd_in[446]
  PIN wd_in[447]
    DIRECTION INPUT ;
    USE SIGNAL ;
    SHAPE ABUTMENT ;
    PORT
      LAYER metal3 ;
      RECT 0.000 263.865 0.070 263.935 ;
    END
  END wd_in[447]
  PIN wd_in[448]
    DIRECTION INPUT ;
    USE SIGNAL ;
    SHAPE ABUTMENT ;
    PORT
      LAYER metal3 ;
      RECT 0.000 264.005 0.070 264.075 ;
    END
  END wd_in[448]
  PIN wd_in[449]
    DIRECTION INPUT ;
    USE SIGNAL ;
    SHAPE ABUTMENT ;
    PORT
      LAYER metal3 ;
      RECT 0.000 264.145 0.070 264.215 ;
    END
  END wd_in[449]
  PIN wd_in[450]
    DIRECTION INPUT ;
    USE SIGNAL ;
    SHAPE ABUTMENT ;
    PORT
      LAYER metal3 ;
      RECT 0.000 264.285 0.070 264.355 ;
    END
  END wd_in[450]
  PIN wd_in[451]
    DIRECTION INPUT ;
    USE SIGNAL ;
    SHAPE ABUTMENT ;
    PORT
      LAYER metal3 ;
      RECT 0.000 264.425 0.070 264.495 ;
    END
  END wd_in[451]
  PIN wd_in[452]
    DIRECTION INPUT ;
    USE SIGNAL ;
    SHAPE ABUTMENT ;
    PORT
      LAYER metal3 ;
      RECT 0.000 264.565 0.070 264.635 ;
    END
  END wd_in[452]
  PIN wd_in[453]
    DIRECTION INPUT ;
    USE SIGNAL ;
    SHAPE ABUTMENT ;
    PORT
      LAYER metal3 ;
      RECT 0.000 264.705 0.070 264.775 ;
    END
  END wd_in[453]
  PIN wd_in[454]
    DIRECTION INPUT ;
    USE SIGNAL ;
    SHAPE ABUTMENT ;
    PORT
      LAYER metal3 ;
      RECT 0.000 264.845 0.070 264.915 ;
    END
  END wd_in[454]
  PIN wd_in[455]
    DIRECTION INPUT ;
    USE SIGNAL ;
    SHAPE ABUTMENT ;
    PORT
      LAYER metal3 ;
      RECT 0.000 264.985 0.070 265.055 ;
    END
  END wd_in[455]
  PIN wd_in[456]
    DIRECTION INPUT ;
    USE SIGNAL ;
    SHAPE ABUTMENT ;
    PORT
      LAYER metal3 ;
      RECT 0.000 265.125 0.070 265.195 ;
    END
  END wd_in[456]
  PIN wd_in[457]
    DIRECTION INPUT ;
    USE SIGNAL ;
    SHAPE ABUTMENT ;
    PORT
      LAYER metal3 ;
      RECT 0.000 265.265 0.070 265.335 ;
    END
  END wd_in[457]
  PIN wd_in[458]
    DIRECTION INPUT ;
    USE SIGNAL ;
    SHAPE ABUTMENT ;
    PORT
      LAYER metal3 ;
      RECT 0.000 265.405 0.070 265.475 ;
    END
  END wd_in[458]
  PIN wd_in[459]
    DIRECTION INPUT ;
    USE SIGNAL ;
    SHAPE ABUTMENT ;
    PORT
      LAYER metal3 ;
      RECT 0.000 265.545 0.070 265.615 ;
    END
  END wd_in[459]
  PIN wd_in[460]
    DIRECTION INPUT ;
    USE SIGNAL ;
    SHAPE ABUTMENT ;
    PORT
      LAYER metal3 ;
      RECT 0.000 265.685 0.070 265.755 ;
    END
  END wd_in[460]
  PIN wd_in[461]
    DIRECTION INPUT ;
    USE SIGNAL ;
    SHAPE ABUTMENT ;
    PORT
      LAYER metal3 ;
      RECT 0.000 265.825 0.070 265.895 ;
    END
  END wd_in[461]
  PIN wd_in[462]
    DIRECTION INPUT ;
    USE SIGNAL ;
    SHAPE ABUTMENT ;
    PORT
      LAYER metal3 ;
      RECT 0.000 265.965 0.070 266.035 ;
    END
  END wd_in[462]
  PIN wd_in[463]
    DIRECTION INPUT ;
    USE SIGNAL ;
    SHAPE ABUTMENT ;
    PORT
      LAYER metal3 ;
      RECT 0.000 266.105 0.070 266.175 ;
    END
  END wd_in[463]
  PIN wd_in[464]
    DIRECTION INPUT ;
    USE SIGNAL ;
    SHAPE ABUTMENT ;
    PORT
      LAYER metal3 ;
      RECT 0.000 266.245 0.070 266.315 ;
    END
  END wd_in[464]
  PIN wd_in[465]
    DIRECTION INPUT ;
    USE SIGNAL ;
    SHAPE ABUTMENT ;
    PORT
      LAYER metal3 ;
      RECT 0.000 266.385 0.070 266.455 ;
    END
  END wd_in[465]
  PIN wd_in[466]
    DIRECTION INPUT ;
    USE SIGNAL ;
    SHAPE ABUTMENT ;
    PORT
      LAYER metal3 ;
      RECT 0.000 266.525 0.070 266.595 ;
    END
  END wd_in[466]
  PIN wd_in[467]
    DIRECTION INPUT ;
    USE SIGNAL ;
    SHAPE ABUTMENT ;
    PORT
      LAYER metal3 ;
      RECT 0.000 266.665 0.070 266.735 ;
    END
  END wd_in[467]
  PIN wd_in[468]
    DIRECTION INPUT ;
    USE SIGNAL ;
    SHAPE ABUTMENT ;
    PORT
      LAYER metal3 ;
      RECT 0.000 266.805 0.070 266.875 ;
    END
  END wd_in[468]
  PIN wd_in[469]
    DIRECTION INPUT ;
    USE SIGNAL ;
    SHAPE ABUTMENT ;
    PORT
      LAYER metal3 ;
      RECT 0.000 266.945 0.070 267.015 ;
    END
  END wd_in[469]
  PIN wd_in[470]
    DIRECTION INPUT ;
    USE SIGNAL ;
    SHAPE ABUTMENT ;
    PORT
      LAYER metal3 ;
      RECT 0.000 267.085 0.070 267.155 ;
    END
  END wd_in[470]
  PIN wd_in[471]
    DIRECTION INPUT ;
    USE SIGNAL ;
    SHAPE ABUTMENT ;
    PORT
      LAYER metal3 ;
      RECT 0.000 267.225 0.070 267.295 ;
    END
  END wd_in[471]
  PIN wd_in[472]
    DIRECTION INPUT ;
    USE SIGNAL ;
    SHAPE ABUTMENT ;
    PORT
      LAYER metal3 ;
      RECT 0.000 267.365 0.070 267.435 ;
    END
  END wd_in[472]
  PIN wd_in[473]
    DIRECTION INPUT ;
    USE SIGNAL ;
    SHAPE ABUTMENT ;
    PORT
      LAYER metal3 ;
      RECT 0.000 267.505 0.070 267.575 ;
    END
  END wd_in[473]
  PIN wd_in[474]
    DIRECTION INPUT ;
    USE SIGNAL ;
    SHAPE ABUTMENT ;
    PORT
      LAYER metal3 ;
      RECT 0.000 267.645 0.070 267.715 ;
    END
  END wd_in[474]
  PIN wd_in[475]
    DIRECTION INPUT ;
    USE SIGNAL ;
    SHAPE ABUTMENT ;
    PORT
      LAYER metal3 ;
      RECT 0.000 267.785 0.070 267.855 ;
    END
  END wd_in[475]
  PIN wd_in[476]
    DIRECTION INPUT ;
    USE SIGNAL ;
    SHAPE ABUTMENT ;
    PORT
      LAYER metal3 ;
      RECT 0.000 267.925 0.070 267.995 ;
    END
  END wd_in[476]
  PIN wd_in[477]
    DIRECTION INPUT ;
    USE SIGNAL ;
    SHAPE ABUTMENT ;
    PORT
      LAYER metal3 ;
      RECT 0.000 268.065 0.070 268.135 ;
    END
  END wd_in[477]
  PIN wd_in[478]
    DIRECTION INPUT ;
    USE SIGNAL ;
    SHAPE ABUTMENT ;
    PORT
      LAYER metal3 ;
      RECT 0.000 268.205 0.070 268.275 ;
    END
  END wd_in[478]
  PIN wd_in[479]
    DIRECTION INPUT ;
    USE SIGNAL ;
    SHAPE ABUTMENT ;
    PORT
      LAYER metal3 ;
      RECT 0.000 268.345 0.070 268.415 ;
    END
  END wd_in[479]
  PIN wd_in[480]
    DIRECTION INPUT ;
    USE SIGNAL ;
    SHAPE ABUTMENT ;
    PORT
      LAYER metal3 ;
      RECT 0.000 268.485 0.070 268.555 ;
    END
  END wd_in[480]
  PIN wd_in[481]
    DIRECTION INPUT ;
    USE SIGNAL ;
    SHAPE ABUTMENT ;
    PORT
      LAYER metal3 ;
      RECT 0.000 268.625 0.070 268.695 ;
    END
  END wd_in[481]
  PIN wd_in[482]
    DIRECTION INPUT ;
    USE SIGNAL ;
    SHAPE ABUTMENT ;
    PORT
      LAYER metal3 ;
      RECT 0.000 268.765 0.070 268.835 ;
    END
  END wd_in[482]
  PIN wd_in[483]
    DIRECTION INPUT ;
    USE SIGNAL ;
    SHAPE ABUTMENT ;
    PORT
      LAYER metal3 ;
      RECT 0.000 268.905 0.070 268.975 ;
    END
  END wd_in[483]
  PIN wd_in[484]
    DIRECTION INPUT ;
    USE SIGNAL ;
    SHAPE ABUTMENT ;
    PORT
      LAYER metal3 ;
      RECT 0.000 269.045 0.070 269.115 ;
    END
  END wd_in[484]
  PIN wd_in[485]
    DIRECTION INPUT ;
    USE SIGNAL ;
    SHAPE ABUTMENT ;
    PORT
      LAYER metal3 ;
      RECT 0.000 269.185 0.070 269.255 ;
    END
  END wd_in[485]
  PIN wd_in[486]
    DIRECTION INPUT ;
    USE SIGNAL ;
    SHAPE ABUTMENT ;
    PORT
      LAYER metal3 ;
      RECT 0.000 269.325 0.070 269.395 ;
    END
  END wd_in[486]
  PIN wd_in[487]
    DIRECTION INPUT ;
    USE SIGNAL ;
    SHAPE ABUTMENT ;
    PORT
      LAYER metal3 ;
      RECT 0.000 269.465 0.070 269.535 ;
    END
  END wd_in[487]
  PIN wd_in[488]
    DIRECTION INPUT ;
    USE SIGNAL ;
    SHAPE ABUTMENT ;
    PORT
      LAYER metal3 ;
      RECT 0.000 269.605 0.070 269.675 ;
    END
  END wd_in[488]
  PIN wd_in[489]
    DIRECTION INPUT ;
    USE SIGNAL ;
    SHAPE ABUTMENT ;
    PORT
      LAYER metal3 ;
      RECT 0.000 269.745 0.070 269.815 ;
    END
  END wd_in[489]
  PIN wd_in[490]
    DIRECTION INPUT ;
    USE SIGNAL ;
    SHAPE ABUTMENT ;
    PORT
      LAYER metal3 ;
      RECT 0.000 269.885 0.070 269.955 ;
    END
  END wd_in[490]
  PIN wd_in[491]
    DIRECTION INPUT ;
    USE SIGNAL ;
    SHAPE ABUTMENT ;
    PORT
      LAYER metal3 ;
      RECT 0.000 270.025 0.070 270.095 ;
    END
  END wd_in[491]
  PIN wd_in[492]
    DIRECTION INPUT ;
    USE SIGNAL ;
    SHAPE ABUTMENT ;
    PORT
      LAYER metal3 ;
      RECT 0.000 270.165 0.070 270.235 ;
    END
  END wd_in[492]
  PIN wd_in[493]
    DIRECTION INPUT ;
    USE SIGNAL ;
    SHAPE ABUTMENT ;
    PORT
      LAYER metal3 ;
      RECT 0.000 270.305 0.070 270.375 ;
    END
  END wd_in[493]
  PIN wd_in[494]
    DIRECTION INPUT ;
    USE SIGNAL ;
    SHAPE ABUTMENT ;
    PORT
      LAYER metal3 ;
      RECT 0.000 270.445 0.070 270.515 ;
    END
  END wd_in[494]
  PIN wd_in[495]
    DIRECTION INPUT ;
    USE SIGNAL ;
    SHAPE ABUTMENT ;
    PORT
      LAYER metal3 ;
      RECT 0.000 270.585 0.070 270.655 ;
    END
  END wd_in[495]
  PIN wd_in[496]
    DIRECTION INPUT ;
    USE SIGNAL ;
    SHAPE ABUTMENT ;
    PORT
      LAYER metal3 ;
      RECT 0.000 270.725 0.070 270.795 ;
    END
  END wd_in[496]
  PIN wd_in[497]
    DIRECTION INPUT ;
    USE SIGNAL ;
    SHAPE ABUTMENT ;
    PORT
      LAYER metal3 ;
      RECT 0.000 270.865 0.070 270.935 ;
    END
  END wd_in[497]
  PIN wd_in[498]
    DIRECTION INPUT ;
    USE SIGNAL ;
    SHAPE ABUTMENT ;
    PORT
      LAYER metal3 ;
      RECT 0.000 271.005 0.070 271.075 ;
    END
  END wd_in[498]
  PIN wd_in[499]
    DIRECTION INPUT ;
    USE SIGNAL ;
    SHAPE ABUTMENT ;
    PORT
      LAYER metal3 ;
      RECT 0.000 271.145 0.070 271.215 ;
    END
  END wd_in[499]
  PIN wd_in[500]
    DIRECTION INPUT ;
    USE SIGNAL ;
    SHAPE ABUTMENT ;
    PORT
      LAYER metal3 ;
      RECT 0.000 271.285 0.070 271.355 ;
    END
  END wd_in[500]
  PIN wd_in[501]
    DIRECTION INPUT ;
    USE SIGNAL ;
    SHAPE ABUTMENT ;
    PORT
      LAYER metal3 ;
      RECT 0.000 271.425 0.070 271.495 ;
    END
  END wd_in[501]
  PIN wd_in[502]
    DIRECTION INPUT ;
    USE SIGNAL ;
    SHAPE ABUTMENT ;
    PORT
      LAYER metal3 ;
      RECT 0.000 271.565 0.070 271.635 ;
    END
  END wd_in[502]
  PIN wd_in[503]
    DIRECTION INPUT ;
    USE SIGNAL ;
    SHAPE ABUTMENT ;
    PORT
      LAYER metal3 ;
      RECT 0.000 271.705 0.070 271.775 ;
    END
  END wd_in[503]
  PIN wd_in[504]
    DIRECTION INPUT ;
    USE SIGNAL ;
    SHAPE ABUTMENT ;
    PORT
      LAYER metal3 ;
      RECT 0.000 271.845 0.070 271.915 ;
    END
  END wd_in[504]
  PIN wd_in[505]
    DIRECTION INPUT ;
    USE SIGNAL ;
    SHAPE ABUTMENT ;
    PORT
      LAYER metal3 ;
      RECT 0.000 271.985 0.070 272.055 ;
    END
  END wd_in[505]
  PIN wd_in[506]
    DIRECTION INPUT ;
    USE SIGNAL ;
    SHAPE ABUTMENT ;
    PORT
      LAYER metal3 ;
      RECT 0.000 272.125 0.070 272.195 ;
    END
  END wd_in[506]
  PIN wd_in[507]
    DIRECTION INPUT ;
    USE SIGNAL ;
    SHAPE ABUTMENT ;
    PORT
      LAYER metal3 ;
      RECT 0.000 272.265 0.070 272.335 ;
    END
  END wd_in[507]
  PIN wd_in[508]
    DIRECTION INPUT ;
    USE SIGNAL ;
    SHAPE ABUTMENT ;
    PORT
      LAYER metal3 ;
      RECT 0.000 272.405 0.070 272.475 ;
    END
  END wd_in[508]
  PIN wd_in[509]
    DIRECTION INPUT ;
    USE SIGNAL ;
    SHAPE ABUTMENT ;
    PORT
      LAYER metal3 ;
      RECT 0.000 272.545 0.070 272.615 ;
    END
  END wd_in[509]
  PIN wd_in[510]
    DIRECTION INPUT ;
    USE SIGNAL ;
    SHAPE ABUTMENT ;
    PORT
      LAYER metal3 ;
      RECT 0.000 272.685 0.070 272.755 ;
    END
  END wd_in[510]
  PIN wd_in[511]
    DIRECTION INPUT ;
    USE SIGNAL ;
    SHAPE ABUTMENT ;
    PORT
      LAYER metal3 ;
      RECT 0.000 272.825 0.070 272.895 ;
    END
  END wd_in[511]
  PIN addr_in[0]
    DIRECTION INPUT ;
    USE SIGNAL ;
    SHAPE ABUTMENT ;
    PORT
      LAYER metal3 ;
      RECT 0.000 301.245 0.070 301.315 ;
    END
  END addr_in[0]
  PIN addr_in[1]
    DIRECTION INPUT ;
    USE SIGNAL ;
    SHAPE ABUTMENT ;
    PORT
      LAYER metal3 ;
      RECT 0.000 301.385 0.070 301.455 ;
    END
  END addr_in[1]
  PIN addr_in[2]
    DIRECTION INPUT ;
    USE SIGNAL ;
    SHAPE ABUTMENT ;
    PORT
      LAYER metal3 ;
      RECT 0.000 301.525 0.070 301.595 ;
    END
  END addr_in[2]
  PIN addr_in[3]
    DIRECTION INPUT ;
    USE SIGNAL ;
    SHAPE ABUTMENT ;
    PORT
      LAYER metal3 ;
      RECT 0.000 301.665 0.070 301.735 ;
    END
  END addr_in[3]
  PIN addr_in[4]
    DIRECTION INPUT ;
    USE SIGNAL ;
    SHAPE ABUTMENT ;
    PORT
      LAYER metal3 ;
      RECT 0.000 301.805 0.070 301.875 ;
    END
  END addr_in[4]
  PIN addr_in[5]
    DIRECTION INPUT ;
    USE SIGNAL ;
    SHAPE ABUTMENT ;
    PORT
      LAYER metal3 ;
      RECT 0.000 301.945 0.070 302.015 ;
    END
  END addr_in[5]
  PIN we_in
    DIRECTION INPUT ;
    USE SIGNAL ;
    SHAPE ABUTMENT ;
    PORT
      LAYER metal3 ;
      RECT 0.000 330.365 0.070 330.435 ;
    END
  END we_in
  PIN ce_in
    DIRECTION INPUT ;
    USE SIGNAL ;
    SHAPE ABUTMENT ;
    PORT
      LAYER metal3 ;
      RECT 0.000 330.505 0.070 330.575 ;
    END
  END ce_in
  PIN clk
    DIRECTION INPUT ;
    USE SIGNAL ;
    SHAPE ABUTMENT ;
    PORT
      LAYER metal3 ;
      RECT 0.000 330.645 0.070 330.715 ;
    END
  END clk
  PIN VSS
    DIRECTION INOUT ;
    USE GROUND ;
    PORT
      LAYER metal4 ;
      RECT 1.260 1.400 1.540 331.800 ;
      RECT 3.500 1.400 3.780 331.800 ;
      RECT 5.740 1.400 6.020 331.800 ;
      RECT 7.980 1.400 8.260 331.800 ;
      RECT 10.220 1.400 10.500 331.800 ;
      RECT 12.460 1.400 12.740 331.800 ;
      RECT 14.700 1.400 14.980 331.800 ;
      RECT 16.940 1.400 17.220 331.800 ;
      RECT 19.180 1.400 19.460 331.800 ;
      RECT 21.420 1.400 21.700 331.800 ;
      RECT 23.660 1.400 23.940 331.800 ;
      RECT 25.900 1.400 26.180 331.800 ;
      RECT 28.140 1.400 28.420 331.800 ;
      RECT 30.380 1.400 30.660 331.800 ;
      RECT 32.620 1.400 32.900 331.800 ;
      RECT 34.860 1.400 35.140 331.800 ;
      RECT 37.100 1.400 37.380 331.800 ;
      RECT 39.340 1.400 39.620 331.800 ;
      RECT 41.580 1.400 41.860 331.800 ;
      RECT 43.820 1.400 44.100 331.800 ;
      RECT 46.060 1.400 46.340 331.800 ;
      RECT 48.300 1.400 48.580 331.800 ;
      RECT 50.540 1.400 50.820 331.800 ;
      RECT 52.780 1.400 53.060 331.800 ;
      RECT 55.020 1.400 55.300 331.800 ;
      RECT 57.260 1.400 57.540 331.800 ;
      RECT 59.500 1.400 59.780 331.800 ;
      RECT 61.740 1.400 62.020 331.800 ;
      RECT 63.980 1.400 64.260 331.800 ;
      RECT 66.220 1.400 66.500 331.800 ;
      RECT 68.460 1.400 68.740 331.800 ;
      RECT 70.700 1.400 70.980 331.800 ;
      RECT 72.940 1.400 73.220 331.800 ;
      RECT 75.180 1.400 75.460 331.800 ;
      RECT 77.420 1.400 77.700 331.800 ;
      RECT 79.660 1.400 79.940 331.800 ;
      RECT 81.900 1.400 82.180 331.800 ;
      RECT 84.140 1.400 84.420 331.800 ;
      RECT 86.380 1.400 86.660 331.800 ;
      RECT 88.620 1.400 88.900 331.800 ;
      RECT 90.860 1.400 91.140 331.800 ;
      RECT 93.100 1.400 93.380 331.800 ;
      RECT 95.340 1.400 95.620 331.800 ;
      RECT 97.580 1.400 97.860 331.800 ;
      RECT 99.820 1.400 100.100 331.800 ;
      RECT 102.060 1.400 102.340 331.800 ;
      RECT 104.300 1.400 104.580 331.800 ;
      RECT 106.540 1.400 106.820 331.800 ;
      RECT 108.780 1.400 109.060 331.800 ;
      RECT 111.020 1.400 111.300 331.800 ;
      RECT 113.260 1.400 113.540 331.800 ;
      RECT 115.500 1.400 115.780 331.800 ;
      RECT 117.740 1.400 118.020 331.800 ;
      RECT 119.980 1.400 120.260 331.800 ;
      RECT 122.220 1.400 122.500 331.800 ;
      RECT 124.460 1.400 124.740 331.800 ;
      RECT 126.700 1.400 126.980 331.800 ;
      RECT 128.940 1.400 129.220 331.800 ;
      RECT 131.180 1.400 131.460 331.800 ;
      RECT 133.420 1.400 133.700 331.800 ;
      RECT 135.660 1.400 135.940 331.800 ;
      RECT 137.900 1.400 138.180 331.800 ;
      RECT 140.140 1.400 140.420 331.800 ;
      RECT 142.380 1.400 142.660 331.800 ;
      RECT 144.620 1.400 144.900 331.800 ;
      RECT 146.860 1.400 147.140 331.800 ;
      RECT 149.100 1.400 149.380 331.800 ;
      RECT 151.340 1.400 151.620 331.800 ;
      RECT 153.580 1.400 153.860 331.800 ;
      RECT 155.820 1.400 156.100 331.800 ;
      RECT 158.060 1.400 158.340 331.800 ;
      RECT 160.300 1.400 160.580 331.800 ;
      RECT 162.540 1.400 162.820 331.800 ;
    END
  END VSS
  PIN VDD
    DIRECTION INOUT ;
    USE POWER ;
    PORT
      LAYER metal4 ;
      RECT 2.380 1.400 2.660 331.800 ;
      RECT 4.620 1.400 4.900 331.800 ;
      RECT 6.860 1.400 7.140 331.800 ;
      RECT 9.100 1.400 9.380 331.800 ;
      RECT 11.340 1.400 11.620 331.800 ;
      RECT 13.580 1.400 13.860 331.800 ;
      RECT 15.820 1.400 16.100 331.800 ;
      RECT 18.060 1.400 18.340 331.800 ;
      RECT 20.300 1.400 20.580 331.800 ;
      RECT 22.540 1.400 22.820 331.800 ;
      RECT 24.780 1.400 25.060 331.800 ;
      RECT 27.020 1.400 27.300 331.800 ;
      RECT 29.260 1.400 29.540 331.800 ;
      RECT 31.500 1.400 31.780 331.800 ;
      RECT 33.740 1.400 34.020 331.800 ;
      RECT 35.980 1.400 36.260 331.800 ;
      RECT 38.220 1.400 38.500 331.800 ;
      RECT 40.460 1.400 40.740 331.800 ;
      RECT 42.700 1.400 42.980 331.800 ;
      RECT 44.940 1.400 45.220 331.800 ;
      RECT 47.180 1.400 47.460 331.800 ;
      RECT 49.420 1.400 49.700 331.800 ;
      RECT 51.660 1.400 51.940 331.800 ;
      RECT 53.900 1.400 54.180 331.800 ;
      RECT 56.140 1.400 56.420 331.800 ;
      RECT 58.380 1.400 58.660 331.800 ;
      RECT 60.620 1.400 60.900 331.800 ;
      RECT 62.860 1.400 63.140 331.800 ;
      RECT 65.100 1.400 65.380 331.800 ;
      RECT 67.340 1.400 67.620 331.800 ;
      RECT 69.580 1.400 69.860 331.800 ;
      RECT 71.820 1.400 72.100 331.800 ;
      RECT 74.060 1.400 74.340 331.800 ;
      RECT 76.300 1.400 76.580 331.800 ;
      RECT 78.540 1.400 78.820 331.800 ;
      RECT 80.780 1.400 81.060 331.800 ;
      RECT 83.020 1.400 83.300 331.800 ;
      RECT 85.260 1.400 85.540 331.800 ;
      RECT 87.500 1.400 87.780 331.800 ;
      RECT 89.740 1.400 90.020 331.800 ;
      RECT 91.980 1.400 92.260 331.800 ;
      RECT 94.220 1.400 94.500 331.800 ;
      RECT 96.460 1.400 96.740 331.800 ;
      RECT 98.700 1.400 98.980 331.800 ;
      RECT 100.940 1.400 101.220 331.800 ;
      RECT 103.180 1.400 103.460 331.800 ;
      RECT 105.420 1.400 105.700 331.800 ;
      RECT 107.660 1.400 107.940 331.800 ;
      RECT 109.900 1.400 110.180 331.800 ;
      RECT 112.140 1.400 112.420 331.800 ;
      RECT 114.380 1.400 114.660 331.800 ;
      RECT 116.620 1.400 116.900 331.800 ;
      RECT 118.860 1.400 119.140 331.800 ;
      RECT 121.100 1.400 121.380 331.800 ;
      RECT 123.340 1.400 123.620 331.800 ;
      RECT 125.580 1.400 125.860 331.800 ;
      RECT 127.820 1.400 128.100 331.800 ;
      RECT 130.060 1.400 130.340 331.800 ;
      RECT 132.300 1.400 132.580 331.800 ;
      RECT 134.540 1.400 134.820 331.800 ;
      RECT 136.780 1.400 137.060 331.800 ;
      RECT 139.020 1.400 139.300 331.800 ;
      RECT 141.260 1.400 141.540 331.800 ;
      RECT 143.500 1.400 143.780 331.800 ;
      RECT 145.740 1.400 146.020 331.800 ;
      RECT 147.980 1.400 148.260 331.800 ;
      RECT 150.220 1.400 150.500 331.800 ;
      RECT 152.460 1.400 152.740 331.800 ;
      RECT 154.700 1.400 154.980 331.800 ;
      RECT 156.940 1.400 157.220 331.800 ;
      RECT 159.180 1.400 159.460 331.800 ;
      RECT 161.420 1.400 161.700 331.800 ;
      RECT 163.660 1.400 163.940 331.800 ;
    END
  END VDD
  OBS
    LAYER metal1 ;
    RECT 0 0 165.870 333.200 ;
    LAYER metal2 ;
    RECT 0 0 165.870 333.200 ;
    LAYER metal3 ;
    RECT 0.070 0 165.870 333.200 ;
    RECT 0 0.000 0.070 1.365 ;
    RECT 0 1.435 0.070 1.505 ;
    RECT 0 1.575 0.070 1.645 ;
    RECT 0 1.715 0.070 1.785 ;
    RECT 0 1.855 0.070 1.925 ;
    RECT 0 1.995 0.070 2.065 ;
    RECT 0 2.135 0.070 2.205 ;
    RECT 0 2.275 0.070 2.345 ;
    RECT 0 2.415 0.070 2.485 ;
    RECT 0 2.555 0.070 2.625 ;
    RECT 0 2.695 0.070 2.765 ;
    RECT 0 2.835 0.070 2.905 ;
    RECT 0 2.975 0.070 3.045 ;
    RECT 0 3.115 0.070 3.185 ;
    RECT 0 3.255 0.070 3.325 ;
    RECT 0 3.395 0.070 3.465 ;
    RECT 0 3.535 0.070 3.605 ;
    RECT 0 3.675 0.070 3.745 ;
    RECT 0 3.815 0.070 3.885 ;
    RECT 0 3.955 0.070 4.025 ;
    RECT 0 4.095 0.070 4.165 ;
    RECT 0 4.235 0.070 4.305 ;
    RECT 0 4.375 0.070 4.445 ;
    RECT 0 4.515 0.070 4.585 ;
    RECT 0 4.655 0.070 4.725 ;
    RECT 0 4.795 0.070 4.865 ;
    RECT 0 4.935 0.070 5.005 ;
    RECT 0 5.075 0.070 5.145 ;
    RECT 0 5.215 0.070 5.285 ;
    RECT 0 5.355 0.070 5.425 ;
    RECT 0 5.495 0.070 5.565 ;
    RECT 0 5.635 0.070 5.705 ;
    RECT 0 5.775 0.070 5.845 ;
    RECT 0 5.915 0.070 5.985 ;
    RECT 0 6.055 0.070 6.125 ;
    RECT 0 6.195 0.070 6.265 ;
    RECT 0 6.335 0.070 6.405 ;
    RECT 0 6.475 0.070 6.545 ;
    RECT 0 6.615 0.070 6.685 ;
    RECT 0 6.755 0.070 6.825 ;
    RECT 0 6.895 0.070 6.965 ;
    RECT 0 7.035 0.070 7.105 ;
    RECT 0 7.175 0.070 7.245 ;
    RECT 0 7.315 0.070 7.385 ;
    RECT 0 7.455 0.070 7.525 ;
    RECT 0 7.595 0.070 7.665 ;
    RECT 0 7.735 0.070 7.805 ;
    RECT 0 7.875 0.070 7.945 ;
    RECT 0 8.015 0.070 8.085 ;
    RECT 0 8.155 0.070 8.225 ;
    RECT 0 8.295 0.070 8.365 ;
    RECT 0 8.435 0.070 8.505 ;
    RECT 0 8.575 0.070 8.645 ;
    RECT 0 8.715 0.070 8.785 ;
    RECT 0 8.855 0.070 8.925 ;
    RECT 0 8.995 0.070 9.065 ;
    RECT 0 9.135 0.070 9.205 ;
    RECT 0 9.275 0.070 9.345 ;
    RECT 0 9.415 0.070 9.485 ;
    RECT 0 9.555 0.070 9.625 ;
    RECT 0 9.695 0.070 9.765 ;
    RECT 0 9.835 0.070 9.905 ;
    RECT 0 9.975 0.070 10.045 ;
    RECT 0 10.115 0.070 10.185 ;
    RECT 0 10.255 0.070 10.325 ;
    RECT 0 10.395 0.070 10.465 ;
    RECT 0 10.535 0.070 10.605 ;
    RECT 0 10.675 0.070 10.745 ;
    RECT 0 10.815 0.070 10.885 ;
    RECT 0 10.955 0.070 11.025 ;
    RECT 0 11.095 0.070 11.165 ;
    RECT 0 11.235 0.070 11.305 ;
    RECT 0 11.375 0.070 11.445 ;
    RECT 0 11.515 0.070 11.585 ;
    RECT 0 11.655 0.070 11.725 ;
    RECT 0 11.795 0.070 11.865 ;
    RECT 0 11.935 0.070 12.005 ;
    RECT 0 12.075 0.070 12.145 ;
    RECT 0 12.215 0.070 12.285 ;
    RECT 0 12.355 0.070 12.425 ;
    RECT 0 12.495 0.070 12.565 ;
    RECT 0 12.635 0.070 12.705 ;
    RECT 0 12.775 0.070 12.845 ;
    RECT 0 12.915 0.070 12.985 ;
    RECT 0 13.055 0.070 13.125 ;
    RECT 0 13.195 0.070 13.265 ;
    RECT 0 13.335 0.070 13.405 ;
    RECT 0 13.475 0.070 13.545 ;
    RECT 0 13.615 0.070 13.685 ;
    RECT 0 13.755 0.070 13.825 ;
    RECT 0 13.895 0.070 13.965 ;
    RECT 0 14.035 0.070 14.105 ;
    RECT 0 14.175 0.070 14.245 ;
    RECT 0 14.315 0.070 14.385 ;
    RECT 0 14.455 0.070 14.525 ;
    RECT 0 14.595 0.070 14.665 ;
    RECT 0 14.735 0.070 14.805 ;
    RECT 0 14.875 0.070 14.945 ;
    RECT 0 15.015 0.070 15.085 ;
    RECT 0 15.155 0.070 15.225 ;
    RECT 0 15.295 0.070 15.365 ;
    RECT 0 15.435 0.070 15.505 ;
    RECT 0 15.575 0.070 15.645 ;
    RECT 0 15.715 0.070 15.785 ;
    RECT 0 15.855 0.070 15.925 ;
    RECT 0 15.995 0.070 16.065 ;
    RECT 0 16.135 0.070 16.205 ;
    RECT 0 16.275 0.070 16.345 ;
    RECT 0 16.415 0.070 16.485 ;
    RECT 0 16.555 0.070 16.625 ;
    RECT 0 16.695 0.070 16.765 ;
    RECT 0 16.835 0.070 16.905 ;
    RECT 0 16.975 0.070 17.045 ;
    RECT 0 17.115 0.070 17.185 ;
    RECT 0 17.255 0.070 17.325 ;
    RECT 0 17.395 0.070 17.465 ;
    RECT 0 17.535 0.070 17.605 ;
    RECT 0 17.675 0.070 17.745 ;
    RECT 0 17.815 0.070 17.885 ;
    RECT 0 17.955 0.070 18.025 ;
    RECT 0 18.095 0.070 18.165 ;
    RECT 0 18.235 0.070 18.305 ;
    RECT 0 18.375 0.070 18.445 ;
    RECT 0 18.515 0.070 18.585 ;
    RECT 0 18.655 0.070 18.725 ;
    RECT 0 18.795 0.070 18.865 ;
    RECT 0 18.935 0.070 19.005 ;
    RECT 0 19.075 0.070 19.145 ;
    RECT 0 19.215 0.070 19.285 ;
    RECT 0 19.355 0.070 19.425 ;
    RECT 0 19.495 0.070 19.565 ;
    RECT 0 19.635 0.070 19.705 ;
    RECT 0 19.775 0.070 19.845 ;
    RECT 0 19.915 0.070 19.985 ;
    RECT 0 20.055 0.070 20.125 ;
    RECT 0 20.195 0.070 20.265 ;
    RECT 0 20.335 0.070 20.405 ;
    RECT 0 20.475 0.070 20.545 ;
    RECT 0 20.615 0.070 20.685 ;
    RECT 0 20.755 0.070 20.825 ;
    RECT 0 20.895 0.070 20.965 ;
    RECT 0 21.035 0.070 21.105 ;
    RECT 0 21.175 0.070 21.245 ;
    RECT 0 21.315 0.070 21.385 ;
    RECT 0 21.455 0.070 21.525 ;
    RECT 0 21.595 0.070 21.665 ;
    RECT 0 21.735 0.070 21.805 ;
    RECT 0 21.875 0.070 21.945 ;
    RECT 0 22.015 0.070 22.085 ;
    RECT 0 22.155 0.070 22.225 ;
    RECT 0 22.295 0.070 22.365 ;
    RECT 0 22.435 0.070 22.505 ;
    RECT 0 22.575 0.070 22.645 ;
    RECT 0 22.715 0.070 22.785 ;
    RECT 0 22.855 0.070 22.925 ;
    RECT 0 22.995 0.070 23.065 ;
    RECT 0 23.135 0.070 23.205 ;
    RECT 0 23.275 0.070 23.345 ;
    RECT 0 23.415 0.070 23.485 ;
    RECT 0 23.555 0.070 23.625 ;
    RECT 0 23.695 0.070 23.765 ;
    RECT 0 23.835 0.070 23.905 ;
    RECT 0 23.975 0.070 24.045 ;
    RECT 0 24.115 0.070 24.185 ;
    RECT 0 24.255 0.070 24.325 ;
    RECT 0 24.395 0.070 24.465 ;
    RECT 0 24.535 0.070 24.605 ;
    RECT 0 24.675 0.070 24.745 ;
    RECT 0 24.815 0.070 24.885 ;
    RECT 0 24.955 0.070 25.025 ;
    RECT 0 25.095 0.070 25.165 ;
    RECT 0 25.235 0.070 25.305 ;
    RECT 0 25.375 0.070 25.445 ;
    RECT 0 25.515 0.070 25.585 ;
    RECT 0 25.655 0.070 25.725 ;
    RECT 0 25.795 0.070 25.865 ;
    RECT 0 25.935 0.070 26.005 ;
    RECT 0 26.075 0.070 26.145 ;
    RECT 0 26.215 0.070 26.285 ;
    RECT 0 26.355 0.070 26.425 ;
    RECT 0 26.495 0.070 26.565 ;
    RECT 0 26.635 0.070 26.705 ;
    RECT 0 26.775 0.070 26.845 ;
    RECT 0 26.915 0.070 26.985 ;
    RECT 0 27.055 0.070 27.125 ;
    RECT 0 27.195 0.070 27.265 ;
    RECT 0 27.335 0.070 27.405 ;
    RECT 0 27.475 0.070 27.545 ;
    RECT 0 27.615 0.070 27.685 ;
    RECT 0 27.755 0.070 27.825 ;
    RECT 0 27.895 0.070 27.965 ;
    RECT 0 28.035 0.070 28.105 ;
    RECT 0 28.175 0.070 28.245 ;
    RECT 0 28.315 0.070 28.385 ;
    RECT 0 28.455 0.070 28.525 ;
    RECT 0 28.595 0.070 28.665 ;
    RECT 0 28.735 0.070 28.805 ;
    RECT 0 28.875 0.070 28.945 ;
    RECT 0 29.015 0.070 29.085 ;
    RECT 0 29.155 0.070 29.225 ;
    RECT 0 29.295 0.070 29.365 ;
    RECT 0 29.435 0.070 29.505 ;
    RECT 0 29.575 0.070 29.645 ;
    RECT 0 29.715 0.070 29.785 ;
    RECT 0 29.855 0.070 29.925 ;
    RECT 0 29.995 0.070 30.065 ;
    RECT 0 30.135 0.070 30.205 ;
    RECT 0 30.275 0.070 30.345 ;
    RECT 0 30.415 0.070 30.485 ;
    RECT 0 30.555 0.070 30.625 ;
    RECT 0 30.695 0.070 30.765 ;
    RECT 0 30.835 0.070 30.905 ;
    RECT 0 30.975 0.070 31.045 ;
    RECT 0 31.115 0.070 31.185 ;
    RECT 0 31.255 0.070 31.325 ;
    RECT 0 31.395 0.070 31.465 ;
    RECT 0 31.535 0.070 31.605 ;
    RECT 0 31.675 0.070 31.745 ;
    RECT 0 31.815 0.070 31.885 ;
    RECT 0 31.955 0.070 32.025 ;
    RECT 0 32.095 0.070 32.165 ;
    RECT 0 32.235 0.070 32.305 ;
    RECT 0 32.375 0.070 32.445 ;
    RECT 0 32.515 0.070 32.585 ;
    RECT 0 32.655 0.070 32.725 ;
    RECT 0 32.795 0.070 32.865 ;
    RECT 0 32.935 0.070 33.005 ;
    RECT 0 33.075 0.070 33.145 ;
    RECT 0 33.215 0.070 33.285 ;
    RECT 0 33.355 0.070 33.425 ;
    RECT 0 33.495 0.070 33.565 ;
    RECT 0 33.635 0.070 33.705 ;
    RECT 0 33.775 0.070 33.845 ;
    RECT 0 33.915 0.070 33.985 ;
    RECT 0 34.055 0.070 34.125 ;
    RECT 0 34.195 0.070 34.265 ;
    RECT 0 34.335 0.070 34.405 ;
    RECT 0 34.475 0.070 34.545 ;
    RECT 0 34.615 0.070 34.685 ;
    RECT 0 34.755 0.070 34.825 ;
    RECT 0 34.895 0.070 34.965 ;
    RECT 0 35.035 0.070 35.105 ;
    RECT 0 35.175 0.070 35.245 ;
    RECT 0 35.315 0.070 35.385 ;
    RECT 0 35.455 0.070 35.525 ;
    RECT 0 35.595 0.070 35.665 ;
    RECT 0 35.735 0.070 35.805 ;
    RECT 0 35.875 0.070 35.945 ;
    RECT 0 36.015 0.070 36.085 ;
    RECT 0 36.155 0.070 36.225 ;
    RECT 0 36.295 0.070 36.365 ;
    RECT 0 36.435 0.070 36.505 ;
    RECT 0 36.575 0.070 36.645 ;
    RECT 0 36.715 0.070 36.785 ;
    RECT 0 36.855 0.070 36.925 ;
    RECT 0 36.995 0.070 37.065 ;
    RECT 0 37.135 0.070 37.205 ;
    RECT 0 37.275 0.070 37.345 ;
    RECT 0 37.415 0.070 37.485 ;
    RECT 0 37.555 0.070 37.625 ;
    RECT 0 37.695 0.070 37.765 ;
    RECT 0 37.835 0.070 37.905 ;
    RECT 0 37.975 0.070 38.045 ;
    RECT 0 38.115 0.070 38.185 ;
    RECT 0 38.255 0.070 38.325 ;
    RECT 0 38.395 0.070 38.465 ;
    RECT 0 38.535 0.070 38.605 ;
    RECT 0 38.675 0.070 38.745 ;
    RECT 0 38.815 0.070 38.885 ;
    RECT 0 38.955 0.070 39.025 ;
    RECT 0 39.095 0.070 39.165 ;
    RECT 0 39.235 0.070 39.305 ;
    RECT 0 39.375 0.070 39.445 ;
    RECT 0 39.515 0.070 39.585 ;
    RECT 0 39.655 0.070 39.725 ;
    RECT 0 39.795 0.070 39.865 ;
    RECT 0 39.935 0.070 40.005 ;
    RECT 0 40.075 0.070 40.145 ;
    RECT 0 40.215 0.070 40.285 ;
    RECT 0 40.355 0.070 40.425 ;
    RECT 0 40.495 0.070 40.565 ;
    RECT 0 40.635 0.070 40.705 ;
    RECT 0 40.775 0.070 40.845 ;
    RECT 0 40.915 0.070 40.985 ;
    RECT 0 41.055 0.070 41.125 ;
    RECT 0 41.195 0.070 41.265 ;
    RECT 0 41.335 0.070 41.405 ;
    RECT 0 41.475 0.070 41.545 ;
    RECT 0 41.615 0.070 41.685 ;
    RECT 0 41.755 0.070 41.825 ;
    RECT 0 41.895 0.070 41.965 ;
    RECT 0 42.035 0.070 42.105 ;
    RECT 0 42.175 0.070 42.245 ;
    RECT 0 42.315 0.070 42.385 ;
    RECT 0 42.455 0.070 42.525 ;
    RECT 0 42.595 0.070 42.665 ;
    RECT 0 42.735 0.070 42.805 ;
    RECT 0 42.875 0.070 42.945 ;
    RECT 0 43.015 0.070 43.085 ;
    RECT 0 43.155 0.070 43.225 ;
    RECT 0 43.295 0.070 43.365 ;
    RECT 0 43.435 0.070 43.505 ;
    RECT 0 43.575 0.070 43.645 ;
    RECT 0 43.715 0.070 43.785 ;
    RECT 0 43.855 0.070 43.925 ;
    RECT 0 43.995 0.070 44.065 ;
    RECT 0 44.135 0.070 44.205 ;
    RECT 0 44.275 0.070 44.345 ;
    RECT 0 44.415 0.070 44.485 ;
    RECT 0 44.555 0.070 44.625 ;
    RECT 0 44.695 0.070 44.765 ;
    RECT 0 44.835 0.070 44.905 ;
    RECT 0 44.975 0.070 45.045 ;
    RECT 0 45.115 0.070 45.185 ;
    RECT 0 45.255 0.070 45.325 ;
    RECT 0 45.395 0.070 45.465 ;
    RECT 0 45.535 0.070 45.605 ;
    RECT 0 45.675 0.070 45.745 ;
    RECT 0 45.815 0.070 45.885 ;
    RECT 0 45.955 0.070 46.025 ;
    RECT 0 46.095 0.070 46.165 ;
    RECT 0 46.235 0.070 46.305 ;
    RECT 0 46.375 0.070 46.445 ;
    RECT 0 46.515 0.070 46.585 ;
    RECT 0 46.655 0.070 46.725 ;
    RECT 0 46.795 0.070 46.865 ;
    RECT 0 46.935 0.070 47.005 ;
    RECT 0 47.075 0.070 47.145 ;
    RECT 0 47.215 0.070 47.285 ;
    RECT 0 47.355 0.070 47.425 ;
    RECT 0 47.495 0.070 47.565 ;
    RECT 0 47.635 0.070 47.705 ;
    RECT 0 47.775 0.070 47.845 ;
    RECT 0 47.915 0.070 47.985 ;
    RECT 0 48.055 0.070 48.125 ;
    RECT 0 48.195 0.070 48.265 ;
    RECT 0 48.335 0.070 48.405 ;
    RECT 0 48.475 0.070 48.545 ;
    RECT 0 48.615 0.070 48.685 ;
    RECT 0 48.755 0.070 48.825 ;
    RECT 0 48.895 0.070 48.965 ;
    RECT 0 49.035 0.070 49.105 ;
    RECT 0 49.175 0.070 49.245 ;
    RECT 0 49.315 0.070 49.385 ;
    RECT 0 49.455 0.070 49.525 ;
    RECT 0 49.595 0.070 49.665 ;
    RECT 0 49.735 0.070 49.805 ;
    RECT 0 49.875 0.070 49.945 ;
    RECT 0 50.015 0.070 50.085 ;
    RECT 0 50.155 0.070 50.225 ;
    RECT 0 50.295 0.070 50.365 ;
    RECT 0 50.435 0.070 50.505 ;
    RECT 0 50.575 0.070 50.645 ;
    RECT 0 50.715 0.070 50.785 ;
    RECT 0 50.855 0.070 50.925 ;
    RECT 0 50.995 0.070 51.065 ;
    RECT 0 51.135 0.070 51.205 ;
    RECT 0 51.275 0.070 51.345 ;
    RECT 0 51.415 0.070 51.485 ;
    RECT 0 51.555 0.070 51.625 ;
    RECT 0 51.695 0.070 51.765 ;
    RECT 0 51.835 0.070 51.905 ;
    RECT 0 51.975 0.070 52.045 ;
    RECT 0 52.115 0.070 52.185 ;
    RECT 0 52.255 0.070 52.325 ;
    RECT 0 52.395 0.070 52.465 ;
    RECT 0 52.535 0.070 52.605 ;
    RECT 0 52.675 0.070 52.745 ;
    RECT 0 52.815 0.070 52.885 ;
    RECT 0 52.955 0.070 53.025 ;
    RECT 0 53.095 0.070 53.165 ;
    RECT 0 53.235 0.070 53.305 ;
    RECT 0 53.375 0.070 53.445 ;
    RECT 0 53.515 0.070 53.585 ;
    RECT 0 53.655 0.070 53.725 ;
    RECT 0 53.795 0.070 53.865 ;
    RECT 0 53.935 0.070 54.005 ;
    RECT 0 54.075 0.070 54.145 ;
    RECT 0 54.215 0.070 54.285 ;
    RECT 0 54.355 0.070 54.425 ;
    RECT 0 54.495 0.070 54.565 ;
    RECT 0 54.635 0.070 54.705 ;
    RECT 0 54.775 0.070 54.845 ;
    RECT 0 54.915 0.070 54.985 ;
    RECT 0 55.055 0.070 55.125 ;
    RECT 0 55.195 0.070 55.265 ;
    RECT 0 55.335 0.070 55.405 ;
    RECT 0 55.475 0.070 55.545 ;
    RECT 0 55.615 0.070 55.685 ;
    RECT 0 55.755 0.070 55.825 ;
    RECT 0 55.895 0.070 55.965 ;
    RECT 0 56.035 0.070 56.105 ;
    RECT 0 56.175 0.070 56.245 ;
    RECT 0 56.315 0.070 56.385 ;
    RECT 0 56.455 0.070 56.525 ;
    RECT 0 56.595 0.070 56.665 ;
    RECT 0 56.735 0.070 56.805 ;
    RECT 0 56.875 0.070 56.945 ;
    RECT 0 57.015 0.070 57.085 ;
    RECT 0 57.155 0.070 57.225 ;
    RECT 0 57.295 0.070 57.365 ;
    RECT 0 57.435 0.070 57.505 ;
    RECT 0 57.575 0.070 57.645 ;
    RECT 0 57.715 0.070 57.785 ;
    RECT 0 57.855 0.070 57.925 ;
    RECT 0 57.995 0.070 58.065 ;
    RECT 0 58.135 0.070 58.205 ;
    RECT 0 58.275 0.070 58.345 ;
    RECT 0 58.415 0.070 58.485 ;
    RECT 0 58.555 0.070 58.625 ;
    RECT 0 58.695 0.070 58.765 ;
    RECT 0 58.835 0.070 58.905 ;
    RECT 0 58.975 0.070 59.045 ;
    RECT 0 59.115 0.070 59.185 ;
    RECT 0 59.255 0.070 59.325 ;
    RECT 0 59.395 0.070 59.465 ;
    RECT 0 59.535 0.070 59.605 ;
    RECT 0 59.675 0.070 59.745 ;
    RECT 0 59.815 0.070 59.885 ;
    RECT 0 59.955 0.070 60.025 ;
    RECT 0 60.095 0.070 60.165 ;
    RECT 0 60.235 0.070 60.305 ;
    RECT 0 60.375 0.070 60.445 ;
    RECT 0 60.515 0.070 60.585 ;
    RECT 0 60.655 0.070 60.725 ;
    RECT 0 60.795 0.070 60.865 ;
    RECT 0 60.935 0.070 61.005 ;
    RECT 0 61.075 0.070 61.145 ;
    RECT 0 61.215 0.070 61.285 ;
    RECT 0 61.355 0.070 61.425 ;
    RECT 0 61.495 0.070 61.565 ;
    RECT 0 61.635 0.070 61.705 ;
    RECT 0 61.775 0.070 61.845 ;
    RECT 0 61.915 0.070 61.985 ;
    RECT 0 62.055 0.070 62.125 ;
    RECT 0 62.195 0.070 62.265 ;
    RECT 0 62.335 0.070 62.405 ;
    RECT 0 62.475 0.070 62.545 ;
    RECT 0 62.615 0.070 62.685 ;
    RECT 0 62.755 0.070 62.825 ;
    RECT 0 62.895 0.070 62.965 ;
    RECT 0 63.035 0.070 63.105 ;
    RECT 0 63.175 0.070 63.245 ;
    RECT 0 63.315 0.070 63.385 ;
    RECT 0 63.455 0.070 63.525 ;
    RECT 0 63.595 0.070 63.665 ;
    RECT 0 63.735 0.070 63.805 ;
    RECT 0 63.875 0.070 63.945 ;
    RECT 0 64.015 0.070 64.085 ;
    RECT 0 64.155 0.070 64.225 ;
    RECT 0 64.295 0.070 64.365 ;
    RECT 0 64.435 0.070 64.505 ;
    RECT 0 64.575 0.070 64.645 ;
    RECT 0 64.715 0.070 64.785 ;
    RECT 0 64.855 0.070 64.925 ;
    RECT 0 64.995 0.070 65.065 ;
    RECT 0 65.135 0.070 65.205 ;
    RECT 0 65.275 0.070 65.345 ;
    RECT 0 65.415 0.070 65.485 ;
    RECT 0 65.555 0.070 65.625 ;
    RECT 0 65.695 0.070 65.765 ;
    RECT 0 65.835 0.070 65.905 ;
    RECT 0 65.975 0.070 66.045 ;
    RECT 0 66.115 0.070 66.185 ;
    RECT 0 66.255 0.070 66.325 ;
    RECT 0 66.395 0.070 66.465 ;
    RECT 0 66.535 0.070 66.605 ;
    RECT 0 66.675 0.070 66.745 ;
    RECT 0 66.815 0.070 66.885 ;
    RECT 0 66.955 0.070 67.025 ;
    RECT 0 67.095 0.070 67.165 ;
    RECT 0 67.235 0.070 67.305 ;
    RECT 0 67.375 0.070 67.445 ;
    RECT 0 67.515 0.070 67.585 ;
    RECT 0 67.655 0.070 67.725 ;
    RECT 0 67.795 0.070 67.865 ;
    RECT 0 67.935 0.070 68.005 ;
    RECT 0 68.075 0.070 68.145 ;
    RECT 0 68.215 0.070 68.285 ;
    RECT 0 68.355 0.070 68.425 ;
    RECT 0 68.495 0.070 68.565 ;
    RECT 0 68.635 0.070 68.705 ;
    RECT 0 68.775 0.070 68.845 ;
    RECT 0 68.915 0.070 68.985 ;
    RECT 0 69.055 0.070 69.125 ;
    RECT 0 69.195 0.070 69.265 ;
    RECT 0 69.335 0.070 69.405 ;
    RECT 0 69.475 0.070 69.545 ;
    RECT 0 69.615 0.070 69.685 ;
    RECT 0 69.755 0.070 69.825 ;
    RECT 0 69.895 0.070 69.965 ;
    RECT 0 70.035 0.070 70.105 ;
    RECT 0 70.175 0.070 70.245 ;
    RECT 0 70.315 0.070 70.385 ;
    RECT 0 70.455 0.070 70.525 ;
    RECT 0 70.595 0.070 70.665 ;
    RECT 0 70.735 0.070 70.805 ;
    RECT 0 70.875 0.070 70.945 ;
    RECT 0 71.015 0.070 71.085 ;
    RECT 0 71.155 0.070 71.225 ;
    RECT 0 71.295 0.070 71.365 ;
    RECT 0 71.435 0.070 71.505 ;
    RECT 0 71.575 0.070 71.645 ;
    RECT 0 71.715 0.070 71.785 ;
    RECT 0 71.855 0.070 71.925 ;
    RECT 0 71.995 0.070 72.065 ;
    RECT 0 72.135 0.070 72.205 ;
    RECT 0 72.275 0.070 72.345 ;
    RECT 0 72.415 0.070 72.485 ;
    RECT 0 72.555 0.070 72.625 ;
    RECT 0 72.695 0.070 72.765 ;
    RECT 0 72.835 0.070 72.905 ;
    RECT 0 72.975 0.070 101.325 ;
    RECT 0 101.395 0.070 101.465 ;
    RECT 0 101.535 0.070 101.605 ;
    RECT 0 101.675 0.070 101.745 ;
    RECT 0 101.815 0.070 101.885 ;
    RECT 0 101.955 0.070 102.025 ;
    RECT 0 102.095 0.070 102.165 ;
    RECT 0 102.235 0.070 102.305 ;
    RECT 0 102.375 0.070 102.445 ;
    RECT 0 102.515 0.070 102.585 ;
    RECT 0 102.655 0.070 102.725 ;
    RECT 0 102.795 0.070 102.865 ;
    RECT 0 102.935 0.070 103.005 ;
    RECT 0 103.075 0.070 103.145 ;
    RECT 0 103.215 0.070 103.285 ;
    RECT 0 103.355 0.070 103.425 ;
    RECT 0 103.495 0.070 103.565 ;
    RECT 0 103.635 0.070 103.705 ;
    RECT 0 103.775 0.070 103.845 ;
    RECT 0 103.915 0.070 103.985 ;
    RECT 0 104.055 0.070 104.125 ;
    RECT 0 104.195 0.070 104.265 ;
    RECT 0 104.335 0.070 104.405 ;
    RECT 0 104.475 0.070 104.545 ;
    RECT 0 104.615 0.070 104.685 ;
    RECT 0 104.755 0.070 104.825 ;
    RECT 0 104.895 0.070 104.965 ;
    RECT 0 105.035 0.070 105.105 ;
    RECT 0 105.175 0.070 105.245 ;
    RECT 0 105.315 0.070 105.385 ;
    RECT 0 105.455 0.070 105.525 ;
    RECT 0 105.595 0.070 105.665 ;
    RECT 0 105.735 0.070 105.805 ;
    RECT 0 105.875 0.070 105.945 ;
    RECT 0 106.015 0.070 106.085 ;
    RECT 0 106.155 0.070 106.225 ;
    RECT 0 106.295 0.070 106.365 ;
    RECT 0 106.435 0.070 106.505 ;
    RECT 0 106.575 0.070 106.645 ;
    RECT 0 106.715 0.070 106.785 ;
    RECT 0 106.855 0.070 106.925 ;
    RECT 0 106.995 0.070 107.065 ;
    RECT 0 107.135 0.070 107.205 ;
    RECT 0 107.275 0.070 107.345 ;
    RECT 0 107.415 0.070 107.485 ;
    RECT 0 107.555 0.070 107.625 ;
    RECT 0 107.695 0.070 107.765 ;
    RECT 0 107.835 0.070 107.905 ;
    RECT 0 107.975 0.070 108.045 ;
    RECT 0 108.115 0.070 108.185 ;
    RECT 0 108.255 0.070 108.325 ;
    RECT 0 108.395 0.070 108.465 ;
    RECT 0 108.535 0.070 108.605 ;
    RECT 0 108.675 0.070 108.745 ;
    RECT 0 108.815 0.070 108.885 ;
    RECT 0 108.955 0.070 109.025 ;
    RECT 0 109.095 0.070 109.165 ;
    RECT 0 109.235 0.070 109.305 ;
    RECT 0 109.375 0.070 109.445 ;
    RECT 0 109.515 0.070 109.585 ;
    RECT 0 109.655 0.070 109.725 ;
    RECT 0 109.795 0.070 109.865 ;
    RECT 0 109.935 0.070 110.005 ;
    RECT 0 110.075 0.070 110.145 ;
    RECT 0 110.215 0.070 110.285 ;
    RECT 0 110.355 0.070 110.425 ;
    RECT 0 110.495 0.070 110.565 ;
    RECT 0 110.635 0.070 110.705 ;
    RECT 0 110.775 0.070 110.845 ;
    RECT 0 110.915 0.070 110.985 ;
    RECT 0 111.055 0.070 111.125 ;
    RECT 0 111.195 0.070 111.265 ;
    RECT 0 111.335 0.070 111.405 ;
    RECT 0 111.475 0.070 111.545 ;
    RECT 0 111.615 0.070 111.685 ;
    RECT 0 111.755 0.070 111.825 ;
    RECT 0 111.895 0.070 111.965 ;
    RECT 0 112.035 0.070 112.105 ;
    RECT 0 112.175 0.070 112.245 ;
    RECT 0 112.315 0.070 112.385 ;
    RECT 0 112.455 0.070 112.525 ;
    RECT 0 112.595 0.070 112.665 ;
    RECT 0 112.735 0.070 112.805 ;
    RECT 0 112.875 0.070 112.945 ;
    RECT 0 113.015 0.070 113.085 ;
    RECT 0 113.155 0.070 113.225 ;
    RECT 0 113.295 0.070 113.365 ;
    RECT 0 113.435 0.070 113.505 ;
    RECT 0 113.575 0.070 113.645 ;
    RECT 0 113.715 0.070 113.785 ;
    RECT 0 113.855 0.070 113.925 ;
    RECT 0 113.995 0.070 114.065 ;
    RECT 0 114.135 0.070 114.205 ;
    RECT 0 114.275 0.070 114.345 ;
    RECT 0 114.415 0.070 114.485 ;
    RECT 0 114.555 0.070 114.625 ;
    RECT 0 114.695 0.070 114.765 ;
    RECT 0 114.835 0.070 114.905 ;
    RECT 0 114.975 0.070 115.045 ;
    RECT 0 115.115 0.070 115.185 ;
    RECT 0 115.255 0.070 115.325 ;
    RECT 0 115.395 0.070 115.465 ;
    RECT 0 115.535 0.070 115.605 ;
    RECT 0 115.675 0.070 115.745 ;
    RECT 0 115.815 0.070 115.885 ;
    RECT 0 115.955 0.070 116.025 ;
    RECT 0 116.095 0.070 116.165 ;
    RECT 0 116.235 0.070 116.305 ;
    RECT 0 116.375 0.070 116.445 ;
    RECT 0 116.515 0.070 116.585 ;
    RECT 0 116.655 0.070 116.725 ;
    RECT 0 116.795 0.070 116.865 ;
    RECT 0 116.935 0.070 117.005 ;
    RECT 0 117.075 0.070 117.145 ;
    RECT 0 117.215 0.070 117.285 ;
    RECT 0 117.355 0.070 117.425 ;
    RECT 0 117.495 0.070 117.565 ;
    RECT 0 117.635 0.070 117.705 ;
    RECT 0 117.775 0.070 117.845 ;
    RECT 0 117.915 0.070 117.985 ;
    RECT 0 118.055 0.070 118.125 ;
    RECT 0 118.195 0.070 118.265 ;
    RECT 0 118.335 0.070 118.405 ;
    RECT 0 118.475 0.070 118.545 ;
    RECT 0 118.615 0.070 118.685 ;
    RECT 0 118.755 0.070 118.825 ;
    RECT 0 118.895 0.070 118.965 ;
    RECT 0 119.035 0.070 119.105 ;
    RECT 0 119.175 0.070 119.245 ;
    RECT 0 119.315 0.070 119.385 ;
    RECT 0 119.455 0.070 119.525 ;
    RECT 0 119.595 0.070 119.665 ;
    RECT 0 119.735 0.070 119.805 ;
    RECT 0 119.875 0.070 119.945 ;
    RECT 0 120.015 0.070 120.085 ;
    RECT 0 120.155 0.070 120.225 ;
    RECT 0 120.295 0.070 120.365 ;
    RECT 0 120.435 0.070 120.505 ;
    RECT 0 120.575 0.070 120.645 ;
    RECT 0 120.715 0.070 120.785 ;
    RECT 0 120.855 0.070 120.925 ;
    RECT 0 120.995 0.070 121.065 ;
    RECT 0 121.135 0.070 121.205 ;
    RECT 0 121.275 0.070 121.345 ;
    RECT 0 121.415 0.070 121.485 ;
    RECT 0 121.555 0.070 121.625 ;
    RECT 0 121.695 0.070 121.765 ;
    RECT 0 121.835 0.070 121.905 ;
    RECT 0 121.975 0.070 122.045 ;
    RECT 0 122.115 0.070 122.185 ;
    RECT 0 122.255 0.070 122.325 ;
    RECT 0 122.395 0.070 122.465 ;
    RECT 0 122.535 0.070 122.605 ;
    RECT 0 122.675 0.070 122.745 ;
    RECT 0 122.815 0.070 122.885 ;
    RECT 0 122.955 0.070 123.025 ;
    RECT 0 123.095 0.070 123.165 ;
    RECT 0 123.235 0.070 123.305 ;
    RECT 0 123.375 0.070 123.445 ;
    RECT 0 123.515 0.070 123.585 ;
    RECT 0 123.655 0.070 123.725 ;
    RECT 0 123.795 0.070 123.865 ;
    RECT 0 123.935 0.070 124.005 ;
    RECT 0 124.075 0.070 124.145 ;
    RECT 0 124.215 0.070 124.285 ;
    RECT 0 124.355 0.070 124.425 ;
    RECT 0 124.495 0.070 124.565 ;
    RECT 0 124.635 0.070 124.705 ;
    RECT 0 124.775 0.070 124.845 ;
    RECT 0 124.915 0.070 124.985 ;
    RECT 0 125.055 0.070 125.125 ;
    RECT 0 125.195 0.070 125.265 ;
    RECT 0 125.335 0.070 125.405 ;
    RECT 0 125.475 0.070 125.545 ;
    RECT 0 125.615 0.070 125.685 ;
    RECT 0 125.755 0.070 125.825 ;
    RECT 0 125.895 0.070 125.965 ;
    RECT 0 126.035 0.070 126.105 ;
    RECT 0 126.175 0.070 126.245 ;
    RECT 0 126.315 0.070 126.385 ;
    RECT 0 126.455 0.070 126.525 ;
    RECT 0 126.595 0.070 126.665 ;
    RECT 0 126.735 0.070 126.805 ;
    RECT 0 126.875 0.070 126.945 ;
    RECT 0 127.015 0.070 127.085 ;
    RECT 0 127.155 0.070 127.225 ;
    RECT 0 127.295 0.070 127.365 ;
    RECT 0 127.435 0.070 127.505 ;
    RECT 0 127.575 0.070 127.645 ;
    RECT 0 127.715 0.070 127.785 ;
    RECT 0 127.855 0.070 127.925 ;
    RECT 0 127.995 0.070 128.065 ;
    RECT 0 128.135 0.070 128.205 ;
    RECT 0 128.275 0.070 128.345 ;
    RECT 0 128.415 0.070 128.485 ;
    RECT 0 128.555 0.070 128.625 ;
    RECT 0 128.695 0.070 128.765 ;
    RECT 0 128.835 0.070 128.905 ;
    RECT 0 128.975 0.070 129.045 ;
    RECT 0 129.115 0.070 129.185 ;
    RECT 0 129.255 0.070 129.325 ;
    RECT 0 129.395 0.070 129.465 ;
    RECT 0 129.535 0.070 129.605 ;
    RECT 0 129.675 0.070 129.745 ;
    RECT 0 129.815 0.070 129.885 ;
    RECT 0 129.955 0.070 130.025 ;
    RECT 0 130.095 0.070 130.165 ;
    RECT 0 130.235 0.070 130.305 ;
    RECT 0 130.375 0.070 130.445 ;
    RECT 0 130.515 0.070 130.585 ;
    RECT 0 130.655 0.070 130.725 ;
    RECT 0 130.795 0.070 130.865 ;
    RECT 0 130.935 0.070 131.005 ;
    RECT 0 131.075 0.070 131.145 ;
    RECT 0 131.215 0.070 131.285 ;
    RECT 0 131.355 0.070 131.425 ;
    RECT 0 131.495 0.070 131.565 ;
    RECT 0 131.635 0.070 131.705 ;
    RECT 0 131.775 0.070 131.845 ;
    RECT 0 131.915 0.070 131.985 ;
    RECT 0 132.055 0.070 132.125 ;
    RECT 0 132.195 0.070 132.265 ;
    RECT 0 132.335 0.070 132.405 ;
    RECT 0 132.475 0.070 132.545 ;
    RECT 0 132.615 0.070 132.685 ;
    RECT 0 132.755 0.070 132.825 ;
    RECT 0 132.895 0.070 132.965 ;
    RECT 0 133.035 0.070 133.105 ;
    RECT 0 133.175 0.070 133.245 ;
    RECT 0 133.315 0.070 133.385 ;
    RECT 0 133.455 0.070 133.525 ;
    RECT 0 133.595 0.070 133.665 ;
    RECT 0 133.735 0.070 133.805 ;
    RECT 0 133.875 0.070 133.945 ;
    RECT 0 134.015 0.070 134.085 ;
    RECT 0 134.155 0.070 134.225 ;
    RECT 0 134.295 0.070 134.365 ;
    RECT 0 134.435 0.070 134.505 ;
    RECT 0 134.575 0.070 134.645 ;
    RECT 0 134.715 0.070 134.785 ;
    RECT 0 134.855 0.070 134.925 ;
    RECT 0 134.995 0.070 135.065 ;
    RECT 0 135.135 0.070 135.205 ;
    RECT 0 135.275 0.070 135.345 ;
    RECT 0 135.415 0.070 135.485 ;
    RECT 0 135.555 0.070 135.625 ;
    RECT 0 135.695 0.070 135.765 ;
    RECT 0 135.835 0.070 135.905 ;
    RECT 0 135.975 0.070 136.045 ;
    RECT 0 136.115 0.070 136.185 ;
    RECT 0 136.255 0.070 136.325 ;
    RECT 0 136.395 0.070 136.465 ;
    RECT 0 136.535 0.070 136.605 ;
    RECT 0 136.675 0.070 136.745 ;
    RECT 0 136.815 0.070 136.885 ;
    RECT 0 136.955 0.070 137.025 ;
    RECT 0 137.095 0.070 137.165 ;
    RECT 0 137.235 0.070 137.305 ;
    RECT 0 137.375 0.070 137.445 ;
    RECT 0 137.515 0.070 137.585 ;
    RECT 0 137.655 0.070 137.725 ;
    RECT 0 137.795 0.070 137.865 ;
    RECT 0 137.935 0.070 138.005 ;
    RECT 0 138.075 0.070 138.145 ;
    RECT 0 138.215 0.070 138.285 ;
    RECT 0 138.355 0.070 138.425 ;
    RECT 0 138.495 0.070 138.565 ;
    RECT 0 138.635 0.070 138.705 ;
    RECT 0 138.775 0.070 138.845 ;
    RECT 0 138.915 0.070 138.985 ;
    RECT 0 139.055 0.070 139.125 ;
    RECT 0 139.195 0.070 139.265 ;
    RECT 0 139.335 0.070 139.405 ;
    RECT 0 139.475 0.070 139.545 ;
    RECT 0 139.615 0.070 139.685 ;
    RECT 0 139.755 0.070 139.825 ;
    RECT 0 139.895 0.070 139.965 ;
    RECT 0 140.035 0.070 140.105 ;
    RECT 0 140.175 0.070 140.245 ;
    RECT 0 140.315 0.070 140.385 ;
    RECT 0 140.455 0.070 140.525 ;
    RECT 0 140.595 0.070 140.665 ;
    RECT 0 140.735 0.070 140.805 ;
    RECT 0 140.875 0.070 140.945 ;
    RECT 0 141.015 0.070 141.085 ;
    RECT 0 141.155 0.070 141.225 ;
    RECT 0 141.295 0.070 141.365 ;
    RECT 0 141.435 0.070 141.505 ;
    RECT 0 141.575 0.070 141.645 ;
    RECT 0 141.715 0.070 141.785 ;
    RECT 0 141.855 0.070 141.925 ;
    RECT 0 141.995 0.070 142.065 ;
    RECT 0 142.135 0.070 142.205 ;
    RECT 0 142.275 0.070 142.345 ;
    RECT 0 142.415 0.070 142.485 ;
    RECT 0 142.555 0.070 142.625 ;
    RECT 0 142.695 0.070 142.765 ;
    RECT 0 142.835 0.070 142.905 ;
    RECT 0 142.975 0.070 143.045 ;
    RECT 0 143.115 0.070 143.185 ;
    RECT 0 143.255 0.070 143.325 ;
    RECT 0 143.395 0.070 143.465 ;
    RECT 0 143.535 0.070 143.605 ;
    RECT 0 143.675 0.070 143.745 ;
    RECT 0 143.815 0.070 143.885 ;
    RECT 0 143.955 0.070 144.025 ;
    RECT 0 144.095 0.070 144.165 ;
    RECT 0 144.235 0.070 144.305 ;
    RECT 0 144.375 0.070 144.445 ;
    RECT 0 144.515 0.070 144.585 ;
    RECT 0 144.655 0.070 144.725 ;
    RECT 0 144.795 0.070 144.865 ;
    RECT 0 144.935 0.070 145.005 ;
    RECT 0 145.075 0.070 145.145 ;
    RECT 0 145.215 0.070 145.285 ;
    RECT 0 145.355 0.070 145.425 ;
    RECT 0 145.495 0.070 145.565 ;
    RECT 0 145.635 0.070 145.705 ;
    RECT 0 145.775 0.070 145.845 ;
    RECT 0 145.915 0.070 145.985 ;
    RECT 0 146.055 0.070 146.125 ;
    RECT 0 146.195 0.070 146.265 ;
    RECT 0 146.335 0.070 146.405 ;
    RECT 0 146.475 0.070 146.545 ;
    RECT 0 146.615 0.070 146.685 ;
    RECT 0 146.755 0.070 146.825 ;
    RECT 0 146.895 0.070 146.965 ;
    RECT 0 147.035 0.070 147.105 ;
    RECT 0 147.175 0.070 147.245 ;
    RECT 0 147.315 0.070 147.385 ;
    RECT 0 147.455 0.070 147.525 ;
    RECT 0 147.595 0.070 147.665 ;
    RECT 0 147.735 0.070 147.805 ;
    RECT 0 147.875 0.070 147.945 ;
    RECT 0 148.015 0.070 148.085 ;
    RECT 0 148.155 0.070 148.225 ;
    RECT 0 148.295 0.070 148.365 ;
    RECT 0 148.435 0.070 148.505 ;
    RECT 0 148.575 0.070 148.645 ;
    RECT 0 148.715 0.070 148.785 ;
    RECT 0 148.855 0.070 148.925 ;
    RECT 0 148.995 0.070 149.065 ;
    RECT 0 149.135 0.070 149.205 ;
    RECT 0 149.275 0.070 149.345 ;
    RECT 0 149.415 0.070 149.485 ;
    RECT 0 149.555 0.070 149.625 ;
    RECT 0 149.695 0.070 149.765 ;
    RECT 0 149.835 0.070 149.905 ;
    RECT 0 149.975 0.070 150.045 ;
    RECT 0 150.115 0.070 150.185 ;
    RECT 0 150.255 0.070 150.325 ;
    RECT 0 150.395 0.070 150.465 ;
    RECT 0 150.535 0.070 150.605 ;
    RECT 0 150.675 0.070 150.745 ;
    RECT 0 150.815 0.070 150.885 ;
    RECT 0 150.955 0.070 151.025 ;
    RECT 0 151.095 0.070 151.165 ;
    RECT 0 151.235 0.070 151.305 ;
    RECT 0 151.375 0.070 151.445 ;
    RECT 0 151.515 0.070 151.585 ;
    RECT 0 151.655 0.070 151.725 ;
    RECT 0 151.795 0.070 151.865 ;
    RECT 0 151.935 0.070 152.005 ;
    RECT 0 152.075 0.070 152.145 ;
    RECT 0 152.215 0.070 152.285 ;
    RECT 0 152.355 0.070 152.425 ;
    RECT 0 152.495 0.070 152.565 ;
    RECT 0 152.635 0.070 152.705 ;
    RECT 0 152.775 0.070 152.845 ;
    RECT 0 152.915 0.070 152.985 ;
    RECT 0 153.055 0.070 153.125 ;
    RECT 0 153.195 0.070 153.265 ;
    RECT 0 153.335 0.070 153.405 ;
    RECT 0 153.475 0.070 153.545 ;
    RECT 0 153.615 0.070 153.685 ;
    RECT 0 153.755 0.070 153.825 ;
    RECT 0 153.895 0.070 153.965 ;
    RECT 0 154.035 0.070 154.105 ;
    RECT 0 154.175 0.070 154.245 ;
    RECT 0 154.315 0.070 154.385 ;
    RECT 0 154.455 0.070 154.525 ;
    RECT 0 154.595 0.070 154.665 ;
    RECT 0 154.735 0.070 154.805 ;
    RECT 0 154.875 0.070 154.945 ;
    RECT 0 155.015 0.070 155.085 ;
    RECT 0 155.155 0.070 155.225 ;
    RECT 0 155.295 0.070 155.365 ;
    RECT 0 155.435 0.070 155.505 ;
    RECT 0 155.575 0.070 155.645 ;
    RECT 0 155.715 0.070 155.785 ;
    RECT 0 155.855 0.070 155.925 ;
    RECT 0 155.995 0.070 156.065 ;
    RECT 0 156.135 0.070 156.205 ;
    RECT 0 156.275 0.070 156.345 ;
    RECT 0 156.415 0.070 156.485 ;
    RECT 0 156.555 0.070 156.625 ;
    RECT 0 156.695 0.070 156.765 ;
    RECT 0 156.835 0.070 156.905 ;
    RECT 0 156.975 0.070 157.045 ;
    RECT 0 157.115 0.070 157.185 ;
    RECT 0 157.255 0.070 157.325 ;
    RECT 0 157.395 0.070 157.465 ;
    RECT 0 157.535 0.070 157.605 ;
    RECT 0 157.675 0.070 157.745 ;
    RECT 0 157.815 0.070 157.885 ;
    RECT 0 157.955 0.070 158.025 ;
    RECT 0 158.095 0.070 158.165 ;
    RECT 0 158.235 0.070 158.305 ;
    RECT 0 158.375 0.070 158.445 ;
    RECT 0 158.515 0.070 158.585 ;
    RECT 0 158.655 0.070 158.725 ;
    RECT 0 158.795 0.070 158.865 ;
    RECT 0 158.935 0.070 159.005 ;
    RECT 0 159.075 0.070 159.145 ;
    RECT 0 159.215 0.070 159.285 ;
    RECT 0 159.355 0.070 159.425 ;
    RECT 0 159.495 0.070 159.565 ;
    RECT 0 159.635 0.070 159.705 ;
    RECT 0 159.775 0.070 159.845 ;
    RECT 0 159.915 0.070 159.985 ;
    RECT 0 160.055 0.070 160.125 ;
    RECT 0 160.195 0.070 160.265 ;
    RECT 0 160.335 0.070 160.405 ;
    RECT 0 160.475 0.070 160.545 ;
    RECT 0 160.615 0.070 160.685 ;
    RECT 0 160.755 0.070 160.825 ;
    RECT 0 160.895 0.070 160.965 ;
    RECT 0 161.035 0.070 161.105 ;
    RECT 0 161.175 0.070 161.245 ;
    RECT 0 161.315 0.070 161.385 ;
    RECT 0 161.455 0.070 161.525 ;
    RECT 0 161.595 0.070 161.665 ;
    RECT 0 161.735 0.070 161.805 ;
    RECT 0 161.875 0.070 161.945 ;
    RECT 0 162.015 0.070 162.085 ;
    RECT 0 162.155 0.070 162.225 ;
    RECT 0 162.295 0.070 162.365 ;
    RECT 0 162.435 0.070 162.505 ;
    RECT 0 162.575 0.070 162.645 ;
    RECT 0 162.715 0.070 162.785 ;
    RECT 0 162.855 0.070 162.925 ;
    RECT 0 162.995 0.070 163.065 ;
    RECT 0 163.135 0.070 163.205 ;
    RECT 0 163.275 0.070 163.345 ;
    RECT 0 163.415 0.070 163.485 ;
    RECT 0 163.555 0.070 163.625 ;
    RECT 0 163.695 0.070 163.765 ;
    RECT 0 163.835 0.070 163.905 ;
    RECT 0 163.975 0.070 164.045 ;
    RECT 0 164.115 0.070 164.185 ;
    RECT 0 164.255 0.070 164.325 ;
    RECT 0 164.395 0.070 164.465 ;
    RECT 0 164.535 0.070 164.605 ;
    RECT 0 164.675 0.070 164.745 ;
    RECT 0 164.815 0.070 164.885 ;
    RECT 0 164.955 0.070 165.025 ;
    RECT 0 165.095 0.070 165.165 ;
    RECT 0 165.235 0.070 165.305 ;
    RECT 0 165.375 0.070 165.445 ;
    RECT 0 165.515 0.070 165.585 ;
    RECT 0 165.655 0.070 165.725 ;
    RECT 0 165.795 0.070 165.865 ;
    RECT 0 165.935 0.070 166.005 ;
    RECT 0 166.075 0.070 166.145 ;
    RECT 0 166.215 0.070 166.285 ;
    RECT 0 166.355 0.070 166.425 ;
    RECT 0 166.495 0.070 166.565 ;
    RECT 0 166.635 0.070 166.705 ;
    RECT 0 166.775 0.070 166.845 ;
    RECT 0 166.915 0.070 166.985 ;
    RECT 0 167.055 0.070 167.125 ;
    RECT 0 167.195 0.070 167.265 ;
    RECT 0 167.335 0.070 167.405 ;
    RECT 0 167.475 0.070 167.545 ;
    RECT 0 167.615 0.070 167.685 ;
    RECT 0 167.755 0.070 167.825 ;
    RECT 0 167.895 0.070 167.965 ;
    RECT 0 168.035 0.070 168.105 ;
    RECT 0 168.175 0.070 168.245 ;
    RECT 0 168.315 0.070 168.385 ;
    RECT 0 168.455 0.070 168.525 ;
    RECT 0 168.595 0.070 168.665 ;
    RECT 0 168.735 0.070 168.805 ;
    RECT 0 168.875 0.070 168.945 ;
    RECT 0 169.015 0.070 169.085 ;
    RECT 0 169.155 0.070 169.225 ;
    RECT 0 169.295 0.070 169.365 ;
    RECT 0 169.435 0.070 169.505 ;
    RECT 0 169.575 0.070 169.645 ;
    RECT 0 169.715 0.070 169.785 ;
    RECT 0 169.855 0.070 169.925 ;
    RECT 0 169.995 0.070 170.065 ;
    RECT 0 170.135 0.070 170.205 ;
    RECT 0 170.275 0.070 170.345 ;
    RECT 0 170.415 0.070 170.485 ;
    RECT 0 170.555 0.070 170.625 ;
    RECT 0 170.695 0.070 170.765 ;
    RECT 0 170.835 0.070 170.905 ;
    RECT 0 170.975 0.070 171.045 ;
    RECT 0 171.115 0.070 171.185 ;
    RECT 0 171.255 0.070 171.325 ;
    RECT 0 171.395 0.070 171.465 ;
    RECT 0 171.535 0.070 171.605 ;
    RECT 0 171.675 0.070 171.745 ;
    RECT 0 171.815 0.070 171.885 ;
    RECT 0 171.955 0.070 172.025 ;
    RECT 0 172.095 0.070 172.165 ;
    RECT 0 172.235 0.070 172.305 ;
    RECT 0 172.375 0.070 172.445 ;
    RECT 0 172.515 0.070 172.585 ;
    RECT 0 172.655 0.070 172.725 ;
    RECT 0 172.795 0.070 172.865 ;
    RECT 0 172.935 0.070 201.285 ;
    RECT 0 201.355 0.070 201.425 ;
    RECT 0 201.495 0.070 201.565 ;
    RECT 0 201.635 0.070 201.705 ;
    RECT 0 201.775 0.070 201.845 ;
    RECT 0 201.915 0.070 201.985 ;
    RECT 0 202.055 0.070 202.125 ;
    RECT 0 202.195 0.070 202.265 ;
    RECT 0 202.335 0.070 202.405 ;
    RECT 0 202.475 0.070 202.545 ;
    RECT 0 202.615 0.070 202.685 ;
    RECT 0 202.755 0.070 202.825 ;
    RECT 0 202.895 0.070 202.965 ;
    RECT 0 203.035 0.070 203.105 ;
    RECT 0 203.175 0.070 203.245 ;
    RECT 0 203.315 0.070 203.385 ;
    RECT 0 203.455 0.070 203.525 ;
    RECT 0 203.595 0.070 203.665 ;
    RECT 0 203.735 0.070 203.805 ;
    RECT 0 203.875 0.070 203.945 ;
    RECT 0 204.015 0.070 204.085 ;
    RECT 0 204.155 0.070 204.225 ;
    RECT 0 204.295 0.070 204.365 ;
    RECT 0 204.435 0.070 204.505 ;
    RECT 0 204.575 0.070 204.645 ;
    RECT 0 204.715 0.070 204.785 ;
    RECT 0 204.855 0.070 204.925 ;
    RECT 0 204.995 0.070 205.065 ;
    RECT 0 205.135 0.070 205.205 ;
    RECT 0 205.275 0.070 205.345 ;
    RECT 0 205.415 0.070 205.485 ;
    RECT 0 205.555 0.070 205.625 ;
    RECT 0 205.695 0.070 205.765 ;
    RECT 0 205.835 0.070 205.905 ;
    RECT 0 205.975 0.070 206.045 ;
    RECT 0 206.115 0.070 206.185 ;
    RECT 0 206.255 0.070 206.325 ;
    RECT 0 206.395 0.070 206.465 ;
    RECT 0 206.535 0.070 206.605 ;
    RECT 0 206.675 0.070 206.745 ;
    RECT 0 206.815 0.070 206.885 ;
    RECT 0 206.955 0.070 207.025 ;
    RECT 0 207.095 0.070 207.165 ;
    RECT 0 207.235 0.070 207.305 ;
    RECT 0 207.375 0.070 207.445 ;
    RECT 0 207.515 0.070 207.585 ;
    RECT 0 207.655 0.070 207.725 ;
    RECT 0 207.795 0.070 207.865 ;
    RECT 0 207.935 0.070 208.005 ;
    RECT 0 208.075 0.070 208.145 ;
    RECT 0 208.215 0.070 208.285 ;
    RECT 0 208.355 0.070 208.425 ;
    RECT 0 208.495 0.070 208.565 ;
    RECT 0 208.635 0.070 208.705 ;
    RECT 0 208.775 0.070 208.845 ;
    RECT 0 208.915 0.070 208.985 ;
    RECT 0 209.055 0.070 209.125 ;
    RECT 0 209.195 0.070 209.265 ;
    RECT 0 209.335 0.070 209.405 ;
    RECT 0 209.475 0.070 209.545 ;
    RECT 0 209.615 0.070 209.685 ;
    RECT 0 209.755 0.070 209.825 ;
    RECT 0 209.895 0.070 209.965 ;
    RECT 0 210.035 0.070 210.105 ;
    RECT 0 210.175 0.070 210.245 ;
    RECT 0 210.315 0.070 210.385 ;
    RECT 0 210.455 0.070 210.525 ;
    RECT 0 210.595 0.070 210.665 ;
    RECT 0 210.735 0.070 210.805 ;
    RECT 0 210.875 0.070 210.945 ;
    RECT 0 211.015 0.070 211.085 ;
    RECT 0 211.155 0.070 211.225 ;
    RECT 0 211.295 0.070 211.365 ;
    RECT 0 211.435 0.070 211.505 ;
    RECT 0 211.575 0.070 211.645 ;
    RECT 0 211.715 0.070 211.785 ;
    RECT 0 211.855 0.070 211.925 ;
    RECT 0 211.995 0.070 212.065 ;
    RECT 0 212.135 0.070 212.205 ;
    RECT 0 212.275 0.070 212.345 ;
    RECT 0 212.415 0.070 212.485 ;
    RECT 0 212.555 0.070 212.625 ;
    RECT 0 212.695 0.070 212.765 ;
    RECT 0 212.835 0.070 212.905 ;
    RECT 0 212.975 0.070 213.045 ;
    RECT 0 213.115 0.070 213.185 ;
    RECT 0 213.255 0.070 213.325 ;
    RECT 0 213.395 0.070 213.465 ;
    RECT 0 213.535 0.070 213.605 ;
    RECT 0 213.675 0.070 213.745 ;
    RECT 0 213.815 0.070 213.885 ;
    RECT 0 213.955 0.070 214.025 ;
    RECT 0 214.095 0.070 214.165 ;
    RECT 0 214.235 0.070 214.305 ;
    RECT 0 214.375 0.070 214.445 ;
    RECT 0 214.515 0.070 214.585 ;
    RECT 0 214.655 0.070 214.725 ;
    RECT 0 214.795 0.070 214.865 ;
    RECT 0 214.935 0.070 215.005 ;
    RECT 0 215.075 0.070 215.145 ;
    RECT 0 215.215 0.070 215.285 ;
    RECT 0 215.355 0.070 215.425 ;
    RECT 0 215.495 0.070 215.565 ;
    RECT 0 215.635 0.070 215.705 ;
    RECT 0 215.775 0.070 215.845 ;
    RECT 0 215.915 0.070 215.985 ;
    RECT 0 216.055 0.070 216.125 ;
    RECT 0 216.195 0.070 216.265 ;
    RECT 0 216.335 0.070 216.405 ;
    RECT 0 216.475 0.070 216.545 ;
    RECT 0 216.615 0.070 216.685 ;
    RECT 0 216.755 0.070 216.825 ;
    RECT 0 216.895 0.070 216.965 ;
    RECT 0 217.035 0.070 217.105 ;
    RECT 0 217.175 0.070 217.245 ;
    RECT 0 217.315 0.070 217.385 ;
    RECT 0 217.455 0.070 217.525 ;
    RECT 0 217.595 0.070 217.665 ;
    RECT 0 217.735 0.070 217.805 ;
    RECT 0 217.875 0.070 217.945 ;
    RECT 0 218.015 0.070 218.085 ;
    RECT 0 218.155 0.070 218.225 ;
    RECT 0 218.295 0.070 218.365 ;
    RECT 0 218.435 0.070 218.505 ;
    RECT 0 218.575 0.070 218.645 ;
    RECT 0 218.715 0.070 218.785 ;
    RECT 0 218.855 0.070 218.925 ;
    RECT 0 218.995 0.070 219.065 ;
    RECT 0 219.135 0.070 219.205 ;
    RECT 0 219.275 0.070 219.345 ;
    RECT 0 219.415 0.070 219.485 ;
    RECT 0 219.555 0.070 219.625 ;
    RECT 0 219.695 0.070 219.765 ;
    RECT 0 219.835 0.070 219.905 ;
    RECT 0 219.975 0.070 220.045 ;
    RECT 0 220.115 0.070 220.185 ;
    RECT 0 220.255 0.070 220.325 ;
    RECT 0 220.395 0.070 220.465 ;
    RECT 0 220.535 0.070 220.605 ;
    RECT 0 220.675 0.070 220.745 ;
    RECT 0 220.815 0.070 220.885 ;
    RECT 0 220.955 0.070 221.025 ;
    RECT 0 221.095 0.070 221.165 ;
    RECT 0 221.235 0.070 221.305 ;
    RECT 0 221.375 0.070 221.445 ;
    RECT 0 221.515 0.070 221.585 ;
    RECT 0 221.655 0.070 221.725 ;
    RECT 0 221.795 0.070 221.865 ;
    RECT 0 221.935 0.070 222.005 ;
    RECT 0 222.075 0.070 222.145 ;
    RECT 0 222.215 0.070 222.285 ;
    RECT 0 222.355 0.070 222.425 ;
    RECT 0 222.495 0.070 222.565 ;
    RECT 0 222.635 0.070 222.705 ;
    RECT 0 222.775 0.070 222.845 ;
    RECT 0 222.915 0.070 222.985 ;
    RECT 0 223.055 0.070 223.125 ;
    RECT 0 223.195 0.070 223.265 ;
    RECT 0 223.335 0.070 223.405 ;
    RECT 0 223.475 0.070 223.545 ;
    RECT 0 223.615 0.070 223.685 ;
    RECT 0 223.755 0.070 223.825 ;
    RECT 0 223.895 0.070 223.965 ;
    RECT 0 224.035 0.070 224.105 ;
    RECT 0 224.175 0.070 224.245 ;
    RECT 0 224.315 0.070 224.385 ;
    RECT 0 224.455 0.070 224.525 ;
    RECT 0 224.595 0.070 224.665 ;
    RECT 0 224.735 0.070 224.805 ;
    RECT 0 224.875 0.070 224.945 ;
    RECT 0 225.015 0.070 225.085 ;
    RECT 0 225.155 0.070 225.225 ;
    RECT 0 225.295 0.070 225.365 ;
    RECT 0 225.435 0.070 225.505 ;
    RECT 0 225.575 0.070 225.645 ;
    RECT 0 225.715 0.070 225.785 ;
    RECT 0 225.855 0.070 225.925 ;
    RECT 0 225.995 0.070 226.065 ;
    RECT 0 226.135 0.070 226.205 ;
    RECT 0 226.275 0.070 226.345 ;
    RECT 0 226.415 0.070 226.485 ;
    RECT 0 226.555 0.070 226.625 ;
    RECT 0 226.695 0.070 226.765 ;
    RECT 0 226.835 0.070 226.905 ;
    RECT 0 226.975 0.070 227.045 ;
    RECT 0 227.115 0.070 227.185 ;
    RECT 0 227.255 0.070 227.325 ;
    RECT 0 227.395 0.070 227.465 ;
    RECT 0 227.535 0.070 227.605 ;
    RECT 0 227.675 0.070 227.745 ;
    RECT 0 227.815 0.070 227.885 ;
    RECT 0 227.955 0.070 228.025 ;
    RECT 0 228.095 0.070 228.165 ;
    RECT 0 228.235 0.070 228.305 ;
    RECT 0 228.375 0.070 228.445 ;
    RECT 0 228.515 0.070 228.585 ;
    RECT 0 228.655 0.070 228.725 ;
    RECT 0 228.795 0.070 228.865 ;
    RECT 0 228.935 0.070 229.005 ;
    RECT 0 229.075 0.070 229.145 ;
    RECT 0 229.215 0.070 229.285 ;
    RECT 0 229.355 0.070 229.425 ;
    RECT 0 229.495 0.070 229.565 ;
    RECT 0 229.635 0.070 229.705 ;
    RECT 0 229.775 0.070 229.845 ;
    RECT 0 229.915 0.070 229.985 ;
    RECT 0 230.055 0.070 230.125 ;
    RECT 0 230.195 0.070 230.265 ;
    RECT 0 230.335 0.070 230.405 ;
    RECT 0 230.475 0.070 230.545 ;
    RECT 0 230.615 0.070 230.685 ;
    RECT 0 230.755 0.070 230.825 ;
    RECT 0 230.895 0.070 230.965 ;
    RECT 0 231.035 0.070 231.105 ;
    RECT 0 231.175 0.070 231.245 ;
    RECT 0 231.315 0.070 231.385 ;
    RECT 0 231.455 0.070 231.525 ;
    RECT 0 231.595 0.070 231.665 ;
    RECT 0 231.735 0.070 231.805 ;
    RECT 0 231.875 0.070 231.945 ;
    RECT 0 232.015 0.070 232.085 ;
    RECT 0 232.155 0.070 232.225 ;
    RECT 0 232.295 0.070 232.365 ;
    RECT 0 232.435 0.070 232.505 ;
    RECT 0 232.575 0.070 232.645 ;
    RECT 0 232.715 0.070 232.785 ;
    RECT 0 232.855 0.070 232.925 ;
    RECT 0 232.995 0.070 233.065 ;
    RECT 0 233.135 0.070 233.205 ;
    RECT 0 233.275 0.070 233.345 ;
    RECT 0 233.415 0.070 233.485 ;
    RECT 0 233.555 0.070 233.625 ;
    RECT 0 233.695 0.070 233.765 ;
    RECT 0 233.835 0.070 233.905 ;
    RECT 0 233.975 0.070 234.045 ;
    RECT 0 234.115 0.070 234.185 ;
    RECT 0 234.255 0.070 234.325 ;
    RECT 0 234.395 0.070 234.465 ;
    RECT 0 234.535 0.070 234.605 ;
    RECT 0 234.675 0.070 234.745 ;
    RECT 0 234.815 0.070 234.885 ;
    RECT 0 234.955 0.070 235.025 ;
    RECT 0 235.095 0.070 235.165 ;
    RECT 0 235.235 0.070 235.305 ;
    RECT 0 235.375 0.070 235.445 ;
    RECT 0 235.515 0.070 235.585 ;
    RECT 0 235.655 0.070 235.725 ;
    RECT 0 235.795 0.070 235.865 ;
    RECT 0 235.935 0.070 236.005 ;
    RECT 0 236.075 0.070 236.145 ;
    RECT 0 236.215 0.070 236.285 ;
    RECT 0 236.355 0.070 236.425 ;
    RECT 0 236.495 0.070 236.565 ;
    RECT 0 236.635 0.070 236.705 ;
    RECT 0 236.775 0.070 236.845 ;
    RECT 0 236.915 0.070 236.985 ;
    RECT 0 237.055 0.070 237.125 ;
    RECT 0 237.195 0.070 237.265 ;
    RECT 0 237.335 0.070 237.405 ;
    RECT 0 237.475 0.070 237.545 ;
    RECT 0 237.615 0.070 237.685 ;
    RECT 0 237.755 0.070 237.825 ;
    RECT 0 237.895 0.070 237.965 ;
    RECT 0 238.035 0.070 238.105 ;
    RECT 0 238.175 0.070 238.245 ;
    RECT 0 238.315 0.070 238.385 ;
    RECT 0 238.455 0.070 238.525 ;
    RECT 0 238.595 0.070 238.665 ;
    RECT 0 238.735 0.070 238.805 ;
    RECT 0 238.875 0.070 238.945 ;
    RECT 0 239.015 0.070 239.085 ;
    RECT 0 239.155 0.070 239.225 ;
    RECT 0 239.295 0.070 239.365 ;
    RECT 0 239.435 0.070 239.505 ;
    RECT 0 239.575 0.070 239.645 ;
    RECT 0 239.715 0.070 239.785 ;
    RECT 0 239.855 0.070 239.925 ;
    RECT 0 239.995 0.070 240.065 ;
    RECT 0 240.135 0.070 240.205 ;
    RECT 0 240.275 0.070 240.345 ;
    RECT 0 240.415 0.070 240.485 ;
    RECT 0 240.555 0.070 240.625 ;
    RECT 0 240.695 0.070 240.765 ;
    RECT 0 240.835 0.070 240.905 ;
    RECT 0 240.975 0.070 241.045 ;
    RECT 0 241.115 0.070 241.185 ;
    RECT 0 241.255 0.070 241.325 ;
    RECT 0 241.395 0.070 241.465 ;
    RECT 0 241.535 0.070 241.605 ;
    RECT 0 241.675 0.070 241.745 ;
    RECT 0 241.815 0.070 241.885 ;
    RECT 0 241.955 0.070 242.025 ;
    RECT 0 242.095 0.070 242.165 ;
    RECT 0 242.235 0.070 242.305 ;
    RECT 0 242.375 0.070 242.445 ;
    RECT 0 242.515 0.070 242.585 ;
    RECT 0 242.655 0.070 242.725 ;
    RECT 0 242.795 0.070 242.865 ;
    RECT 0 242.935 0.070 243.005 ;
    RECT 0 243.075 0.070 243.145 ;
    RECT 0 243.215 0.070 243.285 ;
    RECT 0 243.355 0.070 243.425 ;
    RECT 0 243.495 0.070 243.565 ;
    RECT 0 243.635 0.070 243.705 ;
    RECT 0 243.775 0.070 243.845 ;
    RECT 0 243.915 0.070 243.985 ;
    RECT 0 244.055 0.070 244.125 ;
    RECT 0 244.195 0.070 244.265 ;
    RECT 0 244.335 0.070 244.405 ;
    RECT 0 244.475 0.070 244.545 ;
    RECT 0 244.615 0.070 244.685 ;
    RECT 0 244.755 0.070 244.825 ;
    RECT 0 244.895 0.070 244.965 ;
    RECT 0 245.035 0.070 245.105 ;
    RECT 0 245.175 0.070 245.245 ;
    RECT 0 245.315 0.070 245.385 ;
    RECT 0 245.455 0.070 245.525 ;
    RECT 0 245.595 0.070 245.665 ;
    RECT 0 245.735 0.070 245.805 ;
    RECT 0 245.875 0.070 245.945 ;
    RECT 0 246.015 0.070 246.085 ;
    RECT 0 246.155 0.070 246.225 ;
    RECT 0 246.295 0.070 246.365 ;
    RECT 0 246.435 0.070 246.505 ;
    RECT 0 246.575 0.070 246.645 ;
    RECT 0 246.715 0.070 246.785 ;
    RECT 0 246.855 0.070 246.925 ;
    RECT 0 246.995 0.070 247.065 ;
    RECT 0 247.135 0.070 247.205 ;
    RECT 0 247.275 0.070 247.345 ;
    RECT 0 247.415 0.070 247.485 ;
    RECT 0 247.555 0.070 247.625 ;
    RECT 0 247.695 0.070 247.765 ;
    RECT 0 247.835 0.070 247.905 ;
    RECT 0 247.975 0.070 248.045 ;
    RECT 0 248.115 0.070 248.185 ;
    RECT 0 248.255 0.070 248.325 ;
    RECT 0 248.395 0.070 248.465 ;
    RECT 0 248.535 0.070 248.605 ;
    RECT 0 248.675 0.070 248.745 ;
    RECT 0 248.815 0.070 248.885 ;
    RECT 0 248.955 0.070 249.025 ;
    RECT 0 249.095 0.070 249.165 ;
    RECT 0 249.235 0.070 249.305 ;
    RECT 0 249.375 0.070 249.445 ;
    RECT 0 249.515 0.070 249.585 ;
    RECT 0 249.655 0.070 249.725 ;
    RECT 0 249.795 0.070 249.865 ;
    RECT 0 249.935 0.070 250.005 ;
    RECT 0 250.075 0.070 250.145 ;
    RECT 0 250.215 0.070 250.285 ;
    RECT 0 250.355 0.070 250.425 ;
    RECT 0 250.495 0.070 250.565 ;
    RECT 0 250.635 0.070 250.705 ;
    RECT 0 250.775 0.070 250.845 ;
    RECT 0 250.915 0.070 250.985 ;
    RECT 0 251.055 0.070 251.125 ;
    RECT 0 251.195 0.070 251.265 ;
    RECT 0 251.335 0.070 251.405 ;
    RECT 0 251.475 0.070 251.545 ;
    RECT 0 251.615 0.070 251.685 ;
    RECT 0 251.755 0.070 251.825 ;
    RECT 0 251.895 0.070 251.965 ;
    RECT 0 252.035 0.070 252.105 ;
    RECT 0 252.175 0.070 252.245 ;
    RECT 0 252.315 0.070 252.385 ;
    RECT 0 252.455 0.070 252.525 ;
    RECT 0 252.595 0.070 252.665 ;
    RECT 0 252.735 0.070 252.805 ;
    RECT 0 252.875 0.070 252.945 ;
    RECT 0 253.015 0.070 253.085 ;
    RECT 0 253.155 0.070 253.225 ;
    RECT 0 253.295 0.070 253.365 ;
    RECT 0 253.435 0.070 253.505 ;
    RECT 0 253.575 0.070 253.645 ;
    RECT 0 253.715 0.070 253.785 ;
    RECT 0 253.855 0.070 253.925 ;
    RECT 0 253.995 0.070 254.065 ;
    RECT 0 254.135 0.070 254.205 ;
    RECT 0 254.275 0.070 254.345 ;
    RECT 0 254.415 0.070 254.485 ;
    RECT 0 254.555 0.070 254.625 ;
    RECT 0 254.695 0.070 254.765 ;
    RECT 0 254.835 0.070 254.905 ;
    RECT 0 254.975 0.070 255.045 ;
    RECT 0 255.115 0.070 255.185 ;
    RECT 0 255.255 0.070 255.325 ;
    RECT 0 255.395 0.070 255.465 ;
    RECT 0 255.535 0.070 255.605 ;
    RECT 0 255.675 0.070 255.745 ;
    RECT 0 255.815 0.070 255.885 ;
    RECT 0 255.955 0.070 256.025 ;
    RECT 0 256.095 0.070 256.165 ;
    RECT 0 256.235 0.070 256.305 ;
    RECT 0 256.375 0.070 256.445 ;
    RECT 0 256.515 0.070 256.585 ;
    RECT 0 256.655 0.070 256.725 ;
    RECT 0 256.795 0.070 256.865 ;
    RECT 0 256.935 0.070 257.005 ;
    RECT 0 257.075 0.070 257.145 ;
    RECT 0 257.215 0.070 257.285 ;
    RECT 0 257.355 0.070 257.425 ;
    RECT 0 257.495 0.070 257.565 ;
    RECT 0 257.635 0.070 257.705 ;
    RECT 0 257.775 0.070 257.845 ;
    RECT 0 257.915 0.070 257.985 ;
    RECT 0 258.055 0.070 258.125 ;
    RECT 0 258.195 0.070 258.265 ;
    RECT 0 258.335 0.070 258.405 ;
    RECT 0 258.475 0.070 258.545 ;
    RECT 0 258.615 0.070 258.685 ;
    RECT 0 258.755 0.070 258.825 ;
    RECT 0 258.895 0.070 258.965 ;
    RECT 0 259.035 0.070 259.105 ;
    RECT 0 259.175 0.070 259.245 ;
    RECT 0 259.315 0.070 259.385 ;
    RECT 0 259.455 0.070 259.525 ;
    RECT 0 259.595 0.070 259.665 ;
    RECT 0 259.735 0.070 259.805 ;
    RECT 0 259.875 0.070 259.945 ;
    RECT 0 260.015 0.070 260.085 ;
    RECT 0 260.155 0.070 260.225 ;
    RECT 0 260.295 0.070 260.365 ;
    RECT 0 260.435 0.070 260.505 ;
    RECT 0 260.575 0.070 260.645 ;
    RECT 0 260.715 0.070 260.785 ;
    RECT 0 260.855 0.070 260.925 ;
    RECT 0 260.995 0.070 261.065 ;
    RECT 0 261.135 0.070 261.205 ;
    RECT 0 261.275 0.070 261.345 ;
    RECT 0 261.415 0.070 261.485 ;
    RECT 0 261.555 0.070 261.625 ;
    RECT 0 261.695 0.070 261.765 ;
    RECT 0 261.835 0.070 261.905 ;
    RECT 0 261.975 0.070 262.045 ;
    RECT 0 262.115 0.070 262.185 ;
    RECT 0 262.255 0.070 262.325 ;
    RECT 0 262.395 0.070 262.465 ;
    RECT 0 262.535 0.070 262.605 ;
    RECT 0 262.675 0.070 262.745 ;
    RECT 0 262.815 0.070 262.885 ;
    RECT 0 262.955 0.070 263.025 ;
    RECT 0 263.095 0.070 263.165 ;
    RECT 0 263.235 0.070 263.305 ;
    RECT 0 263.375 0.070 263.445 ;
    RECT 0 263.515 0.070 263.585 ;
    RECT 0 263.655 0.070 263.725 ;
    RECT 0 263.795 0.070 263.865 ;
    RECT 0 263.935 0.070 264.005 ;
    RECT 0 264.075 0.070 264.145 ;
    RECT 0 264.215 0.070 264.285 ;
    RECT 0 264.355 0.070 264.425 ;
    RECT 0 264.495 0.070 264.565 ;
    RECT 0 264.635 0.070 264.705 ;
    RECT 0 264.775 0.070 264.845 ;
    RECT 0 264.915 0.070 264.985 ;
    RECT 0 265.055 0.070 265.125 ;
    RECT 0 265.195 0.070 265.265 ;
    RECT 0 265.335 0.070 265.405 ;
    RECT 0 265.475 0.070 265.545 ;
    RECT 0 265.615 0.070 265.685 ;
    RECT 0 265.755 0.070 265.825 ;
    RECT 0 265.895 0.070 265.965 ;
    RECT 0 266.035 0.070 266.105 ;
    RECT 0 266.175 0.070 266.245 ;
    RECT 0 266.315 0.070 266.385 ;
    RECT 0 266.455 0.070 266.525 ;
    RECT 0 266.595 0.070 266.665 ;
    RECT 0 266.735 0.070 266.805 ;
    RECT 0 266.875 0.070 266.945 ;
    RECT 0 267.015 0.070 267.085 ;
    RECT 0 267.155 0.070 267.225 ;
    RECT 0 267.295 0.070 267.365 ;
    RECT 0 267.435 0.070 267.505 ;
    RECT 0 267.575 0.070 267.645 ;
    RECT 0 267.715 0.070 267.785 ;
    RECT 0 267.855 0.070 267.925 ;
    RECT 0 267.995 0.070 268.065 ;
    RECT 0 268.135 0.070 268.205 ;
    RECT 0 268.275 0.070 268.345 ;
    RECT 0 268.415 0.070 268.485 ;
    RECT 0 268.555 0.070 268.625 ;
    RECT 0 268.695 0.070 268.765 ;
    RECT 0 268.835 0.070 268.905 ;
    RECT 0 268.975 0.070 269.045 ;
    RECT 0 269.115 0.070 269.185 ;
    RECT 0 269.255 0.070 269.325 ;
    RECT 0 269.395 0.070 269.465 ;
    RECT 0 269.535 0.070 269.605 ;
    RECT 0 269.675 0.070 269.745 ;
    RECT 0 269.815 0.070 269.885 ;
    RECT 0 269.955 0.070 270.025 ;
    RECT 0 270.095 0.070 270.165 ;
    RECT 0 270.235 0.070 270.305 ;
    RECT 0 270.375 0.070 270.445 ;
    RECT 0 270.515 0.070 270.585 ;
    RECT 0 270.655 0.070 270.725 ;
    RECT 0 270.795 0.070 270.865 ;
    RECT 0 270.935 0.070 271.005 ;
    RECT 0 271.075 0.070 271.145 ;
    RECT 0 271.215 0.070 271.285 ;
    RECT 0 271.355 0.070 271.425 ;
    RECT 0 271.495 0.070 271.565 ;
    RECT 0 271.635 0.070 271.705 ;
    RECT 0 271.775 0.070 271.845 ;
    RECT 0 271.915 0.070 271.985 ;
    RECT 0 272.055 0.070 272.125 ;
    RECT 0 272.195 0.070 272.265 ;
    RECT 0 272.335 0.070 272.405 ;
    RECT 0 272.475 0.070 272.545 ;
    RECT 0 272.615 0.070 272.685 ;
    RECT 0 272.755 0.070 272.825 ;
    RECT 0 272.895 0.070 301.245 ;
    RECT 0 301.315 0.070 301.385 ;
    RECT 0 301.455 0.070 301.525 ;
    RECT 0 301.595 0.070 301.665 ;
    RECT 0 301.735 0.070 301.805 ;
    RECT 0 301.875 0.070 301.945 ;
    RECT 0 302.015 0.070 330.365 ;
    RECT 0 330.435 0.070 330.505 ;
    RECT 0 330.575 0.070 330.645 ;
    RECT 0 330.715 0.070 333.200 ;
    LAYER metal4 ;
    RECT 0 0 165.870 1.400 ;
    RECT 0 331.800 165.870 333.200 ;
    RECT 0.000 1.400 1.260 331.800 ;
    RECT 1.540 1.400 2.380 331.800 ;
    RECT 2.660 1.400 3.500 331.800 ;
    RECT 3.780 1.400 4.620 331.800 ;
    RECT 4.900 1.400 5.740 331.800 ;
    RECT 6.020 1.400 6.860 331.800 ;
    RECT 7.140 1.400 7.980 331.800 ;
    RECT 8.260 1.400 9.100 331.800 ;
    RECT 9.380 1.400 10.220 331.800 ;
    RECT 10.500 1.400 11.340 331.800 ;
    RECT 11.620 1.400 12.460 331.800 ;
    RECT 12.740 1.400 13.580 331.800 ;
    RECT 13.860 1.400 14.700 331.800 ;
    RECT 14.980 1.400 15.820 331.800 ;
    RECT 16.100 1.400 16.940 331.800 ;
    RECT 17.220 1.400 18.060 331.800 ;
    RECT 18.340 1.400 19.180 331.800 ;
    RECT 19.460 1.400 20.300 331.800 ;
    RECT 20.580 1.400 21.420 331.800 ;
    RECT 21.700 1.400 22.540 331.800 ;
    RECT 22.820 1.400 23.660 331.800 ;
    RECT 23.940 1.400 24.780 331.800 ;
    RECT 25.060 1.400 25.900 331.800 ;
    RECT 26.180 1.400 27.020 331.800 ;
    RECT 27.300 1.400 28.140 331.800 ;
    RECT 28.420 1.400 29.260 331.800 ;
    RECT 29.540 1.400 30.380 331.800 ;
    RECT 30.660 1.400 31.500 331.800 ;
    RECT 31.780 1.400 32.620 331.800 ;
    RECT 32.900 1.400 33.740 331.800 ;
    RECT 34.020 1.400 34.860 331.800 ;
    RECT 35.140 1.400 35.980 331.800 ;
    RECT 36.260 1.400 37.100 331.800 ;
    RECT 37.380 1.400 38.220 331.800 ;
    RECT 38.500 1.400 39.340 331.800 ;
    RECT 39.620 1.400 40.460 331.800 ;
    RECT 40.740 1.400 41.580 331.800 ;
    RECT 41.860 1.400 42.700 331.800 ;
    RECT 42.980 1.400 43.820 331.800 ;
    RECT 44.100 1.400 44.940 331.800 ;
    RECT 45.220 1.400 46.060 331.800 ;
    RECT 46.340 1.400 47.180 331.800 ;
    RECT 47.460 1.400 48.300 331.800 ;
    RECT 48.580 1.400 49.420 331.800 ;
    RECT 49.700 1.400 50.540 331.800 ;
    RECT 50.820 1.400 51.660 331.800 ;
    RECT 51.940 1.400 52.780 331.800 ;
    RECT 53.060 1.400 53.900 331.800 ;
    RECT 54.180 1.400 55.020 331.800 ;
    RECT 55.300 1.400 56.140 331.800 ;
    RECT 56.420 1.400 57.260 331.800 ;
    RECT 57.540 1.400 58.380 331.800 ;
    RECT 58.660 1.400 59.500 331.800 ;
    RECT 59.780 1.400 60.620 331.800 ;
    RECT 60.900 1.400 61.740 331.800 ;
    RECT 62.020 1.400 62.860 331.800 ;
    RECT 63.140 1.400 63.980 331.800 ;
    RECT 64.260 1.400 65.100 331.800 ;
    RECT 65.380 1.400 66.220 331.800 ;
    RECT 66.500 1.400 67.340 331.800 ;
    RECT 67.620 1.400 68.460 331.800 ;
    RECT 68.740 1.400 69.580 331.800 ;
    RECT 69.860 1.400 70.700 331.800 ;
    RECT 70.980 1.400 71.820 331.800 ;
    RECT 72.100 1.400 72.940 331.800 ;
    RECT 73.220 1.400 74.060 331.800 ;
    RECT 74.340 1.400 75.180 331.800 ;
    RECT 75.460 1.400 76.300 331.800 ;
    RECT 76.580 1.400 77.420 331.800 ;
    RECT 77.700 1.400 78.540 331.800 ;
    RECT 78.820 1.400 79.660 331.800 ;
    RECT 79.940 1.400 80.780 331.800 ;
    RECT 81.060 1.400 81.900 331.800 ;
    RECT 82.180 1.400 83.020 331.800 ;
    RECT 83.300 1.400 84.140 331.800 ;
    RECT 84.420 1.400 85.260 331.800 ;
    RECT 85.540 1.400 86.380 331.800 ;
    RECT 86.660 1.400 87.500 331.800 ;
    RECT 87.780 1.400 88.620 331.800 ;
    RECT 88.900 1.400 89.740 331.800 ;
    RECT 90.020 1.400 90.860 331.800 ;
    RECT 91.140 1.400 91.980 331.800 ;
    RECT 92.260 1.400 93.100 331.800 ;
    RECT 93.380 1.400 94.220 331.800 ;
    RECT 94.500 1.400 95.340 331.800 ;
    RECT 95.620 1.400 96.460 331.800 ;
    RECT 96.740 1.400 97.580 331.800 ;
    RECT 97.860 1.400 98.700 331.800 ;
    RECT 98.980 1.400 99.820 331.800 ;
    RECT 100.100 1.400 100.940 331.800 ;
    RECT 101.220 1.400 102.060 331.800 ;
    RECT 102.340 1.400 103.180 331.800 ;
    RECT 103.460 1.400 104.300 331.800 ;
    RECT 104.580 1.400 105.420 331.800 ;
    RECT 105.700 1.400 106.540 331.800 ;
    RECT 106.820 1.400 107.660 331.800 ;
    RECT 107.940 1.400 108.780 331.800 ;
    RECT 109.060 1.400 109.900 331.800 ;
    RECT 110.180 1.400 111.020 331.800 ;
    RECT 111.300 1.400 112.140 331.800 ;
    RECT 112.420 1.400 113.260 331.800 ;
    RECT 113.540 1.400 114.380 331.800 ;
    RECT 114.660 1.400 115.500 331.800 ;
    RECT 115.780 1.400 116.620 331.800 ;
    RECT 116.900 1.400 117.740 331.800 ;
    RECT 118.020 1.400 118.860 331.800 ;
    RECT 119.140 1.400 119.980 331.800 ;
    RECT 120.260 1.400 121.100 331.800 ;
    RECT 121.380 1.400 122.220 331.800 ;
    RECT 122.500 1.400 123.340 331.800 ;
    RECT 123.620 1.400 124.460 331.800 ;
    RECT 124.740 1.400 125.580 331.800 ;
    RECT 125.860 1.400 126.700 331.800 ;
    RECT 126.980 1.400 127.820 331.800 ;
    RECT 128.100 1.400 128.940 331.800 ;
    RECT 129.220 1.400 130.060 331.800 ;
    RECT 130.340 1.400 131.180 331.800 ;
    RECT 131.460 1.400 132.300 331.800 ;
    RECT 132.580 1.400 133.420 331.800 ;
    RECT 133.700 1.400 134.540 331.800 ;
    RECT 134.820 1.400 135.660 331.800 ;
    RECT 135.940 1.400 136.780 331.800 ;
    RECT 137.060 1.400 137.900 331.800 ;
    RECT 138.180 1.400 139.020 331.800 ;
    RECT 139.300 1.400 140.140 331.800 ;
    RECT 140.420 1.400 141.260 331.800 ;
    RECT 141.540 1.400 142.380 331.800 ;
    RECT 142.660 1.400 143.500 331.800 ;
    RECT 143.780 1.400 144.620 331.800 ;
    RECT 144.900 1.400 145.740 331.800 ;
    RECT 146.020 1.400 146.860 331.800 ;
    RECT 147.140 1.400 147.980 331.800 ;
    RECT 148.260 1.400 149.100 331.800 ;
    RECT 149.380 1.400 150.220 331.800 ;
    RECT 150.500 1.400 151.340 331.800 ;
    RECT 151.620 1.400 152.460 331.800 ;
    RECT 152.740 1.400 153.580 331.800 ;
    RECT 153.860 1.400 154.700 331.800 ;
    RECT 154.980 1.400 155.820 331.800 ;
    RECT 156.100 1.400 156.940 331.800 ;
    RECT 157.220 1.400 158.060 331.800 ;
    RECT 158.340 1.400 159.180 331.800 ;
    RECT 159.460 1.400 160.300 331.800 ;
    RECT 160.580 1.400 161.420 331.800 ;
    RECT 161.700 1.400 162.540 331.800 ;
    RECT 162.820 1.400 163.660 331.800 ;
    RECT 163.940 1.400 165.870 331.800 ;
    LAYER OVERLAP ;
    RECT 0 0 165.870 333.200 ;
  END
END sram_64x512_1rw

END LIBRARY
